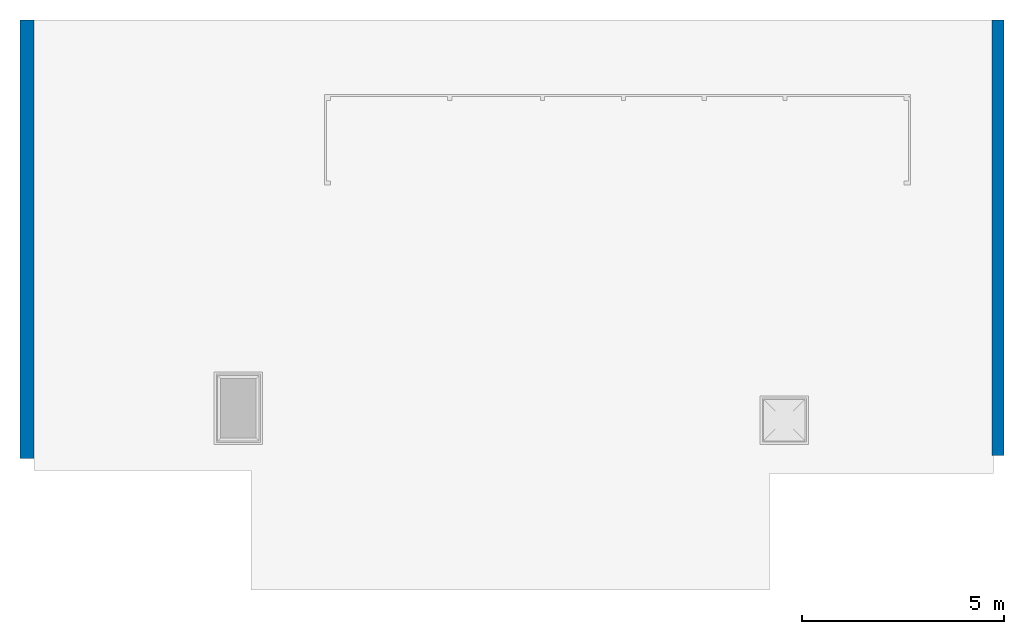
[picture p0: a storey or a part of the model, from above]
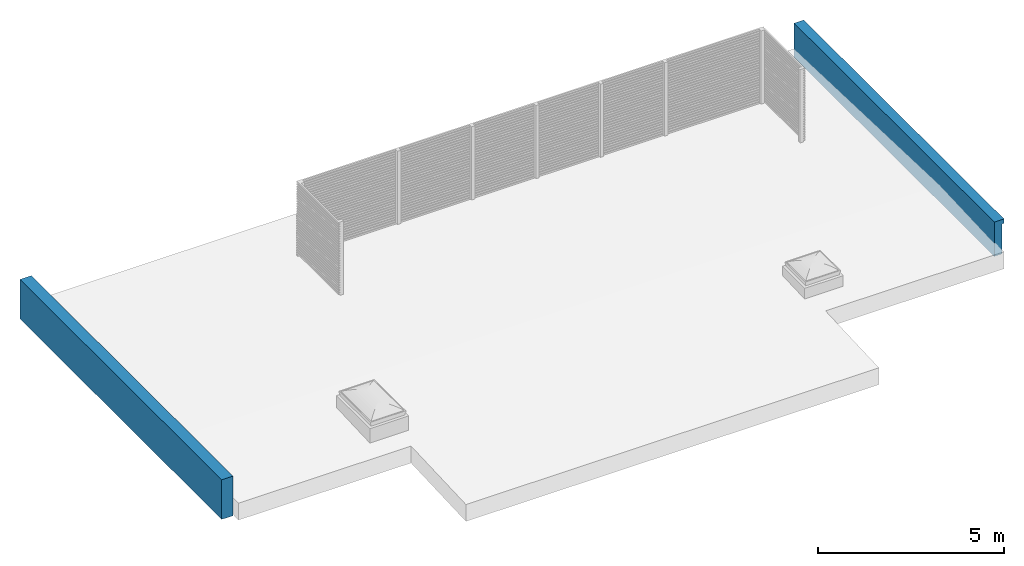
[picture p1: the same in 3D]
Properties of the parts of a building model (IFC2X3), part 1 of 7

# File
Description: ViewDefinition [CoordinationView_V2.0]
File name: 19043
Time: 2021-08-16T15:12:21
Written by: The EXPRESS Data Manager Version 5.02.0100.07 : 28 Aug 2013
Made in: 20190808_0900(x64) - Exporter 19.3.0.0 - Alternate UI 19.3.0.0
Comment: STEP Physical File produced by: The EXPRESS Data Manager Version 5.02.0100.07 : 28 Aug 2013 * Module: EDMstepFileFactory/EDMstandAlone * Creation date: Mon Aug 16 15:12:21 2021 * Host: SA-2 * Database: C:\Users\Kasutaja\AppData\Local\Temp\{7F7ABF4B-EC79-415C-8A1B-BE8ADDE48ED6}\ifc * Database version: 5507 * Database creation date: Mon Aug 16 15:08:34 2021 * Schema: IFC2X3 * Model: DataRepository.ifc * Model creation date: Mon Aug 16 15:08:34 2021 * Header model: DataRepository.ifc_HeaderModel * Header model creation date: Mon Aug 16 15:08:34 2021 * EDMuser: sdai-user * EDMgroup: sdai-group * License ID and type: 5605 : Permanent license. Expiry date: * EDMstepFileFactory options: 020000

# IfcProject, 19043
LongName: Jõe tn 8 ühiselamu rekonstrueerimine; Phase: PP

# IfcSite, Default
RefLatitude: 58, 5, 40, 850830; RefLongitude: 27, 26, 59, 528961; RefElevation: 0 mm
Pset_ProductRequirements - Category: Project Information

# IfcBuilding, SMA ARH
LongName: SMA ARH
Pset_BuildingCommon - NumberOfStoreys: 9
Pset_ProductRequirements - Category: Project Information

# IfcBuildingStorey: Level:Level head 1 (9)
In: SMA ARH
Pset_ProductRequirements - Category: Levels
Name | LongName = Pset_AirSideSystemInformation, Name = Pset_ProductRequirements, Name | Elevation (mm)
0 Kelder | 0 Kelder | -1400
1 Korrus | 1 Korrus | 0
1 Korrus A | 1 Korrus A | 1400
2 Korrus | 2 Korrus | 2800
2 Korrus A | 2 Korrus A | 4200
3 korrus | 3 korrus | 5600
3 Korrus A | 3 Korrus A | 7000
Katus | Katus | 8100
Katus A | Katus A | 9700

# IfcSpace: Dušširuum 008:1007028, 008
In: 0 Kelder
LongName: Dušširuum; InteriorOrExteriorSpace: INTERNAL
Pset_AirSideSystemInformation - Name: Dušširuum; sets with these values: 2
Pset_SpaceCommon - Reference: Dušširuum 008; FloorCovering: P3/P4; WallCovering: S3.1/S3.2; CeilingCovering: L5

# IfcSpace: Dušširuum 101E:976458, 101E
In: 1 Korrus
LongName: Dušširuum; InteriorOrExteriorSpace: INTERNAL
Pset_AirSideSystemInformation - Name: Dušširuum; sets with these values: 2
Pset_SpaceCommon - Reference: Dušširuum 101E; FloorCovering: P4; WallCovering: S4.1/S4.2; CeilingCovering: L2

# IfcSpace: Dušširuum 102D:975544, 102D
In: 1 Korrus A
LongName: Dušširuum; InteriorOrExteriorSpace: INTERNAL
Pset_AirSideSystemInformation - Name: Dušširuum; sets with these values: 2
Pset_SpaceCommon - Reference: Dušširuum 102D; FloorCovering: P3/P4; WallCovering: S3.1/S3.2; CeilingCovering: L2

# IfcSpace: Dušširuum 103C:975547, 103C
In: 1 Korrus A
LongName: Dušširuum; InteriorOrExteriorSpace: INTERNAL
Pset_AirSideSystemInformation - Name: Dušširuum; sets with these values: 2
Pset_SpaceCommon - Reference: Dušširuum 103C; FloorCovering: P3/P4; WallCovering: S3.1/S3.2; CeilingCovering: L2

# IfcSpace: Dušširuum 104D:975531, 104D
In: 1 Korrus A
LongName: Dušširuum; InteriorOrExteriorSpace: INTERNAL
Pset_AirSideSystemInformation - Name: Dušširuum; sets with these values: 2
Pset_SpaceCommon - Reference: Dušširuum 104D; FloorCovering: P3/P4; WallCovering: S3.1/S3.2; CeilingCovering: L2

# IfcSpace: Dušširuum 105C:975528, 105C
In: 1 Korrus A
LongName: Dušširuum; InteriorOrExteriorSpace: INTERNAL
Pset_AirSideSystemInformation - Name: Dušširuum; sets with these values: 2
Pset_SpaceCommon - Reference: Dušširuum 105C; FloorCovering: P3/P4; WallCovering: S3.1/S3.2; CeilingCovering: L2

# IfcSpace: Dušširuum 106D:976437, 106D
In: 1 Korrus A
LongName: Dušširuum; InteriorOrExteriorSpace: INTERNAL
Pset_AirSideSystemInformation - Name: Dušširuum; sets with these values: 2
Pset_SpaceCommon - Reference: Dušširuum 106D; FloorCovering: P3/P4; WallCovering: S3.1/S3.2; CeilingCovering: L2

# IfcSpace: Dušširuum 108G:990469, 108G
In: 1 Korrus
LongName: Dušširuum; InteriorOrExteriorSpace: INTERNAL
Pset_AirSideSystemInformation - Name: Dušširuum; sets with these values: 2
Pset_SpaceCommon - Reference: Dušširuum 108G; FloorCovering: P3; WallCovering: S3.1/S3.2; CeilingCovering: L2

# IfcSpace: Dušširuum 201F:984375, 201F
In: 2 Korrus
LongName: Dušširuum; InteriorOrExteriorSpace: INTERNAL
Pset_AirSideSystemInformation - Name: Dušširuum; sets with these values: 2
Pset_SpaceCommon - Reference: Dušširuum 201F; FloorCovering: P3; WallCovering: S3.1/S3.2; CeilingCovering: L2

# IfcSpace: Dušširuum 202D:977817, 202D
In: 2 Korrus A
LongName: Dušširuum; InteriorOrExteriorSpace: INTERNAL
Pset_AirSideSystemInformation - Name: Dušširuum; sets with these values: 2
Pset_SpaceCommon - Reference: Dušširuum 202D; FloorCovering: P3/P4; WallCovering: S3.1/S3.2; CeilingCovering: L2

# IfcSpace: Dušširuum 203C:977799, 203C
In: 2 Korrus A
LongName: Dušširuum; InteriorOrExteriorSpace: INTERNAL
Pset_AirSideSystemInformation - Name: Dušširuum; sets with these values: 2
Pset_SpaceCommon - Reference: Dušširuum 203C; FloorCovering: P3/P4; WallCovering: S3.1/S3.2; CeilingCovering: L2

# IfcSpace: Dušširuum 204D:977787, 204D
In: 2 Korrus A
LongName: Dušširuum; InteriorOrExteriorSpace: INTERNAL
Pset_AirSideSystemInformation - Name: Dušširuum; sets with these values: 2
Pset_SpaceCommon - Reference: Dušširuum 204D; FloorCovering: P3/P4; WallCovering: S3.1/S3.2; CeilingCovering: L2

# IfcSpace: Dušširuum 205C:977769, 205C
In: 2 Korrus A
LongName: Dušširuum; InteriorOrExteriorSpace: INTERNAL
Pset_AirSideSystemInformation - Name: Dušširuum; sets with these values: 2
Pset_SpaceCommon - Reference: Dušširuum 205C; FloorCovering: P3/P4; WallCovering: S3.1/S3.2; CeilingCovering: L2

# IfcSpace: Dušširuum 206D:977850, 206D
In: 2 Korrus A
LongName: Dušširuum; InteriorOrExteriorSpace: INTERNAL
Pset_AirSideSystemInformation - Name: Dušširuum; sets with these values: 2
Pset_SpaceCommon - Reference: Dušširuum 206D; FloorCovering: P3/P4; WallCovering: S3.1/S3.2; CeilingCovering: L2

# IfcSpace: Dušširuum 208E:977689, 208E
In: 2 Korrus
LongName: Dušširuum; InteriorOrExteriorSpace: INTERNAL
Pset_AirSideSystemInformation - Name: Dušširuum; sets with these values: 2
Pset_SpaceCommon - Reference: Dušširuum 208E; FloorCovering: P3/P4; WallCovering: S3.1/S3.2; CeilingCovering: L2

# IfcSpace: Dušširuum 301E:985822, 301E
In: 3 korrus
LongName: Dušširuum; InteriorOrExteriorSpace: INTERNAL
Pset_AirSideSystemInformation - Name: Dušširuum; sets with these values: 2
Pset_SpaceCommon - Reference: Dušširuum 301E; FloorCovering: P3/P4; WallCovering: S3.1/S3.2; CeilingCovering: L2

# IfcSpace: Dušširuum 302D:985771, 302D
In: 3 Korrus A
LongName: Dušširuum; InteriorOrExteriorSpace: INTERNAL
Pset_AirSideSystemInformation - Name: Dušširuum; sets with these values: 2
Pset_SpaceCommon - Reference: Dušširuum 302D; FloorCovering: P3/P4; WallCovering: S3.1/S3.2; CeilingCovering: L2

# IfcSpace: Dušširuum 303C:985774, 303C
In: 3 Korrus A
LongName: Dušširuum; InteriorOrExteriorSpace: INTERNAL
Pset_AirSideSystemInformation - Name: Dušširuum; sets with these values: 2
Pset_SpaceCommon - Reference: Dušširuum 303C; FloorCovering: P3/P4; WallCovering: S3.1/S3.2; CeilingCovering: L2

# IfcSpace: Dušširuum 304D:985753, 304D
In: 3 Korrus A
LongName: Dušširuum; InteriorOrExteriorSpace: INTERNAL
Pset_AirSideSystemInformation - Name: Dušširuum; sets with these values: 2
Pset_SpaceCommon - Reference: Dušširuum 304D; FloorCovering: P3/P4; WallCovering: S3.1/S3.2; CeilingCovering: L2

# IfcSpace: Dušširuum 305C:985750, 305C
In: 3 Korrus A
LongName: Dušširuum; InteriorOrExteriorSpace: INTERNAL
Pset_AirSideSystemInformation - Name: Dušširuum; sets with these values: 2
Pset_SpaceCommon - Reference: Dušširuum 305C; FloorCovering: P3/P4; WallCovering: S3.1/S3.2; CeilingCovering: L2

# IfcSpace: Dušširuum 306D:985798, 306D
In: 3 Korrus A
LongName: Dušširuum; InteriorOrExteriorSpace: INTERNAL
Pset_AirSideSystemInformation - Name: Dušširuum; sets with these values: 2
Pset_SpaceCommon - Reference: Dušširuum 306D; FloorCovering: P3/P4; WallCovering: S3.1/S3.2; CeilingCovering: L2

# IfcSpace: Dušširuum 308E:985433, 308E
In: 3 korrus
LongName: Dušširuum; InteriorOrExteriorSpace: INTERNAL
Pset_AirSideSystemInformation - Name: Dušširuum; sets with these values: 2
Pset_SpaceCommon - Reference: Dušširuum 308E; FloorCovering: P3/P4; WallCovering: S3.1/S3.2; CeilingCovering: L2

# IfcSpace: El. kilp 014:2405710, 014
In: 0 Kelder
LongName: El. kilp; InteriorOrExteriorSpace: INTERNAL
Pset_AirSideSystemInformation - Name: El. kilp; sets with these values: 2
Pset_SpaceCommon - Reference: El. kilp 014; FloorCovering: P2; WallCovering: S1.1; CeilingCovering: L1.1

# IfcSpace: Esik 101:976452, 101
In: 1 Korrus
LongName: Esik; InteriorOrExteriorSpace: INTERNAL
Pset_AirSideSystemInformation - Name: Esik; sets with these values: 2
Pset_SpaceCommon - Reference: Esik 101; FloorCovering: P3; WallCovering: S1.1; CeilingCovering: L1.1

# IfcSpace: Esik 102:975541, 102
In: 1 Korrus A
LongName: Esik; InteriorOrExteriorSpace: INTERNAL
Pset_AirSideSystemInformation - Name: Esik; sets with these values: 2
Pset_SpaceCommon - Reference: Esik 102; FloorCovering: P3; WallCovering: S1.1; CeilingCovering: L2

# IfcSpace: Esik 103:1088645, 103
In: 1 Korrus A
LongName: Esik; InteriorOrExteriorSpace: INTERNAL
Pset_AirSideSystemInformation - Name: Esik; sets with these values: 2
Pset_SpaceCommon - Reference: Esik 103; FloorCovering: P3; WallCovering: S1.1; CeilingCovering: L2

# IfcSpace: Esik 104:1088635, 104
In: 1 Korrus A
LongName: Esik; InteriorOrExteriorSpace: INTERNAL
Pset_AirSideSystemInformation - Name: Esik; sets with these values: 2
Pset_SpaceCommon - Reference: Esik 104; FloorCovering: P3; WallCovering: S1.1; CeilingCovering: L2

# IfcSpace: Esik 105:975525, 105
In: 1 Korrus A
LongName: Esik; InteriorOrExteriorSpace: INTERNAL
Pset_AirSideSystemInformation - Name: Esik; sets with these values: 2
Pset_SpaceCommon - Reference: Esik 105; FloorCovering: P3; WallCovering: S1.1; CeilingCovering: L2

# IfcSpace: Esik 106:976431, 106
In: 1 Korrus A
LongName: Esik; InteriorOrExteriorSpace: INTERNAL
Pset_AirSideSystemInformation - Name: Esik; sets with these values: 2
Pset_SpaceCommon - Reference: Esik 106; FloorCovering: P3; WallCovering: S1.1; CeilingCovering: L2

# IfcSpace: Esik 108:883815, 108
In: 1 Korrus
LongName: Esik; InteriorOrExteriorSpace: INTERNAL
Pset_AirSideSystemInformation - Name: Esik; sets with these values: 2
Pset_SpaceCommon - Reference: Esik 108; FloorCovering: P1; WallCovering: S1.1; CeilingCovering: L1.1

# IfcSpace: Esik 201:984372, 201
In: 2 Korrus
LongName: Esik; InteriorOrExteriorSpace: INTERNAL
Pset_AirSideSystemInformation - Name: Esik; sets with these values: 2
Pset_SpaceCommon - Reference: Esik 201; FloorCovering: P3; WallCovering: S1.1; CeilingCovering: L1.1/L3

# IfcSpace: Esik 202:977811, 202
In: 2 Korrus A
LongName: Esik; InteriorOrExteriorSpace: INTERNAL
Pset_AirSideSystemInformation - Name: Esik; sets with these values: 2
Pset_SpaceCommon - Reference: Esik 202; FloorCovering: P3; WallCovering: S1.1; CeilingCovering: L2

# IfcSpace: Esik 203:977796, 203
In: 2 Korrus A
LongName: Esik; InteriorOrExteriorSpace: INTERNAL
Pset_AirSideSystemInformation - Name: Esik; sets with these values: 2
Pset_SpaceCommon - Reference: Esik 203; FloorCovering: P3; WallCovering: S1.1; CeilingCovering: L2

# IfcSpace: Esik 204:977781, 204
In: 2 Korrus A
LongName: Esik; InteriorOrExteriorSpace: INTERNAL
Pset_AirSideSystemInformation - Name: Esik; sets with these values: 2
Pset_SpaceCommon - Reference: Esik 204; FloorCovering: P3; WallCovering: S1.1; CeilingCovering: L2

# IfcSpace: Esik 205:977766, 205
In: 2 Korrus A
LongName: Esik; InteriorOrExteriorSpace: INTERNAL
Pset_AirSideSystemInformation - Name: Esik; sets with these values: 2
Pset_SpaceCommon - Reference: Esik 205; FloorCovering: P3; WallCovering: S1.1; CeilingCovering: L2

# IfcSpace: Esik 206:977844, 206
In: 2 Korrus A
LongName: Esik; InteriorOrExteriorSpace: INTERNAL
Pset_AirSideSystemInformation - Name: Esik; sets with these values: 2
Pset_SpaceCommon - Reference: Esik 206; FloorCovering: P3/P4; WallCovering: S1.1; CeilingCovering: L2

# IfcSpace: Esik 208:977576, 208
In: 2 Korrus
LongName: Esik; InteriorOrExteriorSpace: INTERNAL
Pset_AirSideSystemInformation - Name: Esik; sets with these values: 2
Pset_SpaceCommon - Reference: Esik 208; FloorCovering: P3; WallCovering: S1.1; CeilingCovering: L1.1

# IfcSpace: Esik 301:985816, 301
In: 3 korrus
LongName: Esik; InteriorOrExteriorSpace: INTERNAL
Pset_AirSideSystemInformation - Name: Esik; sets with these values: 2
Pset_SpaceCommon - Reference: Esik 301; FloorCovering: P3; WallCovering: S1.1; CeilingCovering: L1.1

# IfcSpace: Esik 302:985768, 302
In: 3 Korrus A
LongName: Esik; InteriorOrExteriorSpace: INTERNAL
Pset_AirSideSystemInformation - Name: Esik; sets with these values: 2
Pset_SpaceCommon - Reference: Esik 302; FloorCovering: P3; WallCovering: S1.1; CeilingCovering: L2

# IfcSpace: Esik 303:1125635, 303
In: 3 Korrus A
LongName: Esik; InteriorOrExteriorSpace: INTERNAL
Pset_AirSideSystemInformation - Name: Esik; sets with these values: 2
Pset_SpaceCommon - Reference: Esik 303; FloorCovering: P3; WallCovering: S1.1; CeilingCovering: L2

# IfcSpace: Esik 304:1125644, 304
In: 3 Korrus A
LongName: Esik; InteriorOrExteriorSpace: INTERNAL
Pset_AirSideSystemInformation - Name: Esik; sets with these values: 2
Pset_SpaceCommon - Reference: Esik 304; FloorCovering: P3; WallCovering: S1.1; CeilingCovering: L2

# IfcSpace: Esik 305:985747, 305
In: 3 Korrus A
LongName: Esik; InteriorOrExteriorSpace: INTERNAL
Pset_AirSideSystemInformation - Name: Esik; sets with these values: 2
Pset_SpaceCommon - Reference: Esik 305; FloorCovering: P3; WallCovering: S1.1; CeilingCovering: L2

# IfcSpace: Esik 306:985792, 306
In: 3 Korrus A
LongName: Esik; InteriorOrExteriorSpace: INTERNAL
Pset_AirSideSystemInformation - Name: Esik; sets with these values: 2
Pset_SpaceCommon - Reference: Esik 306; FloorCovering: P3; WallCovering: S1.1; CeilingCovering: L2

# IfcSpace: Esik 308:985427, 308
In: 3 korrus
LongName: Esik; InteriorOrExteriorSpace: INTERNAL
Pset_AirSideSystemInformation - Name: Esik; sets with these values: 2
Pset_SpaceCommon - Reference: Esik 308; FloorCovering: P3; WallCovering: S1.1; CeilingCovering: L2

# IfcSpace: Hoiuruum 006:1007034, 006
In: 0 Kelder
LongName: Hoiuruum; InteriorOrExteriorSpace: INTERNAL
Pset_AirSideSystemInformation - Name: Hoiuruum; sets with these values: 2
Pset_SpaceCommon - Reference: Hoiuruum 006; FloorCovering: P6; WallCovering: S1.1; CeilingCovering: L1.1

# IfcSpace: Hoiuruum 108B:905546, 108B
In: 1 Korrus
LongName: Hoiuruum; InteriorOrExteriorSpace: INTERNAL
Pset_AirSideSystemInformation - Name: Hoiuruum; sets with these values: 2
Pset_SpaceCommon - Reference: Hoiuruum 108B; FloorCovering: P1; WallCovering: S1.1; CeilingCovering: L1.1

# IfcSpace: Hoiuruum 108C:905543, 108C
In: 1 Korrus
LongName: Hoiuruum; InteriorOrExteriorSpace: INTERNAL
Pset_AirSideSystemInformation - Name: Hoiuruum; sets with these values: 2
Pset_SpaceCommon - Reference: Hoiuruum 108C; FloorCovering: P7; WallCovering: S1.1; CeilingCovering: L1.1

# IfcSpace: Jõusaal 005:1007037, 005
In: 0 Kelder
LongName: Jõusaal; InteriorOrExteriorSpace: INTERNAL
Pset_AirSideSystemInformation - Name: Jõusaal; sets with these values: 2
Pset_SpaceCommon - Reference: Jõusaal 005; FloorCovering: P5; WallCovering: S1.2; CeilingCovering: L1.1

# IfcSpace: Koridor K001:1007049, K001
In: 0 Kelder
LongName: Koridor; InteriorOrExteriorSpace: INTERNAL
Pset_AirSideSystemInformation - Name: Koridor; sets with these values: 2
Pset_SpaceCommon - Reference: Koridor K001; FloorCovering: P1; WallCovering: S1.1; CeilingCovering: L1.1

# IfcSpace: Koridor K101:975522, K101
In: 1 Korrus A
LongName: Koridor; InteriorOrExteriorSpace: INTERNAL
Pset_AirSideSystemInformation - Name: Koridor; sets with these values: 2
Pset_SpaceCommon - Reference: Koridor K101; FloorCovering: P1; WallCovering: S1.1; CeilingCovering: L1.1

# IfcSpace: Koridor K201:977762, K201
In: 2 Korrus A
LongName: Koridor; InteriorOrExteriorSpace: INTERNAL
Pset_AirSideSystemInformation - Name: Koridor; sets with these values: 2
Pset_SpaceCommon - Reference: Koridor K201; FloorCovering: P1; WallCovering: S1.1; CeilingCovering: L1.1

# IfcSpace: Koridor K301:985743, K301
In: 3 Korrus A
LongName: Koridor; InteriorOrExteriorSpace: INTERNAL
Pset_AirSideSystemInformation - Name: Koridor; sets with these values: 2
Pset_SpaceCommon - Reference: Koridor K301; FloorCovering: P1; WallCovering: S1.1; CeilingCovering: L1.1

# IfcSpace: Koristusvahendid 108A:905549, 108A
In: 1 Korrus
LongName: Koristusvahendid; InteriorOrExteriorSpace: INTERNAL
Pset_AirSideSystemInformation - Name: Koristusvahendid; sets with these values: 2
Pset_SpaceCommon - Reference: Koristusvahendid 108A; FloorCovering: P4; WallCovering: S1.1; CeilingCovering: L1.1

# IfcSpace: Korrapidaja 109:976467, 109
In: 1 Korrus
LongName: Korrapidaja; InteriorOrExteriorSpace: INTERNAL
Pset_AirSideSystemInformation - Name: Korrapidaja; sets with these values: 2
Pset_SpaceCommon - Reference: Korrapidaja 109; FloorCovering: P7; WallCovering: S1.1; CeilingCovering: L1.1/L1.2/L3

# IfcSpace: Kuivatus ruum 002:1007046, 002
In: 0 Kelder
LongName: Kuivatus ruum; InteriorOrExteriorSpace: INTERNAL
Pset_AirSideSystemInformation - Name: Kuivatus ruum; sets with these values: 2
Pset_SpaceCommon - Reference: Kuivatus ruum 002; FloorCovering: P9; WallCovering: S2; CeilingCovering: L1.1

# IfcSpace: Kuivatus ruum 012:1007052, 012
In: 0 Kelder
LongName: Kuivatus ruum; InteriorOrExteriorSpace: INTERNAL
Pset_AirSideSystemInformation - Name: Kuivatus ruum; sets with these values: 2
Pset_SpaceCommon - Reference: Kuivatus ruum 012; FloorCovering: P9; WallCovering: S2; CeilingCovering: L1.1

# IfcSpace: Köök 107:976428, 107
In: 1 Korrus A
LongName: Köök; InteriorOrExteriorSpace: INTERNAL
Pset_AirSideSystemInformation - Name: Köök; sets with these values: 2
Pset_SpaceCommon - Reference: Köök 107; FloorCovering: P3; WallCovering: S1.1; CeilingCovering: L1.1

# IfcSpace: Köök 207:977829, 207
In: 2 Korrus A
LongName: Köök; InteriorOrExteriorSpace: INTERNAL
Pset_AirSideSystemInformation - Name: Köök; sets with these values: 2
Pset_SpaceCommon - Reference: Köök 207; FloorCovering: P3; WallCovering: S1.1; CeilingCovering: L1.1

# IfcSpace: Köök 307:985789, 307
In: 3 Korrus A
LongName: Köök; InteriorOrExteriorSpace: INTERNAL
Pset_AirSideSystemInformation - Name: Köök; sets with these values: 2
Pset_SpaceCommon - Reference: Köök 307; FloorCovering: P3; WallCovering: S1.1; CeilingCovering: L1.1

# IfcSpace: Must pesu 108D:905540, 108D
In: 1 Korrus
LongName: Must pesu; InteriorOrExteriorSpace: INTERNAL
Pset_AirSideSystemInformation - Name: Must pesu; sets with these values: 2
Pset_SpaceCommon - Reference: Must pesu 108D; FloorCovering: P1; WallCovering: S1.1; CeilingCovering: L1.1

# IfcSpace: Pesumasinad 010:1007022, 010
In: 0 Kelder
LongName: Pesumasinad; InteriorOrExteriorSpace: INTERNAL
Pset_AirSideSystemInformation - Name: Pesumasinad; sets with these values: 2
Pset_SpaceCommon - Reference: Pesumasinad 010; FloorCovering: P9; WallCovering: S2; CeilingCovering: L1.1

# IfcSpace: Puhas pesu 108E:990472, 108E
In: 1 Korrus
LongName: Puhas pesu; InteriorOrExteriorSpace: INTERNAL
Pset_AirSideSystemInformation - Name: Puhas pesu; sets with these values: 2
Pset_SpaceCommon - Reference: Puhas pesu 108E; FloorCovering: P1; WallCovering: S1.1; CeilingCovering: L1.1

# IfcSpace: Puhkeruum 110:976470, 110
In: 1 Korrus
LongName: Puhkeruum; InteriorOrExteriorSpace: INTERNAL
Pset_AirSideSystemInformation - Name: Puhkeruum; sets with these values: 2
Pset_SpaceCommon - Reference: Puhkeruum 110; FloorCovering: P7; WallCovering: S1.1; CeilingCovering: L1.1/L1.2/L3

# IfcSpace: Riietusruum 007:1007025, 007
In: 0 Kelder
LongName: Riietusruum; InteriorOrExteriorSpace: INTERNAL
Pset_AirSideSystemInformation - Name: Riietusruum; sets with these values: 2
Pset_SpaceCommon - Reference: Riietusruum 007; FloorCovering: P3; WallCovering: S1.1; CeilingCovering: L2

# IfcSpace: Saal 001:1007058, 001
In: 0 Kelder
LongName: Saal; InteriorOrExteriorSpace: INTERNAL
Pset_AirSideSystemInformation - Name: Saal; sets with these values: 2
Pset_SpaceCommon - Reference: Saal 001; FloorCovering: P7; WallCovering: S1.3; CeilingCovering: L1.1

# IfcSpace: Saun 009:1007031, 009
In: 0 Kelder
LongName: Saun; InteriorOrExteriorSpace: INTERNAL
Pset_AirSideSystemInformation - Name: Saun; sets with these values: 2
Pset_SpaceCommon - Reference: Saun 009; FloorCovering: P4; WallCovering: S5; CeilingCovering: L4

# IfcSpace: Tehniline ruum 003:1007043, 003
In: 0 Kelder
LongName: Tehniline ruum; InteriorOrExteriorSpace: INTERNAL
Pset_AirSideSystemInformation - Name: Tehniline ruum; sets with these values: 2
Pset_SpaceCommon - Reference: Tehniline ruum 003; FloorCovering: P6; WallCovering: S1.1; CeilingCovering: L1.1

# IfcSpace: Trepikoda T001:1007061, T001
In: 0 Kelder
LongName: Trepikoda; InteriorOrExteriorSpace: INTERNAL
Pset_AirSideSystemInformation - Name: Trepikoda; sets with these values: 2
Pset_SpaceCommon - Reference: Trepikoda T001; FloorCovering: P2; WallCovering: S1.1/S1.2; CeilingCovering: L1.1

# IfcSpace: Trepikoda T002:1007055, T002
In: 0 Kelder
LongName: Trepikoda; InteriorOrExteriorSpace: INTERNAL
Pset_AirSideSystemInformation - Name: Trepikoda; sets with these values: 2
Pset_SpaceCommon - Reference: Trepikoda T002; FloorCovering: P2; WallCovering: S1.1/S1.2; CeilingCovering: L1.1

# IfcSpace: Trepikoda T102:976449, T102
In: 1 Korrus
LongName: Trepikoda; InteriorOrExteriorSpace: INTERNAL
Pset_AirSideSystemInformation - Name: Trepikoda; sets with these values: 2
Pset_SpaceCommon - Reference: Trepikoda T102; FloorCovering: P2; WallCovering: S1.1/S1.2; CeilingCovering: L1.1

# IfcSpace: Trepikoda T103:975487, T103
In: 1 Korrus
LongName: Trepikoda; InteriorOrExteriorSpace: INTERNAL
Pset_AirSideSystemInformation - Name: Trepikoda; sets with these values: 2
Pset_SpaceCommon - Reference: Trepikoda T103; FloorCovering: P2; WallCovering: S1.1/S1.2; CeilingCovering: L1.1

# IfcSpace: Trepikoda T201:984233, T201
In: 2 Korrus
LongName: Trepikoda; InteriorOrExteriorSpace: INTERNAL
Pset_AirSideSystemInformation - Name: Trepikoda; sets with these values: 2
Pset_SpaceCommon - Reference: Trepikoda T201; FloorCovering: P2; WallCovering: S1.1/S1.2; CeilingCovering: L1.1

# IfcSpace: Trepikoda T202:977453, T202
In: 2 Korrus
LongName: Trepikoda; InteriorOrExteriorSpace: INTERNAL
Pset_AirSideSystemInformation - Name: Trepikoda; sets with these values: 2
Pset_SpaceCommon - Reference: Trepikoda T202; FloorCovering: P2; WallCovering: S1.1/S1.2; CeilingCovering: L1.1

# IfcSpace: Trepikoda T301:985810, T301
In: 3 korrus
LongName: Trepikoda; InteriorOrExteriorSpace: INTERNAL
Pset_AirSideSystemInformation - Name: Trepikoda; sets with these values: 2
Pset_SpaceCommon - Reference: Trepikoda T301; FloorCovering: P2; WallCovering: S1.1/S1.2; CeilingCovering: L1.1

# IfcSpace: Trepikoda T302:985419, T302
In: 3 korrus
LongName: Trepikoda; InteriorOrExteriorSpace: INTERNAL
Pset_AirSideSystemInformation - Name: Trepikoda; sets with these values: 2
Pset_SpaceCommon - Reference: Trepikoda T302; FloorCovering: P2; WallCovering: S1.1/S1.2; CeilingCovering: L1.1

# IfcSpace: Tuba 101A:976461, 101A
In: 1 Korrus
LongName: Tuba; InteriorOrExteriorSpace: INTERNAL
Pset_AirSideSystemInformation - Name: Tuba; sets with these values: 2
Pset_SpaceCommon - Reference: Tuba 101A; FloorCovering: P7; WallCovering: S1.1; CeilingCovering: L1.1/L1.2

# IfcSpace: Tuba 101B:976464, 101B
In: 1 Korrus
LongName: Tuba; InteriorOrExteriorSpace: INTERNAL
Pset_AirSideSystemInformation - Name: Tuba; sets with these values: 2
Pset_SpaceCommon - Reference: Tuba 101B; FloorCovering: P7; WallCovering: S1.1; CeilingCovering: L1.1/L1.2

# IfcSpace: Tuba 102A:975556, 102A
In: 1 Korrus A
LongName: Tuba; InteriorOrExteriorSpace: INTERNAL
Pset_AirSideSystemInformation - Name: Tuba; sets with these values: 2
Pset_SpaceCommon - Reference: Tuba 102A; FloorCovering: P7; WallCovering: S1.1/S1.4; CeilingCovering: L1.1/L1.2/L3

# IfcSpace: Tuba 102B:975559, 102B
In: 1 Korrus A
LongName: Tuba; InteriorOrExteriorSpace: INTERNAL
Pset_AirSideSystemInformation - Name: Tuba; sets with these values: 2
Pset_SpaceCommon - Reference: Tuba 102B; FloorCovering: P7; WallCovering: S1.1/S1.4; CeilingCovering: L1.1/L1.2/L3

# IfcSpace: Tuba 103A:975550, 103A
In: 1 Korrus A
LongName: Tuba; InteriorOrExteriorSpace: INTERNAL
Pset_AirSideSystemInformation - Name: Tuba; sets with these values: 2
Pset_SpaceCommon - Reference: Tuba 103A; FloorCovering: P7; WallCovering: S1.1/S1.4; CeilingCovering: L1.1/L1.2/L3

# IfcSpace: Tuba 103B:975553, 103B
In: 1 Korrus A
LongName: Tuba; InteriorOrExteriorSpace: INTERNAL
Pset_AirSideSystemInformation - Name: Tuba; sets with these values: 2
Pset_SpaceCommon - Reference: Tuba 103B; FloorCovering: P7; WallCovering: S1.1/S1.4; CeilingCovering: L1.1/L1.2/L3

# IfcSpace: Tuba 104A:961784, 104A
In: 1 Korrus A
LongName: Tuba; InteriorOrExteriorSpace: INTERNAL
Pset_AirSideSystemInformation - Name: Tuba; sets with these values: 2
Pset_SpaceCommon - Reference: Tuba 104A; FloorCovering: P7; WallCovering: S1.1/S1.4; CeilingCovering: L1.1/L1.2/L3

# IfcSpace: Tuba 104B:961787, 104B
In: 1 Korrus A
LongName: Tuba; InteriorOrExteriorSpace: INTERNAL
Pset_AirSideSystemInformation - Name: Tuba; sets with these values: 2
Pset_SpaceCommon - Reference: Tuba 104B; FloorCovering: P7; WallCovering: S1.1/S1.4; CeilingCovering: L1.1/L1.2/L3

# IfcSpace: Tuba 105A:959096, 105A
In: 1 Korrus A
LongName: Tuba; InteriorOrExteriorSpace: INTERNAL
Pset_AirSideSystemInformation - Name: Tuba; sets with these values: 2
Pset_SpaceCommon - Reference: Tuba 105A; FloorCovering: P7; WallCovering: S1.1/S1.4; CeilingCovering: L1.1/L1.2/L3

# IfcSpace: Tuba 105B:959349, 105B
In: 1 Korrus A
LongName: Tuba; InteriorOrExteriorSpace: INTERNAL
Pset_AirSideSystemInformation - Name: Tuba; sets with these values: 2
Pset_SpaceCommon - Reference: Tuba 105B; FloorCovering: P7; WallCovering: S1.1/S1.4; CeilingCovering: L1.1/L1.2/L3

# IfcSpace: Tuba 106A:976440, 106A
In: 1 Korrus A
LongName: Tuba; InteriorOrExteriorSpace: INTERNAL
Pset_AirSideSystemInformation - Name: Tuba; sets with these values: 2
Pset_SpaceCommon - Reference: Tuba 106A; FloorCovering: P7; WallCovering: S1.1/S1.4; CeilingCovering: L1.1/L1.2/L3

# IfcSpace: Tuba 106B:976443, 106B
In: 1 Korrus A
LongName: Tuba; InteriorOrExteriorSpace: INTERNAL
Pset_AirSideSystemInformation - Name: Tuba; sets with these values: 2
Pset_SpaceCommon - Reference: Tuba 106B; FloorCovering: P7; WallCovering: S1.1/S1.4; CeilingCovering: L1.1/L1.2/L3

# IfcSpace: Tuba 201A:984381, 201A
In: 2 Korrus
LongName: Tuba; InteriorOrExteriorSpace: INTERNAL
Pset_AirSideSystemInformation - Name: Tuba; sets with these values: 2
Pset_SpaceCommon - Reference: Tuba 201A; FloorCovering: P7; WallCovering: S1.1/S1.5; CeilingCovering: L1.1/L1.3/L3

# IfcSpace: Tuba 201B:984384, 201B
In: 2 Korrus
LongName: Tuba; InteriorOrExteriorSpace: INTERNAL
Pset_AirSideSystemInformation - Name: Tuba; sets with these values: 2
Pset_SpaceCommon - Reference: Tuba 201B; FloorCovering: P7; WallCovering: S1.1/S1.5; CeilingCovering: L1.1/L1.3/L3

# IfcSpace: Tuba 201C:984387, 201C
In: 2 Korrus
LongName: Tuba; InteriorOrExteriorSpace: INTERNAL
Pset_AirSideSystemInformation - Name: Tuba; sets with these values: 2
Pset_SpaceCommon - Reference: Tuba 201C; FloorCovering: P7; WallCovering: S1.1/S1.5; CeilingCovering: L1.1/L1.3/L3

# IfcSpace: Tuba 201D:984390, 201D
In: 2 Korrus
LongName: Tuba; InteriorOrExteriorSpace: INTERNAL
Pset_AirSideSystemInformation - Name: Tuba; sets with these values: 2
Pset_SpaceCommon - Reference: Tuba 201D; FloorCovering: P7; WallCovering: S1.1/S1.5; CeilingCovering: L1.1/L1.3/L3

# IfcSpace: Tuba 202A:977820, 202A
In: 2 Korrus A
LongName: Tuba; InteriorOrExteriorSpace: INTERNAL
Pset_AirSideSystemInformation - Name: Tuba; sets with these values: 2
Pset_SpaceCommon - Reference: Tuba 202A; FloorCovering: P7; WallCovering: S1.1/S1.5; CeilingCovering: L1.1/L1.3/L3

# IfcSpace: Tuba 202B:977823, 202B
In: 2 Korrus A
LongName: Tuba; InteriorOrExteriorSpace: INTERNAL
Pset_AirSideSystemInformation - Name: Tuba; sets with these values: 2
Pset_SpaceCommon - Reference: Tuba 202B; FloorCovering: P7; WallCovering: S1.1/S1.5; CeilingCovering: L1.1/L1.3/L3

# IfcSpace: Tuba 203A:977805, 203A
In: 2 Korrus A
LongName: Tuba; InteriorOrExteriorSpace: INTERNAL
Pset_AirSideSystemInformation - Name: Tuba; sets with these values: 2
Pset_SpaceCommon - Reference: Tuba 203A; FloorCovering: P7; WallCovering: S1.1/S1.5; CeilingCovering: L1.1/L1.3/L3

# IfcSpace: Tuba 203B:977808, 203B
In: 2 Korrus A
LongName: Tuba; InteriorOrExteriorSpace: INTERNAL
Pset_AirSideSystemInformation - Name: Tuba; sets with these values: 2
Pset_SpaceCommon - Reference: Tuba 203B; FloorCovering: P7; WallCovering: S1.1/S1.5; CeilingCovering: L1.1/L1.3/L3

# IfcSpace: Tuba 204A:977790, 204A
In: 2 Korrus A
LongName: Tuba; InteriorOrExteriorSpace: INTERNAL
Pset_AirSideSystemInformation - Name: Tuba; sets with these values: 2
Pset_SpaceCommon - Reference: Tuba 204A; FloorCovering: P7; WallCovering: S1.1/S1.5; CeilingCovering: L1.1/L1.3/L3

# IfcSpace: Tuba 204B:977793, 204B
In: 2 Korrus A
LongName: Tuba; InteriorOrExteriorSpace: INTERNAL
Pset_AirSideSystemInformation - Name: Tuba; sets with these values: 2
Pset_SpaceCommon - Reference: Tuba 204B; FloorCovering: P7; WallCovering: S1.1/S1.5; CeilingCovering: L1.1/L1.3/L3

# IfcSpace: Tuba 205A:977775, 205A
In: 2 Korrus A
LongName: Tuba; InteriorOrExteriorSpace: INTERNAL
Pset_AirSideSystemInformation - Name: Tuba; sets with these values: 2
Pset_SpaceCommon - Reference: Tuba 205A; FloorCovering: P7; WallCovering: S1.1/S1.4; CeilingCovering: L1.1/L1.3/L3

# IfcSpace: Tuba 205B:977778, 205B
In: 2 Korrus A
LongName: Tuba; InteriorOrExteriorSpace: INTERNAL
Pset_AirSideSystemInformation - Name: Tuba; sets with these values: 2
Pset_SpaceCommon - Reference: Tuba 205B; FloorCovering: P7; WallCovering: S1.1/S1.4; CeilingCovering: L1.1/L1.3/L3

# IfcSpace: Tuba 206A:977853, 206A
In: 2 Korrus A
LongName: Tuba; InteriorOrExteriorSpace: INTERNAL
Pset_AirSideSystemInformation - Name: Tuba; sets with these values: 2
Pset_SpaceCommon - Reference: Tuba 206A; FloorCovering: P7; WallCovering: S1.1/S1.5; CeilingCovering: L1.1/L1.3/L3

# IfcSpace: Tuba 206B:977856, 206B
In: 2 Korrus A
LongName: Tuba; InteriorOrExteriorSpace: INTERNAL
Pset_AirSideSystemInformation - Name: Tuba; sets with these values: 2
Pset_SpaceCommon - Reference: Tuba 206B; FloorCovering: P7; WallCovering: S1.1/S1.5; CeilingCovering: L1.1/L1.3/L3

# IfcSpace: Tuba 208A:977713, 208A
In: 2 Korrus
LongName: Tuba; InteriorOrExteriorSpace: INTERNAL
Pset_AirSideSystemInformation - Name: Tuba; sets with these values: 2
Pset_SpaceCommon - Reference: Tuba 208A; FloorCovering: P7; WallCovering: S1.1/S1.5; CeilingCovering: L1.1/L1.3/L3

# IfcSpace: Tuba 208B:977716, 208B
In: 2 Korrus
LongName: Tuba; InteriorOrExteriorSpace: INTERNAL
Pset_AirSideSystemInformation - Name: Tuba; sets with these values: 2
Pset_SpaceCommon - Reference: Tuba 208B; FloorCovering: P7; WallCovering: S1.1/S1.5; CeilingCovering: L1.1/L1.3/L3

# IfcSpace: Tuba 208C:977719, 208C
In: 2 Korrus
LongName: Tuba; InteriorOrExteriorSpace: INTERNAL
Pset_AirSideSystemInformation - Name: Tuba; sets with these values: 2
Pset_SpaceCommon - Reference: Tuba 208C; FloorCovering: P7; WallCovering: S1.1/S1.5; CeilingCovering: L1.1/L1.3/L3

# IfcSpace: Tuba 208D:977731, 208D
In: 2 Korrus
LongName: Tuba; InteriorOrExteriorSpace: INTERNAL
Pset_AirSideSystemInformation - Name: Tuba; sets with these values: 2
Pset_SpaceCommon - Reference: Tuba 208D; FloorCovering: P7; WallCovering: S1.1/S1.5; CeilingCovering: L1.1/L1.3/L3

# IfcSpace: Tuba 301A:985825, 301A
In: 3 korrus
LongName: Tuba; InteriorOrExteriorSpace: INTERNAL
Pset_AirSideSystemInformation - Name: Tuba; sets with these values: 2
Pset_SpaceCommon - Reference: Tuba 301A; FloorCovering: P7; WallCovering: S1.1/S1.6; CeilingCovering: L1.1/L1.4/L3

# IfcSpace: Tuba 301B:985828, 301B
In: 3 korrus
LongName: Tuba; InteriorOrExteriorSpace: INTERNAL
Pset_AirSideSystemInformation - Name: Tuba; sets with these values: 2
Pset_SpaceCommon - Reference: Tuba 301B; FloorCovering: P7; WallCovering: S1.1/S1.6; CeilingCovering: L1.1/L1.4/L3

# IfcSpace: Tuba 301C:985831, 301C
In: 3 korrus
LongName: Tuba; InteriorOrExteriorSpace: INTERNAL
Pset_AirSideSystemInformation - Name: Tuba; sets with these values: 2
Pset_SpaceCommon - Reference: Tuba 301C; FloorCovering: P7; WallCovering: S1.1/S1.6; CeilingCovering: L1.1/L1.4/L3

# IfcSpace: Tuba 301D:985834, 301D
In: 3 korrus
LongName: Tuba; InteriorOrExteriorSpace: INTERNAL
Pset_AirSideSystemInformation - Name: Tuba; sets with these values: 2
Pset_SpaceCommon - Reference: Tuba 301D; FloorCovering: P7; WallCovering: S1.1/S1.6; CeilingCovering: L1.1/L1.4/L3

# IfcSpace: Tuba 302A:985783, 302A
In: 3 Korrus A
LongName: Tuba; InteriorOrExteriorSpace: INTERNAL
Pset_AirSideSystemInformation - Name: Tuba; sets with these values: 2
Pset_SpaceCommon - Reference: Tuba 302A; FloorCovering: P7; WallCovering: S1.1/S1.6; CeilingCovering: L1.1/L1.4/L3

# IfcSpace: Tuba 302B:985786, 302B
In: 3 Korrus A
LongName: Tuba; InteriorOrExteriorSpace: INTERNAL
Pset_AirSideSystemInformation - Name: Tuba; sets with these values: 2
Pset_SpaceCommon - Reference: Tuba 302B; FloorCovering: P7; WallCovering: S1.1/S1.6; CeilingCovering: L1.1/L1.4/L3

# IfcSpace: Tuba 303A:985777, 303A
In: 3 Korrus A
LongName: Tuba; InteriorOrExteriorSpace: INTERNAL
Pset_AirSideSystemInformation - Name: Tuba; sets with these values: 2
Pset_SpaceCommon - Reference: Tuba 303A; FloorCovering: P7; WallCovering: S1.1/S1.6; CeilingCovering: L1.1/L1.4/L3

# IfcSpace: Tuba 303B:985780, 303B
In: 3 Korrus A
LongName: Tuba; InteriorOrExteriorSpace: INTERNAL
Pset_AirSideSystemInformation - Name: Tuba; sets with these values: 2
Pset_SpaceCommon - Reference: Tuba 303B; FloorCovering: P7; WallCovering: S1.1/S1.6; CeilingCovering: L1.1/L1.4/L3

# IfcSpace: Tuba 304A:985762, 304A
In: 3 Korrus A
LongName: Tuba; InteriorOrExteriorSpace: INTERNAL
Pset_AirSideSystemInformation - Name: Tuba; sets with these values: 2
Pset_SpaceCommon - Reference: Tuba 304A; FloorCovering: P7; WallCovering: S1.1/S1.6; CeilingCovering: L1.1/L1.4/L3

# IfcSpace: Tuba 304B:985765, 304B
In: 3 Korrus A
LongName: Tuba; InteriorOrExteriorSpace: INTERNAL
Pset_AirSideSystemInformation - Name: Tuba; sets with these values: 2
Pset_SpaceCommon - Reference: Tuba 304B; FloorCovering: P7; WallCovering: S1.1/S1.6; CeilingCovering: L1.1/L1.4/L3

# IfcSpace: Tuba 305A:985756, 305A
In: 3 Korrus A
LongName: Tuba; InteriorOrExteriorSpace: INTERNAL
Pset_AirSideSystemInformation - Name: Tuba; sets with these values: 2
Pset_SpaceCommon - Reference: Tuba 305A; FloorCovering: P7; WallCovering: S1.1/S1.6; CeilingCovering: L1.1/L1.4/L3

# IfcSpace: Tuba 305B:985759, 305B
In: 3 Korrus A
LongName: Tuba; InteriorOrExteriorSpace: INTERNAL
Pset_AirSideSystemInformation - Name: Tuba; sets with these values: 2
Pset_SpaceCommon - Reference: Tuba 305B; FloorCovering: P7; WallCovering: S1.1/S1.6; CeilingCovering: L1.1/L1.4/L3

# IfcSpace: Tuba 306A:985801, 306A
In: 3 Korrus A
LongName: Tuba; InteriorOrExteriorSpace: INTERNAL
Pset_AirSideSystemInformation - Name: Tuba; sets with these values: 2
Pset_SpaceCommon - Reference: Tuba 306A; FloorCovering: P7; WallCovering: S1.1/S1.6; CeilingCovering: L1.1/L1.4/L3

# IfcSpace: Tuba 306B:985804, 306B
In: 3 Korrus A
LongName: Tuba; InteriorOrExteriorSpace: INTERNAL
Pset_AirSideSystemInformation - Name: Tuba; sets with these values: 2
Pset_SpaceCommon - Reference: Tuba 306B; FloorCovering: P7; WallCovering: S1.1/S1.6; CeilingCovering: L1.1/L1.4/L3

# IfcSpace: Tuba 308A:985436, 308A
In: 3 korrus
LongName: Tuba; InteriorOrExteriorSpace: INTERNAL
Pset_AirSideSystemInformation - Name: Tuba; sets with these values: 2
Pset_SpaceCommon - Reference: Tuba 308A; FloorCovering: P7; WallCovering: S1.1/S1.6; CeilingCovering: L1.1/L1.4/L3

# IfcSpace: Tuba 308B:985439, 308B
In: 3 korrus
LongName: Tuba; InteriorOrExteriorSpace: INTERNAL
Pset_AirSideSystemInformation - Name: Tuba; sets with these values: 2
Pset_SpaceCommon - Reference: Tuba 308B; FloorCovering: P7; WallCovering: S1.1/S1.6; CeilingCovering: L1.1/L1.4/L3

# IfcSpace: Tuba 308C:985442, 308C
In: 3 korrus
LongName: Tuba; InteriorOrExteriorSpace: INTERNAL
Pset_AirSideSystemInformation - Name: Tuba; sets with these values: 2
Pset_SpaceCommon - Reference: Tuba 308C; FloorCovering: P7; WallCovering: S1.1/S1.6; CeilingCovering: L1.1/L1.4/L3

# IfcSpace: Tuba 308D:985446, 308D
In: 3 korrus
LongName: Tuba; InteriorOrExteriorSpace: INTERNAL
Pset_AirSideSystemInformation - Name: Tuba; sets with these values: 2
Pset_SpaceCommon - Reference: Tuba 308D; FloorCovering: P7; WallCovering: S1.1/S1.6; CeilingCovering: L1.1/L1.4/L3

# IfcSpace: Tuulekoda T101:983107, T101
In: 1 Korrus
LongName: Tuulekoda; InteriorOrExteriorSpace: INTERNAL
Pset_AirSideSystemInformation - Name: Tuulekoda; sets with these values: 2
Pset_SpaceCommon - Reference: Tuulekoda T101; FloorCovering: P1/P8; WallCovering: S1.1; CeilingCovering: L1.1

# IfcSpace: Tuulekoda T104:975484, T104
In: 1 Korrus
LongName: Tuulekoda; InteriorOrExteriorSpace: INTERNAL
Pset_AirSideSystemInformation - Name: Tuulekoda; sets with these values: 2
Pset_SpaceCommon - Reference: Tuulekoda T104; FloorCovering: P8; WallCovering: S1.1; CeilingCovering: L1.1

# IfcSpace: Töömehe ruum 004:1007040, 004
In: 0 Kelder
LongName: Töömehe ruum; InteriorOrExteriorSpace: INTERNAL
Pset_AirSideSystemInformation - Name: Töömehe ruum; sets with these values: 2
Pset_SpaceCommon - Reference: Töömehe ruum 004; FloorCovering: P1; WallCovering: S1.1; CeilingCovering: L1.1

# IfcSpace: Tööriiete kuivatus 011:1006994, 011
In: 0 Kelder
LongName: Tööriiete kuivatus; InteriorOrExteriorSpace: INTERNAL
Pset_AirSideSystemInformation - Name: Tööriiete kuivatus; sets with these values: 2
Pset_SpaceCommon - Reference: Tööriiete kuivatus 011; FloorCovering: P9; WallCovering: S2; CeilingCovering: L1.1

# IfcSpace: Wc 013:1309005, 013
In: 0 Kelder
LongName: Wc; InteriorOrExteriorSpace: INTERNAL
Pset_AirSideSystemInformation - Name: Wc; sets with these values: 2
Pset_SpaceCommon - Reference: Wc 013; FloorCovering: P3; WallCovering: S4.1/S4.2; CeilingCovering: L2

# IfcSpace: Wc 102C:1088651, 102C
In: 1 Korrus A
LongName: Wc; InteriorOrExteriorSpace: INTERNAL
Pset_AirSideSystemInformation - Name: Wc; sets with these values: 2
Pset_SpaceCommon - Reference: Wc 102C; FloorCovering: P3; WallCovering: S4.1/S4.2; CeilingCovering: L2

# IfcSpace: Wc 103D:1088648, 103D
In: 1 Korrus A
LongName: Wc; InteriorOrExteriorSpace: INTERNAL
Pset_AirSideSystemInformation - Name: Wc; sets with these values: 2
Pset_SpaceCommon - Reference: Wc 103D; FloorCovering: P3; WallCovering: S4.1/S4.2; CeilingCovering: L2

# IfcSpace: Wc 104C:1088638, 104C
In: 1 Korrus A
LongName: Wc; InteriorOrExteriorSpace: INTERNAL
Pset_AirSideSystemInformation - Name: Wc; sets with these values: 2
Pset_SpaceCommon - Reference: Wc 104C; FloorCovering: P3; WallCovering: S4.1/S4.2; CeilingCovering: L2

# IfcSpace: Wc 105D:1088629, 105D
In: 1 Korrus A
LongName: Wc; InteriorOrExteriorSpace: INTERNAL
Pset_AirSideSystemInformation - Name: Wc; sets with these values: 2
Pset_SpaceCommon - Reference: Wc 105D; FloorCovering: P3; WallCovering: S4.1/S4.2; CeilingCovering: L2

# IfcSpace: Wc 106C:976434, 106C
In: 1 Korrus A
LongName: Wc; InteriorOrExteriorSpace: INTERNAL
Pset_AirSideSystemInformation - Name: Wc; sets with these values: 2
Pset_SpaceCommon - Reference: Wc 106C; FloorCovering: P3; WallCovering: S4.1/S4.2; CeilingCovering: L2

# IfcSpace: Wc 108F:997693, 108F
In: 1 Korrus
LongName: Wc; InteriorOrExteriorSpace: INTERNAL
Pset_AirSideSystemInformation - Name: Wc; sets with these values: 2
Pset_SpaceCommon - Reference: Wc 108F; FloorCovering: P3/P4; WallCovering: S4.1/S4.2; CeilingCovering: L2

# IfcSpace: Wc 111:1172387, 111
In: 1 Korrus A
LongName: Wc; InteriorOrExteriorSpace: INTERNAL
Pset_AirSideSystemInformation - Name: Wc; sets with these values: 2
Pset_SpaceCommon - Reference: Wc 111; FloorCovering: P3; WallCovering: S4.1/S4.2; CeilingCovering: L2

# IfcSpace: Wc 201E:984378, 201E
In: 2 Korrus
LongName: Wc; InteriorOrExteriorSpace: INTERNAL
Pset_AirSideSystemInformation - Name: Wc; sets with these values: 2
Pset_SpaceCommon - Reference: Wc 201E; FloorCovering: P3/P4; WallCovering: S4.1/S4.2; CeilingCovering: L2

# IfcSpace: Wc 202C:977814, 202C
In: 2 Korrus A
LongName: Wc; InteriorOrExteriorSpace: INTERNAL
Pset_AirSideSystemInformation - Name: Wc; sets with these values: 2
Pset_SpaceCommon - Reference: Wc 202C; FloorCovering: P3; WallCovering: S4.1/S4.2; CeilingCovering: L2

# IfcSpace: Wc 203D:977802, 203D
In: 2 Korrus A
LongName: Wc; InteriorOrExteriorSpace: INTERNAL
Pset_AirSideSystemInformation - Name: Wc; sets with these values: 2
Pset_SpaceCommon - Reference: Wc 203D; FloorCovering: P3; WallCovering: S4.1/S4.2; CeilingCovering: L2

# IfcSpace: Wc 204C:977784, 204C
In: 2 Korrus A
LongName: Wc; InteriorOrExteriorSpace: INTERNAL
Pset_AirSideSystemInformation - Name: Wc; sets with these values: 2
Pset_SpaceCommon - Reference: Wc 204C; FloorCovering: P3; WallCovering: S4.1/S4.2; CeilingCovering: L2

# IfcSpace: Wc 205D:977772, 205D
In: 2 Korrus A
LongName: Wc; InteriorOrExteriorSpace: INTERNAL
Pset_AirSideSystemInformation - Name: Wc; sets with these values: 2
Pset_SpaceCommon - Reference: Wc 205D; FloorCovering: P3; WallCovering: S4.1/S4.2; CeilingCovering: L2

# IfcSpace: Wc 206C:977847, 206C
In: 2 Korrus A
LongName: Wc; InteriorOrExteriorSpace: INTERNAL
Pset_AirSideSystemInformation - Name: Wc; sets with these values: 2
Pset_SpaceCommon - Reference: Wc 206C; FloorCovering: P3; WallCovering: S4.1/S4.2; CeilingCovering: L2

# IfcSpace: Wc 208F:977686, 208F
In: 2 Korrus
LongName: Wc; InteriorOrExteriorSpace: INTERNAL
Pset_AirSideSystemInformation - Name: Wc; sets with these values: 2
Pset_SpaceCommon - Reference: Wc 208F; FloorCovering: P3; WallCovering: S3.1/S3.2; CeilingCovering: L2

# IfcSpace: Wc 301F:985819, 301F
In: 3 korrus
LongName: Wc; InteriorOrExteriorSpace: INTERNAL
Pset_AirSideSystemInformation - Name: Wc; sets with these values: 2
Pset_SpaceCommon - Reference: Wc 301F; FloorCovering: P3; WallCovering: S4.1/S4.2; CeilingCovering: L2

# IfcSpace: Wc 302C:1125641, 302C
In: 3 Korrus A
LongName: Wc; InteriorOrExteriorSpace: INTERNAL
Pset_AirSideSystemInformation - Name: Wc; sets with these values: 2
Pset_SpaceCommon - Reference: Wc 302C; FloorCovering: P3; WallCovering: S4.1/S4.2; CeilingCovering: L2

# IfcSpace: Wc 303D:1125638, 303D
In: 3 Korrus A
LongName: Wc; InteriorOrExteriorSpace: INTERNAL
Pset_AirSideSystemInformation - Name: Wc; sets with these values: 2
Pset_SpaceCommon - Reference: Wc 303D; FloorCovering: P3; WallCovering: S4.1/S4.2; CeilingCovering: L2

# IfcSpace: Wc 304C:1125647, 304C
In: 3 Korrus A
LongName: Wc; InteriorOrExteriorSpace: INTERNAL
Pset_AirSideSystemInformation - Name: Wc; sets with these values: 2
Pset_SpaceCommon - Reference: Wc 304C; FloorCovering: P3; WallCovering: S4.1/S4.2; CeilingCovering: L2

# IfcSpace: Wc 305D:1125650, 305D
In: 3 Korrus A
LongName: Wc; InteriorOrExteriorSpace: INTERNAL
Pset_AirSideSystemInformation - Name: Wc; sets with these values: 2
Pset_SpaceCommon - Reference: Wc 305D; FloorCovering: P3; WallCovering: S4.1/S4.2; CeilingCovering: L2

# IfcSpace: Wc 306C:985795, 306C
In: 3 Korrus A
LongName: Wc; InteriorOrExteriorSpace: INTERNAL
Pset_AirSideSystemInformation - Name: Wc; sets with these values: 2
Pset_SpaceCommon - Reference: Wc 306C; FloorCovering: P3; WallCovering: S4.1/S4.2; CeilingCovering: L2

# IfcSpace: Wc 308F:985430, 308F
In: 3 korrus
LongName: Wc; InteriorOrExteriorSpace: INTERNAL
Pset_AirSideSystemInformation - Name: Wc; sets with these values: 2
Pset_SpaceCommon - Reference: Wc 308F; FloorCovering: P3; WallCovering: S4.1/S4.2; CeilingCovering: L2

# IfcBuildingElementProxy: 2249041
In: Katus
Type - Description: eQ, s/e air
Pset_ProductRequirements - Category: Generic Models
Group: Model Group:Katus:2248594

# IfcBuildingElementProxy: 4048P Wall mounted toilet brush set polished stainless steel_ENG:Type 1 (4)
Type - Material: Inox 304 poli brillant
Type - Pset_BuildingElementProxyCommon - Reference: Type 1
Type - Pset_ManufacturerOccurrence - SerialNumber: 3456330028646
Type - Pset_ManufacturerTypeInformation - Manufacturer: DELABIE
Type - Pset_PrecastConcreteElementGeneral - SerialNumber: 3456330028646
Type - Pset_ProductRequirements - Name: Toilet brush set; Category: WC accessories
Type - Pset_QuantityTakeOff - Reference: Type 1
Pset_BuildingElementProxyCommon - sets with these values: 2
Pset_ManufacturerOccurrence - sets with these values: 2
Pset_ProductRequirements - Category: Generic Models
Name (4048P Wall mounted toilet brush set polished stainless steel_ENG:Type 1:...) | In
1431984 | 205D
1910578 | 111
1910730 | 101E
1911784 | 013

# IfcBuildingElementProxy: Fully_Parametric_Flagpole_7712:American Flag, Fully_Parametric_Flagpole_7712:American Flag:1234127
In: 0 Kelder
Type - Material: <Unnamed> (2), Steel
Type - Pset_BuildingElementProxyCommon - Reference: American Flag
Type - Pset_ProductRequirements - Category: Generic Models
Type - Pset_QuantityTakeOff - Reference: American Flag
Material: Steel
Pset_BuildingElementProxyCommon - sets with these values: 2

# IfcBuildingElementProxy: Generic Models 10:Generic Models 27, Generic Models 10:Generic Models 27:1786656
In: T201
Type - Material: __Olemasolev konstruktsioon
Type - Pset_BuildingElementProxyCommon - Reference: Generic Models 27
Type - Pset_ProductRequirements - Category: Generic Models
Type - Pset_QuantityTakeOff - Reference: Generic Models 27
Pset_BuildingElementProxyCommon - sets with these values: 2

# IfcBuildingElementProxy: Generic Models 11:Generic Models 4, Generic Models 11:Generic Models 4:1437210
In: 3 korrus
Type - Material: __Metall silt valge
Type - Pset_BuildingElementProxyCommon - Reference: Generic Models 4
Type - Pset_ProductRequirements - Category: Generic Models
Type - Pset_QuantityTakeOff - Reference: Generic Models 4
Pset_BuildingElementProxyCommon - sets with these values: 2
Pset_ProvisionForVoid - Width: 20 mm; Height: 662.5 mm; Depth: 20 mm

# IfcBuildingElementProxy: Generic Models 12:Generic Models 12, Generic Models 12:Generic Models 12:1463340
In: 308
Type - Material: __Metall silt valge
Type - Pset_BuildingElementProxyCommon - Reference: Generic Models 12
Type - Pset_ProductRequirements - Category: Generic Models
Type - Pset_QuantityTakeOff - Reference: Generic Models 12
Pset_BuildingElementProxyCommon - sets with these values: 2
Pset_ProvisionForVoid - Width: 2400 mm; Height: 17.8196 mm; Depth: 2400 mm

# IfcBuildingElementProxy: Generic Models 13:Generic Models 13, Generic Models 13:Generic Models 13:1486218
In: 207
Type - Material: __Metall silt valge
Type - Pset_BuildingElementProxyCommon - Reference: Generic Models 13
Type - Pset_ProductRequirements - Category: Generic Models
Type - Pset_QuantityTakeOff - Reference: Generic Models 13
Pset_BuildingElementProxyCommon - sets with these values: 2
Pset_ProvisionForVoid - Width: 389.406 mm; Height: 16 mm; Depth: 389.406 mm

# IfcBuildingElementProxy: Generic Models 14:Generic Models 14, Generic Models 14:Generic Models 14:1810133
In: 207
Type - Material: __Metall silt valge
Type - Pset_BuildingElementProxyCommon - Reference: Generic Models 14
Type - Pset_ProductRequirements - Category: Generic Models
Type - Pset_QuantityTakeOff - Reference: Generic Models 14
Pset_BuildingElementProxyCommon - sets with these values: 2
Pset_ProvisionForVoid - Width: 880 mm; Height: 2053.62 mm; Depth: 880 mm

# IfcBuildingElementProxy: Generic Models 15:Generic Models 14, Generic Models 15:Generic Models 14:1817653
In: 207
Type - Material: __Metall silt valge
Type - Pset_BuildingElementProxyCommon - Reference: Generic Models 14
Type - Pset_ProductRequirements - Category: Generic Models
Type - Pset_QuantityTakeOff - Reference: Generic Models 14
Pset_BuildingElementProxyCommon - sets with these values: 2
Pset_ProvisionForVoid - Width: 880 mm; Height: 2928 mm; Depth: 880 mm

# IfcBuildingElementProxy: Generic Models 16:Generic Models 8, Generic Models 16:Generic Models 8:2295190
In: T101
Type - Material: __Metall silt hall
Type - Pset_BuildingElementProxyCommon - Reference: Generic Models 8
Type - Pset_ProductRequirements - Category: Generic Models
Type - Pset_QuantityTakeOff - Reference: Generic Models 8
Material: __Metall silt hall, __Metall silt heleroheline), __Metall silt korallroosa, __Metall silt sinine
Pset_BuildingElementProxyCommon - sets with these values: 2
Pset_ProvisionForVoid - Width: 250 mm; Height: 800 mm; Depth: 250 mm

# IfcBuildingElementProxy: Generic Models 17:Generic Models 49, Generic Models 17:Generic Models 49:1524754
In: 0 Kelder
Type - Material: __Tumehall SW
Type - Pset_BuildingElementProxyCommon - Reference: Generic Models 49
Type - Pset_ProductRequirements - Category: Generic Models
Type - Pset_QuantityTakeOff - Reference: Generic Models 49
Pset_BuildingElementProxyCommon - sets with these values: 2

# IfcBuildingElementProxy: Generic Models 18:Generic Models 17, Generic Models 18:Generic Models 17:1525959
In: 1 Korrus A
Type - Material: __Metal Tumehall
Type - Pset_BuildingElementProxyCommon - Reference: Generic Models 17
Type - Pset_ProductRequirements - Category: Generic Models
Type - Pset_QuantityTakeOff - Reference: Generic Models 17
Pset_BuildingElementProxyCommon - sets with these values: 2
Pset_ProvisionForVoid - Width: 300 mm; Depth: 300 mm

# IfcBuildingElementProxy: Generic Models 19:Generic Models 17, Generic Models 19:Generic Models 17:1544020
In: 1 Korrus
Type - Material: __Metal Tumehall
Type - Pset_BuildingElementProxyCommon - Reference: Generic Models 17
Type - Pset_ProductRequirements - Category: Generic Models
Type - Pset_QuantityTakeOff - Reference: Generic Models 17
Pset_BuildingElementProxyCommon - sets with these values: 2
Pset_ProvisionForVoid - Width: 275.5 mm; Depth: 275.5 mm

# IfcBuildingElementProxy: Generic Models 1:Generic Models 49, Generic Models 1:Generic Models 49:1027794
In: 0 Kelder
Type - Material: __Tumehall SW
Type - Pset_BuildingElementProxyCommon - Reference: Generic Models 49
Type - Pset_ProductRequirements - Category: Generic Models
Type - Pset_QuantityTakeOff - Reference: Generic Models 49
Pset_BuildingElementProxyCommon - sets with these values: 2

# IfcBuildingElementProxy: Generic Models 20:Generic Models 17, Generic Models 20:Generic Models 17:1545922
In: 1 Korrus A
Type - Material: __Metal Tumehall
Type - Pset_BuildingElementProxyCommon - Reference: Generic Models 17
Type - Pset_ProductRequirements - Category: Generic Models
Type - Pset_QuantityTakeOff - Reference: Generic Models 17
Pset_BuildingElementProxyCommon - sets with these values: 2
Pset_ProvisionForVoid - Width: 313.5 mm; Depth: 313.5 mm

# IfcBuildingElementProxy: Generic Models 21:Generic Models 13, Generic Models 21:Generic Models 13:1872316
In: 307
Type - Material: __Metall silt valge
Type - Pset_BuildingElementProxyCommon - Reference: Generic Models 13
Type - Pset_ProductRequirements - Category: Generic Models
Type - Pset_QuantityTakeOff - Reference: Generic Models 13
Pset_BuildingElementProxyCommon - sets with these values: 2
Pset_ProvisionForVoid - Width: 389.406 mm; Height: 16 mm; Depth: 389.406 mm

# IfcBuildingElementProxy: Generic Models 22:Generic Models 14, Generic Models 22:Generic Models 14:1557127
In: 307
Type - Material: __Metall silt valge
Type - Pset_BuildingElementProxyCommon - Reference: Generic Models 14
Type - Pset_ProductRequirements - Category: Generic Models
Type - Pset_QuantityTakeOff - Reference: Generic Models 14
Pset_BuildingElementProxyCommon - sets with these values: 2
Pset_ProvisionForVoid - Width: 880 mm; Height: 2040 mm; Depth: 880 mm

# IfcBuildingElementProxy: Generic Models 23:Generic Models 14, Generic Models 23:Generic Models 14:1817761
In: 307
Type - Material: __Metall silt valge
Type - Pset_BuildingElementProxyCommon - Reference: Generic Models 14
Type - Pset_ProductRequirements - Category: Generic Models
Type - Pset_QuantityTakeOff - Reference: Generic Models 14
Pset_BuildingElementProxyCommon - sets with these values: 2
Pset_ProvisionForVoid - Width: 880 mm; Height: 2928 mm; Depth: 880 mm

# IfcBuildingElementProxy: Generic Models 24:Generic Models 14, Generic Models 24:Generic Models 14:1810305
In: 107
Type - Material: __Metall silt valge
Type - Pset_BuildingElementProxyCommon - Reference: Generic Models 14
Type - Pset_ProductRequirements - Category: Generic Models
Type - Pset_QuantityTakeOff - Reference: Generic Models 14
Pset_BuildingElementProxyCommon - sets with these values: 2
Pset_ProvisionForVoid - Width: 880 mm; Height: 2052.4 mm; Depth: 880 mm

# IfcBuildingElementProxy: Generic Models 25:Generic Models 4, Generic Models 25:Generic Models 4:1691928
In: 3 korrus
Type - Material: __Metall silt valge
Type - Pset_BuildingElementProxyCommon - Reference: Generic Models 4
Type - Pset_ProductRequirements - Category: Generic Models
Type - Pset_QuantityTakeOff - Reference: Generic Models 4
Pset_BuildingElementProxyCommon - sets with these values: 2
Pset_ProvisionForVoid - Width: 20 mm; Height: 450.99 mm; Depth: 20 mm

# IfcBuildingElementProxy: Generic Models 26:Generic Models 27, Generic Models 26:Generic Models 27:1751667
In: 1 Korrus A
Type - Material: __Olemasolev konstruktsioon
Type - Pset_BuildingElementProxyCommon - Reference: Generic Models 27
Type - Pset_ProductRequirements - Category: Generic Models
Type - Pset_QuantityTakeOff - Reference: Generic Models 27
Pset_BuildingElementProxyCommon - sets with these values: 2

# IfcBuildingElementProxy: Generic Models 27:Generic Models 27, Generic Models 27:Generic Models 27:1753589
In: T202
Type - Material: __Olemasolev konstruktsioon
Type - Pset_BuildingElementProxyCommon - Reference: Generic Models 27
Type - Pset_ProductRequirements - Category: Generic Models
Type - Pset_QuantityTakeOff - Reference: Generic Models 27
Pset_BuildingElementProxyCommon - sets with these values: 2

# IfcBuildingElementProxy: Generic Models 28:Generic Models 27, Generic Models 28:Generic Models 27:1786895
In: 1 Korrus A
Type - Material: __Olemasolev konstruktsioon
Type - Pset_BuildingElementProxyCommon - Reference: Generic Models 27
Type - Pset_ProductRequirements - Category: Generic Models
Type - Pset_QuantityTakeOff - Reference: Generic Models 27
Pset_BuildingElementProxyCommon - sets with these values: 2

# IfcBuildingElementProxy: Generic Models 29:Generic Models 27, Generic Models 29:Generic Models 27:1787130
In: T201
Type - Material: __Olemasolev konstruktsioon
Type - Pset_BuildingElementProxyCommon - Reference: Generic Models 27
Type - Pset_ProductRequirements - Category: Generic Models
Type - Pset_QuantityTakeOff - Reference: Generic Models 27
Pset_BuildingElementProxyCommon - sets with these values: 2

# IfcBuildingElementProxy: Generic Models 2:Generic Models 49, Generic Models 2:Generic Models 49:1027911
In: 0 Kelder
Type - Material: __Tumehall SW
Type - Pset_BuildingElementProxyCommon - Reference: Generic Models 49
Type - Pset_ProductRequirements - Category: Generic Models
Type - Pset_QuantityTakeOff - Reference: Generic Models 49
Pset_BuildingElementProxyCommon - sets with these values: 2

# IfcBuildingElementProxy: Generic Models 30:Generic Models 13, Generic Models 30:Generic Models 13:1872477
In: 107
Type - Material: __Metall silt valge
Type - Pset_BuildingElementProxyCommon - Reference: Generic Models 13
Type - Pset_ProductRequirements - Category: Generic Models
Type - Pset_QuantityTakeOff - Reference: Generic Models 13
Pset_BuildingElementProxyCommon - sets with these values: 2
Pset_ProvisionForVoid - Width: 389.406 mm; Height: 16 mm; Depth: 389.406 mm

# IfcBuildingElementProxy: Generic Models 31:Generic Models 14, Generic Models 31:Generic Models 14:1810352
In: 107
Type - Material: __Metall silt valge
Type - Pset_BuildingElementProxyCommon - Reference: Generic Models 14
Type - Pset_ProductRequirements - Category: Generic Models
Type - Pset_QuantityTakeOff - Reference: Generic Models 14
Pset_BuildingElementProxyCommon - sets with these values: 2
Pset_ProvisionForVoid - Width: 880 mm; Height: 2928 mm; Depth: 880 mm

# IfcBuildingElementProxy: Generic Models 32:Generic Models 27, Generic Models 32:Generic Models 27:1142491
In: T202
Type - Material: Concrete, Cast In Situ
Type - Pset_BuildingElementProxyCommon - Reference: Generic Models 27
Type - Pset_ProductRequirements - Category: Generic Models
Type - Pset_QuantityTakeOff - Reference: Generic Models 27
Material: Concrete, Cast In Situ, __Olemasolev konstruktsioon
Pset_BuildingElementProxyCommon - sets with these values: 2

# IfcBuildingElementProxy: Generic Models 33:Generic Models 27, Generic Models 33:Generic Models 27:1145210
In: T202
Type - Material: __Olemasolev konstruktsioon
Type - Pset_BuildingElementProxyCommon - Reference: Generic Models 27
Type - Pset_ProductRequirements - Category: Generic Models
Type - Pset_QuantityTakeOff - Reference: Generic Models 27
Pset_BuildingElementProxyCommon - sets with these values: 2

# IfcBuildingElementProxy: Generic Models 34:Generic Models 8, Generic Models 34:Generic Models 8:2296738
In: T201
Type - Material: __Metall silt hall
Type - Pset_BuildingElementProxyCommon - Reference: Generic Models 8
Type - Pset_ProductRequirements - Category: Generic Models
Type - Pset_QuantityTakeOff - Reference: Generic Models 8
Material: __Metall silt hall, __Metall silt heleroheline), __Metall silt korallroosa, __Metall silt sinine
Pset_BuildingElementProxyCommon - sets with these values: 2
Pset_ProvisionForVoid - Width: 5 mm; Depth: 5 mm

# IfcBuildingElementProxy: Generic Models 35:Generic Models 8, Generic Models 35:Generic Models 8:2304223
In: T202
Type - Material: __Metall silt hall
Type - Pset_BuildingElementProxyCommon - Reference: Generic Models 8
Type - Pset_ProductRequirements - Category: Generic Models
Type - Pset_QuantityTakeOff - Reference: Generic Models 8
Material: __Metall silt hall, __Metall silt heleroheline), __Metall silt korallroosa, __Metall silt sinine
Pset_BuildingElementProxyCommon - sets with these values: 2
Pset_ProvisionForVoid - Width: 5 mm; Depth: 5 mm

# IfcBuildingElementProxy: Generic Models 36:Generic Models 8, Generic Models 36:Generic Models 8:2314490
In: K201
Type - Material: __Metall silt heleroheline)
Type - Pset_BuildingElementProxyCommon - Reference: Generic Models 8
Type - Pset_ProductRequirements - Category: Generic Models
Type - Pset_QuantityTakeOff - Reference: Generic Models 8
Material: __Metall silt heleroheline), __Metall silt korallroosa, __Metall silt sinine
Pset_BuildingElementProxyCommon - sets with these values: 2
Pset_ProvisionForVoid - Width: 5 mm; Depth: 5 mm

# IfcBuildingElementProxy: Generic Models 37:Generic Models 2, Generic Models 37:Generic Models 2:2387745
In: 107
Type - Material: Wood Sheathing, Chipboard
Type - Pset_BuildingElementProxyCommon - Reference: Generic Models 2
Type - Pset_ProductRequirements - Category: Generic Models
Type - Pset_QuantityTakeOff - Reference: Generic Models 2
Pset_BuildingElementProxyCommon - sets with these values: 2
Pset_ProvisionForVoid - Width: 30 mm; Height: 100 mm; Depth: 30 mm

# IfcBuildingElementProxy: Generic Models 38:Generic Models 2, Generic Models 38:Generic Models 2:2387913
In: 207
Type - Material: Wood Sheathing, Chipboard
Type - Pset_BuildingElementProxyCommon - Reference: Generic Models 2
Type - Pset_ProductRequirements - Category: Generic Models
Type - Pset_QuantityTakeOff - Reference: Generic Models 2
Pset_BuildingElementProxyCommon - sets with these values: 2
Pset_ProvisionForVoid - Width: 30 mm; Height: 100 mm; Depth: 30 mm

# IfcBuildingElementProxy: Generic Models 39:Generic Models 2, Generic Models 39:Generic Models 2:2388071
In: 307
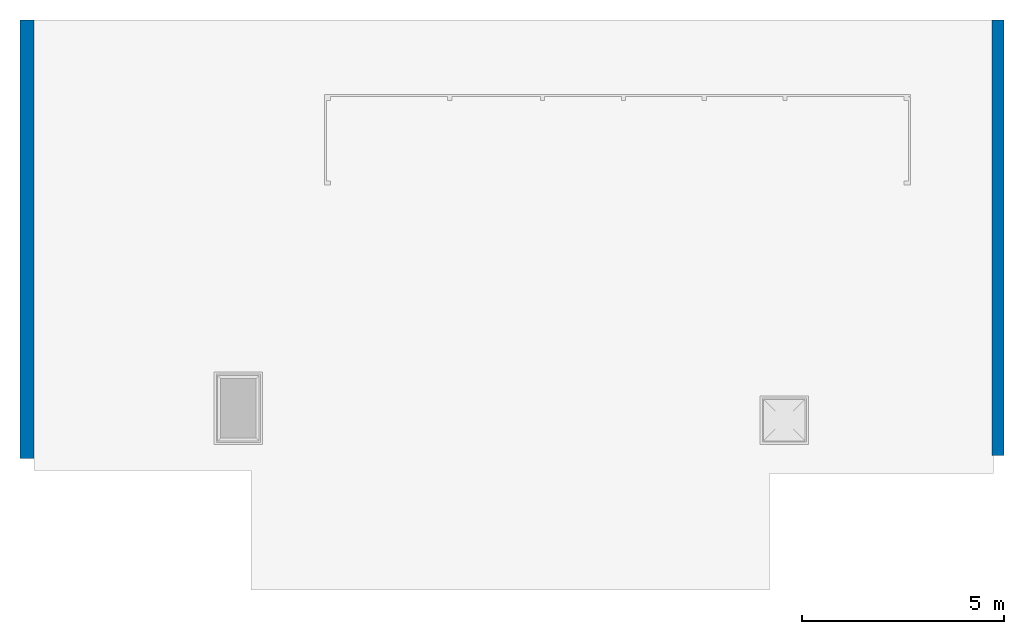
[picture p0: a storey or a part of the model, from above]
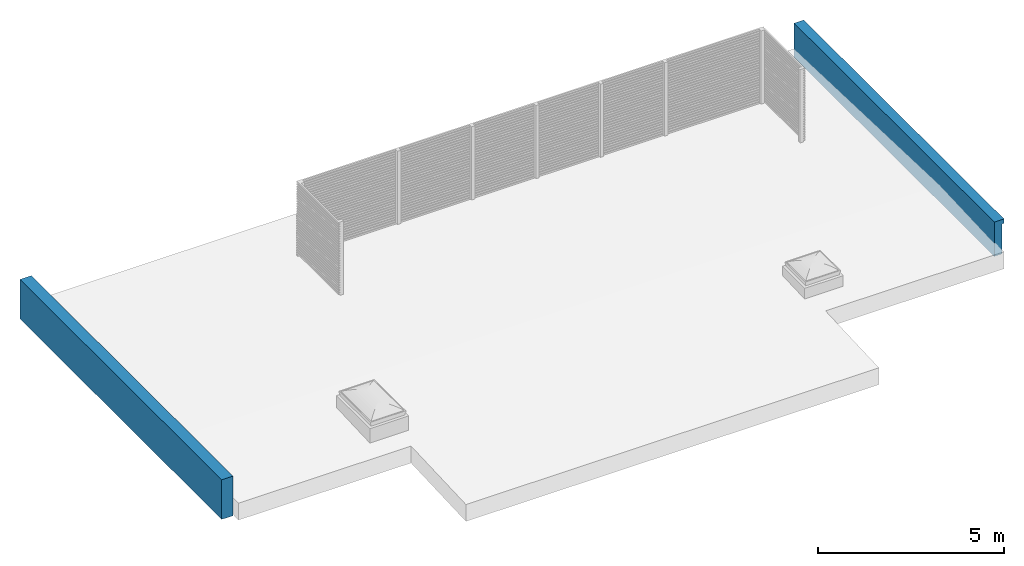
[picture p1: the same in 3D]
Properties of the parts of a building model (IFC2X3), part 2 of 7

# IfcBuildingElementProxy: Generic Models 39:Generic Models 2, Generic Models 39:Generic Models 2:2388071
Type - Material: Wood Sheathing, Chipboard
Type - Pset_BuildingElementProxyCommon - Reference: Generic Models 2
Type - Pset_ProductRequirements - Category: Generic Models
Type - Pset_QuantityTakeOff - Reference: Generic Models 2
Pset_BuildingElementProxyCommon - sets with these values: 2
Pset_ProvisionForVoid - Width: 30 mm; Height: 100 mm; Depth: 30 mm

# IfcBuildingElementProxy: Generic Models 3:Generic Models 3, Generic Models 3:Generic Models 3:1031346
In: Katus
Type - Material: EST. Katusekate. Plekk. Värvitud. RR32
Type - Pset_BuildingElementProxyCommon - Reference: Generic Models 3
Type - Pset_ProductRequirements - Category: Generic Models
Type - Pset_QuantityTakeOff - Reference: Generic Models 3
Pset_BuildingElementProxyCommon - sets with these values: 2

# IfcBuildingElementProxy: Generic Models 41:Generic Models 2, Generic Models 41:Generic Models 2:1277709
In: 109
Type - Material: Wood Sheathing, Chipboard
Type - Pset_BuildingElementProxyCommon - Reference: Generic Models 2
Type - Pset_ProductRequirements - Category: Generic Models
Type - Pset_QuantityTakeOff - Reference: Generic Models 2
Pset_BuildingElementProxyCommon - sets with these values: 2
Pset_ProvisionForVoid - Width: 30 mm; Height: 100 mm; Depth: 30 mm

# IfcBuildingElementProxy: Generic Models 4:Generic Models 4, Generic Models 4:Generic Models 4:1376197
In: 3 korrus
Type - Material: __Metall silt valge
Type - Pset_BuildingElementProxyCommon - Reference: Generic Models 4
Type - Pset_ProductRequirements - Category: Generic Models
Type - Pset_QuantityTakeOff - Reference: Generic Models 4
Pset_BuildingElementProxyCommon - sets with these values: 2
Pset_ProvisionForVoid - Width: 20 mm; Height: 662.5 mm; Depth: 20 mm

# IfcBuildingElementProxy: Generic Models 5:Generic Models 5, Generic Models 5:Generic Models 5:1038817
In: 1 Korrus
Type - Material: EST. Puit. Liimpuit
Type - Pset_BuildingElementProxyCommon - Reference: Generic Models 5
Type - Pset_ProductRequirements - Category: Generic Models
Type - Pset_QuantityTakeOff - Reference: Generic Models 5
Pset_BuildingElementProxyCommon - sets with these values: 2
Pset_ProvisionForVoid - Width: 100 mm; Depth: 100 mm

# IfcBuildingElementProxy: Generic Models 6:Generic Models 5, Generic Models 6:Generic Models 5:1039988
In: 1 Korrus
Type - Material: EST. Puit. Liimpuit
Type - Pset_BuildingElementProxyCommon - Reference: Generic Models 5
Type - Pset_ProductRequirements - Category: Generic Models
Type - Pset_QuantityTakeOff - Reference: Generic Models 5
Pset_BuildingElementProxyCommon - sets with these values: 2
Pset_ProvisionForVoid - Width: 100 mm; Depth: 100 mm

# IfcBuildingElementProxy: Generic Models 72:Generic Models 49, Generic Models 72:Generic Models 49:1664487
In: 0 Kelder
Type - Material: __Tumehall SW
Type - Pset_BuildingElementProxyCommon - Reference: Generic Models 49
Type - Pset_ProductRequirements - Category: Generic Models
Type - Pset_QuantityTakeOff - Reference: Generic Models 49
Pset_BuildingElementProxyCommon - sets with these values: 2

# IfcBuildingElementProxy: Generic Models 7:Generic Models 49, Generic Models 7:Generic Models 49:1643334
In: 0 Kelder
Type - Material: __Tumehall SW
Type - Pset_BuildingElementProxyCommon - Reference: Generic Models 49
Type - Pset_ProductRequirements - Category: Generic Models
Type - Pset_QuantityTakeOff - Reference: Generic Models 49
Pset_BuildingElementProxyCommon - sets with these values: 2

# IfcBuildingElementProxy: Generic Models 8:Generic Models 8, Generic Models 8:Generic Models 8:1304295
In: 1 Korrus A
Type - Material: __Metall silt valge
Type - Pset_BuildingElementProxyCommon - Reference: Generic Models 8
Type - Pset_ProductRequirements - Category: Generic Models
Type - Pset_QuantityTakeOff - Reference: Generic Models 8
Material: __Metall silt valge, __Metall silt sinine
Pset_BuildingElementProxyCommon - sets with these values: 2
Pset_ProvisionForVoid - Width: 180 mm; Height: 600 mm; Depth: 180 mm

# IfcBuildingElementProxy: Generic Models 9:Generic Models 27, Generic Models 9:Generic Models 27:1786599
In: T201
Type - Material: __Olemasolev konstruktsioon
Type - Pset_BuildingElementProxyCommon - Reference: Generic Models 27
Type - Pset_ProductRequirements - Category: Generic Models
Type - Pset_QuantityTakeOff - Reference: Generic Models 27
Pset_BuildingElementProxyCommon - sets with these values: 2

# IfcBuildingElementProxy: Mediclinics_Liquid soap dispenser_DJ0031x:DJ0031 (43)
Type - Classification: E Equipment & Furnishings (Uniformat); Material: AISI 304 stainless steel_Mediclinics_Satin, Steel_Mediclinics_White epoxy
Type - Pset_BuildingElementProxyCommon - Reference: DJ0031
Type - Pset_ManufacturerTypeInformation - Manufacturer: Mediclinics
Type - Pset_ProductRequirements - Category: Generic Models
Type - Pset_QuantityTakeOff - Reference: DJ0031
Type - Pset_ProvisionForVoid - Width: 109.999 mm; Height: 240 mm; Depth: 133 mm
Material: Steel_Mediclinics_White epoxy, Transparent, AISI 304 stainless steel_Mediclinics_Satin, black
Pset_BuildingElementProxyCommon - sets with these values: 2
Name (Mediclinics_Liquid soap dispenser_DJ0031x:DJ0031:...) | In
1399014 | 205D
1404758 | 205C
1909454 | 101E
1910485 | 111
2230232 | 013
2234027 | 204D
2234028 | 204C
2234034 | 203D
2234035 | 203C
2234043 | 202D
2234044 | 202C
2234052 | 302D
2234053 | 302C
2234061 | 303D
2234062 | 303C
2234070 | 304D
2234071 | 304C
2234079 | 305D
2234080 | 305C
2234088 | 105D
2234089 | 105C
2234097 | 104D
2234098 | 104C
2234106 | 103D
2234107 | 103C
2234117 | 102D
2234118 | 102C
2234857 | 108G
2234974 | 108F
2235513 | 208F
2235560 | 308F
2235612 | 201F
2235745 | 301F
2236091 | 201E
2236092 | 301E
2236100 | 208E
2236110 | 308E
2236352 | 306D
2236397 | 306C
2237005 | 206D
2237007 | 206C
2237059 | 106D
2237060 | 106C

# IfcBuildingElementProxy: Mediclinics_Steel paper towel CZ folds dispenser_DT0106x:DT0106C (36)
Type - Material: <Unnamed>, AISI 304 stainless steel_Mediclinics_Bright
Type - Pset_BuildingElementProxyCommon - Reference: DT0106C
Type - Pset_ManufacturerTypeInformation - Manufacturer: Mediclinics
Type - Pset_ProductRequirements - Category: Generic Models
Type - Pset_QuantityTakeOff - Reference: DT0106C
Type - Pset_ProvisionForVoid - Width: 275 mm; Height: 330 mm; Depth: 133 mm
Material: AISI 304 stainless steel_Mediclinics_Bright
Pset_BuildingElementProxyCommon - sets with these values: 2
Name (Mediclinics_Steel paper towel CZ folds dispenser_DT0106x:DT0106C:...) | In
1399045 | 205D
1910194 | 101E
1910356 | 111
2099231 | 204C
2099233 | 204D
2099235 | 203C
2099237 | 203D
2099239 | 202C
2099241 | 202D
2099243 | 206C
2099245 | 206D
2230235 | 013
2233977 | 105D
2233981 | 104C
2233983 | 104D
2233985 | 103C
2233987 | 103D
2233989 | 102C
2233991 | 102D
2235157 | 108F
2235336 | 108G
2235515 | 208F
2235561 | 308F
2236120 | 301F
2236223 | 201F
2236622 | 306C
2236729 | 306D
2237054 | 106C
2237056 | 106D
2379041 | 305D
2379045 | 304C
2379047 | 304D
2379049 | 303C
2379051 | 303D
2379053 | 302C
2379055 | 302D

# IfcBuildingElementProxy: Mediclinics_Steel paper towel CZ folds dispenser_DT0106x:DT0106C (7)
Type - Material: AISI 304 stainless steel_Mediclinics_Bright, <Unnamed>
Type - Pset_BuildingElementProxyCommon - Reference: DT0106C
Type - Pset_ManufacturerTypeInformation - Manufacturer: Mediclinics
Type - Pset_ProductRequirements - Category: Generic Models
Type - Pset_QuantityTakeOff - Reference: DT0106C
Type - Pset_ProvisionForVoid - Width: 275 mm; Height: 330 mm; Depth: 133 mm
Material: AISI 304 stainless steel_Mediclinics_Bright
Pset_BuildingElementProxyCommon - sets with these values: 2
Name (Mediclinics_Steel paper towel CZ folds dispenser_DT0106x:DT0106C:...) | In
1901458 | 205C
2233979 | 105C
2236101 | 208E
2236111 | 308E
2236240 | 301E
2379043 | 305C
2379115 | 201E

# IfcBuildingElementProxy: Model Text:1000mm Arial bold (3)
Type - Pset_BuildingElementProxyCommon - Reference: 1000mm Arial bold
Type - Pset_ProductRequirements - Category: Generic Models
Type - Pset_QuantityTakeOff - Reference: 1000mm Arial bold
Pset_BuildingElementProxyCommon - sets with these values: 2
Pset_ProvisionForVoid - Shape: Undefined; Width: 10 mm; Depth: 10 mm
Name (Model Text:1000mm Arial bold:...) | In
2315669 | 2 Korrus
2316586 | 3 korrus
2316606 | Katus

# IfcBuildingElementProxy: Model Text:150mm Arial (4)
Type - Pset_BuildingElementProxyCommon - Reference: 150mm Arial
Type - Pset_ProductRequirements - Category: Generic Models
Type - Pset_QuantityTakeOff - Reference: 150mm Arial
Pset_BuildingElementProxyCommon - sets with these values: 2
Pset_ProvisionForVoid - Shape: Undefined; Width: 10 mm; Depth: 10 mm
Name (Model Text:150mm Arial:...) | In
2296296 | 1 Korrus A
2296334 | 1 Korrus A
2296343 | 1 Korrus A
2296352 | 1 Korrus

# IfcBuildingElementProxy: Model Text:150mm Arial italic (6)
Type - Pset_BuildingElementProxyCommon - Reference: 150mm Arial italic
Type - Pset_ProductRequirements - Category: Generic Models
Type - Pset_QuantityTakeOff - Reference: 150mm Arial italic
Pset_BuildingElementProxyCommon - sets with these values: 2
Name (Model Text:150mm Arial italic:...) | In | Shape | Width (mm) | Depth (mm)
2298192 | 2 Korrus | Undefined | 10 | 10
2301050 | 3 korrus | Undefined | 10 | 10
2301223 | Katus | Undefined | 10 | 10
2302366 | 1 Korrus A | Undefined | 5 | 5
2302797 | 2 Korrus A |  |  | 1
2302806 | 3 Korrus A |  |  | 1

# IfcBuildingElementProxy: Model Text:200mm Arial Narrow (2)
In: 3 korrus
Type - Pset_BuildingElementProxyCommon - Reference: 200mm Arial Narrow
Type - Pset_ProductRequirements - Category: Generic Models
Type - Pset_QuantityTakeOff - Reference: 200mm Arial Narrow
Pset_BuildingElementProxyCommon - sets with these values: 2
Pset_ProvisionForVoid - Shape: Undefined; Width: 5 mm; Depth: 5 mm
Name (Model Text:200mm Arial Narrow:...)
2309942
2310032

# IfcBuildingElementProxy: Model Text:25mm Arial bold italic (13)
Type - Pset_BuildingElementProxyCommon - Reference: 25mm Arial bold italic
Type - Pset_ProductRequirements - Category: Generic Models
Type - Pset_QuantityTakeOff - Reference: 25mm Arial bold italic
Pset_BuildingElementProxyCommon - sets with these values: 2
Pset_ProvisionForVoid - Shape: Undefined; Depth: 10 mm
Name (Model Text:25mm Arial bold italic:...) | In | Width (mm) | Height (mm)
2317954 | 1 Korrus | 10 | 4.85838
2318033 | 1 Korrus | 10 | 4.85838
2318050 | 1 Korrus | 4.45351 | 4.85838
2318282 | 1 Korrus | 10 | 9.71676
2319023 | 1 Korrus A | 10
2319024 | 1 Korrus A | 10 | 9.71676
2319025 | 1 Korrus A | 10
2373669 | 1 Korrus A | 10
2373670 | 1 Korrus A | 10 | 9.71676
2373671 | 1 Korrus A | 10
2373728 | 1 Korrus A | 10
2373729 | 1 Korrus A | 10 | 9.71676
2373730 | 1 Korrus A | 10

# IfcBuildingElementProxy: Model Text:300mm Arial (3)
Type - Pset_BuildingElementProxyCommon - Reference: 300mm Arial
Type - Pset_ProductRequirements - Category: Generic Models
Type - Pset_QuantityTakeOff - Reference: 300mm Arial
Pset_BuildingElementProxyCommon - sets with these values: 2
Pset_ProvisionForVoid - Shape: Undefined; Width: 10 mm; Depth: 10 mm
Name (Model Text:300mm Arial:...) | In
2299123 | 1 Korrus A
2301051 | 2 Korrus A
2301224 | 3 Korrus A

# IfcBuildingElementProxy: Model Text:300mm Arial 2 (2)
Type - Pset_BuildingElementProxyCommon - Reference: 300mm Arial 2
Type - Pset_ProductRequirements - Category: Generic Models
Type - Pset_QuantityTakeOff - Reference: 300mm Arial 2
Pset_BuildingElementProxyCommon - sets with these values: 2
Pset_ProvisionForVoid - Shape: Undefined; Height: 58.3005 mm
Name (Model Text:300mm Arial 2:...) | In | Width (mm) = Depth (mm)
1299111 | 2 Korrus | 100
1299348 | 1 Korrus A | 50

# IfcBuildingElementProxy: Model Text:60mm Arial bold italic (4)
Type - Pset_BuildingElementProxyCommon - Reference: 60mm Arial bold italic
Type - Pset_ProductRequirements - Category: Generic Models
Type - Pset_QuantityTakeOff - Reference: 60mm Arial bold italic
Pset_BuildingElementProxyCommon - sets with these values: 2
Pset_ProvisionForVoid - Shape: Undefined; Width: 10 mm; Depth: 10 mm
Name (Model Text:60mm Arial bold italic:...) | In
2299711 | 1 Korrus
2299725 | 1 Korrus
2299735 | 1 Korrus
2300646 | 0 Kelder

# IfcBuildingElementProxy: Model Text:70 mmArial Black (6)
Type - Pset_BuildingElementProxyCommon - Reference: 70 mmArial Black
Type - Pset_ProductRequirements - Category: Generic Models
Type - Pset_QuantityTakeOff - Reference: 70 mmArial Black
Pset_BuildingElementProxyCommon - sets with these values: 2
Pset_ProvisionForVoid - Shape: Undefined
Name (Model Text:70 mmArial Black:...) | In | Width (mm) = Depth (mm)
2318969 | 1 Korrus A | 10
2319014 | 1 Korrus A | 10
2319027 | 1 Korrus A | 10
2319648 | 1 Korrus | 10
2371405 | 3 korrus | 5
2371430 | 3 korrus | 5

# IfcBuildingElementProxy: Model Text:90mm Arial, Model Text:90mm Arial:1304312
In: 1 Korrus A
Type - Pset_BuildingElementProxyCommon - Reference: 90mm Arial
Type - Pset_ProductRequirements - Category: Generic Models
Type - Pset_QuantityTakeOff - Reference: 90mm Arial
Pset_BuildingElementProxyCommon - sets with these values: 2
Pset_ProvisionForVoid - Shape: Undefined; Width: 10 mm; Depth: 10 mm

# IfcBuildingElementProxy: Model Text:90mm Franklin (2)
Type - Pset_BuildingElementProxyCommon - Reference: 90mm Franklin
Type - Pset_ProductRequirements - Category: Generic Models
Type - Pset_QuantityTakeOff - Reference: 90mm Franklin
Pset_BuildingElementProxyCommon - sets with these values: 2
Pset_ProvisionForVoid - Shape: Undefined; Width: 10 mm; Depth: 10 mm
Name (Model Text:90mm Franklin:...) | In
2298156 | 1 Korrus A
2301222 | 3 Korrus A

# IfcBuildingElementProxy: Model Text:90mmArial Black 100mm, Model Text:90mmArial Black 100mm:2301048
In: 2 Korrus A
Type - Pset_BuildingElementProxyCommon - Reference: 90mmArial Black 100mm
Type - Pset_ProductRequirements - Category: Generic Models
Type - Pset_QuantityTakeOff - Reference: 90mmArial Black 100mm
Pset_BuildingElementProxyCommon - sets with these values: 2
Pset_ProvisionForVoid - Shape: Undefined; Width: 10 mm; Depth: 10 mm

# IfcBuildingElementProxy: Reeper:Reeper, Reeper:Reeper:847138
In: 108B
Type - Pset_BuildingElementProxyCommon - Reference: Reeper
Type - Pset_ProductRequirements - Category: Generic Models
Type - Pset_QuantityTakeOff - Reference: Reeper
Pset_BuildingElementProxyCommon - sets with these values: 2
Pset_ProvisionForVoid - Width: 500 mm; Height: 500 mm; Depth: 500 mm

# IfcBuildingElementProxy: Rowing_Machine_10106:Rowing_Machine_10106, Rowing_Machine_10106:Rowing_Machine_10106:2288694
In: 005
Type - Material: Slider
Type - Pset_BuildingElementProxyCommon - Reference: Rowing_Machine_10106
Type - Pset_ProductRequirements - Category: Generic Models
Type - Pset_QuantityTakeOff - Reference: Rowing_Machine_10106
Material: Slider, Casing
Pset_BuildingElementProxyCommon - sets with these values: 2

# IfcBuildingElementProxy: Sony_TV:Sony_TV (6)
Type - Material: base
Type - Pset_BuildingElementProxyCommon - Reference: Sony_TV
Type - Pset_ProductRequirements - Category: Generic Models
Type - Pset_QuantityTakeOff - Reference: Sony_TV
Material: base, Glass, tv, sony, underlining
Pset_BuildingElementProxyCommon - sets with these values: 2
Name (Sony_TV:Sony_TV:...) | In
1129837 | 308
1133886 | 301
1165619 | 208
1165635 | 201
1247972 | 110
1265828 | 001

# IfcBuildingElementProxy: katuse varjestus2:katuse varjestus, katuse varjestus2:katuse varjestus:2278581
In: Katus A
Type - Material: EST. Fassaadikate. Laudis. Horisontaalne. Default(1)
Type - Pset_BuildingElementProxyCommon - Reference: katuse varjestus
Type - Pset_ProductRequirements - Category: Generic Models
Type - Pset_QuantityTakeOff - Reference: katuse varjestus
Pset_BuildingElementProxyCommon - sets with these values: 2
Pset_ProvisionForVoid - Width: 2406.53 mm; Height: 100 mm; Depth: 2406.53 mm

# IfcBuildingElementProxy: katuseredel1:katuseredel, katuseredel1:katuseredel:1352266
In: Katus
Type - Material: __Aken/Uks_hall(1)
Type - Pset_BuildingElementProxyCommon - Reference: katuseredel
Type - Pset_ProductRequirements - Category: Generic Models
Type - Pset_QuantityTakeOff - Reference: katuseredel
Pset_BuildingElementProxyCommon - sets with these values: 2
Pset_ProvisionForVoid - Width: 30 mm; Height: 325 mm; Depth: 30 mm

# IfcBuildingElementProxy: katuseredel3:katuseredel, katuseredel3:katuseredel:1352130
In: Katus
Type - Material: __Aken/Uks_hall(1)
Type - Pset_BuildingElementProxyCommon - Reference: katuseredel
Type - Pset_ProductRequirements - Category: Generic Models
Type - Pset_QuantityTakeOff - Reference: katuseredel
Pset_BuildingElementProxyCommon - sets with these values: 2
Pset_ProvisionForVoid - Width: 30 mm; Height: 325 mm; Depth: 30 mm

# IfcBuildingElementProxy: paneel:paneel (33)
Type - Material: Solar panel
Type - Pset_BuildingElementProxyCommon - Reference: paneel
Type - Pset_ProductRequirements - Category: Generic Models
Type - Pset_QuantityTakeOff - Reference: paneel
Pset_BuildingElementProxyCommon - sets with these values: 2
Name (paneel:paneel:...) | In
1514748 | 301C | Pset_ProvisionForVoid - Width: 1318 mm; Height: 60 mm; Depth: 1318 mm
1514749 | 301C
1514768 | 301B
1514769 | 301B
1514782 | 301B
1514783 | 301B
1514860 | 308D
1514861 | 308D
2174806 | Katus
2174807 | Katus
2174889 | 301A
2174890 | 301A
2175205 | 308D
2175206 | 308D
2175258 | 308C
2175259 | 308C
2175285 | 308B
2175286 | 308B
2175311 | 308B
2175312 | 308B
2175335 | 308A
2175336 | 308A
2243167 | Katus
2243218 | 306A
2243219 | 306A
2243220 | 307
2243243 | 306A
2243244 | 306A
2243245 | 307
2246085 | 308B
2246086 | 308A
2246122 | Katus
2246123 | Katus

# IfcBuildingElementProxy: rippkiik:rippkiik, rippkiik:rippkiik:1244530
In: 110
Type - Material: Fabric rippkiik
Type - Pset_BuildingElementProxyCommon - Reference: rippkiik
Type - Pset_ProductRequirements - Category: Generic Models
Type - Pset_QuantityTakeOff - Reference: rippkiik
Pset_BuildingElementProxyCommon - sets with these values: 2

# IfcCovering: 2249017
In: Katus
Type - PredefinedType: INSULATION
Material: Default Surface 128; Group: Model Group:Katus:2248594
Pset_ProductRequirements - Category: Generic Models

# IfcCovering: 2249019
In: Katus
Type - PredefinedType: INSULATION
Material: Default Surface 128; Group: Model Group:Katus:2248594
Pset_ProductRequirements - Category: Generic Models

# IfcCovering: 2249021
In: Katus
Type - PredefinedType: INSULATION
Material: Default Surface 128; Group: Model Group:Katus:2248594
Pset_ProductRequirements - Category: Generic Models

# IfcCovering: 2249023
In: Katus
Type - PredefinedType: INSULATION
Material: Default Surface 128; Group: Model Group:Katus:2248594
Pset_ProductRequirements - Category: Generic Models

# IfcCovering: 2249025
In: Katus
Type - PredefinedType: INSULATION
Material: Default Surface 128; Group: Model Group:Katus:2248594
Pset_ProductRequirements - Category: Generic Models

# IfcCovering: 2249027
In: Katus
Type - PredefinedType: INSULATION
Material: Default Surface 128; Group: Model Group:Katus:2248594
Pset_ProductRequirements - Category: Generic Models

# IfcCovering: 2249029
In: Katus
Type - PredefinedType: INSULATION
Material: Default Surface 128; Group: Model Group:Katus:2248594
Pset_ProductRequirements - Category: Generic Models

# IfcCovering: 2249031
In: Katus
Type - PredefinedType: INSULATION
Material: Default Surface 128; Group: Model Group:Katus:2248594
Pset_ProductRequirements - Category: Generic Models

# IfcCovering: 2249033
In: Katus
Type - PredefinedType: INSULATION
Material: Default Surface 128; Group: Model Group:Katus:2248594
Pset_ProductRequirements - Category: Generic Models

# IfcCovering: 2249035
In: Katus
Type - PredefinedType: INSULATION
Material: Default Surface 128; Group: Model Group:Katus:2248594
Pset_ProductRequirements - Category: Generic Models

# IfcCovering: 2249037
In: Katus
Type - PredefinedType: INSULATION
Material: Default Surface 128; Group: Model Group:Katus:2248594
Pset_ProductRequirements - Category: Generic Models

# IfcCovering: 2249039
In: Katus
Type - PredefinedType: INSULATION
Material: Default Surface 128; Group: Model Group:Katus:2248594
Pset_ProductRequirements - Category: Generic Models

# IfcCovering: 2249042
In: Katus
Type - PredefinedType: INSULATION
Material: Default Surface 128; Group: Model Group:Katus:2248594
Pset_ProductRequirements - Category: Generic Models

# IfcCovering: 2249044
In: Katus
Type - PredefinedType: INSULATION
Material: Default Surface 128; Group: Model Group:Katus:2248594
Pset_ProductRequirements - Category: Generic Models

# IfcCovering: 2249046
In: Katus
Type - PredefinedType: INSULATION
Material: Default Surface 128; Group: Model Group:Katus:2248594
Pset_ProductRequirements - Category: Generic Models

# IfcCovering: 2249048
In: Katus
Type - PredefinedType: INSULATION
Material: Default Surface 128; Group: Model Group:Katus:2248594
Pset_ProductRequirements - Category: Generic Models

# IfcCovering: 2249050
In: Katus
Type - PredefinedType: INSULATION
Material: Default Surface 128; Group: Model Group:Katus:2248594
Pset_ProductRequirements - Category: Generic Models

# IfcCovering: 2249052
In: Katus
Type - PredefinedType: INSULATION
Material: Default Surface 128; Group: Model Group:Katus:2248594
Pset_ProductRequirements - Category: Generic Models

# IfcCovering: 2249054
In: Katus
Type - PredefinedType: INSULATION
Material: Default Surface 128; Group: Model Group:Katus:2248594
Pset_ProductRequirements - Category: Generic Models

# IfcCovering: 2249056
In: Katus
Type - PredefinedType: INSULATION
Material: Default Surface 128; Group: Model Group:Katus:2248594
Pset_ProductRequirements - Category: Generic Models

# IfcCovering: 2249058
In: Katus
Type - PredefinedType: INSULATION
Material: Default Surface 128; Group: Model Group:Katus:2248594
Pset_ProductRequirements - Category: Generic Models

# IfcCovering: 2249060
In: Katus
Type - PredefinedType: INSULATION
Material: Default Surface 128; Group: Model Group:Katus:2248594
Pset_ProductRequirements - Category: Generic Models

# IfcCovering: 2249062
In: Katus
Type - PredefinedType: INSULATION
Material: Default Surface 128; Group: Model Group:Katus:2248594
Pset_ProductRequirements - Category: Generic Models

# IfcCovering: 2249064
In: Katus
Type - PredefinedType: INSULATION
Material: Default Surface 128; Group: Model Group:Katus:2248594
Pset_ProductRequirements - Category: Generic Models

# IfcCovering: 2249066
In: Katus
Type - PredefinedType: INSULATION
Material: Default Surface 128; Group: Model Group:Katus:2248594
Pset_ProductRequirements - Category: Generic Models

# IfcCovering: 2249068
In: Katus
Type - PredefinedType: INSULATION
Material: Default Surface 128; Group: Model Group:Katus:2248594
Pset_ProductRequirements - Category: Generic Models

# IfcCovering: 2249070
In: Katus
Type - PredefinedType: INSULATION
Material: Default Surface 128; Group: Model Group:Katus:2248594
Pset_ProductRequirements - Category: Generic Models

# IfcCovering: 2249072
In: Katus
Type - PredefinedType: INSULATION
Material: Default Surface 128; Group: Model Group:Katus:2248594
Pset_ProductRequirements - Category: Generic Models

# IfcCovering: 2249074
In: Katus
Type - PredefinedType: INSULATION
Material: Default Surface 128; Group: Model Group:Katus:2248594
Pset_ProductRequirements - Category: Generic Models

# IfcCovering: 2249076
In: Katus
Type - PredefinedType: INSULATION
Material: Default Surface 128; Group: Model Group:Katus:2248594
Pset_ProductRequirements - Category: Generic Models

# IfcCovering: 2249078
In: Katus
Type - PredefinedType: INSULATION
Material: Default Surface 128; Group: Model Group:Katus:2248594
Pset_ProductRequirements - Category: Generic Models

# IfcCovering: 2249080
In: Katus
Type - PredefinedType: INSULATION
Material: Default Surface 128; Group: Model Group:Katus:2248594
Pset_ProductRequirements - Category: Generic Models

# IfcCovering: 2249082
In: Katus
Type - PredefinedType: INSULATION
Material: Default Surface 128; Group: Model Group:Katus:2248594
Pset_ProductRequirements - Category: Generic Models

# IfcCovering: 2249085
In: Katus
Type - PredefinedType: INSULATION
Material: Default Surface 128; Group: Model Group:Katus:2248594
Pset_ProductRequirements - Category: Generic Models

# IfcCovering: 2249087
In: Katus
Type - PredefinedType: INSULATION
Material: Default Surface 128; Group: Model Group:Katus:2248594
Pset_ProductRequirements - Category: Generic Models

# IfcCovering: 2249089
In: Katus
Type - PredefinedType: INSULATION
Material: Default Surface 128; Group: Model Group:Katus:2248594
Pset_ProductRequirements - Category: Generic Models

# IfcCovering: 2249092
In: Katus
Type - PredefinedType: INSULATION
Material: Default Surface 128; Group: Model Group:Katus:2248594
Pset_ProductRequirements - Category: Generic Models

# IfcCovering: 2249094
In: Katus
Type - PredefinedType: INSULATION
Material: Default Surface 128; Group: Model Group:Katus:2248594
Pset_ProductRequirements - Category: Generic Models

# IfcCovering: 2249096
In: Katus
Type - PredefinedType: INSULATION
Material: Default Surface 128; Group: Model Group:Katus:2248594
Pset_ProductRequirements - Category: Generic Models

# IfcCovering: 2249098
In: Katus
Type - PredefinedType: INSULATION
Material: Default Surface 128; Group: Model Group:Katus:2248594
Pset_ProductRequirements - Category: Generic Models

# IfcCovering: 2249100
In: Katus
Type - PredefinedType: INSULATION
Material: Default Surface 128; Group: Model Group:Katus:2248594
Pset_ProductRequirements - Category: Generic Models

# IfcCovering: 2249102
In: Katus
Type - PredefinedType: INSULATION
Material: Default Surface 128; Group: Model Group:Katus:2248594
Pset_ProductRequirements - Category: Generic Models

# IfcCovering: 2249104
In: Katus
Type - PredefinedType: INSULATION
Material: Default Surface 128; Group: Model Group:Katus:2248594
Pset_ProductRequirements - Category: Generic Models

# IfcCovering: 2249106
In: Katus
Type - PredefinedType: INSULATION
Material: Default Surface 128; Group: Model Group:Katus:2248594
Pset_ProductRequirements - Category: Generic Models

# IfcCovering: 2249108
In: Katus
Type - PredefinedType: INSULATION
Material: Default Surface 128; Group: Model Group:Katus:2248594
Pset_ProductRequirements - Category: Generic Models

# IfcCovering: 2249110
In: Katus
Type - PredefinedType: INSULATION
Material: Default Surface 128; Group: Model Group:Katus:2248594
Pset_ProductRequirements - Category: Generic Models

# IfcCovering: 2249112
In: Katus
Type - PredefinedType: INSULATION
Material: Default Surface 128; Group: Model Group:Katus:2248594
Pset_ProductRequirements - Category: Generic Models

# IfcCovering: 2249114
In: Katus
Type - PredefinedType: INSULATION
Material: Default Surface 128; Group: Model Group:Katus:2248594
Pset_ProductRequirements - Category: Generic Models

# IfcCovering: 2249116
In: Katus
Type - PredefinedType: INSULATION
Material: Default Surface 128; Group: Model Group:Katus:2248594
Pset_ProductRequirements - Category: Generic Models

# IfcCovering: 2249118
In: Katus
Type - PredefinedType: INSULATION
Material: Default Surface 128; Group: Model Group:Katus:2248594
Pset_ProductRequirements - Category: Generic Models

# IfcCovering: 2249120
In: Katus
Type - PredefinedType: INSULATION
Material: Default Surface 128; Group: Model Group:Katus:2248594
Pset_ProductRequirements - Category: Generic Models

# IfcCovering: 2249122
In: Katus
Type - PredefinedType: INSULATION
Material: Default Surface 128; Group: Model Group:Katus:2248594
Pset_ProductRequirements - Category: Generic Models

# IfcCovering: 2249124
In: Katus
Type - PredefinedType: INSULATION
Material: Default Surface 128; Group: Model Group:Katus:2248594
Pset_ProductRequirements - Category: Generic Models

# IfcCovering: 2249126
In: Katus
Type - PredefinedType: INSULATION
Material: Default Surface 128; Group: Model Group:Katus:2248594
Pset_ProductRequirements - Category: Generic Models

# IfcCovering: 2249128
In: Katus
Type - PredefinedType: INSULATION
Material: Default Surface 128; Group: Model Group:Katus:2248594
Pset_ProductRequirements - Category: Generic Models

# IfcCovering: 2249130
In: Katus
Type - PredefinedType: INSULATION
Material: Default Surface 128; Group: Model Group:Katus:2248594
Pset_ProductRequirements - Category: Generic Models

# IfcCovering: 2249132
In: Katus
Type - PredefinedType: INSULATION
Material: Default Surface 128; Group: Model Group:Katus:2248594
Pset_ProductRequirements - Category: Generic Models

# IfcCovering: 2249134
In: Katus
Type - PredefinedType: INSULATION
Material: Default Surface 128; Group: Model Group:Katus:2248594
Pset_ProductRequirements - Category: Generic Models

# IfcCovering: 2249136
In: Katus
Type - PredefinedType: INSULATION
Material: Default Surface 128; Group: Model Group:Katus:2248594
Pset_ProductRequirements - Category: Generic Models

# IfcCovering: 2249138
In: Katus
Type - PredefinedType: INSULATION
Material: Default Surface 128; Group: Model Group:Katus:2248594
Pset_ProductRequirements - Category: Generic Models

# IfcCovering: 2249140
In: Katus
Type - PredefinedType: INSULATION
Material: Default Surface 128; Group: Model Group:Katus:2248594
Pset_ProductRequirements - Category: Generic Models

# IfcCovering: 2249142
In: Katus
Type - PredefinedType: INSULATION
Material: Default Surface 128; Group: Model Group:Katus:2248594
Pset_ProductRequirements - Category: Generic Models

# IfcCovering: 2249144
In: Katus
Type - PredefinedType: INSULATION
Material: Default Surface 128; Group: Model Group:Katus:2248594
Pset_ProductRequirements - Category: Generic Models

# IfcCovering: 2249146
In: Katus
Type - PredefinedType: INSULATION
Material: Default Surface 128; Group: Model Group:Katus:2248594
Pset_ProductRequirements - Category: Generic Models

# IfcCovering: 2249148
In: Katus
Type - PredefinedType: INSULATION
Material: Default Surface 128; Group: Model Group:Katus:2248594
Pset_ProductRequirements - Category: Generic Models

# IfcCovering: 2249150
In: Katus
Type - PredefinedType: INSULATION
Material: Default Surface 128; Group: Model Group:Katus:2248594
Pset_ProductRequirements - Category: Generic Models

# IfcCovering: 2249152
In: Katus
Type - PredefinedType: INSULATION
Material: Default Surface 128; Group: Model Group:Katus:2248594
Pset_ProductRequirements - Category: Generic Models

# IfcCovering: 2249154
In: Katus
Type - PredefinedType: INSULATION
Material: Default Surface 128; Group: Model Group:Katus:2248594
Pset_ProductRequirements - Category: Generic Models

# IfcCovering: 2249156
In: Katus
Type - PredefinedType: INSULATION
Material: Default Surface 128; Group: Model Group:Katus:2248594
Pset_ProductRequirements - Category: Generic Models

# IfcCovering: 2249158
In: Katus
Type - PredefinedType: INSULATION
Material: Default Surface 128; Group: Model Group:Katus:2248594
Pset_ProductRequirements - Category: Generic Models

# IfcCovering: 2249160
In: Katus
Type - PredefinedType: INSULATION
Material: Default Surface 128; Group: Model Group:Katus:2248594
Pset_ProductRequirements - Category: Generic Models

# IfcCovering: 2249162
In: Katus
Type - PredefinedType: INSULATION
Material: Default Surface 128; Group: Model Group:Katus:2248594
Pset_ProductRequirements - Category: Generic Models

# IfcCovering: 2249164
In: Katus
Type - PredefinedType: INSULATION
Material: Default Surface 128; Group: Model Group:Katus:2248594
Pset_ProductRequirements - Category: Generic Models

# IfcCovering: 2249166
In: Katus
Type - PredefinedType: INSULATION
Material: Default Surface 128; Group: Model Group:Katus:2248594
Pset_ProductRequirements - Category: Generic Models

# IfcCovering: 2249168
In: Katus
Type - PredefinedType: INSULATION
Material: Default Surface 128; Group: Model Group:Katus:2248594
Pset_ProductRequirements - Category: Generic Models

# IfcCovering: 2249170
In: Katus
Type - PredefinedType: INSULATION
Material: Default Surface 128; Group: Model Group:Katus:2248594
Pset_ProductRequirements - Category: Generic Models

# IfcCovering: 2249172
In: Katus
Type - PredefinedType: INSULATION
Material: Default Surface 128; Group: Model Group:Katus:2248594
Pset_ProductRequirements - Category: Generic Models

# IfcCovering: 2249174
In: Katus
Type - PredefinedType: INSULATION
Material: Default Surface 128; Group: Model Group:Katus:2248594
Pset_ProductRequirements - Category: Generic Models

# IfcCovering: 2249176
In: Katus
Type - PredefinedType: INSULATION
Material: Default Surface 128; Group: Model Group:Katus:2248594
Pset_ProductRequirements - Category: Generic Models

# IfcCovering: 2249178
In: Katus
Type - PredefinedType: INSULATION
Material: Default Surface 128; Group: Model Group:Katus:2248594
Pset_ProductRequirements - Category: Generic Models

# IfcCovering: 2249180
In: Katus
Type - PredefinedType: INSULATION
Material: Default Surface 128; Group: Model Group:Katus:2248594
Pset_ProductRequirements - Category: Generic Models

# IfcCovering: 2249182
In: Katus
Type - PredefinedType: INSULATION
Material: Default Surface 128; Group: Model Group:Katus:2248594
Pset_ProductRequirements - Category: Generic Models

# IfcCovering: 2249184
In: Katus
Type - PredefinedType: INSULATION
Material: Default Surface 128; Group: Model Group:Katus:2248594
Pset_ProductRequirements - Category: Generic Models

# IfcCovering: 2249186
In: Katus
Type - PredefinedType: INSULATION
Material: Default Surface 128; Group: Model Group:Katus:2248594
Pset_ProductRequirements - Category: Generic Models

# IfcCovering: 2249188
In: Katus
Type - PredefinedType: INSULATION
Material: Default Surface 128; Group: Model Group:Katus:2248594
Pset_ProductRequirements - Category: Generic Models

# IfcCovering: 2249190
In: Katus
Type - PredefinedType: INSULATION
Material: Default Surface 128; Group: Model Group:Katus:2248594
Pset_ProductRequirements - Category: Generic Models

# IfcCovering: 2249192
In: Katus
Type - PredefinedType: INSULATION
Material: Default Surface 128; Group: Model Group:Katus:2248594
Pset_ProductRequirements - Category: Generic Models

# IfcCovering: 2249194
In: Katus
Type - PredefinedType: INSULATION
Material: Default Surface 128; Group: Model Group:Katus:2248594
Pset_ProductRequirements - Category: Generic Models

# IfcCovering: 2249196
In: Katus
Type - PredefinedType: INSULATION
Material: Default Surface 128; Group: Model Group:Katus:2248594
Pset_ProductRequirements - Category: Generic Models

# IfcCovering: 2249198
In: Katus
Type - PredefinedType: INSULATION
Material: Default Surface 128; Group: Model Group:Katus:2248594
Pset_ProductRequirements - Category: Generic Models

# IfcCovering: 2249200
In: Katus
Type - PredefinedType: INSULATION
Material: Default Surface 128; Group: Model Group:Katus:2248594
Pset_ProductRequirements - Category: Generic Models

# IfcCovering: 2249202
In: Katus
Type - PredefinedType: INSULATION
Material: Default Surface 128; Group: Model Group:Katus:2248594
Pset_ProductRequirements - Category: Generic Models

# IfcCovering: 2249204
In: Katus
Type - PredefinedType: INSULATION
Material: Default Surface 128; Group: Model Group:Katus:2248594
Pset_ProductRequirements - Category: Generic Models

# IfcCovering: 2249206
In: Katus
Type - PredefinedType: INSULATION
Material: Default Surface 128; Group: Model Group:Katus:2248594
Pset_ProductRequirements - Category: Generic Models

# IfcCovering: 2249208
In: Katus
Type - PredefinedType: INSULATION
Material: Default Surface 128; Group: Model Group:Katus:2248594
Pset_ProductRequirements - Category: Generic Models

# IfcCovering: 2249210
In: Katus
Type - PredefinedType: INSULATION
Material: Default Surface 128; Group: Model Group:Katus:2248594
Pset_ProductRequirements - Category: Generic Models

# IfcCovering: 2249212
In: Katus
Type - PredefinedType: INSULATION
Material: Default Surface 128; Group: Model Group:Katus:2248594
Pset_ProductRequirements - Category: Generic Models

# IfcCovering: 2249214
In: Katus
Type - PredefinedType: INSULATION
Material: Default Surface 128; Group: Model Group:Katus:2248594
Pset_ProductRequirements - Category: Generic Models

# IfcCovering: 2249216
In: Katus
Type - PredefinedType: INSULATION
Material: Default Surface 128; Group: Model Group:Katus:2248594
Pset_ProductRequirements - Category: Generic Models

# IfcCovering: 2249219
In: Katus
Type - PredefinedType: INSULATION
Material: Default Surface 128; Group: Model Group:Katus:2248594
Pset_ProductRequirements - Category: Generic Models

# IfcCovering: 2249221
In: Katus
Type - PredefinedType: INSULATION
Material: Default Surface 128; Group: Model Group:Katus:2248594
Pset_ProductRequirements - Category: Generic Models

# IfcCovering: 2249223
In: Katus
Type - PredefinedType: INSULATION
Material: Default Surface 128; Group: Model Group:Katus:2248594
Pset_ProductRequirements - Category: Generic Models

# IfcCovering: 2249225
In: Katus
Type - PredefinedType: INSULATION
Material: Default Surface 128; Group: Model Group:Katus:2248594
Pset_ProductRequirements - Category: Generic Models

# IfcCovering: 2249227
In: Katus
Type - PredefinedType: INSULATION
Material: Default Surface 128; Group: Model Group:Katus:2248594
Pset_ProductRequirements - Category: Generic Models

# IfcCovering: 2249229
In: Katus
Type - PredefinedType: INSULATION
Material: Default Surface 128; Group: Model Group:Katus:2248594
Pset_ProductRequirements - Category: Generic Models

# IfcCovering: 2249231
In: Katus
Type - PredefinedType: INSULATION
Material: Default Surface 128; Group: Model Group:Katus:2248594
Pset_ProductRequirements - Category: Generic Models

# IfcCovering: 2249233
In: Katus
Type - PredefinedType: INSULATION
Material: Default Surface 128; Group: Model Group:Katus:2248594
Pset_ProductRequirements - Category: Generic Models

# IfcCovering: 2249235
In: Katus
Type - PredefinedType: INSULATION
Material: Default Surface 128; Group: Model Group:Katus:2248594
Pset_ProductRequirements - Category: Generic Models

# IfcCovering: 2249237
In: Katus
Type - PredefinedType: INSULATION
Material: Default Surface 128; Group: Model Group:Katus:2248594
Pset_ProductRequirements - Category: Generic Models

# IfcCovering: 2249239
In: Katus
Type - PredefinedType: INSULATION
Material: Default Surface 128; Group: Model Group:Katus:2248594
Pset_ProductRequirements - Category: Generic Models

# IfcCovering: 2249241
In: Katus
Type - PredefinedType: INSULATION
Material: Default Surface 128; Group: Model Group:Katus:2248594
Pset_ProductRequirements - Category: Generic Models

# IfcCovering: 2249243
In: Katus
Type - PredefinedType: INSULATION
Material: Default Surface 128; Group: Model Group:Katus:2248594
Pset_ProductRequirements - Category: Generic Models

# IfcCovering: 2249245
In: Katus
Type - PredefinedType: INSULATION
Material: Default Surface 128; Group: Model Group:Katus:2248594
Pset_ProductRequirements - Category: Generic Models

# IfcCovering: 2249247
In: Katus
Type - PredefinedType: INSULATION
Material: Default Surface 128; Group: Model Group:Katus:2248594
Pset_ProductRequirements - Category: Generic Models

# IfcCovering: 2249249
In: Katus
Type - PredefinedType: INSULATION
Material: Default Surface 128; Group: Model Group:Katus:2248594
Pset_ProductRequirements - Category: Generic Models

# IfcCovering: 2249251
In: Katus
Type - PredefinedType: INSULATION
Material: Default Surface 128; Group: Model Group:Katus:2248594
Pset_ProductRequirements - Category: Generic Models

# IfcCovering: 2249253
In: Katus
Type - PredefinedType: INSULATION
Material: Default Surface 128; Group: Model Group:Katus:2248594
Pset_ProductRequirements - Category: Generic Models

# IfcCovering: 2249255
In: Katus
Type - PredefinedType: INSULATION
Material: Default Surface 128; Group: Model Group:Katus:2248594
Pset_ProductRequirements - Category: Generic Models

# IfcCovering: 2249257
In: Katus
Type - PredefinedType: INSULATION
Material: Default Surface 128; Group: Model Group:Katus:2248594
Pset_ProductRequirements - Category: Generic Models

# IfcCovering: 2249259
In: Katus
Type - PredefinedType: INSULATION
Material: Default Surface 128; Group: Model Group:Katus:2248594
Pset_ProductRequirements - Category: Generic Models

# IfcCovering: 2249261
In: Katus
Type - PredefinedType: INSULATION
Material: Default Surface 128; Group: Model Group:Katus:2248594
Pset_ProductRequirements - Category: Generic Models

# IfcCovering: 2249263
In: Katus
Type - PredefinedType: INSULATION
Material: Default Surface 128; Group: Model Group:Katus:2248594
Pset_ProductRequirements - Category: Generic Models

# IfcCovering: 2249265
In: Katus
Type - PredefinedType: INSULATION
Material: Default Surface 128; Group: Model Group:Katus:2248594
Pset_ProductRequirements - Category: Generic Models

# IfcCovering: 2249267
In: Katus
Type - PredefinedType: INSULATION
Material: Default Surface 128; Group: Model Group:Katus:2248594
Pset_ProductRequirements - Category: Generic Models

# IfcCovering: 2249270
In: Katus
Type - PredefinedType: INSULATION
Material: Default Surface 128; Group: Model Group:Katus:2248594
Pset_ProductRequirements - Category: Generic Models

# IfcCovering: 2249272
In: Katus
Type - PredefinedType: INSULATION
Material: Default Surface 128; Group: Model Group:Katus:2248594
Pset_ProductRequirements - Category: Generic Models

# IfcCovering: 2249274
In: Katus
Type - PredefinedType: INSULATION
Material: Default Surface 128; Group: Model Group:Katus:2248594
Pset_ProductRequirements - Category: Generic Models

# IfcCovering: 2249276
In: Katus
Type - PredefinedType: INSULATION
Material: Default Surface 128; Group: Model Group:Katus:2248594
Pset_ProductRequirements - Category: Generic Models

# IfcCovering: 2249278
In: Katus
Type - PredefinedType: INSULATION
Material: Default Surface 128; Group: Model Group:Katus:2248594
Pset_ProductRequirements - Category: Generic Models

# IfcCovering: 2249280
In: Katus
Type - PredefinedType: INSULATION
Material: Default Surface 128; Group: Model Group:Katus:2248594
Pset_ProductRequirements - Category: Generic Models

# IfcCovering: 2249282
In: Katus
Type - PredefinedType: INSULATION
Material: Default Surface 128; Group: Model Group:Katus:2248594
Pset_ProductRequirements - Category: Generic Models

# IfcCovering: 2249284
In: Katus
Type - PredefinedType: INSULATION
Material: Default Surface 128; Group: Model Group:Katus:2248594
Pset_ProductRequirements - Category: Generic Models

# IfcCovering: 2249286
In: Katus
Type - PredefinedType: INSULATION
Material: Default Surface 128; Group: Model Group:Katus:2248594
Pset_ProductRequirements - Category: Generic Models

# IfcCovering: 2249288
In: Katus
Type - PredefinedType: INSULATION
Material: Default Surface 128; Group: Model Group:Katus:2248594
Pset_ProductRequirements - Category: Generic Models

# IfcCovering: 2249290
In: Katus
Type - PredefinedType: INSULATION
Material: Default Surface 128; Group: Model Group:Katus:2248594
Pset_ProductRequirements - Category: Generic Models

# IfcCovering: 2249292
In: Katus
Type - PredefinedType: INSULATION
Material: Default Surface 128; Group: Model Group:Katus:2248594
Pset_ProductRequirements - Category: Generic Models

# IfcCovering: 2249294
In: Katus
Type - PredefinedType: INSULATION
Material: Default Surface 128; Group: Model Group:Katus:2248594
Pset_ProductRequirements - Category: Generic Models

# IfcCovering: 2249298
In: Katus
Type - PredefinedType: INSULATION
Material: Default Surface 128; Group: Model Group:Katus:2248594
Pset_ProductRequirements - Category: Generic Models

# IfcCovering: 2249300
In: Katus
Type - PredefinedType: INSULATION
Material: Default Surface 128; Group: Model Group:Katus:2248594
Pset_ProductRequirements - Category: Generic Models

# IfcCovering: 2249302
In: Katus
Type - PredefinedType: INSULATION
Material: Default Surface 128; Group: Model Group:Katus:2248594
Pset_ProductRequirements - Category: Generic Models

# IfcCovering: 2249304
In: Katus
Type - PredefinedType: INSULATION
Material: Default Surface 128; Group: Model Group:Katus:2248594
Pset_ProductRequirements - Category: Generic Models

# IfcCovering: 2249307
In: Katus
Type - PredefinedType: INSULATION
Material: Default Surface 128; Group: Model Group:Katus:2248594
Pset_ProductRequirements - Category: Generic Models

# IfcCovering: 2249309
In: Katus
Type - PredefinedType: INSULATION
Material: Default Surface 128; Group: Model Group:Katus:2248594
Pset_ProductRequirements - Category: Generic Models

# IfcCovering: 2249311
In: Katus
Type - PredefinedType: INSULATION
Material: Default Surface 128; Group: Model Group:Katus:2248594
Pset_ProductRequirements - Category: Generic Models

# IfcCovering: 2249313
In: Katus
Type - PredefinedType: INSULATION
Material: Default Surface 128; Group: Model Group:Katus:2248594
Pset_ProductRequirements - Category: Generic Models

# IfcCovering: 2249315
In: Katus
Type - PredefinedType: INSULATION
Material: Default Surface 128; Group: Model Group:Katus:2248594
Pset_ProductRequirements - Category: Generic Models

# IfcCovering: 2249317
In: Katus
Type - PredefinedType: INSULATION
Material: Default Surface 128; Group: Model Group:Katus:2248594
Pset_ProductRequirements - Category: Generic Models

# IfcCovering: 2249319
In: Katus
Type - PredefinedType: INSULATION
Material: Default Surface 128; Group: Model Group:Katus:2248594
Pset_ProductRequirements - Category: Generic Models

# IfcCovering: 2249321
In: Katus
Type - PredefinedType: INSULATION
Material: Default Surface 128; Group: Model Group:Katus:2248594
Pset_ProductRequirements - Category: Generic Models

# IfcCovering: 2249323
In: Katus
Type - PredefinedType: INSULATION
Material: Default Surface 128; Group: Model Group:Katus:2248594
Pset_ProductRequirements - Category: Generic Models

# IfcCovering: 2249325
In: Katus
Type - PredefinedType: INSULATION
Material: Default Surface 128; Group: Model Group:Katus:2248594
Pset_ProductRequirements - Category: Generic Models

# IfcCovering: 2249327
In: Katus
Type - PredefinedType: INSULATION
Material: Default Surface 128; Group: Model Group:Katus:2248594
Pset_ProductRequirements - Category: Generic Models

# IfcCovering: 2249329
In: Katus
Type - PredefinedType: INSULATION
Material: Default Surface 128; Group: Model Group:Katus:2248594
Pset_ProductRequirements - Category: Generic Models

# IfcCovering: 2249331
In: Katus
Type - PredefinedType: INSULATION
Material: Default Surface 128; Group: Model Group:Katus:2248594
Pset_ProductRequirements - Category: Generic Models

# IfcCovering: 2249333
In: Katus
Type - PredefinedType: INSULATION
Material: Default Surface 128; Group: Model Group:Katus:2248594
Pset_ProductRequirements - Category: Generic Models

# IfcCovering: 2249335
In: Katus
Type - PredefinedType: INSULATION
Material: Default Surface 128; Group: Model Group:Katus:2248594
Pset_ProductRequirements - Category: Generic Models

# IfcCovering: 2249338
In: Katus
Type - PredefinedType: INSULATION
Material: Default Surface 128; Group: Model Group:Katus:2248594
Pset_ProductRequirements - Category: Generic Models

# IfcCovering: 2249340
In: Katus
Type - PredefinedType: INSULATION
Material: Default Surface 128; Group: Model Group:Katus:2248594
Pset_ProductRequirements - Category: Generic Models

# IfcCovering: 2249342
In: Katus
Type - PredefinedType: INSULATION
Material: Default Surface 128; Group: Model Group:Katus:2248594
Pset_ProductRequirements - Category: Generic Models

# IfcCovering: 2249346
In: Katus
Type - PredefinedType: INSULATION
Material: Default Surface 128; Group: Model Group:Katus:2248594
Pset_ProductRequirements - Category: Generic Models

# IfcCovering: 2249348
In: Katus
Type - PredefinedType: INSULATION
Material: Default Surface 128; Group: Model Group:Katus:2248594
Pset_ProductRequirements - Category: Generic Models

# IfcCovering: 2249350
In: Katus
Type - PredefinedType: INSULATION
Material: Default Surface 128; Group: Model Group:Katus:2248594
Pset_ProductRequirements - Category: Generic Models

# IfcCovering: 2249352
In: Katus
Type - PredefinedType: INSULATION
Material: Default Surface 128; Group: Model Group:Katus:2248594
Pset_ProductRequirements - Category: Generic Models

# IfcCovering: 2249354
In: Katus
Type - PredefinedType: INSULATION
Material: Default Surface 128; Group: Model Group:Katus:2248594
Pset_ProductRequirements - Category: Generic Models

# IfcCovering: 2249356
In: Katus
Type - PredefinedType: INSULATION
Material: Default Surface 128; Group: Model Group:Katus:2248594
Pset_ProductRequirements - Category: Generic Models

# IfcCovering: 2249358
In: Katus
Type - PredefinedType: INSULATION
Material: Default Surface 128; Group: Model Group:Katus:2248594
Pset_ProductRequirements - Category: Generic Models

# IfcCovering: 2249360
In: Katus
Type - PredefinedType: INSULATION
Material: Default Surface 128; Group: Model Group:Katus:2248594
Pset_ProductRequirements - Category: Generic Models

# IfcCovering: 2249363
In: Katus
Type - PredefinedType: INSULATION
Material: Default Surface 128; Group: Model Group:Katus:2248594
Pset_ProductRequirements - Category: Generic Models

# IfcCovering: 2249366
In: Katus
Type - PredefinedType: INSULATION
Material: Default Surface 128; Group: Model Group:Katus:2248594
Pset_ProductRequirements - Category: Generic Models

# IfcCovering: 2249368
In: Katus
Type - PredefinedType: INSULATION
Material: Default Surface 128; Group: Model Group:Katus:2248594
Pset_ProductRequirements - Category: Generic Models

# IfcCovering: 2249370
In: Katus
Type - PredefinedType: INSULATION
Material: Default Surface 128; Group: Model Group:Katus:2248594
Pset_ProductRequirements - Category: Generic Models

# IfcCovering: 2249372
In: Katus
Type - PredefinedType: INSULATION
Material: Default Surface 128; Group: Model Group:Katus:2248594
Pset_ProductRequirements - Category: Generic Models

# IfcCovering: 2249374
In: Katus
Type - PredefinedType: INSULATION
Material: Default Surface 128; Group: Model Group:Katus:2248594
Pset_ProductRequirements - Category: Generic Models

# IfcCovering: 2249376
In: Katus
Type - PredefinedType: INSULATION
Material: Default Surface 128; Group: Model Group:Katus:2248594
Pset_ProductRequirements - Category: Generic Models

# IfcCovering: 2249378
In: Katus
Type - PredefinedType: INSULATION
Material: Default Surface 128; Group: Model Group:Katus:2248594
Pset_ProductRequirements - Category: Generic Models

# IfcCovering: 2249380
In: Katus
Type - PredefinedType: INSULATION
Material: Default Surface 128; Group: Model Group:Katus:2248594
Pset_ProductRequirements - Category: Generic Models

# IfcCovering: 2249382
In: Katus
Type - PredefinedType: INSULATION
Material: Default Surface 128; Group: Model Group:Katus:2248594
Pset_ProductRequirements - Category: Generic Models

# IfcCovering: 2249385
In: Katus
Type - PredefinedType: INSULATION
Material: Default Surface 128; Group: Model Group:Katus:2248594
Pset_ProductRequirements - Category: Generic Models

# IfcCovering: 2249387
In: Katus
Type - PredefinedType: INSULATION
Material: Default Surface 128; Group: Model Group:Katus:2248594
Pset_ProductRequirements - Category: Generic Models

# IfcCovering: 2249391
In: Katus
Type - PredefinedType: INSULATION
Material: Default Surface 128; Group: Model Group:Katus:2248594
Pset_ProductRequirements - Category: Generic Models

# IfcCovering: 2249393
In: Katus
Type - PredefinedType: INSULATION
Material: Default Surface 128; Group: Model Group:Katus:2248594
Pset_ProductRequirements - Category: Generic Models

# IfcCovering: 2249397
In: Katus
Type - PredefinedType: INSULATION
Material: Default Surface 128; Group: Model Group:Katus:2248594
Pset_ProductRequirements - Category: Generic Models

# IfcCovering: 2249399
In: Katus
Type - PredefinedType: INSULATION
Material: Default Surface 128; Group: Model Group:Katus:2248594
Pset_ProductRequirements - Category: Generic Models

# IfcCovering: 2249401
In: Katus
Type - PredefinedType: INSULATION
Material: Default Surface 128; Group: Model Group:Katus:2248594
Pset_ProductRequirements - Category: Generic Models

# IfcCovering: 2249403
In: Katus
Type - PredefinedType: INSULATION
Material: Default Surface 128; Group: Model Group:Katus:2248594
Pset_ProductRequirements - Category: Generic Models

# IfcCovering: 2249405
In: Katus
Type - PredefinedType: INSULATION
Material: Default Surface 128; Group: Model Group:Katus:2248594
Pset_ProductRequirements - Category: Generic Models

# IfcCovering: 2249407
In: Katus
Type - PredefinedType: INSULATION
Material: Default Surface 128; Group: Model Group:Katus:2248594
Pset_ProductRequirements - Category: Generic Models

# IfcCovering: 2249409
In: Katus
Type - PredefinedType: INSULATION
Material: Default Surface 128; Group: Model Group:Katus:2248594
Pset_ProductRequirements - Category: Generic Models

# IfcCovering: 2249411
In: Katus
Type - PredefinedType: INSULATION
Material: Default Surface 128; Group: Model Group:Katus:2248594
Pset_ProductRequirements - Category: Generic Models

# IfcCovering: 2249413
In: Katus
Type - PredefinedType: INSULATION
Material: Default Surface 128; Group: Model Group:Katus:2248594
Pset_ProductRequirements - Category: Generic Models

# IfcCovering: 2249415
In: Katus
Type - PredefinedType: INSULATION
Material: Default Surface 128; Group: Model Group:Katus:2248594
Pset_ProductRequirements - Category: Generic Models

# IfcCovering: 2249417
In: Katus
Type - PredefinedType: INSULATION
Material: Default Surface 128; Group: Model Group:Katus:2248594
Pset_ProductRequirements - Category: Generic Models

# IfcCovering: 2249419
In: Katus
Type - PredefinedType: INSULATION
Material: Default Surface 128; Group: Model Group:Katus:2248594
Pset_ProductRequirements - Category: Generic Models

# IfcCovering: 2249421
In: Katus
Type - PredefinedType: INSULATION
Material: Default Surface 128; Group: Model Group:Katus:2248594
Pset_ProductRequirements - Category: Generic Models

# IfcCovering: 2249425
In: Katus
Type - PredefinedType: INSULATION
Material: Default Surface 128; Group: Model Group:Katus:2248594
Pset_ProductRequirements - Category: Generic Models

# IfcCovering: 2249428
In: Katus
Type - PredefinedType: INSULATION
Material: Default Surface 128; Group: Model Group:Katus:2248594
Pset_ProductRequirements - Category: Generic Models

# IfcCovering: 2249432
In: Katus
Type - PredefinedType: INSULATION
Material: Default Surface 128; Group: Model Group:Katus:2248594
Pset_ProductRequirements - Category: Generic Models

# IfcCovering: 2249434
In: Katus
Type - PredefinedType: INSULATION
Material: Default Surface 128; Group: Model Group:Katus:2248594
Pset_ProductRequirements - Category: Generic Models

# IfcCovering: 2249436
In: Katus
Type - PredefinedType: INSULATION
Material: Default Surface 128; Group: Model Group:Katus:2248594
Pset_ProductRequirements - Category: Generic Models

# IfcCovering: Compound Ceiling:600 x 600mm (59)
Type - PredefinedType: CEILING
Type - Pset_CoveringCommon - Reference: 600 x 600mm; TotalThickness: 52 mm
Type - Pset_ElementShading - Roughness: 914.4 mm
Type - Pset_ProductRequirements - Category: Ceilings
Type - Pset_QuantityTakeOff - Reference: 600 x 600mm
Material: EST. Õhkvahe. Roov. Kipsplaadi alusroov. Vertikaalne 36 mm, EST. Ripplagi. Moodullagi. 600 x 600 mm 16 mm
Pset_CoveringCommon - Finish: EST. Ripplagi. Moodullagi. 600 x 600 mm;
Name (Compound Ceiling:600 x 600mm:...) | In
1651622 | 1 Korrus A
1651632 | 1 Korrus A
1692347 | 1 Korrus A
1692355 | 1 Korrus A
1692363 | 1 Korrus A
1692371 | 1 Korrus A
1692381 | 1 Korrus A
1692389 | 1 Korrus A
1692401 | 1 Korrus A
1692412 | 1 Korrus A
1692420 | 1 Korrus A
1692428 | 1 Korrus A
1692440 | 1 Korrus A
1692448 | 1 Korrus A
1698092 | 1 Korrus
1698103 | 1 Korrus
1698111 | 1 Korrus
1698121 | 1 Korrus
1702988 | 0 Kelder
1703000 | 0 Kelder
1703938 | 2 Korrus A
1703946 | 2 Korrus A
1703954 | 2 Korrus A
1703965 | 2 Korrus A
1703977 | 2 Korrus A
1703985 | 2 Korrus A
1703995 | 2 Korrus A
1704005 | 2 Korrus A
1704013 | 2 Korrus A
1704035 | 2 Korrus A
1704043 | 2 Korrus A
1704051 | 2 Korrus A
1704059 | 2 Korrus A
1704067 | 2 Korrus A
1704079 | 3 korrus
1704088 | 3 korrus
1704096 | 2 Korrus
1709272 | 2 Korrus
1717397 | 3 korrus
1717404 | 3 Korrus A
1717411 | 3 Korrus A
1717421 | 3 Korrus A
1717438 | 3 Korrus A
1717445 | 3 Korrus A
1717452 | 3 Korrus A
1717462 | 3 Korrus A
1717469 | 3 Korrus A
1717478 | 3 Korrus A
1717487 | 3 Korrus A
1717494 | 3 Korrus A
1717504 | 3 Korrus A
1717514 | 3 Korrus A
1717521 | 3 Korrus A
1717530 | 3 korrus
1748908 | 2 Korrus
1789390 | 1 Korrus A
1823759 | 2 Korrus
1825176 | 2 Korrus A
1920765 | 3 Korrus A

# IfcCovering: Compound Ceiling:600 x 600mm Grid 2, Compound Ceiling:600 x 600mm Grid 2:1702979
In: 0 Kelder
Type - PredefinedType: CEILING
Type - Pset_CoveringCommon - Reference: 600 x 600mm Grid 2; TotalThickness: 52 mm
Type - Pset_ElementShading - Roughness: 914.4 mm
Type - Pset_ProductRequirements - Category: Ceilings
Type - Pset_QuantityTakeOff - Reference: 600 x 600mm Grid 2
Material: Default 36 mm, Ceiling Tile 600 x 600 TEINE TOON VMS 16 mm
Pset_CoveringCommon - Finish: Ceiling Tile 600 x 600 TEINE TOON VMS;

# IfcCovering: Compound Ceiling:Kips (16)
Type - PredefinedType: CEILING
Type - Pset_CoveringCommon - Reference: Kips; TotalThickness: 57 mm
Type - Pset_ElementShading - Roughness: 914.4 mm
Type - Pset_ProductRequirements - Category: Ceilings
Type - Pset_QuantityTakeOff - Reference: Kips
Material: EST. Õhkvahe. Roov. Kipsplaadi alusroov. Vertikaalne 45 mm, EST. Ehitusplaat. Kipsplaat 12 mm
Name (Compound Ceiling:Kips:...) | In
1651464 | 1 Korrus
1651474 | 1 Korrus
1694012 | 1 Korrus A
1704635 | 2 Korrus A
1707391 | 2 Korrus
1707521 | 2 Korrus
1709255 | 2 Korrus
1709263 | 2 Korrus
1709805 | 3 korrus
1709824 | 3 korrus
1713979 | 3 Korrus A
1828915 | 1 Korrus
2000567 | 3 korrus
2000601 | 2 Korrus
2000619 | 2 Korrus
2000646 | 2 Korrus

# IfcCovering: Compound Ceiling:Termotöödeldud voodrilaud, Compound Ceiling:Termotöödeldud voodrilaud:1702971
In: 0 Kelder
Type - PredefinedType: CEILING
Type - Pset_CoveringCommon - Reference: Termotöödeldud voodrilaud; TotalThickness: 52 mm
Type - Pset_ElementShading - Roughness: 914.4 mm
Type - Pset_ProductRequirements - Category: Ceilings
Type - Pset_QuantityTakeOff - Reference: Termotöödeldud voodrilaud
Material: Default 36 mm, Ceiling Tile 600 x 1200(2) 16 mm
Pset_CoveringCommon - Finish: Ceiling Tile 600 x 1200(2);

# IfcCurtainWall: Curtain Wall:Curtain Wall, Curtain Wall:Curtain Wall:1171982
In: 1 Korrus
Type - Pset_CurtainWallCommon - IsExternal: no; Reference: Curtain Wall
Type - Pset_ProductRequirements - Category: Walls
Type - Pset_QuantityTakeOff - Reference: Curtain Wall
Pset_CurtainWallCommon - IsExternal: yes

# IfcCurtainWall: Curtain Wall:Curtain Wall KLF-01.2, Curtain Wall:Curtain Wall KLF-01.2:978327
In: 1 Korrus
Type - Pset_CurtainWallCommon - IsExternal: no; Reference: Curtain Wall KLF-01.2
Type - Pset_ProductRequirements - Category: Walls
Type - Pset_QuantityTakeOff - Reference: Curtain Wall KLF-01.2
Pset_CurtainWallCommon - IsExternal: yes

# IfcCurtainWall: Curtain Wall:Curtain Wall KLF-02.1, Curtain Wall:Curtain Wall KLF-02.1:906456
In: 1 Korrus
Type - Pset_CurtainWallCommon - IsExternal: no; Reference: Curtain Wall KLF-02.1
Type - Pset_ProductRequirements - Category: Walls
Type - Pset_QuantityTakeOff - Reference: Curtain Wall KLF-02.1
Pset_CurtainWallCommon - IsExternal: yes

# IfcCurtainWall: Curtain Wall:Curtain Wall KLF-02.2, Curtain Wall:Curtain Wall KLF-02.2:906291
In: 1 Korrus
Type - Pset_CurtainWallCommon - IsExternal: no; Reference: Curtain Wall KLF-02.2
Type - Pset_ProductRequirements - Category: Walls
Type - Pset_QuantityTakeOff - Reference: Curtain Wall KLF-02.2
Pset_CurtainWallCommon - IsExternal: yes

# IfcCurtainWall: Curtain Wall:Curtain Wall KLF-03, Curtain Wall:Curtain Wall KLF-03:859011
In: 1 Korrus
Type - Pset_CurtainWallCommon - IsExternal: no; Reference: Curtain Wall KLF-03
Type - Pset_ProductRequirements - Category: Walls
Type - Pset_QuantityTakeOff - Reference: Curtain Wall KLF-03
Pset_CurtainWallCommon - IsExternal: yes

# IfcCurtainWall: Curtain Wall:Curtain Wall KLF-04, Curtain Wall:Curtain Wall KLF-04:1051206
In: 2 Korrus
Type - Pset_CurtainWallCommon - IsExternal: no; Reference: Curtain Wall KLF-04
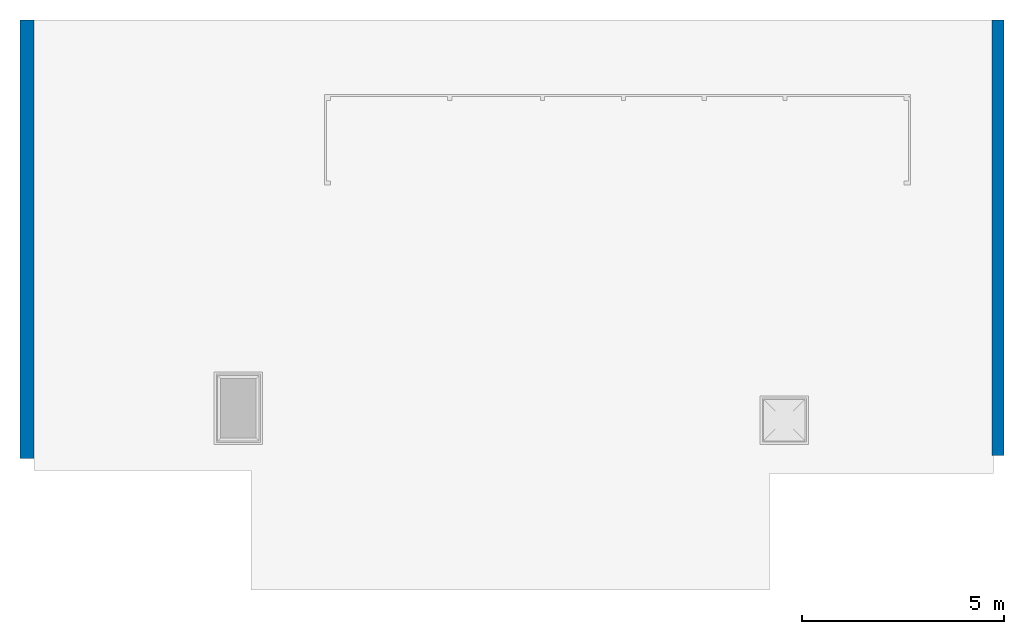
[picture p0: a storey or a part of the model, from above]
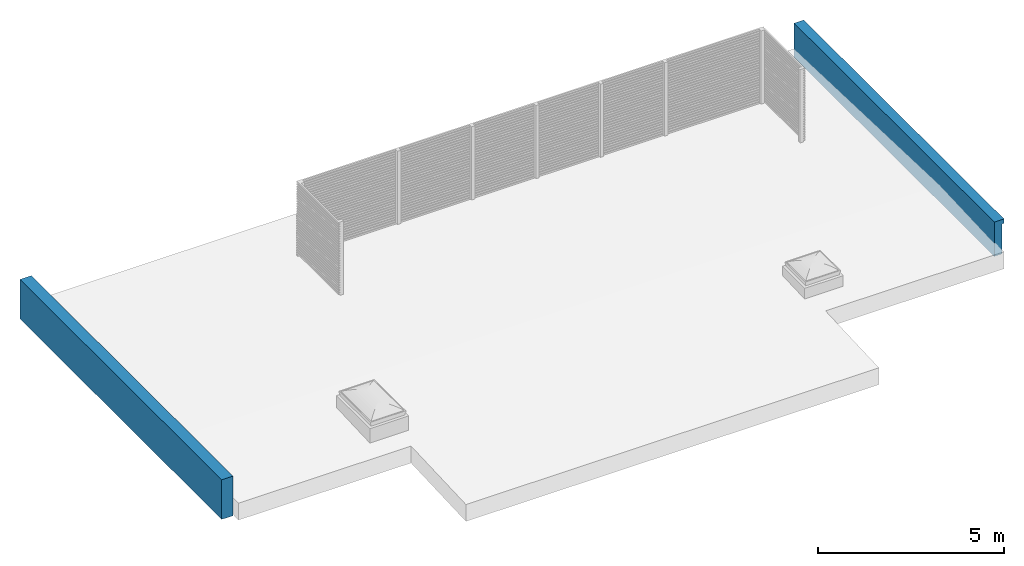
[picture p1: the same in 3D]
Properties of the parts of a building model (IFC2X3), part 3 of 7

# IfcCurtainWall: Curtain Wall:Curtain Wall KLF-04, Curtain Wall:Curtain Wall KLF-04:1051206
Type - Pset_ProductRequirements - Category: Walls
Type - Pset_QuantityTakeOff - Reference: Curtain Wall KLF-04
Pset_OpeningElementCommon - Reference: Curtain Wall KLF-04; sets with these values: 2

# IfcCurtainWall: Curtain Wall:Curtain Wall KLF-05, Curtain Wall:Curtain Wall KLF-05:1051232
In: 2 Korrus
Type - Pset_CurtainWallCommon - IsExternal: no; Reference: Curtain Wall KLF-05
Type - Pset_ProductRequirements - Category: Walls
Type - Pset_QuantityTakeOff - Reference: Curtain Wall KLF-05
Pset_OpeningElementCommon - Reference: Curtain Wall KLF-05; sets with these values: 2

# IfcCurtainWall: Curtain Wall:Curtain Wall KLF-06, Curtain Wall:Curtain Wall KLF-06:939564
In: 2 Korrus
Type - Pset_CurtainWallCommon - IsExternal: no; Reference: Curtain Wall KLF-06
Type - Pset_ProductRequirements - Category: Walls
Type - Pset_QuantityTakeOff - Reference: Curtain Wall KLF-06
Pset_OpeningElementCommon - Reference: Curtain Wall KLF-06; sets with these values: 2

# IfcCurtainWall: Curtain Wall:Curtain Wall KLF-07, Curtain Wall:Curtain Wall KLF-07:858533
In: 1 Korrus
Type - Pset_CurtainWallCommon - IsExternal: no; Reference: Curtain Wall KLF-07
Type - Pset_ProductRequirements - Category: Walls
Type - Pset_QuantityTakeOff - Reference: Curtain Wall KLF-07
Pset_OpeningElementCommon - Reference: Curtain Wall KLF-07; sets with these values: 2

# IfcCurtainWall: Curtain Wall:Curtain Wall KLF-08, Curtain Wall:Curtain Wall KLF-08:859162
In: 2 Korrus
Type - Pset_CurtainWallCommon - IsExternal: no; Reference: Curtain Wall KLF-08
Type - Pset_ProductRequirements - Category: Walls
Type - Pset_QuantityTakeOff - Reference: Curtain Wall KLF-08
Pset_OpeningElementCommon - Reference: Curtain Wall KLF-08; sets with these values: 2

# IfcCurtainWall: Curtain Wall:Curtain Wall KLF-09, Curtain Wall:Curtain Wall KLF-09:1049648
In: 2 Korrus
Type - Pset_CurtainWallCommon - IsExternal: no; Reference: Curtain Wall KLF-09
Type - Pset_ProductRequirements - Category: Walls
Type - Pset_QuantityTakeOff - Reference: Curtain Wall KLF-09
Pset_OpeningElementCommon - Reference: Curtain Wall KLF-09; sets with these values: 2

# IfcCurtainWall: Curtain Wall:Curtain Wall KLF-10, Curtain Wall:Curtain Wall KLF-10:859215
In: 2 Korrus
Type - Pset_CurtainWallCommon - IsExternal: no; Reference: Curtain Wall KLF-10
Type - Pset_ProductRequirements - Category: Walls
Type - Pset_QuantityTakeOff - Reference: Curtain Wall KLF-10
Pset_OpeningElementCommon - Reference: Curtain Wall KLF-10; sets with these values: 2

# IfcCurtainWall: Curtain Wall:Curtain Wall KLF-11, Curtain Wall:Curtain Wall KLF-11:859017
In: 1 Korrus
Type - Pset_CurtainWallCommon - IsExternal: no; Reference: Curtain Wall KLF-11
Type - Pset_ProductRequirements - Category: Walls
Type - Pset_QuantityTakeOff - Reference: Curtain Wall KLF-11
Pset_CurtainWallCommon - IsExternal: yes

# IfcCurtainWall: Curtain Wall:Curtain Wall SKF-02, Curtain Wall:Curtain Wall SKF-02:858924
In: 1 Korrus
Type - Pset_CurtainWallCommon - IsExternal: no; Reference: Curtain Wall SKF-02
Type - Pset_ProductRequirements - Category: Walls
Type - Pset_QuantityTakeOff - Reference: Curtain Wall SKF-02
Pset_OpeningElementCommon - Reference: Curtain Wall SKF-02; sets with these values: 2

# IfcCurtainWall: Curtain Wall:Curtain Wall SKF-03, Curtain Wall:Curtain Wall SKF-03:1234896
In: 1 Korrus
Type - Pset_CurtainWallCommon - IsExternal: no; Reference: Curtain Wall SKF-03
Type - Pset_ProductRequirements - Category: Walls
Type - Pset_QuantityTakeOff - Reference: Curtain Wall SKF-03
Pset_CurtainWallCommon - IsExternal: yes

# IfcCurtainWall: Curtain Wall:Curtain Wall SKF-04, Curtain Wall:Curtain Wall SKF-04:1177057
In: 1 Korrus
Type - Pset_CurtainWallCommon - IsExternal: no; Reference: Curtain Wall SKF-04
Type - Pset_ProductRequirements - Category: Walls
Type - Pset_QuantityTakeOff - Reference: Curtain Wall SKF-04
Pset_CurtainWallCommon - IsExternal: yes

# IfcDistributionPort (95)
Description: Flow
Name | FlowDirection
Port_927013 | SOURCE
2 x Port_927014 | SOURCE
Port_927148 | SOURCE
2 x Port_927149 | SOURCE
2 x Port_928283 | SOURCE
Port_928299 | SOURCE
2 x Port_928300 | SOURCE
Port_928327 | SOURCE
2 x Port_960013 | SOURCE
Port_961657 | SOURCE
2 x Port_964291 | SOURCE
Port_964298 | SOURCE
2 x Port_984763 | SOURCE
Port_984780 | SOURCE
2 x Port_984802 | SOURCE
Port_984809 | SOURCE
2 x Port_990765 | SOURCE
2 x Port_1003803 | SOURCE
2 x Port_1003821 | SOURCE
2 x Port_1008217 | SOURCE
Port_1087488 | SOURCE
Port_1088243 | SOURCE
2 x Port_1088941 | SOURCE
2 x Port_1088985 | SOURCE
Port_1089195 | SOURCE
Port_1096543 | SOURCE
2 x Port_1096544 | SOURCE
Port_1096547 | SOURCE
2 x Port_1096548 | SOURCE
Port_1097291 | SOURCE
2 x Port_1133726 | SOURCE
2 x Port_1149609 | SOURCE
2 x Port_1152890 | SOURCE
Port_1163451 | SOURCE
2 x Port_1165601 | SOURCE
2 x Port_1165627 | SOURCE
Port_1185656 | SOURCE
Port_1186849 | SOURCE
Port_1189481 | SOURCE
Port_1189507 | SOURCE
Port_1190811 | SOURCE
Port_1214545 | SOURCE
Port_1216161 | SINK
Port_1308801 | SOURCE
Port_1452865 | SOURCE
Port_1464224 | SOURCE
Port_1655380 | SOURCE
Port_1655395 | SOURCE
2 x Port_1689746 | SOURCE
2 x Port_1689975 | SOURCE
2 x Port_1690031 | SOURCE
Port_1732858 | SOURCE
Port_1733218 | SOURCE
Port_1742474 | SOURCE
Port_1742484 | SOURCE
Port_1742540 | SOURCE
Port_1742541 | SOURCE
Port_1742542 | SOURCE
Port_1742591 | SOURCE
Port_1742592 | SOURCE
Port_1742593 | SOURCE
Port_1742594 | SOURCE
Port_1742595 | SOURCE
Port_1742596 | SOURCE
Port_1772812 | SOURCE
Port_1782382 | SOURCE
Port_1805655 | SOURCE
2 x Port_2392830 | SOURCE
2 x Port_2393006 | SOURCE

# IfcDoor: Liugsein 2700-h:SU-L-03_Liugsein 5700x2700-h klassides, Liugsein 2700-h:SU-L-03_Liugsein 5700x2700-h klassides:1255928
In: 0 Kelder
Type - ParameterTakesPrecedence: no; Sizeable: no; Material: <Unnamed> (3), Default White Panel
Type - Pset_DoorCommon - IsExternal: no; Reference: SU-L-03_Liugsein 5700x2700-h klassides
Type - Pset_ProductRequirements - Category: Doors
Type - Pset_QuantityTakeOff - Reference: SU-L-03_Liugsein 5700x2700-h klassides
OverallHeight: 2000 mm; OverallWidth: 3300 mm; Material: Default White Panel, Aluminum, Default White Frame

# IfcDoor: SMA_D01, 1-poolne:SU-AL-01 - 800x2100, SMA_D01, 1-poolne:SU-AL-01 - 800x2100:1003749
In: 0 Kelder
Type - ParameterTakesPrecedence: no; Sizeable: no; Material: Glass, <Unnamed> (3), __Metall silt hall (2), EST. Klaas. 3x. Default
Type - Pset_ConcreteElementGeneral - FireRating: -
Type - Pset_DoorCommon - IsExternal: no; Reference: SU-AL-01 - 800x2100; FireRating: -; AcousticRating: -
Type - Pset_ProductRequirements - Category: Doors
Type - Pset_QuantityTakeOff - Reference: SU-AL-01 - 800x2100
OverallHeight: 2100 mm; OverallWidth: 800 mm; Material: __Metall silt hall, Glass

# IfcDoor: SMA_D01, 1-poolne:SU-KL-01 - 700x2100, SMA_D01, 1-poolne:SU-KL-01 - 700x2100:1003642
In: 0 Kelder
Type - ParameterTakesPrecedence: no; Sizeable: no; Material: EST. Metall. Alumiinium. Värvitud. RAL7023 (Concrete grey) (2), <Unnamed> (2), __Metall silt hall, EST. Klaas. 3x. Default, EST. Klaas. 1x. Default(1)
Type - Pset_ConcreteElementGeneral - FireRating: -
Type - Pset_DoorCommon - IsExternal: no; Reference: SU-KL-01 - 700x2100; FireRating: -; AcousticRating: -
Type - Pset_ProductRequirements - Category: Doors
Type - Pset_QuantityTakeOff - Reference: SU-KL-01 - 700x2100
OverallHeight: 2100 mm; OverallWidth: 700 mm; Material: EST. Metall. Alumiinium. Värvitud. RAL7023 (Concrete grey), __Metall silt hall

# IfcDoor: SMA_D01, 1-poolne:SU-M-02 - 1000x2100, SMA_D01, 1-poolne:SU-M-02 - 1000x2100:1001055
In: 0 Kelder
Type - ParameterTakesPrecedence: no; Sizeable: no; Material: <Unnamed> (3), __Metall silt hall (3), EST. Klaas. 3x. Default
Type - Pset_ConcreteElementGeneral - FireRating: -
Type - Pset_DoorCommon - IsExternal: no; Reference: SU-M-02 - 1000x2100; FireRating: -; AcousticRating: -
Type - Pset_ProductRequirements - Category: Doors
Type - Pset_QuantityTakeOff - Reference: SU-M-02 - 1000x2100
OverallHeight: 2100 mm; OverallWidth: 1000 mm; Material: __Metall silt hall

# IfcDoor: SMA_D01, 1-poolne:SU-M-02 - 1000x2100 (2)
In: 0 Kelder
Type - ParameterTakesPrecedence: no; Sizeable: no; Material: __Metall silt hall (3), <Unnamed> (3), EST. Klaas. 3x. Default
Type - Pset_ConcreteElementGeneral - FireRating: -
Type - Pset_DoorCommon - IsExternal: no; Reference: SU-M-02 - 1000x2100; FireRating: -; AcousticRating: -
Type - Pset_ProductRequirements - Category: Doors
Type - Pset_QuantityTakeOff - Reference: SU-M-02 - 1000x2100
OverallHeight: 2100 mm; OverallWidth: 1000 mm; Material: __Metall silt hall
Name (SMA_D01, 1-poolne:SU-M-02 - 1000x2100:...)
1001475
1004780

# IfcDoor: SMA_D01, 1-poolne:SU-M-03- 900x2100, SMA_D01, 1-poolne:SU-M-03- 900x2100:1001097
In: 0 Kelder
Type - ParameterTakesPrecedence: no; Sizeable: no; Material: EST. Klaas. 3x. Default, __Metall silt hall (3), <Unnamed> (3)
Type - Pset_ConcreteElementGeneral - FireRating: -
Type - Pset_DoorCommon - IsExternal: no; Reference: SU-M-03- 900x2100; FireRating: -; AcousticRating: -
Type - Pset_ProductRequirements - Category: Doors
Type - Pset_QuantityTakeOff - Reference: SU-M-03- 900x2100
OverallHeight: 2100 mm; OverallWidth: 900 mm; Material: __Metall silt hall
Pset_OpeningElementCommon - Reference: SU-M-03- 900x2100; sets with these values: 2

# IfcDoor: SMA_D01, 1-poolne:SU-M-03- 900x2100, SMA_D01, 1-poolne:SU-M-03- 900x2100:1001388
In: 0 Kelder
Type - ParameterTakesPrecedence: no; Sizeable: no; Material: __Metall silt hall (3), <Unnamed> (3), EST. Klaas. 3x. Default
Type - Pset_ConcreteElementGeneral - FireRating: -
Type - Pset_DoorCommon - IsExternal: no; Reference: SU-M-03- 900x2100; FireRating: -; AcousticRating: -
Type - Pset_ProductRequirements - Category: Doors
Type - Pset_QuantityTakeOff - Reference: SU-M-03- 900x2100
OverallHeight: 2100 mm; OverallWidth: 900 mm; Material: __Metall silt hall

# IfcDoor: SMA_D01, 1-poolne:SU-P-01 - 1200x2100 EI, SMA_D01, 1-poolne:SU-P-01 - 1200x2100 EI:1147972
In: 0 Kelder
Type - ParameterTakesPrecedence: no; Sizeable: no; Material: <Unnamed> (3), EST. Klaas. 3x. Default, __Metall silt hall (2), EST. Metall. Alumiinium. Anodeeritud. Naturaalne
Type - Pset_ConcreteElementGeneral - FireRating: EI-30
Type - Pset_DoorCommon - IsExternal: no; Reference: SU-P-01 - 1200x2100 EI; FireRating: EI-30; AcousticRating: 35dB
Type - Pset_ProductRequirements - Category: Doors
Type - Pset_QuantityTakeOff - Reference: SU-P-01 - 1200x2100 EI
OverallHeight: 2100 mm; OverallWidth: 1200 mm; Material: EST. Metall. Alumiinium. Anodeeritud. Naturaalne, __Metall silt hall
Pset_OpeningElementCommon - Reference: SU-P-01 - 1200x2100 EI; sets with these values: 2

# IfcDoor: SMA_D01, 1-poolne:SU-P-01 - 1200x2100 EI, SMA_D01, 1-poolne:SU-P-01 - 1200x2100 EI:999350
In: 0 Kelder
Type - ParameterTakesPrecedence: no; Sizeable: no; Material: __Metall silt hall (2), <Unnamed> (3), EST. Klaas. 3x. Default, EST. Metall. Alumiinium. Anodeeritud. Naturaalne
Type - Pset_ConcreteElementGeneral - FireRating: EI-30
Type - Pset_DoorCommon - IsExternal: no; Reference: SU-P-01 - 1200x2100 EI; FireRating: EI-30; AcousticRating: 35dB
Type - Pset_ProductRequirements - Category: Doors
Type - Pset_QuantityTakeOff - Reference: SU-P-01 - 1200x2100 EI
OverallHeight: 2100 mm; OverallWidth: 1200 mm; Material: EST. Metall. Alumiinium. Anodeeritud. Naturaalne, __Metall silt hall

# IfcDoor: SMA_D01, 1-poolne:SU-P-01 - 1200x2100 EI 1korrus, SMA_D01, 1-poolne:SU-P-01 - 1200x2100 EI 1korrus:847671
In: 1 Korrus A
Type - OperationType: SINGLE_SWING_LEFT; ParameterTakesPrecedence: no; Sizeable: no; Material: <Unnamed> (3), EST. Klaas. 3x. Default, __Metall silt heleroheline) (2), EST. Metall. Alumiinium. Anodeeritud. Naturaalne
Type - SMA_D01, 1-poolne:SU-P-01 - 1200x2100 EI 1korrus:847671 - PanelOperation: SWINGING
Type - Pset_ConcreteElementGeneral - FireRating: EI-30
Type - Pset_DoorCommon - IsExternal: no; Reference: SU-P-01 - 1200x2100 EI 1korrus; FireRating: EI-30; AcousticRating: 35dB
Type - Pset_ProductRequirements - Category: Doors
Type - Pset_QuantityTakeOff - Reference: SU-P-01 - 1200x2100 EI 1korrus
OverallHeight: 2100 mm; OverallWidth: 1200 mm; Material: EST. Metall. Alumiinium. Anodeeritud. Naturaalne, __Metall silt heleroheline)
Pset_OpeningElementCommon - Reference: SU-P-01 - 1200x2100 EI 1korrus; sets with these values: 2

# IfcDoor: SMA_D01, 1-poolne:SU-P-01 - 1200x2100 EI 1korrus, SMA_D01, 1-poolne:SU-P-01 - 1200x2100 EI 1korrus:847702
In: 1 Korrus A
Type - OperationType: SINGLE_SWING_RIGHT; ParameterTakesPrecedence: no; Sizeable: no; Material: <Unnamed> (3), __Metall silt heleroheline) (2), EST. Klaas. 3x. Default, EST. Metall. Alumiinium. Anodeeritud. Naturaalne
Type - SMA_D01, 1-poolne:SU-P-01 - 1200x2100 EI 1korrus:847702 - PanelOperation: SWINGING
Type - Pset_ConcreteElementGeneral - FireRating: EI-30
Type - Pset_DoorCommon - IsExternal: no; Reference: SU-P-01 - 1200x2100 EI 1korrus; FireRating: EI-30; AcousticRating: 35dB
Type - Pset_ProductRequirements - Category: Doors
Type - Pset_QuantityTakeOff - Reference: SU-P-01 - 1200x2100 EI 1korrus
OverallHeight: 2100 mm; OverallWidth: 1200 mm; Material: EST. Metall. Alumiinium. Anodeeritud. Naturaalne, __Metall silt heleroheline)
Pset_OpeningElementCommon - Reference: SU-P-01 - 1200x2100 EI 1korrus; sets with these values: 2

# IfcDoor: SMA_D01, 1-poolne:SU-P-01 - 1200x2100 EI 2 korrus, SMA_D01, 1-poolne:SU-P-01 - 1200x2100 EI 2 korrus:847743
In: 2 Korrus A
Type - ParameterTakesPrecedence: no; Sizeable: no; Material: <Unnamed> (3), __Metall silt korallroosa (2), EST. Metall. Alumiinium. Anodeeritud. Naturaalne, EST. Klaas. 3x. Default
Type - Pset_ConcreteElementGeneral - FireRating: EI-30
Type - Pset_DoorCommon - IsExternal: no; Reference: SU-P-01 - 1200x2100 EI 2 korrus; FireRating: EI-30; AcousticRating: 35dB
Type - Pset_ProductRequirements - Category: Doors
Type - Pset_QuantityTakeOff - Reference: SU-P-01 - 1200x2100 EI 2 korrus
OverallHeight: 2100 mm; OverallWidth: 1200 mm; Material: EST. Metall. Alumiinium. Anodeeritud. Naturaalne, __Metall silt korallroosa

# IfcDoor: SMA_D01, 1-poolne:SU-P-01 - 1200x2100 EI 2 korrus, SMA_D01, 1-poolne:SU-P-01 - 1200x2100 EI 2 korrus:847740
In: 2 Korrus A
Type - ParameterTakesPrecedence: no; Sizeable: no; Material: EST. Klaas. 3x. Default, <Unnamed> (3), __Metall silt korallroosa (2), EST. Metall. Alumiinium. Anodeeritud. Naturaalne
Type - Pset_ConcreteElementGeneral - FireRating: EI-30
Type - Pset_DoorCommon - IsExternal: no; Reference: SU-P-01 - 1200x2100 EI 2 korrus; FireRating: EI-30; AcousticRating: 35dB
Type - Pset_ProductRequirements - Category: Doors
Type - Pset_QuantityTakeOff - Reference: SU-P-01 - 1200x2100 EI 2 korrus
OverallHeight: 2100 mm; OverallWidth: 1200 mm; Material: EST. Metall. Alumiinium. Anodeeritud. Naturaalne, __Metall silt korallroosa
Pset_OpeningElementCommon - Reference: SU-P-01 - 1200x2100 EI 2 korrus; sets with these values: 2

# IfcDoor: SMA_D01, 1-poolne:SU-P-01 - 1200x2100 EI 3 korrus, SMA_D01, 1-poolne:SU-P-01 - 1200x2100 EI 3 korrus:847810
In: 3 Korrus A
Type - ParameterTakesPrecedence: no; Sizeable: no; Material: <Unnamed> (3), EST. Klaas. 3x. Default, __Metall silt sinine (2), EST. Metall. Alumiinium. Anodeeritud. Naturaalne
Type - Pset_ConcreteElementGeneral - FireRating: EI-30
Type - Pset_DoorCommon - IsExternal: no; Reference: SU-P-01 - 1200x2100 EI 3 korrus; FireRating: EI-30; AcousticRating: 35dB
Type - Pset_ProductRequirements - Category: Doors
Type - Pset_QuantityTakeOff - Reference: SU-P-01 - 1200x2100 EI 3 korrus
OverallHeight: 2100 mm; OverallWidth: 1200 mm; Material: EST. Metall. Alumiinium. Anodeeritud. Naturaalne, __Metall silt sinine

# IfcDoor: SMA_D01, 1-poolne:SU-P-01 - 1200x2100 EI 3 korrus, SMA_D01, 1-poolne:SU-P-01 - 1200x2100 EI 3 korrus:847800
In: 3 Korrus A
Type - ParameterTakesPrecedence: no; Sizeable: no; Material: __Metall silt sinine (2), EST. Metall. Alumiinium. Anodeeritud. Naturaalne, <Unnamed> (3), EST. Klaas. 3x. Default
Type - Pset_ConcreteElementGeneral - FireRating: EI-30
Type - Pset_DoorCommon - IsExternal: no; Reference: SU-P-01 - 1200x2100 EI 3 korrus; FireRating: EI-30; AcousticRating: 35dB
Type - Pset_ProductRequirements - Category: Doors
Type - Pset_QuantityTakeOff - Reference: SU-P-01 - 1200x2100 EI 3 korrus
OverallHeight: 2100 mm; OverallWidth: 1200 mm; Material: EST. Metall. Alumiinium. Anodeeritud. Naturaalne, __Metall silt sinine

# IfcDoor: SMA_D01, 1-poolne:SU-P-03 - 1200x2100, SMA_D01, 1-poolne:SU-P-03 - 1200x2100:1000728
In: 0 Kelder
Type - ParameterTakesPrecedence: no; Sizeable: no; Material: <Unnamed> (3), __Metall silt korallroosa (3), EST. Klaas. 3x. Default
Type - Pset_ConcreteElementGeneral - FireRating: -
Type - Pset_DoorCommon - IsExternal: no; Reference: SU-P-03 - 1200x2100; FireRating: -; AcousticRating: 35dB
Type - Pset_ProductRequirements - Category: Doors
Type - Pset_QuantityTakeOff - Reference: SU-P-03 - 1200x2100
OverallHeight: 2100 mm; OverallWidth: 1200 mm; Material: __Metall silt korallroosa

# IfcDoor: SMA_D01, 1-poolne:SU-P-04 - 750x2100 (18)
Type - OperationType: SINGLE_SWING_LEFT; ParameterTakesPrecedence: no; Sizeable: no; Material: EST. Klaas. 3x. Default, __Metall silt hall (3), <Unnamed> (3)
Type - SMA_D01, 1-poolne:SU-P-04 - 750x2100:895776 - PanelOperation: SWINGING
Type - Pset_ConcreteElementGeneral - FireRating: -
Type - Pset_DoorCommon - IsExternal: no; Reference: SU-P-04 - 750x2100; FireRating: -; AcousticRating: -
Type - Pset_ProductRequirements - Category: Doors
Type - Pset_QuantityTakeOff - Reference: SU-P-04 - 750x2100
OverallHeight: 2100 mm; OverallWidth: 750 mm; Material: __Metall silt hall
Name (SMA_D01, 1-poolne:SU-P-04 - 750x2100:...) | In
895776 | 1 Korrus A
912007 | 2 Korrus A
912014 | 2 Korrus A
919247 | 2 Korrus A
928278 | 2 Korrus A
928481 | 2 Korrus A
960009 | 1 Korrus A | Pset_OpeningElementCommon - Reference: SU-P-04 - 750x2100; sets with these values: 2
984731 | 3 Korrus A | Pset_OpeningElementCommon - Reference: SU-P-04 - 750x2100; sets with these values: 2
984761 | 3 Korrus A | Pset_OpeningElementCommon - Reference: SU-P-04 - 750x2100; sets with these values: 2
984798 | 3 Korrus A
1081745 | 1 Korrus A
1081749 | 1 Korrus A | Pset_OpeningElementCommon - Reference: SU-P-04 - 750x2100; sets with these values: 2
1081761 | 1 Korrus A
1093848 | 3 Korrus A | Pset_OpeningElementCommon - Reference: SU-P-04 - 750x2100; sets with these values: 2
1093861 | 3 Korrus A | Pset_OpeningElementCommon - Reference: SU-P-04 - 750x2100; sets with these values: 2
1165600 | 2 Korrus | Pset_OpeningElementCommon - Reference: SU-P-04 - 750x2100; sets with these values: 2
1165624 | 2 Korrus | Pset_OpeningElementCommon - Reference: SU-P-04 - 750x2100; sets with these values: 2
1898575 | 1 Korrus | Pset_OpeningElementCommon - Reference: SU-P-04 - 750x2100; sets with these values: 2

# IfcDoor: SMA_D01, 1-poolne:SU-P-04 - 750x2100 (21)
Type - OperationType: SINGLE_SWING_RIGHT; ParameterTakesPrecedence: no; Sizeable: no; Material: __Metall silt hall (3), EST. Klaas. 3x. Default, <Unnamed> (3)
Type - SMA_D01, 1-poolne:SU-P-04 - 750x2100:895705 - PanelOperation: SWINGING
Type - Pset_ConcreteElementGeneral - FireRating: -
Type - Pset_DoorCommon - IsExternal: no; Reference: SU-P-04 - 750x2100; FireRating: -; AcousticRating: -
Type - Pset_ProductRequirements - Category: Doors
Type - Pset_QuantityTakeOff - Reference: SU-P-04 - 750x2100
OverallHeight: 2100 mm; OverallWidth: 750 mm; Material: __Metall silt hall
Name (SMA_D01, 1-poolne:SU-P-04 - 750x2100:...) | In | Reference | sets with these values
895705 | 1 Korrus A
912008 | 2 Korrus A | SU-P-04 - 750x2100 | 2
912013 | 2 Korrus A
912018 | 2 Korrus A
919288 | 2 Korrus A | SU-P-04 - 750x2100 | 2
960004 | 1 Korrus A
981304 | 3 korrus
984729 | 3 Korrus A | SU-P-04 - 750x2100 | 2
984759 | 3 Korrus A | SU-P-04 - 750x2100 | 2
984800 | 3 Korrus A | SU-P-04 - 750x2100 | 2
1081744 | 1 Korrus A | SU-P-04 - 750x2100 | 2
1081750 | 1 Korrus A | SU-P-04 - 750x2100 | 2
1081760 | 1 Korrus A | SU-P-04 - 750x2100 | 2
1093849 | 3 Korrus A | SU-P-04 - 750x2100 | 2
1093860 | 3 Korrus A | SU-P-04 - 750x2100 | 2
1099340 | 3 korrus | SU-P-04 - 750x2100 | 2
1149606 | 1 Korrus | SU-P-04 - 750x2100 | 2
1149612 | 1 Korrus | SU-P-04 - 750x2100 | 2
1165593 | 2 Korrus | SU-P-04 - 750x2100 | 2
1165611 | 2 Korrus
1209232 | 2 Korrus A | SU-P-04 - 750x2100 | 2

# IfcDoor: SMA_D01, 1-poolne:SU-P-04 - 750x2100 (2)
In: 3 korrus
Type - ParameterTakesPrecedence: no; Sizeable: no; Material: __Metall silt hall (3), <Unnamed> (3), EST. Klaas. 3x. Default
Type - Pset_ConcreteElementGeneral - FireRating: -
Type - Pset_DoorCommon - IsExternal: no; Reference: SU-P-04 - 750x2100; FireRating: -; AcousticRating: -
Type - Pset_ProductRequirements - Category: Doors
Type - Pset_QuantityTakeOff - Reference: SU-P-04 - 750x2100
OverallHeight: 2100 mm; OverallWidth: 750 mm; Material: __Metall silt hall
Pset_OpeningElementCommon - Reference: SU-P-04 - 750x2100; sets with these values: 2
Name (SMA_D01, 1-poolne:SU-P-04 - 750x2100:...)
985246
1133644

# IfcDoor: SMA_D01, 1-poolne:SU-P-04 - 750x2100, SMA_D01, 1-poolne:SU-P-04 - 750x2100:1308913
In: 0 Kelder
Type - ParameterTakesPrecedence: no; Sizeable: no; Material: __Metall silt hall (3), EST. Klaas. 3x. Default, <Unnamed> (3)
Type - Pset_ConcreteElementGeneral - FireRating: -
Type - Pset_DoorCommon - IsExternal: no; Reference: SU-P-04 - 750x2100; FireRating: -; AcousticRating: -
Type - Pset_ProductRequirements - Category: Doors
Type - Pset_QuantityTakeOff - Reference: SU-P-04 - 750x2100
OverallHeight: 2100 mm; OverallWidth: 750 mm; Material: __Metall silt hall

# IfcDoor: SMA_D01, 1-poolne:SU-P-05- 900x2100, SMA_D01, 1-poolne:SU-P-05- 900x2100:1007118
In: 0 Kelder
Type - ParameterTakesPrecedence: no; Sizeable: no; Material: EST. Klaas. 3x. Default, <Unnamed> (3), __Metall silt hall (3)
Type - Pset_ConcreteElementGeneral - FireRating: -
Type - Pset_DoorCommon - IsExternal: no; Reference: SU-P-05- 900x2100; FireRating: -; AcousticRating: -
Type - Pset_ProductRequirements - Category: Doors
Type - Pset_QuantityTakeOff - Reference: SU-P-05- 900x2100
OverallHeight: 2100 mm; OverallWidth: 900 mm; Material: __Metall silt hall

# IfcDoor: SMA_D01, 1-poolne:SU-P-05- 900x2100 (5)
In: 1 Korrus
Type - ParameterTakesPrecedence: no; Sizeable: no; Material: __Metall silt hall (3), <Unnamed> (3), EST. Klaas. 3x. Default
Type - Pset_ConcreteElementGeneral - FireRating: -
Type - Pset_DoorCommon - IsExternal: no; Reference: SU-P-05- 900x2100; FireRating: -; AcousticRating: -
Type - Pset_ProductRequirements - Category: Doors
Type - Pset_QuantityTakeOff - Reference: SU-P-05- 900x2100
OverallHeight: 2100 mm; OverallWidth: 900 mm; Material: __Metall silt hall
Name (SMA_D01, 1-poolne:SU-P-05- 900x2100:...)
866225
866294
866961
867016
996302

# IfcDoor: SMA_D01, 1-poolne:SU-P-06 - 900x2100 EI-30 (2)
Type - ParameterTakesPrecedence: no; Sizeable: no; Material: <Unnamed> (3), __Metall silt korallroosa (3), EST. Klaas. 3x. Default
Type - Pset_ConcreteElementGeneral - FireRating: EI-30
Type - Pset_DoorCommon - IsExternal: no; Reference: SU-P-06 - 900x2100 EI-30; FireRating: EI-30; AcousticRating: 35dB
Type - Pset_ProductRequirements - Category: Doors
Type - Pset_QuantityTakeOff - Reference: SU-P-06 - 900x2100 EI-30
OverallHeight: 2100 mm; OverallWidth: 900 mm; Material: __Metall silt korallroosa
Name (SMA_D01, 1-poolne:SU-P-06 - 900x2100 EI-30:...) | In
1199508 | 0 Kelder
1213530 | 1 Korrus | Pset_OpeningElementCommon - Reference: SU-P-06 - 900x2100 EI-30; sets with these values: 2

# IfcDoor: SMA_D01, 1-poolne:SU-P-06 - 900x2100 EI-30, SMA_D01, 1-poolne:SU-P-06 - 900x2100 EI-30:1177053
In: 1 Korrus
Type - ParameterTakesPrecedence: no; Sizeable: no; Material: __Metall silt korallroosa (3), <Unnamed> (3), EST. Klaas. 3x. Default
Type - Pset_ConcreteElementGeneral - FireRating: EI-30
Type - Pset_DoorCommon - IsExternal: no; Reference: SU-P-06 - 900x2100 EI-30; FireRating: EI-30; AcousticRating: 35dB
Type - Pset_ProductRequirements - Category: Doors
Type - Pset_QuantityTakeOff - Reference: SU-P-06 - 900x2100 EI-30
OverallHeight: 2100 mm; OverallWidth: 900 mm; Material: __Metall silt korallroosa

# IfcDoor: SMA_D01, 1-poolne:SU-P-07 - 1000x2100 1 korrus (2)
In: 1 Korrus A
Type - OperationType: SINGLE_SWING_LEFT; ParameterTakesPrecedence: no; Sizeable: no; Material: <Unnamed> (3), __Metall silt heleroheline) (2), EST. Metall. Alumiinium. Anodeeritud. Naturaalne, EST. Klaas. 3x. Default
Type - SMA_D01, 1-poolne:SU-P-07 - 1000x2100 1 korrus:896119 - PanelOperation: SWINGING
Type - Pset_ConcreteElementGeneral - FireRating: EI-15
Type - Pset_DoorCommon - IsExternal: no; Reference: SU-P-07 - 1000x2100 1 korrus; FireRating: EI-15; AcousticRating: 35dB
Type - Pset_ProductRequirements - Category: Doors
Type - Pset_QuantityTakeOff - Reference: SU-P-07 - 1000x2100 1 korrus
OverallHeight: 2100 mm; OverallWidth: 1000 mm; Material: EST. Metall. Alumiinium. Anodeeritud. Naturaalne, __Metall silt heleroheline)
Name (SMA_D01, 1-poolne:SU-P-07 - 1000x2100 1 korrus:...)
896119
1018835

# IfcDoor: SMA_D01, 1-poolne:SU-P-07 - 1000x2100 1 korrus (3)
In: 1 Korrus A
Type - OperationType: SINGLE_SWING_RIGHT; ParameterTakesPrecedence: no; Sizeable: no; Material: __Metall silt heleroheline) (2), EST. Klaas. 3x. Default, <Unnamed> (3), EST. Metall. Alumiinium. Anodeeritud. Naturaalne
Type - SMA_D01, 1-poolne:SU-P-07 - 1000x2100 1 korrus:895916 - PanelOperation: SWINGING
Type - Pset_ConcreteElementGeneral - FireRating: EI-15
Type - Pset_DoorCommon - IsExternal: no; Reference: SU-P-07 - 1000x2100 1 korrus; FireRating: EI-15; AcousticRating: 35dB
Type - Pset_ProductRequirements - Category: Doors
Type - Pset_QuantityTakeOff - Reference: SU-P-07 - 1000x2100 1 korrus
OverallHeight: 2100 mm; OverallWidth: 1000 mm; Material: EST. Metall. Alumiinium. Anodeeritud. Naturaalne, __Metall silt heleroheline)
Name (SMA_D01, 1-poolne:SU-P-07 - 1000x2100 1 korrus:...)
895916
896288
1082451

# IfcDoor: SMA_D01, 1-poolne:SU-P-07 - 1000x2100 2korrus (2)
In: 2 Korrus A
Type - ParameterTakesPrecedence: no; Sizeable: no; Material: <Unnamed> (3), __Metall silt korallroosa (2), EST. Klaas. 3x. Default, EST. Metall. Alumiinium. Anodeeritud. Naturaalne
Type - Pset_ConcreteElementGeneral - FireRating: EI-15
Type - Pset_DoorCommon - IsExternal: no; Reference: SU-P-07 - 1000x2100 2korrus; FireRating: EI-15; AcousticRating: 35dB
Type - Pset_ProductRequirements - Category: Doors
Type - Pset_QuantityTakeOff - Reference: SU-P-07 - 1000x2100 2korrus
OverallHeight: 2100 mm; OverallWidth: 1000 mm; Material: EST. Metall. Alumiinium. Anodeeritud. Naturaalne, __Metall silt korallroosa
Name (SMA_D01, 1-poolne:SU-P-07 - 1000x2100 2korrus:...)
912023
985903

# IfcDoor: SMA_D01, 1-poolne:SU-P-07 - 1000x2100 2korrus (3)
In: 2 Korrus A
Type - ParameterTakesPrecedence: no; Sizeable: no; Material: <Unnamed> (3), __Metall silt korallroosa (2), EST. Metall. Alumiinium. Anodeeritud. Naturaalne, EST. Klaas. 3x. Default
Type - Pset_ConcreteElementGeneral - FireRating: EI-15
Type - Pset_DoorCommon - IsExternal: no; Reference: SU-P-07 - 1000x2100 2korrus; FireRating: EI-15; AcousticRating: 35dB
Type - Pset_ProductRequirements - Category: Doors
Type - Pset_QuantityTakeOff - Reference: SU-P-07 - 1000x2100 2korrus
OverallHeight: 2100 mm; OverallWidth: 1000 mm; Material: EST. Metall. Alumiinium. Anodeeritud. Naturaalne, __Metall silt korallroosa
Name (SMA_D01, 1-poolne:SU-P-07 - 1000x2100 2korrus:...)
912022
912024
926904

# IfcDoor: SMA_D01, 1-poolne:SU-P-07 - 1000x2100 3korrus (2)
In: 3 Korrus A
Type - ParameterTakesPrecedence: no; Sizeable: no; Material: <Unnamed> (3), __Metall silt sinine (2), EST. Metall. Alumiinium. Anodeeritud. Naturaalne, EST. Klaas. 3x. Default
Type - Pset_ConcreteElementGeneral - FireRating: EI-15
Type - Pset_DoorCommon - IsExternal: no; Reference: SU-P-07 - 1000x2100 3korrus; FireRating: EI-15; AcousticRating: 35dB
Type - Pset_ProductRequirements - Category: Doors
Type - Pset_QuantityTakeOff - Reference: SU-P-07 - 1000x2100 3korrus
OverallHeight: 2100 mm; OverallWidth: 1000 mm; Material: EST. Metall. Alumiinium. Anodeeritud. Naturaalne, __Metall silt sinine
Name (SMA_D01, 1-poolne:SU-P-07 - 1000x2100 3korrus:...)
984734
1064311

# IfcDoor: SMA_D01, 1-poolne:SU-P-07 - 1000x2100 3korrus (3)
In: 3 Korrus A
Type - ParameterTakesPrecedence: no; Sizeable: no; Material: __Metall silt sinine (2), <Unnamed> (3), EST. Metall. Alumiinium. Anodeeritud. Naturaalne, EST. Klaas. 3x. Default
Type - Pset_ConcreteElementGeneral - FireRating: EI-15
Type - Pset_DoorCommon - IsExternal: no; Reference: SU-P-07 - 1000x2100 3korrus; FireRating: EI-15; AcousticRating: 35dB
Type - Pset_ProductRequirements - Category: Doors
Type - Pset_QuantityTakeOff - Reference: SU-P-07 - 1000x2100 3korrus
OverallHeight: 2100 mm; OverallWidth: 1000 mm; Material: EST. Metall. Alumiinium. Anodeeritud. Naturaalne, __Metall silt sinine
Name (SMA_D01, 1-poolne:SU-P-07 - 1000x2100 3korrus:...)
984733
984735
1064425

# IfcDoor: SMA_D01, 1-poolne:SU-P-08 - 1200x2100 EI, SMA_D01, 1-poolne:SU-P-08 - 1200x2100 EI:1557387
In: 2 Korrus A
Type - ParameterTakesPrecedence: no; Sizeable: no; Material: <Unnamed> (3), EST. Klaas. 3x. Default, __Metall silt korallroosa (2), EST. Metall. Alumiinium. Anodeeritud. Naturaalne
Type - Pset_ConcreteElementGeneral - FireRating: EI-30
Type - Pset_DoorCommon - IsExternal: no; Reference: SU-P-08 - 1200x2100 EI; FireRating: EI-30; AcousticRating: 35dB
Type - Pset_ProductRequirements - Category: Doors
Type - Pset_QuantityTakeOff - Reference: SU-P-08 - 1200x2100 EI
OverallHeight: 2100 mm; OverallWidth: 1200 mm; Material: EST. Metall. Alumiinium. Anodeeritud. Naturaalne, __Metall silt korallroosa
Pset_OpeningElementCommon - Reference: SU-P-08 - 1200x2100 EI; sets with these values: 2

# IfcDoor: SMA_D01, 1-poolne:SU-P-08 - 1200x2100 EI, SMA_D01, 1-poolne:SU-P-08 - 1200x2100 EI:847742
In: 2 Korrus
Type - ParameterTakesPrecedence: no; Sizeable: no; Material: <Unnamed> (3), __Metall silt korallroosa (2), EST. Metall. Alumiinium. Anodeeritud. Naturaalne, EST. Klaas. 3x. Default
Type - Pset_ConcreteElementGeneral - FireRating: EI-30
Type - Pset_DoorCommon - IsExternal: no; Reference: SU-P-08 - 1200x2100 EI; FireRating: EI-30; AcousticRating: 35dB
Type - Pset_ProductRequirements - Category: Doors
Type - Pset_QuantityTakeOff - Reference: SU-P-08 - 1200x2100 EI
OverallHeight: 2100 mm; OverallWidth: 1200 mm; Material: EST. Metall. Alumiinium. Anodeeritud. Naturaalne, __Metall silt korallroosa
Pset_OpeningElementCommon - Reference: SU-P-08 - 1200x2100 EI; sets with these values: 2

# IfcDoor: SMA_D01, 1-poolne:SU-P-08 - 1200x2100 EI, SMA_D01, 1-poolne:SU-P-08 - 1200x2100 EI:847741
In: 2 Korrus A
Type - ParameterTakesPrecedence: no; Sizeable: no; Material: __Metall silt korallroosa (2), EST. Metall. Alumiinium. Anodeeritud. Naturaalne, EST. Klaas. 3x. Default, <Unnamed> (3)
Type - Pset_ConcreteElementGeneral - FireRating: EI-30
Type - Pset_DoorCommon - IsExternal: no; Reference: SU-P-08 - 1200x2100 EI; FireRating: EI-30; AcousticRating: 35dB
Type - Pset_ProductRequirements - Category: Doors
Type - Pset_QuantityTakeOff - Reference: SU-P-08 - 1200x2100 EI
OverallHeight: 2100 mm; OverallWidth: 1200 mm; Material: EST. Metall. Alumiinium. Anodeeritud. Naturaalne, __Metall silt korallroosa
Pset_OpeningElementCommon - Reference: SU-P-08 - 1200x2100 EI; sets with these values: 2

# IfcDoor: SMA_D01, 1-poolne:SU-P-08 - 1200x2100 EI 1 korrus, SMA_D01, 1-poolne:SU-P-08 - 1200x2100 EI 1 korrus:895798
In: 1 Korrus A
Type - OperationType: SINGLE_SWING_LEFT; ParameterTakesPrecedence: no; Sizeable: no; Material: <Unnamed> (3), __Metall silt heleroheline) (2), EST. Metall. Alumiinium. Anodeeritud. Naturaalne, EST. Klaas. 3x. Default
Type - SMA_D01, 1-poolne:SU-P-08 - 1200x2100 EI 1 korrus:895798 - PanelOperation: SWINGING
Type - Pset_ConcreteElementGeneral - FireRating: EI-30
Type - Pset_DoorCommon - IsExternal: no; Reference: SU-P-08 - 1200x2100 EI 1 korrus; FireRating: EI-30; AcousticRating: 35dB
Type - Pset_ProductRequirements - Category: Doors
Type - Pset_QuantityTakeOff - Reference: SU-P-08 - 1200x2100 EI 1 korrus
OverallHeight: 2100 mm; OverallWidth: 1200 mm; Material: EST. Metall. Alumiinium. Anodeeritud. Naturaalne, __Metall silt heleroheline)

# IfcDoor: SMA_D01, 1-poolne:SU-P-08 - 1200x2100 EI 1 korrus (2)
In: 1 Korrus
Type - ParameterTakesPrecedence: no; Sizeable: no; Material: __Metall silt heleroheline) (2), <Unnamed> (3), EST. Klaas. 3x. Default, EST. Metall. Alumiinium. Anodeeritud. Naturaalne
Type - Pset_ConcreteElementGeneral - FireRating: EI-30
Type - Pset_DoorCommon - IsExternal: no; Reference: SU-P-08 - 1200x2100 EI 1 korrus; FireRating: EI-30; AcousticRating: 35dB
Type - Pset_ProductRequirements - Category: Doors
Type - Pset_QuantityTakeOff - Reference: SU-P-08 - 1200x2100 EI 1 korrus
OverallHeight: 2100 mm; OverallWidth: 1200 mm; Material: EST. Metall. Alumiinium. Anodeeritud. Naturaalne, __Metall silt heleroheline)
Name (SMA_D01, 1-poolne:SU-P-08 - 1200x2100 EI 1 korrus:...)
847672
1178971 | Pset_OpeningElementCommon - Reference: SU-P-08 - 1200x2100 EI 1 korrus; sets with these values: 2

# IfcDoor: SMA_D01, 1-poolne:SU-P-08 - 1200x2100 EI 3 korrus, SMA_D01, 1-poolne:SU-P-08 - 1200x2100 EI 3 korrus:847811
In: 3 korrus
Type - ParameterTakesPrecedence: no; Sizeable: no; Material: <Unnamed> (3), EST. Metall. Alumiinium. Anodeeritud. Naturaalne, __Metall silt sinine (2), EST. Klaas. 3x. Default
Type - Pset_ConcreteElementGeneral - FireRating: EI-30
Type - Pset_DoorCommon - IsExternal: no; Reference: SU-P-08 - 1200x2100 EI 3 korrus; FireRating: EI-30; AcousticRating: 35dB
Type - Pset_ProductRequirements - Category: Doors
Type - Pset_QuantityTakeOff - Reference: SU-P-08 - 1200x2100 EI 3 korrus
OverallHeight: 2100 mm; OverallWidth: 1200 mm; Material: EST. Metall. Alumiinium. Anodeeritud. Naturaalne, __Metall silt sinine

# IfcDoor: SMA_D01, 1-poolne:SU-P-08 - 1200x2100 EI 3 korrus, SMA_D01, 1-poolne:SU-P-08 - 1200x2100 EI 3 korrus:1755816
In: 3 Korrus A
Type - ParameterTakesPrecedence: no; Sizeable: no; Material: <Unnamed> (3), __Metall silt sinine (2), EST. Klaas. 3x. Default, EST. Metall. Alumiinium. Anodeeritud. Naturaalne
Type - Pset_ConcreteElementGeneral - FireRating: EI-30
Type - Pset_DoorCommon - IsExternal: no; Reference: SU-P-08 - 1200x2100 EI 3 korrus; FireRating: EI-30; AcousticRating: 35dB
Type - Pset_ProductRequirements - Category: Doors
Type - Pset_QuantityTakeOff - Reference: SU-P-08 - 1200x2100 EI 3 korrus
OverallHeight: 2100 mm; OverallWidth: 1200 mm; Material: EST. Metall. Alumiinium. Anodeeritud. Naturaalne, __Metall silt sinine

# IfcDoor: SMA_D01, 1-poolne:SU-P-08 - 1200x2100 EI 3 korrus, SMA_D01, 1-poolne:SU-P-08 - 1200x2100 EI 3 korrus:1098961
In: 3 Korrus A
Type - ParameterTakesPrecedence: no; Sizeable: no; Material: __Metall silt sinine (2), EST. Klaas. 3x. Default, <Unnamed> (3), EST. Metall. Alumiinium. Anodeeritud. Naturaalne
Type - Pset_ConcreteElementGeneral - FireRating: EI-30
Type - Pset_DoorCommon - IsExternal: no; Reference: SU-P-08 - 1200x2100 EI 3 korrus; FireRating: EI-30; AcousticRating: 35dB
Type - Pset_ProductRequirements - Category: Doors
Type - Pset_QuantityTakeOff - Reference: SU-P-08 - 1200x2100 EI 3 korrus
OverallHeight: 2100 mm; OverallWidth: 1200 mm; Material: EST. Metall. Alumiinium. Anodeeritud. Naturaalne, __Metall silt sinine

# IfcDoor: SMA_D01, 1-poolne:SU-P-09 - 1000x2100 (2)
In: 1 Korrus
Type - ParameterTakesPrecedence: no; Sizeable: no; Material: EST. Metall. Alumiinium. Värvitud. RAL7023 (Concrete grey), <Unnamed> (3), EST. Klaas. 3x. Default, __Metall silt heleroheline) (2)
Type - Pset_ConcreteElementGeneral - FireRating: -
Type - Pset_DoorCommon - IsExternal: no; Reference: SU-P-09 - 1000x2100; FireRating: -; AcousticRating: 35dB
Type - Pset_ProductRequirements - Category: Doors
Type - Pset_QuantityTakeOff - Reference: SU-P-09 - 1000x2100
OverallHeight: 2100 mm; OverallWidth: 1000 mm; Material: EST. Metall. Alumiinium. Värvitud. RAL7023 (Concrete grey), __Metall silt heleroheline)
Name (SMA_D01, 1-poolne:SU-P-09 - 1000x2100:...)
886870 | Pset_OpeningElementCommon - Reference: SU-P-09 - 1000x2100; sets with these values: 2
886871

# IfcDoor: SMA_D01, 1-poolne:SU-P-10- 900x2100 1 korrus (5)
In: 1 Korrus A
Type - OperationType: SINGLE_SWING_LEFT; ParameterTakesPrecedence: no; Sizeable: no; Material: __Metall silt heleroheline) (2), <Unnamed> (3), EST. Metall. Alumiinium. Anodeeritud. Naturaalne, EST. Klaas. 3x. Default
Type - SMA_D01, 1-poolne:SU-P-10- 900x2100 1 korrus:887994 - PanelOperation: SWINGING
Type - Pset_ConcreteElementGeneral - FireRating: -
Type - Pset_DoorCommon - IsExternal: no; Reference: SU-P-10- 900x2100 1 korrus; FireRating: -; AcousticRating: 35dB
Type - Pset_ProductRequirements - Category: Doors
Type - Pset_QuantityTakeOff - Reference: SU-P-10- 900x2100 1 korrus
OverallHeight: 2100 mm; OverallWidth: 900 mm; Material: EST. Metall. Alumiinium. Anodeeritud. Naturaalne, __Metall silt heleroheline)
Name (SMA_D01, 1-poolne:SU-P-10- 900x2100 1 korrus:...)
887994 | Pset_OpeningElementCommon - Reference: SU-P-10- 900x2100 1 korrus; sets with these values: 2
888112
889334
889365
897309

# IfcDoor: SMA_D01, 1-poolne:SU-P-10- 900x2100 1 korrus (5)
In: 1 Korrus A
Type - OperationType: SINGLE_SWING_RIGHT; ParameterTakesPrecedence: no; Sizeable: no; Material: __Metall silt heleroheline) (2), <Unnamed> (3), EST. Klaas. 3x. Default, EST. Metall. Alumiinium. Anodeeritud. Naturaalne
Type - SMA_D01, 1-poolne:SU-P-10- 900x2100 1 korrus:887995 - PanelOperation: SWINGING
Type - Pset_ConcreteElementGeneral - FireRating: -
Type - Pset_DoorCommon - IsExternal: no; Reference: SU-P-10- 900x2100 1 korrus; FireRating: -; AcousticRating: 35dB
Type - Pset_ProductRequirements - Category: Doors
Type - Pset_QuantityTakeOff - Reference: SU-P-10- 900x2100 1 korrus
OverallHeight: 2100 mm; OverallWidth: 900 mm; Material: EST. Metall. Alumiinium. Anodeeritud. Naturaalne, __Metall silt heleroheline)
Name (SMA_D01, 1-poolne:SU-P-10- 900x2100 1 korrus:...)
887995
888111
889265
889426 | Pset_OpeningElementCommon - Reference: SU-P-10- 900x2100 1 korrus; sets with these values: 2
897379

# IfcDoor: SMA_D01, 1-poolne:SU-P-10- 900x2100 2 korrus (2)
In: 2 Korrus
Type - ParameterTakesPrecedence: no; Sizeable: no; Material: <Unnamed> (3), EST. Klaas. 3x. Default, __Metall silt korallroosa (2), EST. Metall. Alumiinium. Anodeeritud. Naturaalne
Type - Pset_ConcreteElementGeneral - FireRating: -
Type - Pset_DoorCommon - IsExternal: no; Reference: SU-P-10- 900x2100 2 korrus; FireRating: -; AcousticRating: 35dB
Type - Pset_ProductRequirements - Category: Doors
Type - Pset_QuantityTakeOff - Reference: SU-P-10- 900x2100 2 korrus
OverallHeight: 2100 mm; OverallWidth: 900 mm; Material: EST. Metall. Alumiinium. Anodeeritud. Naturaalne, __Metall silt korallroosa
Name (SMA_D01, 1-poolne:SU-P-10- 900x2100 2 korrus:...)
912489
918217

# IfcDoor: SMA_D01, 1-poolne:SU-P-10- 900x2100 2 korrus (2)
In: 2 Korrus
Type - ParameterTakesPrecedence: no; Sizeable: no; Material: <Unnamed> (3), EST. Metall. Alumiinium. Anodeeritud. Naturaalne, EST. Klaas. 3x. Default, __Metall silt korallroosa (2)
Type - Pset_ConcreteElementGeneral - FireRating: -
Type - Pset_DoorCommon - IsExternal: no; Reference: SU-P-10- 900x2100 2 korrus; FireRating: -; AcousticRating: 35dB
Type - Pset_ProductRequirements - Category: Doors
Type - Pset_QuantityTakeOff - Reference: SU-P-10- 900x2100 2 korrus
OverallHeight: 2100 mm; OverallWidth: 900 mm; Material: EST. Metall. Alumiinium. Anodeeritud. Naturaalne, __Metall silt korallroosa
Name (SMA_D01, 1-poolne:SU-P-10- 900x2100 2 korrus:...)
912488
912490

# IfcDoor: SMA_D01, 1-poolne:SU-P-10- 900x2100 2 korrus (14)
Type - ParameterTakesPrecedence: no; Sizeable: no; Material: __Metall silt korallroosa (2), <Unnamed> (3), EST. Metall. Alumiinium. Anodeeritud. Naturaalne, EST. Klaas. 3x. Default
Type - Pset_ConcreteElementGeneral - FireRating: -
Type - Pset_DoorCommon - IsExternal: no; Reference: SU-P-10- 900x2100 2 korrus; FireRating: -; AcousticRating: 35dB
Type - Pset_ProductRequirements - Category: Doors
Type - Pset_QuantityTakeOff - Reference: SU-P-10- 900x2100 2 korrus
OverallHeight: 2100 mm; OverallWidth: 900 mm; Material: EST. Metall. Alumiinium. Anodeeritud. Naturaalne, __Metall silt korallroosa
Name (SMA_D01, 1-poolne:SU-P-10- 900x2100 2 korrus:...) | In
911990 | 2 Korrus A
911991 | 2 Korrus A
911993 | 2 Korrus A
911994 | 2 Korrus A
912001 | 2 Korrus A
912002 | 2 Korrus A
912003 | 2 Korrus A
912004 | 2 Korrus A | Pset_OpeningElementCommon - Reference: SU-P-10- 900x2100 2 korrus; sets with these values: 2
912025 | 2 Korrus A
912026 | 2 Korrus A | Pset_OpeningElementCommon - Reference: SU-P-10- 900x2100 2 korrus; sets with these values: 2
912476 | 2 Korrus
912477 | 2 Korrus
912478 | 2 Korrus
912479 | 2 Korrus

# IfcDoor: SMA_D01, 1-poolne:SU-P-10- 900x2100 3 korrus (5)
In: 3 Korrus A
Type - ParameterTakesPrecedence: no; Sizeable: no; Material: <Unnamed> (3), EST. Klaas. 3x. Default, EST. Metall. Alumiinium. Anodeeritud. Naturaalne, __Metall silt sinine (2)
Type - Pset_ConcreteElementGeneral - FireRating: -
Type - Pset_DoorCommon - IsExternal: no; Reference: SU-P-10- 900x2100 3 korrus; FireRating: -; AcousticRating: 35dB
Type - Pset_ProductRequirements - Category: Doors
Type - Pset_QuantityTakeOff - Reference: SU-P-10- 900x2100 3 korrus
OverallHeight: 2100 mm; OverallWidth: 900 mm; Material: EST. Metall. Alumiinium. Anodeeritud. Naturaalne, __Metall silt sinine
Name (SMA_D01, 1-poolne:SU-P-10- 900x2100 3 korrus:...)
984686
984688
984696
984699
984740

# IfcDoor: SMA_D01, 1-poolne:SU-P-10- 900x2100 3 korrus (2)
In: 3 korrus
Type - ParameterTakesPrecedence: no; Sizeable: no; Material: <Unnamed> (3), EST. Metall. Alumiinium. Anodeeritud. Naturaalne, __Metall silt sinine (2), EST. Klaas. 3x. Default
Type - Pset_ConcreteElementGeneral - FireRating: -
Type - Pset_DoorCommon - IsExternal: no; Reference: SU-P-10- 900x2100 3 korrus; FireRating: -; AcousticRating: 35dB
Type - Pset_ProductRequirements - Category: Doors
Type - Pset_QuantityTakeOff - Reference: SU-P-10- 900x2100 3 korrus
OverallHeight: 2100 mm; OverallWidth: 900 mm; Material: EST. Metall. Alumiinium. Anodeeritud. Naturaalne, __Metall silt sinine
Name (SMA_D01, 1-poolne:SU-P-10- 900x2100 3 korrus:...)
981298
981300

# IfcDoor: SMA_D01, 1-poolne:SU-P-10- 900x2100 3 korrus (2)
In: 3 korrus
Type - ParameterTakesPrecedence: no; Sizeable: no; Material: EST. Klaas. 3x. Default, <Unnamed> (3), __Metall silt sinine (2), EST. Metall. Alumiinium. Anodeeritud. Naturaalne
Type - Pset_ConcreteElementGeneral - FireRating: -
Type - Pset_DoorCommon - IsExternal: no; Reference: SU-P-10- 900x2100 3 korrus; FireRating: -; AcousticRating: 35dB
Type - Pset_ProductRequirements - Category: Doors
Type - Pset_QuantityTakeOff - Reference: SU-P-10- 900x2100 3 korrus
OverallHeight: 2100 mm; OverallWidth: 900 mm; Material: EST. Metall. Alumiinium. Anodeeritud. Naturaalne, __Metall silt sinine
Name (SMA_D01, 1-poolne:SU-P-10- 900x2100 3 korrus:...)
985191
1718227

# IfcDoor: SMA_D01, 1-poolne:SU-P-10- 900x2100 3 korrus (4)
In: 3 Korrus A
Type - ParameterTakesPrecedence: no; Sizeable: no; Material: EST. Metall. Alumiinium. Anodeeritud. Naturaalne, <Unnamed> (3), __Metall silt sinine (2), EST. Klaas. 3x. Default
Type - Pset_ConcreteElementGeneral - FireRating: -
Type - Pset_DoorCommon - IsExternal: no; Reference: SU-P-10- 900x2100 3 korrus; FireRating: -; AcousticRating: 35dB
Type - Pset_ProductRequirements - Category: Doors
Type - Pset_QuantityTakeOff - Reference: SU-P-10- 900x2100 3 korrus
OverallHeight: 2100 mm; OverallWidth: 900 mm; Material: EST. Metall. Alumiinium. Anodeeritud. Naturaalne, __Metall silt sinine
Name (SMA_D01, 1-poolne:SU-P-10- 900x2100 3 korrus:...)
984689
984697
984698
984739

# IfcDoor: SMA_D01, 1-poolne:SU-P-10- 900x2100 3 korrus (2)
In: 3 korrus
Type - ParameterTakesPrecedence: no; Sizeable: no; Material: EST. Metall. Alumiinium. Anodeeritud. Naturaalne, __Metall silt sinine (2), <Unnamed> (3), EST. Klaas. 3x. Default
Type - Pset_ConcreteElementGeneral - FireRating: -
Type - Pset_DoorCommon - IsExternal: no; Reference: SU-P-10- 900x2100 3 korrus; FireRating: -; AcousticRating: 35dB
Type - Pset_ProductRequirements - Category: Doors
Type - Pset_QuantityTakeOff - Reference: SU-P-10- 900x2100 3 korrus
OverallHeight: 2100 mm; OverallWidth: 900 mm; Material: EST. Metall. Alumiinium. Anodeeritud. Naturaalne, __Metall silt sinine
Name (SMA_D01, 1-poolne:SU-P-10- 900x2100 3 korrus:...)
981297
981299

# IfcDoor: SMA_D01, 1-poolne:SU-P-10- 900x2100 3 korrus, SMA_D01, 1-poolne:SU-P-10- 900x2100 3 korrus:984685
In: 3 Korrus A
Type - ParameterTakesPrecedence: no; Sizeable: no; Material: __Metall silt sinine (2), <Unnamed> (3), EST. Metall. Alumiinium. Anodeeritud. Naturaalne, EST. Klaas. 3x. Default
Type - Pset_ConcreteElementGeneral - FireRating: -
Type - Pset_DoorCommon - IsExternal: no; Reference: SU-P-10- 900x2100 3 korrus; FireRating: -; AcousticRating: 35dB
Type - Pset_ProductRequirements - Category: Doors
Type - Pset_QuantityTakeOff - Reference: SU-P-10- 900x2100 3 korrus
OverallHeight: 2100 mm; OverallWidth: 900 mm; Material: EST. Metall. Alumiinium. Anodeeritud. Naturaalne, __Metall silt sinine

# IfcDoor: SMA_D01, 1-poolne:SU-P-10- 900x2100 3 korrus (2)
In: 3 korrus
Type - ParameterTakesPrecedence: no; Sizeable: no; Material: __Metall silt sinine (2), EST. Metall. Alumiinium. Anodeeritud. Naturaalne, <Unnamed> (3), EST. Klaas. 3x. Default
Type - Pset_ConcreteElementGeneral - FireRating: -
Type - Pset_DoorCommon - IsExternal: no; Reference: SU-P-10- 900x2100 3 korrus; FireRating: -; AcousticRating: 35dB
Type - Pset_ProductRequirements - Category: Doors
Type - Pset_QuantityTakeOff - Reference: SU-P-10- 900x2100 3 korrus
OverallHeight: 2100 mm; OverallWidth: 900 mm; Material: EST. Metall. Alumiinium. Anodeeritud. Naturaalne, __Metall silt sinine
Name (SMA_D01, 1-poolne:SU-P-10- 900x2100 3 korrus:...)
985190
1718228

# IfcDoor: SMA_D01, 1-poolne:SU-P-11 - 1000x2100, SMA_D01, 1-poolne:SU-P-11 - 1000x2100:1215646
In: 1 Korrus
Type - ParameterTakesPrecedence: no; Sizeable: no; Material: <Unnamed> (3), EST. Metall. Alumiinium. Värvitud. RAL7023 (Concrete grey), EST. Klaas. 3x. Default, __Metall silt heleroheline) (2)
Type - Pset_ConcreteElementGeneral - FireRating: -
Type - Pset_DoorCommon - IsExternal: no; Reference: SU-P-11 - 1000x2100; FireRating: -; AcousticRating: 35dB
Type - Pset_ProductRequirements - Category: Doors
Type - Pset_QuantityTakeOff - Reference: SU-P-11 - 1000x2100
OverallHeight: 2100 mm; OverallWidth: 1000 mm; Material: EST. Metall. Alumiinium. Värvitud. RAL7023 (Concrete grey), __Metall silt heleroheline)
Pset_OpeningElementCommon - Reference: SU-P-11 - 1000x2100; sets with these values: 2

# IfcDoor: SMA_D02, 2-poolne:SU-M-01 - 1200x2100, SMA_D02, 2-poolne:SU-M-01 - 1200x2100:1000967
In: 0 Kelder
Type - ParameterTakesPrecedence: no; Sizeable: no; Material: <Unnamed> (3), __Metall silt hall (3), EST. Klaas. 3x. Default
Type - Pset_ConcreteElementGeneral - FireRating: EI-30
Type - Pset_DoorCommon - IsExternal: no; Reference: SU-M-01 - 1200x2100; FireRating: EI-30; AcousticRating: -
Type - Pset_ProductRequirements - Category: Doors
Type - Pset_QuantityTakeOff - Reference: SU-M-01 - 1200x2100
OverallHeight: 2100 mm; OverallWidth: 1200 mm; Material: __Metall silt hall
Pset_OpeningElementCommon - Reference: SU-M-01 - 1200x2100; sets with these values: 2

# IfcDoor: SMA_D02, 2-poolne:SU-M-04 - 1000x1800, SMA_D02, 2-poolne:SU-M-04 - 1000x1800:2404765
In: 0 Kelder
Type - ParameterTakesPrecedence: no; Sizeable: no; Material: EST. Klaas. 3x. Default, __Metall silt hall (3), <Unnamed> (3)
Type - Pset_ConcreteElementGeneral - FireRating: EI-30
Type - Pset_DoorCommon - IsExternal: no; Reference: SU-M-04 - 1000x1800; FireRating: EI-30; AcousticRating: -
Type - Pset_ProductRequirements - Category: Doors
Type - Pset_QuantityTakeOff - Reference: SU-M-04 - 1000x1800
OverallHeight: 1800 mm; OverallWidth: 1000 mm; Material: __Metall silt hall
Pset_OpeningElementCommon - Reference: SU-M-04 - 1000x1800; sets with these values: 2

# IfcDoor: SMA_D02, 2-poolne:SU-P-02 - 1500x2100, SMA_D02, 2-poolne:SU-P-02 - 1500x2100:999328
In: 0 Kelder
Type - ParameterTakesPrecedence: no; Sizeable: no; Material: <Unnamed> (3), EST. Metall. Alumiinium. Anodeeritud. Naturaalne, EST. Klaas. 3x. Default, __Metall silt korallroosa (2)
Type - Pset_ConcreteElementGeneral - FireRating: EI-30
Type - Pset_DoorCommon - IsExternal: no; Reference: SU-P-02 - 1500x2100; FireRating: EI-30; AcousticRating: 35dB
Type - Pset_ProductRequirements - Category: Doors
Type - Pset_QuantityTakeOff - Reference: SU-P-02 - 1500x2100
OverallHeight: 2100 mm; OverallWidth: 1500 mm; Material: EST. Metall. Alumiinium. Anodeeritud. Naturaalne, __Metall silt korallroosa, EST. Klaas. 3x. Default

# IfcDoor: SMA_D02, 2-poolne:SU-P-02 - 1500x2100, SMA_D02, 2-poolne:SU-P-02 - 1500x2100:999266
In: 0 Kelder
Type - ParameterTakesPrecedence: no; Sizeable: no; Material: __Metall silt korallroosa (2), EST. Metall. Alumiinium. Anodeeritud. Naturaalne, <Unnamed> (3), EST. Klaas. 3x. Default
Type - Pset_ConcreteElementGeneral - FireRating: EI-30
Type - Pset_DoorCommon - IsExternal: no; Reference: SU-P-02 - 1500x2100; FireRating: EI-30; AcousticRating: 35dB
Type - Pset_ProductRequirements - Category: Doors
Type - Pset_QuantityTakeOff - Reference: SU-P-02 - 1500x2100
OverallHeight: 2100 mm; OverallWidth: 1500 mm; Material: EST. Metall. Alumiinium. Anodeeritud. Naturaalne, __Metall silt korallroosa, EST. Klaas. 3x. Default
Pset_OpeningElementCommon - Reference: SU-P-02 - 1500x2100; sets with these values: 2

# IfcDoor: Schueco_FWS_ADS-70-HD_out_Family-02:FWS SI insert unit 4, Schueco_FWS_ADS-70-HD_out_Family-02:FWS SI insert unit 4:1574108
In: 1 Korrus
Type - ConstructionType: USERDEFINED; ParameterTakesPrecedence: no; Sizeable: no; Material: __Metal Tumehall, <Unnamed> (4), Glass
Type - Pset_ConcreteElementGeneral - FireRating: -; ConstructionType: Door, double-leaf, outward-opening
Type - Pset_DoorCommon - IsExternal: no; Reference: FWS SI insert unit 4; FireRating: -; AcousticRating: -
Type - Pset_ManufacturerTypeInformation - Manufacturer: Schueco International KG
Type - Pset_ProductRequirements - Category: Doors
Type - Pset_QuantityTakeOff - Reference: FWS SI insert unit 4
OverallHeight: 2154 mm; OverallWidth: 1814 mm; Material: __Metal Tumehall, Glass
Pset_DoorCommon - IsExternal: yes

# IfcDoor: Schueco_FWS_ADS-70-HD_out_Family-02:SU-AL-02 FWS SI insert unit 3, Schueco_FWS_ADS-70-HD_out_Family-02:SU-AL-02 FWS SI insert unit 3:1177687
In: 1 Korrus
Type - ConstructionType: USERDEFINED; ParameterTakesPrecedence: no; Sizeable: no; Material: <Unnamed> (4), EST. Metall. Alumiinium. Värvitud. RAL7023 (Concrete grey), Glass
Type - Pset_ConcreteElementGeneral - FireRating: -; ConstructionType: Door, double-leaf, outward-opening
Type - Pset_DoorCommon - IsExternal: no; Reference: SU-AL-02 FWS SI insert unit 3; FireRating: -; AcousticRating: -
Type - Pset_ManufacturerTypeInformation - Manufacturer: Schueco International KG
Type - Pset_ProductRequirements - Category: Doors
Type - Pset_QuantityTakeOff - Reference: SU-AL-02 FWS SI insert unit 3
OverallHeight: 2154 mm; OverallWidth: 1768 mm; Material: EST. Metall. Alumiinium. Värvitud. RAL7023 (Concrete grey), Glass
Pset_DoorCommon - IsExternal: yes

# IfcDoor: Schueco_FWS_ADS-70-HD_out_Family-02:VU-01 FWS SI insert unit, Schueco_FWS_ADS-70-HD_out_Family-02:VU-01 FWS SI insert unit:1171881
In: 1 Korrus
Type - ConstructionType: USERDEFINED; ParameterTakesPrecedence: no; Sizeable: no; Material: __Metal Tumehall, <Unnamed> (4), Glass
Type - Pset_ConcreteElementGeneral - FireRating: EI-30; ConstructionType: Door, double-leaf, outward-opening
Type - Pset_DoorCommon - IsExternal: no; Reference: VU-01 FWS SI insert unit; FireRating: EI-30; AcousticRating: 35dB
Type - Pset_ManufacturerTypeInformation - Manufacturer: Schueco International KG
Type - Pset_ProductRequirements - Category: Doors
Type - Pset_QuantityTakeOff - Reference: VU-01 FWS SI insert unit
OverallHeight: 2154 mm; OverallWidth: 1768 mm; Material: __Metal Tumehall, Glass
Pset_DoorCommon - IsExternal: yes

# IfcDoor: Schueco_FWS_ADS-70-HD_out_Family-02:VU-02 FWS SI insert unit 2, Schueco_FWS_ADS-70-HD_out_Family-02:VU-02 FWS SI insert unit 2:1177792
In: 1 Korrus
Type - ConstructionType: USERDEFINED; ParameterTakesPrecedence: no; Sizeable: no; Material: <Unnamed> (4), EST. Metall. Alumiinium. Värvitud. RAL7023 (Concrete grey), Glass
Type - Pset_ConcreteElementGeneral - FireRating: -; ConstructionType: Door, double-leaf, outward-opening
Type - Pset_DoorCommon - IsExternal: no; Reference: VU-02 FWS SI insert unit 2; FireRating: -; AcousticRating: 35dB
Type - Pset_ManufacturerTypeInformation - Manufacturer: Schueco International KG
Type - Pset_ProductRequirements - Category: Doors
Type - Pset_QuantityTakeOff - Reference: VU-02 FWS SI insert unit 2
OverallHeight: 2108 mm; OverallWidth: 1768 mm; Material: EST. Metall. Alumiinium. Värvitud. RAL7023 (Concrete grey), Glass
Pset_DoorCommon - IsExternal: yes

# IfcFlowFitting: BAKB-1-080-080-0, BAKB-1-0801:BAKB-1-0801:2249394
In: Katus
Type - Description: Kant; PredefinedType: BEND; Material: Default Surface 128
Type - Pset_DistributionFlowElementCommon - Reference: BAKB-1-0801
Type - Pset_ProductRequirements - Category: Duct Fittings
Type - Pset_QuantityTakeOff - Reference: BAKB-1-0801
Description: Bend; Group: Model Group:Katus:2248594
Pset_DistributionFlowElementCommon - sets with these values: 2

# IfcFlowFitting: BAKB-1-080-080-0, BAKB-11:BAKB-11:2249418
In: Katus
Type - Description: Kant; PredefinedType: BEND; Material: Default Surface 128
Type - Pset_DistributionFlowElementCommon - Reference: BAKB-11
Type - Pset_ProductRequirements - Category: Duct Fittings
Type - Pset_QuantityTakeOff - Reference: BAKB-11
Description: Bend; Group: Model Group:Katus:2248594
Pset_DistributionFlowElementCommon - sets with these values: 2

# IfcFlowFitting: BDEB-30-063, BDEB-301:BDEB-301:2249287
In: Katus
Type - Description: Ümar; PredefinedType: BEND; Material: Default Surface 128
Type - Pset_DistributionFlowElementCommon - Reference: BDEB-301
Type - Pset_ProductRequirements - Category: Duct Fittings
Type - Pset_QuantityTakeOff - Reference: BDEB-301
Description: Bend; Group: Model Group:Katus:2248594
Pset_DistributionFlowElementCommon - sets with these values: 2

# IfcFlowFitting: BDEB-90-020, BDEB1:BDEB1:2249266
In: Katus
Type - Description: Ümar; PredefinedType: BEND; Material: Default Surface 128
Type - Pset_DistributionFlowElementCommon - Reference: BDEB1
Type - Pset_ProductRequirements - Category: Duct Fittings
Type - Pset_QuantityTakeOff - Reference: BDEB1
Description: Bend; Group: Model Group:Katus:2248594
Pset_DistributionFlowElementCommon - sets with these values: 2

# IfcFlowFitting: BDEB-90-020, BDEB2:BDEB2:2249141
In: Katus
Type - Description: Ümar; PredefinedType: BEND; Material: Default Surface 128
Type - Pset_DistributionFlowElementCommon - Reference: BDEB2
Type - Pset_ProductRequirements - Category: Duct Fittings
Type - Pset_QuantityTakeOff - Reference: BDEB2
Description: Bend; Group: Model Group:Katus:2248594
Pset_DistributionFlowElementCommon - sets with these values: 2

# IfcFlowFitting: BDEB-90-025 (49)
In: Katus
Type - Description: Ümar; PredefinedType: BEND; Material: Default Surface 128
Type - Pset_DistributionFlowElementCommon - Reference: BDEB2
Type - Pset_ProductRequirements - Category: Duct Fittings
Type - Pset_QuantityTakeOff - Reference: BDEB2
Description: Bend; Group: Model Group:Katus:2248594
Pset_DistributionFlowElementCommon - sets with these values: 2
Name (BDEB2:BDEB2:...)
2249018
2249020
2249022
2249024
2249028
2249032
2249036
2249040
2249043
2249045
2249047
2249049
2249053
2249057
2249061
2249065
2249069
2249073
2249077
2249081
2249086
2249113
2249127
2249137
2249157
2249161
2249165
2249169
2249171
2249181
2249195
2249199
2249203
2249207
2249211
2249215
2249222
2249230
2249248
2249252
2249256
2249260
2249262
2249277
2249314
2249375
2249398
2249406
2249437

# IfcFlowFitting: BDEM-1-050, BDEM1:BDEM1:2249310
In: Katus
Type - Description: Ümar; PredefinedType: JUNCTION; Material: Default Surface 128
Type - Pset_DistributionFlowElementCommon - Reference: BDEM1
Type - Pset_ProductRequirements - Category: Duct Fittings
Type - Pset_QuantityTakeOff - Reference: BDEM1
Description: Joint part; Group: Model Group:Katus:2248594
Pset_DistributionFlowElementCommon - sets with these values: 2

# IfcFlowFitting: BDEM-1-050, BDEM2:BDEM2:2249324
In: Katus
Type - Description: Ümar; PredefinedType: JUNCTION; Material: Default Surface 128
Type - Pset_DistributionFlowElementCommon - Reference: BDEM2
Type - Pset_ProductRequirements - Category: Duct Fittings
Type - Pset_QuantityTakeOff - Reference: BDEM2
Description: Joint part; Group: Model Group:Katus:2248594
Pset_DistributionFlowElementCommon - sets with these values: 2

# IfcFlowFitting: BDET-1-031-025 (4)
In: Katus
Type - Description: Ümar; PredefinedType: JUNCTION; Material: Default Surface 128
Type - Pset_DistributionFlowElementCommon - Reference: BDET1
Type - Pset_ProductRequirements - Category: Duct Fittings
Type - Pset_QuantityTakeOff - Reference: BDET1
Description: T-branch; Group: Model Group:Katus:2248594
Pset_DistributionFlowElementCommon - sets with these values: 2
Name (BDET1:BDET1:...)
2249133
2249191
2249240
2249244

# IfcFlowFitting: BDET-1-040-025, BDET1:BDET1:2249149
In: Katus
Type - Description: Ümar; PredefinedType: JUNCTION; Material: Default Surface 128
Type - Pset_DistributionFlowElementCommon - Reference: BDET1
Type - Pset_ProductRequirements - Category: Duct Fittings
Type - Pset_QuantityTakeOff - Reference: BDET1
Description: T-branch; Group: Model Group:Katus:2248594
Pset_DistributionFlowElementCommon - sets with these values: 2

# IfcFlowFitting: BDET-1-040-025, BDET2:BDET2:2249351
In: Katus
Type - Description: Ümar; PredefinedType: JUNCTION; Material: Default Surface 128
Type - Pset_DistributionFlowElementCommon - Reference: BDET2
Type - Pset_ProductRequirements - Category: Duct Fittings
Type - Pset_QuantityTakeOff - Reference: BDET2
Description: T-branch; Group: Model Group:Katus:2248594
Pset_DistributionFlowElementCommon - sets with these values: 2

# IfcFlowFitting: BDET-1-040-031 (3)
In: Katus
Type - Description: Ümar; PredefinedType: JUNCTION; Material: Default Surface 128
Type - Pset_DistributionFlowElementCommon - Reference: BDET1
Type - Pset_ProductRequirements - Category: Duct Fittings
Type - Pset_QuantityTakeOff - Reference: BDET1
Description: T-branch; Group: Model Group:Katus:2248594
Pset_DistributionFlowElementCommon - sets with these values: 2
Name (BDET1:BDET1:...)
2249187
2249271
2249295

# IfcFlowFitting: BDET-1-050-031, BDET1:BDET1:2249291
In: Katus
Type - Description: Ümar; PredefinedType: JUNCTION; Material: Default Surface 128
Type - Pset_DistributionFlowElementCommon - Reference: BDET1
Type - Pset_ProductRequirements - Category: Duct Fittings
Type - Pset_QuantityTakeOff - Reference: BDET1
Description: T-branch; Group: Model Group:Katus:2248594
Pset_DistributionFlowElementCommon - sets with these values: 2

# IfcFlowFitting: BDET-1-050-040, BDET-1-0501:BDET-1-0501:2249177
In: Katus
Type - Description: Ümar; PredefinedType: JUNCTION; Material: Default Surface 128
Type - Pset_DistributionFlowElementCommon - Reference: BDET-1-0501
Type - Pset_ProductRequirements - Category: Duct Fittings
Type - Pset_QuantityTakeOff - Reference: BDET-1-0501
Description: T-branch; Group: Model Group:Katus:2248594
Pset_DistributionFlowElementCommon - sets with these values: 2

# IfcFlowFitting: BDET-1-050-050, BDET1:BDET1:2249328
In: Katus
Type - Description: Ümar; PredefinedType: JUNCTION; Material: Default Surface 128
Type - Pset_DistributionFlowElementCommon - Reference: BDET1
Type - Pset_ProductRequirements - Category: Duct Fittings
Type - Pset_QuantityTakeOff - Reference: BDET1
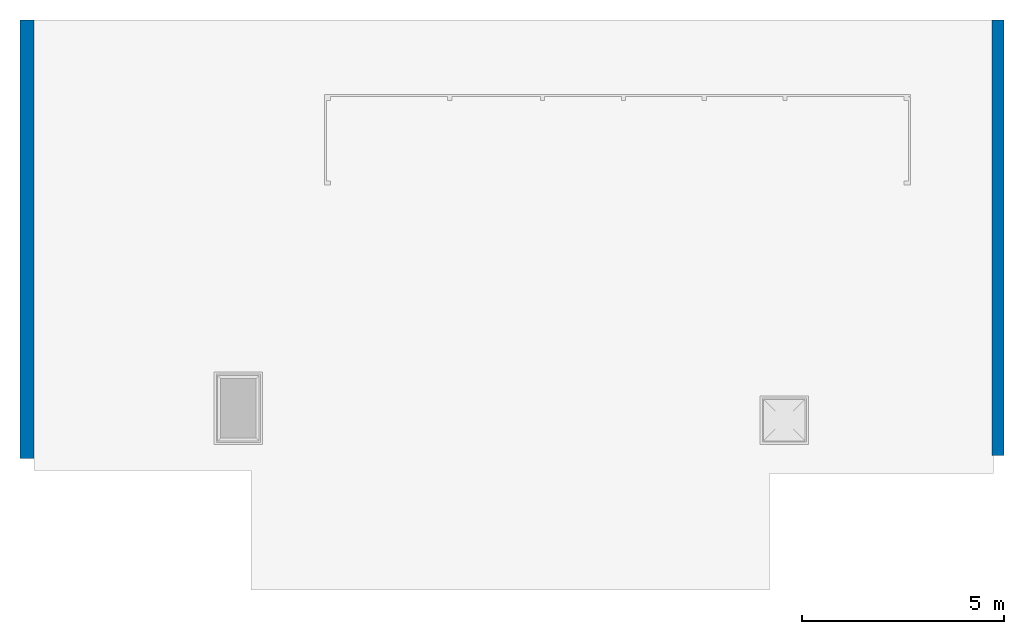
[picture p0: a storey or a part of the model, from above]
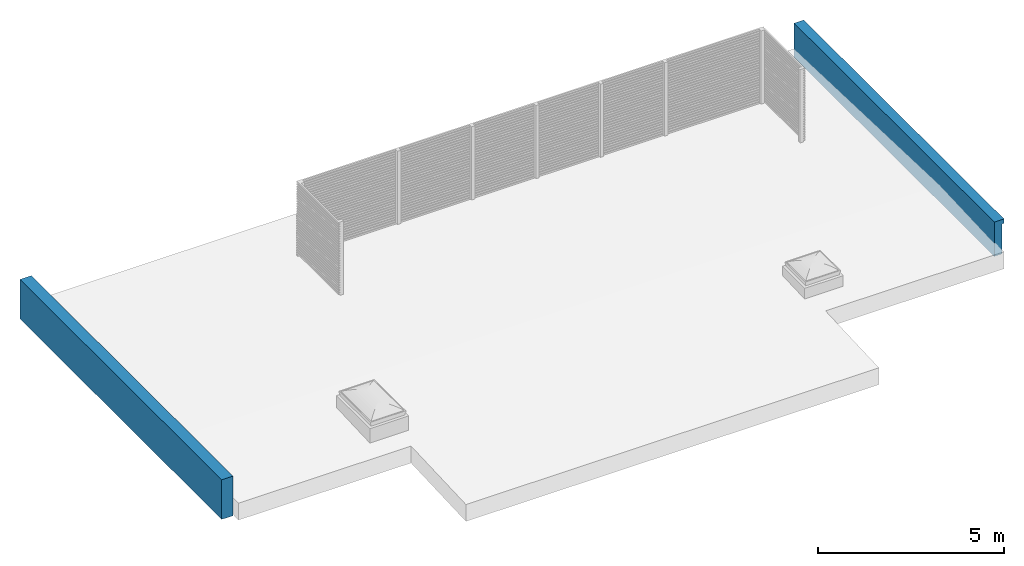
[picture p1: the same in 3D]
Properties of the parts of a building model (IFC2X3), part 4 of 7

# IfcFlowFitting: BDET-1-050-050, BDET1:BDET1:2249328
Description: T-branch; Group: Model Group:Katus:2248594
Pset_DistributionFlowElementCommon - sets with these values: 2

# IfcFlowFitting: BDET-1-063-040 (2)
In: Katus
Type - Description: Ümar; PredefinedType: JUNCTION; Material: Default Surface 128
Type - Pset_DistributionFlowElementCommon - Reference: BDET-1-0631
Type - Pset_ProductRequirements - Category: Duct Fittings
Type - Pset_QuantityTakeOff - Reference: BDET-1-0631
Description: T-branch; Group: Model Group:Katus:2248594
Pset_DistributionFlowElementCommon - sets with these values: 2
Name (BDET-1-0631:BDET-1-0631:...)
2249334
2249371

# IfcFlowFitting: DirectShapeType 11477:DirectShapeType 11477, DirectShapeType 11477:DirectShapeType 11477:2249218
In: Katus
Type - PredefinedType: TRANSITION; Material: Default Surface 128
Type - Pset_DistributionFlowElementCommon - Reference: DirectShapeType 11477
Type - Pset_ProductRequirements - Category: Duct Fittings
Type - Pset_QuantityTakeOff - Reference: DirectShapeType 11477
Description: Reduction; Group: Model Group:Katus:2248594
Pset_DistributionFlowElementCommon - sets with these values: 2

# IfcFlowFitting: DirectShapeType 11686:DirectShapeType 11686, DirectShapeType 11686:DirectShapeType 11686:2249234
In: Katus
Type - Description: Ümar; PredefinedType: JUNCTION; Material: Default Surface 128
Type - Pset_DistributionFlowElementCommon - Reference: DirectShapeType 11686
Type - Pset_ProductRequirements - Category: Duct Fittings
Type - Pset_QuantityTakeOff - Reference: DirectShapeType 11686
Description: S-part; Group: Model Group:Katus:2248594
Pset_DistributionFlowElementCommon - sets with these values: 2

# IfcFlowFitting: DirectShapeType 14370:DirectShapeType 14370, DirectShapeType 14370:DirectShapeType 14370:2249269
In: Katus
Type - PredefinedType: TRANSITION; Material: Default Surface 128
Type - Pset_DistributionFlowElementCommon - Reference: DirectShapeType 14370
Type - Pset_ProductRequirements - Category: Duct Fittings
Type - Pset_QuantityTakeOff - Reference: DirectShapeType 14370
Description: Reduction; Group: Model Group:Katus:2248594
Pset_DistributionFlowElementCommon - sets with these values: 2

# IfcFlowFitting: DirectShapeType 14875:DirectShapeType 14875, DirectShapeType 14875:DirectShapeType 14875:2249283
In: Katus
Type - Description: Ümar; PredefinedType: JUNCTION; Material: Default Surface 128
Type - Pset_DistributionFlowElementCommon - Reference: DirectShapeType 14875
Type - Pset_ProductRequirements - Category: Duct Fittings
Type - Pset_QuantityTakeOff - Reference: DirectShapeType 14875
Description: X-branch; Group: Model Group:Katus:2248594
Pset_DistributionFlowElementCommon - sets with these values: 2

# IfcFlowFitting: DirectShapeType 16358:DirectShapeType 16358, DirectShapeType 16358:DirectShapeType 16358:2249296
In: Katus
Type - PredefinedType: TRANSITION; Material: Default Surface 128
Type - Pset_DistributionFlowElementCommon - Reference: DirectShapeType 16358
Type - Pset_ProductRequirements - Category: Duct Fittings
Type - Pset_QuantityTakeOff - Reference: DirectShapeType 16358
Description: Reduction; Group: Model Group:Katus:2248594
Pset_DistributionFlowElementCommon - sets with these values: 2

# IfcFlowFitting: DirectShapeType 16451:DirectShapeType 16451, DirectShapeType 16451:DirectShapeType 16451:2249297
In: Katus
Type - PredefinedType: TRANSITION; Material: Default Surface 128
Type - Pset_DistributionFlowElementCommon - Reference: DirectShapeType 16451
Type - Pset_ProductRequirements - Category: Duct Fittings
Type - Pset_QuantityTakeOff - Reference: DirectShapeType 16451
Description: Reduction; Group: Model Group:Katus:2248594
Pset_DistributionFlowElementCommon - sets with these values: 2

# IfcFlowFitting: DirectShapeType 16561:DirectShapeType 16561, DirectShapeType 16561:DirectShapeType 16561:2249301
In: Katus
Type - Description: Ümar; PredefinedType: BEND; Material: Default Surface 128
Type - Pset_DistributionFlowElementCommon - Reference: DirectShapeType 16561
Type - Pset_ProductRequirements - Category: Duct Fittings
Type - Pset_QuantityTakeOff - Reference: DirectShapeType 16561
Description: Bend; Group: Model Group:Katus:2248594
Pset_DistributionFlowElementCommon - sets with these values: 2

# IfcFlowFitting: DirectShapeType 17129:DirectShapeType 17129, DirectShapeType 17129:DirectShapeType 17129:2249303
In: Katus
Type - Description: Ümar; PredefinedType: JUNCTION; Material: Default Surface 128
Type - Pset_DistributionFlowElementCommon - Reference: DirectShapeType 17129
Type - Pset_ProductRequirements - Category: Duct Fittings
Type - Pset_QuantityTakeOff - Reference: DirectShapeType 17129
Description: S-part; Group: Model Group:Katus:2248594
Pset_DistributionFlowElementCommon - sets with these values: 2

# IfcFlowFitting: DirectShapeType 18414:DirectShapeType 18414, DirectShapeType 18414:DirectShapeType 18414:2249306
In: Katus
Type - PredefinedType: TRANSITION; Material: Default Surface 128
Type - Pset_DistributionFlowElementCommon - Reference: DirectShapeType 18414
Type - Pset_ProductRequirements - Category: Duct Fittings
Type - Pset_QuantityTakeOff - Reference: DirectShapeType 18414
Description: Reduction; Group: Model Group:Katus:2248594
Pset_DistributionFlowElementCommon - sets with these values: 2

# IfcFlowFitting: DirectShapeType 19034:DirectShapeType 19034, DirectShapeType 19034:DirectShapeType 19034:2249318
In: Katus
Type - Description: Kant; PredefinedType: TRANSITION; Material: Default Surface 128
Type - Pset_DistributionFlowElementCommon - Reference: DirectShapeType 19034
Type - Pset_ProductRequirements - Category: Duct Fittings
Type - Pset_QuantityTakeOff - Reference: DirectShapeType 19034
Description: Reduction; Group: Model Group:Katus:2248594
Pset_DistributionFlowElementCommon - sets with these values: 2

# IfcFlowFitting: DirectShapeType 20034:DirectShapeType 20034, DirectShapeType 20034:DirectShapeType 20034:2249337
In: Katus
Type - PredefinedType: TRANSITION; Material: Default Surface 128
Type - Pset_DistributionFlowElementCommon - Reference: DirectShapeType 20034
Type - Pset_ProductRequirements - Category: Duct Fittings
Type - Pset_QuantityTakeOff - Reference: DirectShapeType 20034
Description: Reduction; Group: Model Group:Katus:2248594
Pset_DistributionFlowElementCommon - sets with these values: 2

# IfcFlowFitting: DirectShapeType 20144:DirectShapeType 20144, DirectShapeType 20144:DirectShapeType 20144:2249341
In: Katus
Type - Description: Ümar; PredefinedType: BEND; Material: Default Surface 128
Type - Pset_DistributionFlowElementCommon - Reference: DirectShapeType 20144
Type - Pset_ProductRequirements - Category: Duct Fittings
Type - Pset_QuantityTakeOff - Reference: DirectShapeType 20144
Description: Bend; Group: Model Group:Katus:2248594
Pset_DistributionFlowElementCommon - sets with these values: 2

# IfcFlowFitting: DirectShapeType 20731:DirectShapeType 20731, DirectShapeType 20731:DirectShapeType 20731:2249344
In: Katus
Type - PredefinedType: TRANSITION; Material: Default Surface 128
Type - Pset_DistributionFlowElementCommon - Reference: DirectShapeType 20731
Type - Pset_ProductRequirements - Category: Duct Fittings
Type - Pset_QuantityTakeOff - Reference: DirectShapeType 20731
Description: Reduction; Group: Model Group:Katus:2248594
Pset_DistributionFlowElementCommon - sets with these values: 2

# IfcFlowFitting: DirectShapeType 20825:DirectShapeType 20825, DirectShapeType 20825:DirectShapeType 20825:2249345
In: Katus
Type - PredefinedType: TRANSITION; Material: Default Surface 128
Type - Pset_DistributionFlowElementCommon - Reference: DirectShapeType 20825
Type - Pset_ProductRequirements - Category: Duct Fittings
Type - Pset_QuantityTakeOff - Reference: DirectShapeType 20825
Description: Reduction; Group: Model Group:Katus:2248594
Pset_DistributionFlowElementCommon - sets with these values: 2

# IfcFlowFitting: DirectShapeType 21299:DirectShapeType 21299, DirectShapeType 21299:DirectShapeType 21299:2249353
In: Katus
Type - Description: Ümar; PredefinedType: JUNCTION; Material: Default Surface 128
Type - Pset_DistributionFlowElementCommon - Reference: DirectShapeType 21299
Type - Pset_ProductRequirements - Category: Duct Fittings
Type - Pset_QuantityTakeOff - Reference: DirectShapeType 21299
Description: S-part; Group: Model Group:Katus:2248594
Pset_DistributionFlowElementCommon - sets with these values: 2

# IfcFlowFitting: DirectShapeType 22571:DirectShapeType 22571, DirectShapeType 22571:DirectShapeType 22571:2249355
In: Katus
Type - Description: Ümar; PredefinedType: JUNCTION; Material: Default Surface 128
Type - Pset_DistributionFlowElementCommon - Reference: DirectShapeType 22571
Type - Pset_ProductRequirements - Category: Duct Fittings
Type - Pset_QuantityTakeOff - Reference: DirectShapeType 22571
Description: S-part; Group: Model Group:Katus:2248594
Pset_DistributionFlowElementCommon - sets with these values: 2

# IfcFlowFitting: DirectShapeType 23843:DirectShapeType 23843, DirectShapeType 23843:DirectShapeType 23843:2249357
In: Katus
Type - Description: Ümar; PredefinedType: BEND; Material: Default Surface 128
Type - Pset_DistributionFlowElementCommon - Reference: DirectShapeType 23843
Type - Pset_ProductRequirements - Category: Duct Fittings
Type - Pset_QuantityTakeOff - Reference: DirectShapeType 23843
Description: Bend; Group: Model Group:Katus:2248594
Pset_DistributionFlowElementCommon - sets with these values: 2

# IfcFlowFitting: DirectShapeType 24448:DirectShapeType 24448, DirectShapeType 24448:DirectShapeType 24448:2249362
In: Katus
Type - PredefinedType: TRANSITION; Material: Default Surface 128
Type - Pset_DistributionFlowElementCommon - Reference: DirectShapeType 24448
Type - Pset_ProductRequirements - Category: Duct Fittings
Type - Pset_QuantityTakeOff - Reference: DirectShapeType 24448
Description: Reduction; Group: Model Group:Katus:2248594
Pset_DistributionFlowElementCommon - sets with these values: 2

# IfcFlowFitting: DirectShapeType 24561:DirectShapeType 24561, DirectShapeType 24561:DirectShapeType 24561:2249365
In: Katus
Type - PredefinedType: TRANSITION; Material: Default Surface 128
Type - Pset_DistributionFlowElementCommon - Reference: DirectShapeType 24561
Type - Pset_ProductRequirements - Category: Duct Fittings
Type - Pset_QuantityTakeOff - Reference: DirectShapeType 24561
Description: Reduction; Group: Model Group:Katus:2248594
Pset_DistributionFlowElementCommon - sets with these values: 2

# IfcFlowFitting: DirectShapeType 24808:DirectShapeType 24808, DirectShapeType 24808:DirectShapeType 24808:2249384
In: Katus
Type - Description: Ümar; Material: Default Surface 128
Type - Pset_DistributionFlowElementCommon - Reference: DirectShapeType 24808
Type - Pset_ProductRequirements - Category: Duct Fittings
Type - Pset_QuantityTakeOff - Reference: DirectShapeType 24808
Description: N-branch; Group: Model Group:Katus:2248594
Pset_DistributionFlowElementCommon - sets with these values: 2

# IfcFlowFitting: DirectShapeType 25100:DirectShapeType 25100, DirectShapeType 25100:DirectShapeType 25100:2249389
In: Katus
Type - PredefinedType: TRANSITION; Material: Default Surface 128
Type - Pset_DistributionFlowElementCommon - Reference: DirectShapeType 25100
Type - Pset_ProductRequirements - Category: Duct Fittings
Type - Pset_QuantityTakeOff - Reference: DirectShapeType 25100
Description: Reduction; Group: Model Group:Katus:2248594
Pset_DistributionFlowElementCommon - sets with these values: 2

# IfcFlowFitting: DirectShapeType 25194:DirectShapeType 25194, DirectShapeType 25194:DirectShapeType 25194:2249390
In: Katus
Type - PredefinedType: TRANSITION; Material: Default Surface 128
Type - Pset_DistributionFlowElementCommon - Reference: DirectShapeType 25194
Type - Pset_ProductRequirements - Category: Duct Fittings
Type - Pset_QuantityTakeOff - Reference: DirectShapeType 25194
Description: Reduction; Group: Model Group:Katus:2248594
Pset_DistributionFlowElementCommon - sets with these values: 2

# IfcFlowFitting: DirectShapeType 25875:DirectShapeType 25875, DirectShapeType 25875:DirectShapeType 25875:2249395
In: Katus
Type - PredefinedType: TRANSITION; Material: Default Surface 128
Type - Pset_DistributionFlowElementCommon - Reference: DirectShapeType 25875
Type - Pset_ProductRequirements - Category: Duct Fittings
Type - Pset_QuantityTakeOff - Reference: DirectShapeType 25875
Description: Reduction; Group: Model Group:Katus:2248594
Pset_DistributionFlowElementCommon - sets with these values: 2

# IfcFlowFitting: DirectShapeType 25969:DirectShapeType 25969, DirectShapeType 25969:DirectShapeType 25969:2249396
In: Katus
Type - PredefinedType: TRANSITION; Material: Default Surface 128
Type - Pset_DistributionFlowElementCommon - Reference: DirectShapeType 25969
Type - Pset_ProductRequirements - Category: Duct Fittings
Type - Pset_QuantityTakeOff - Reference: DirectShapeType 25969
Description: Reduction; Group: Model Group:Katus:2248594
Pset_DistributionFlowElementCommon - sets with these values: 2

# IfcFlowFitting: DirectShapeType 26459:DirectShapeType 26459 (2)
In: Katus
Type - Description: Ümar; PredefinedType: BEND; Material: Default Surface 128
Type - Pset_DistributionFlowElementCommon - Reference: DirectShapeType 26459
Type - Pset_ProductRequirements - Category: Duct Fittings
Type - Pset_QuantityTakeOff - Reference: DirectShapeType 26459
Description: Bend; Group: Model Group:Katus:2248594
Pset_DistributionFlowElementCommon - sets with these values: 2
Name (DirectShapeType 26459:DirectShapeType 26459:...)
2249402
2249408

# IfcFlowFitting: DirectShapeType 27108:DirectShapeType 27108, DirectShapeType 27108:DirectShapeType 27108:2249414
In: Katus
Type - Description: Kant; PredefinedType: TRANSITION; Material: Default Surface 128
Type - Pset_DistributionFlowElementCommon - Reference: DirectShapeType 27108
Type - Pset_ProductRequirements - Category: Duct Fittings
Type - Pset_QuantityTakeOff - Reference: DirectShapeType 27108
Description: Reduction; Group: Model Group:Katus:2248594
Pset_DistributionFlowElementCommon - sets with these values: 2

# IfcFlowFitting: DirectShapeType 28045:DirectShapeType 28045, DirectShapeType 28045:DirectShapeType 28045:2249424
In: Katus
Type - PredefinedType: TRANSITION; Material: Default Surface 128
Type - Pset_DistributionFlowElementCommon - Reference: DirectShapeType 28045
Type - Pset_ProductRequirements - Category: Duct Fittings
Type - Pset_QuantityTakeOff - Reference: DirectShapeType 28045
Description: Reduction; Group: Model Group:Katus:2248594
Pset_DistributionFlowElementCommon - sets with these values: 2

# IfcFlowFitting: DirectShapeType 28092:DirectShapeType 28092, DirectShapeType 28092:DirectShapeType 28092:2249427
In: Katus
Type - PredefinedType: TRANSITION; Material: Default Surface 128
Type - Pset_DistributionFlowElementCommon - Reference: DirectShapeType 28092
Type - Pset_ProductRequirements - Category: Duct Fittings
Type - Pset_QuantityTakeOff - Reference: DirectShapeType 28092
Description: Reduction; Group: Model Group:Katus:2248594
Pset_DistributionFlowElementCommon - sets with these values: 2

# IfcFlowFitting: DirectShapeType 28203:DirectShapeType 28203, DirectShapeType 28203:DirectShapeType 28203:2249430
In: Katus
Type - PredefinedType: TRANSITION; Material: Default Surface 128
Type - Pset_DistributionFlowElementCommon - Reference: DirectShapeType 28203
Type - Pset_ProductRequirements - Category: Duct Fittings
Type - Pset_QuantityTakeOff - Reference: DirectShapeType 28203
Description: Reduction; Group: Model Group:Katus:2248594
Pset_DistributionFlowElementCommon - sets with these values: 2

# IfcFlowFitting: DirectShapeType 28398:DirectShapeType 28398, DirectShapeType 28398:DirectShapeType 28398:2249438
In: Katus
Type - PredefinedType: TRANSITION; Material: Default Surface 128
Type - Pset_DistributionFlowElementCommon - Reference: DirectShapeType 28398
Type - Pset_ProductRequirements - Category: Duct Fittings
Type - Pset_QuantityTakeOff - Reference: DirectShapeType 28398
Description: Reduction; Group: Model Group:Katus:2248594
Pset_DistributionFlowElementCommon - sets with these values: 2

# IfcFlowFitting: DirectShapeType 3998:DirectShapeType 3998, DirectShapeType 3998:DirectShapeType 3998:2249084
In: Katus
Type - PredefinedType: TRANSITION; Material: Default Surface 128
Type - Pset_DistributionFlowElementCommon - Reference: DirectShapeType 3998
Type - Pset_ProductRequirements - Category: Duct Fittings
Type - Pset_QuantityTakeOff - Reference: DirectShapeType 3998
Description: Reduction; Group: Model Group:Katus:2248594
Pset_DistributionFlowElementCommon - sets with these values: 2

# IfcFlowFitting: DirectShapeType 4064:DirectShapeType 4064, DirectShapeType 4064:DirectShapeType 4064:2249090
In: Katus
Type - Description: Kant; PredefinedType: BEND; Material: Default Surface 128
Type - Pset_DistributionFlowElementCommon - Reference: DirectShapeType 4064
Type - Pset_ProductRequirements - Category: Duct Fittings
Type - Pset_QuantityTakeOff - Reference: DirectShapeType 4064
Description: Bend; Group: Model Group:Katus:2248594
Pset_DistributionFlowElementCommon - sets with these values: 2

# IfcFlowFitting: DirectShapeType 4232:DirectShapeType 4232, DirectShapeType 4232:DirectShapeType 4232:2249091
In: Katus
Type - PredefinedType: TRANSITION; Material: Default Surface 128
Type - Pset_DistributionFlowElementCommon - Reference: DirectShapeType 4232
Type - Pset_ProductRequirements - Category: Duct Fittings
Type - Pset_QuantityTakeOff - Reference: DirectShapeType 4232
Description: Reduction; Group: Model Group:Katus:2248594
Pset_DistributionFlowElementCommon - sets with these values: 2

# IfcFlowFitting: DirectShapeType 4446:DirectShapeType 4446, DirectShapeType 4446:DirectShapeType 4446:2249117
In: Katus
Type - Description: Ümar; PredefinedType: BEND; Material: Default Surface 128
Type - Pset_DistributionFlowElementCommon - Reference: DirectShapeType 4446
Type - Pset_ProductRequirements - Category: Duct Fittings
Type - Pset_QuantityTakeOff - Reference: DirectShapeType 4446
Description: Bend; Group: Model Group:Katus:2248594
Pset_DistributionFlowElementCommon - sets with these values: 2

# IfcFlowFitting: DirectShapeType 5031:DirectShapeType 5031, DirectShapeType 5031:DirectShapeType 5031:2249121
In: Katus
Type - Description: Ümar; PredefinedType: JUNCTION; Material: Default Surface 128
Type - Pset_DistributionFlowElementCommon - Reference: DirectShapeType 5031
Type - Pset_ProductRequirements - Category: Duct Fittings
Type - Pset_QuantityTakeOff - Reference: DirectShapeType 5031
Description: S-part; Group: Model Group:Katus:2248594
Pset_DistributionFlowElementCommon - sets with these values: 2

# IfcFlowFitting: DirectShapeType 7364:DirectShapeType 7364, DirectShapeType 7364:DirectShapeType 7364:2249145
In: Katus
Type - Description: Ümar; PredefinedType: BEND; Material: Default Surface 128
Type - Pset_DistributionFlowElementCommon - Reference: DirectShapeType 7364
Type - Pset_ProductRequirements - Category: Duct Fittings
Type - Pset_QuantityTakeOff - Reference: DirectShapeType 7364
Description: Bend; Group: Model Group:Katus:2248594
Pset_DistributionFlowElementCommon - sets with these values: 2

# IfcFlowFitting: DirectShapeType 8311:DirectShapeType 8311 (2)
In: Katus
Type - Description: Ümar; PredefinedType: BEND; Material: Default Surface 128
Type - Pset_DistributionFlowElementCommon - Reference: DirectShapeType 8311
Type - Pset_ProductRequirements - Category: Duct Fittings
Type - Pset_QuantityTakeOff - Reference: DirectShapeType 8311
Description: Bend; Group: Model Group:Katus:2248594
Pset_DistributionFlowElementCommon - sets with these values: 2
Name (DirectShapeType 8311:DirectShapeType 8311:...)
2249153
2249379

# IfcFlowSegment: BAKK-1-080-080-0 (6)
In: Katus
Type - PredefinedType: RIGIDSEGMENT; Material: Default Surface 128
Type - Pset_DistributionFlowElementCommon - Reference: BAKK-1-080-0801
Type - Pset_ProductRequirements - Category: Ducts
Type - Pset_QuantityTakeOff - Reference: BAKK-1-080-0801
Description: Duct; Group: Model Group:Katus:2248594
Pset_DistributionFlowElementCommon - sets with these values: 2
Name (BAKK-1-080-0801:BAKK-1-080-0801:...)
2249083
2249088
2249109
2249392
2249416
2249420

# IfcFlowSegment: BDEK-6-031 (105)
In: Katus
Type - PredefinedType: RIGIDSEGMENT; Material: Default Surface 128
Type - Pset_DistributionFlowElementCommon - Reference: BDEK-61
Type - Pset_ProductRequirements - Category: Ducts
Type - Pset_QuantityTakeOff - Reference: BDEK-61
Description: Duct; Group: Model Group:Katus:2248594
Pset_DistributionFlowElementCommon - sets with these values: 2
Name (BDEK-61:BDEK-61:...)
2249026
2249030
2249034
2249038
2249051
2249055
2249059
2249063
2249067
2249071
2249075
2249079
2249093
2249095
2249097
2249099
2249101
2249103
2249105
2249107
2249111
2249115
2249119
2249123
2249125
2249129
2249131
2249135
2249139
2249143
2249147
2249151
2249155
2249159
2249163
2249167
2249173
2249175
2249179
2249183
2249185
2249189
2249193
2249197
2249201
2249205
2249209
2249213
2249217
2249220
2249224
2249226
2249228
2249232
2249236
2249238
2249242
2249246
2249250
2249254
2249258
2249264
2249268
2249273
2249275
2249279
2249281
2249285
2249289
2249293
2249299
2249305
2249308
2249312
2249316
2249320
2249322
2249326
2249330
2249332
2249336
2249339
2249343
2249347
2249349
2249359
2249361
2249364
2249367
2249369
2249373
2249377
2249381
2249383
2249386
2249388
2249400
2249404
2249410
2249412
2249422
2249426
2249429
2249433
2249435

# IfcFlowTerminal: Bath&ShowerMixer-(Built-in)-Vitra-OriginSeries-A42619:Bath&ShowerMixer-Vitra-OriginSeries(Chrome)-A42619 (2)
Type - Material: Vitra-Chrome
Type - Pset_ElementShading - Color: Chrome
Type - Pset_ManufacturerTypeInformation - Manufacturer: Hansgrohe
Type - Pset_ProductRequirements - Category: Plumbing Fixtures
Type - Pset_QuantityTakeOff - Reference: Bath&ShowerMixer-Vitra-OriginSeries(Chrome)-A42619
Pset_DistributionFlowElementCommon - Reference: Bath&ShowerMixer-Vitra-OriginSeries(Chrome)-A42619; sets with these values: 3
Pset_ElementShading - sets with these values: 2
Pset_ManufacturerTypeInformation - sets with these values: 2
Pset_ProductRequirements - sets with these values: 2
Name (Bath&ShowerMixer-(Built-in)-Vitra-OriginSeries-A42619:Bath&ShowerMixer-Vitra-OriginSeries(Chrome)-A42619:...) | In
2392830 | T101
2393006 | 101E

# IfcFlowTerminal: Dušši segisti:SA-00 - Dušš Oras Nova + Apollo 530 ECO (24)
Type - Classification: D2010 Plumbing Fixtures (Uniformat); Material: Gustavsberg Chrome - Polished
Type - Pset_ManufacturerTypeInformation - Manufacturer: Oras
Type - Pset_ProductRequirements - Category: Plumbing Fixtures
Type - Pset_QuantityTakeOff - Reference: SA-00 - Dušš Oras Nova + Apollo 530 ECO
Pset_DistributionFlowElementCommon - Reference: SA-00 - Dušš Oras Nova + Apollo 530 ECO; sets with these values: 3
Pset_ManufacturerTypeInformation - sets with these values: 2
Pset_ProductRequirements - sets with these values: 2
Name (Dušši segisti:SA-00 - Dušš Oras Nova + Apollo 530 ECO:...) | In
927014 | 204D
927149 | 205C
928283 | 202D
928300 | 203C
960013 | 105C
964291 | 102D
984763 | 305C
984802 | 302D
990765 | 308E
1003803 | 008
1003821 | 008
1008217 | 008
1088941 | 103C
1088985 | 104D
1096544 | 304D
1096548 | 303C
1133726 | 301E
1149609 | 108F
1152890 | 101E
1165601 | 208E
1165627 | 201E
1689746 | 306D
1689975 | 206D
1690031 | 106D

# IfcFlowTerminal: EYMA-2-080, EYMA-21:EYMA-21:2249423
In: Katus
Type - Description: EYAMA-2; Material: Default Surface 128
Type - Pset_DistributionFlowElementCommon - Reference: EYMA-21
Type - Pset_ProductRequirements - Category: Air Terminals
Type - Pset_QuantityTakeOff - Reference: EYMA-21
Description: Exhaust air device; Group: Model Group:Katus:2248594
Pset_DistributionFlowElementCommon - sets with these values: 2

# IfcFlowTerminal: Flush_System-Push_Plates_Mechanical&Pneumatic-Valsir-TropeaS_WinnerS_CubikS-P1-00:P1_Polished_Chrome, Flush_System-Push_Plates_Mechanical&Pneumatic-Valsir-TropeaS_WinnerS_CubikS-P1-00:P1_Polished_Chrome:1432566
In: 205D
Type - Material: POLISHED CHROME - ABS - Valsir® PLATES (3)
Type - Pset_ManufacturerTypeInformation - Manufacturer: Valsir S.p.A.
Type - Pset_ProductRequirements - Category: Plumbing Fixtures
Type - Pset_QuantityTakeOff - Reference: P1_Polished_Chrome
Material: POLISHED CHROME - ABS - Valsir® PLATES
Pset_DistributionFlowElementCommon - Reference: P1_Polished_Chrome; sets with these values: 3
Pset_ManufacturerTypeInformation - sets with these values: 2
Pset_ProductRequirements - sets with these values: 2

# IfcFlowTerminal: M_Sink Vanity-Square:500 x 440mm (2)
In: 207
Type - Material: Porcelain - Linen, Metal - Steel, Polished
Type - Pset_ProductRequirements - Category: Plumbing Fixtures
Type - Pset_QuantityTakeOff - Reference: 500 x 440mm
Pset_DistributionFlowElementCommon - Reference: 500 x 440mm; sets with these values: 3
Pset_ProductRequirements - sets with these values: 2
Name (M_Sink Vanity-Square:500 x 440mm:...)
1480243
1480654

# IfcFlowTerminal: SMA_Inva valamu:Standard, SMA_Inva valamu:Standard:1216161
In: 101E
Type - Classification: D2010400 Sinks (Uniformat); Material: Gustavsberg Porcelain - White
Type - Pset_ManufacturerTypeInformation - ArticleNumber: GB1074010101; Manufacturer: Gustavsberg
Type - Pset_ProductRequirements - Category: Plumbing Fixtures
Type - Pset_QuantityTakeOff - Reference: Standard
Pset_DistributionFlowElementCommon - Reference: Standard; sets with these values: 3
Pset_ManufacturerTypeInformation - sets with these values: 2
Pset_ProductRequirements - sets with these values: 2

# IfcFlowTerminal: SMA_Pro A allas 28x48cm:SA-00 - Laufen Pro 480 + Oras Saga PAREMPOOLNE (8)
Type - Material: Chrome, Duravit Keramik
Type - Pset_ManufacturerTypeInformation - ArticleNumber: PL8159550001041F; Manufacturer: Laufen + Hansgrohe
Type - Pset_ProductRequirements - Category: Plumbing Fixtures
Type - Pset_QuantityTakeOff - Reference: SA-00 - Laufen Pro 480 + Oras Saga PAREMPOOLNE
Pset_DistributionFlowElementCommon - Reference: SA-00 - Laufen Pro 480 + Oras Saga PAREMPOOLNE
Name (SMA_Pro A allas 28x48cm:SA-00 - Laufen Pro 480 + Oras Saga PAREMPOOLNE:...) | In | Pset_DistributionFlowElementCommon, sets with these values | Pset_ManufacturerTypeInformation, sets with these values = Pset_ProductRequirements, sets with these values
927013 | 204D | 2
928327 | 202D | 3 | 2
964298 | 102D | 3 | 2
984809 | 302D | 3 | 2
1089195 | 104D | 3 | 2
1096543 | 304D | 3 | 2
1185656 | 201E | 3 | 2
1189507 | 301E | 3 | 2

# IfcFlowTerminal: SMA_Pro A allas 28x48cm:SA-00 - Laufen Pro 480 + Oras Saga PAREMPOOLNE KÄSIDUŠŠIGA (11)
Type - Material: Chrome, Duravit Keramik
Type - Pset_ManufacturerTypeInformation - ArticleNumber: PL8159550001041F; Manufacturer: Laufen + Hansgrohe
Type - Pset_ProductRequirements - Category: Plumbing Fixtures
Type - Pset_QuantityTakeOff - Reference: SA-00 - Laufen Pro 480 + Oras Saga PAREMPOOLNE KÄSIDUŠŠIGA
Pset_DistributionFlowElementCommon - Reference: SA-00 - Laufen Pro 480 + Oras Saga PAREMPOOLNE KÄSIDUŠŠIGA; sets with these values: 3
Pset_ManufacturerTypeInformation - sets with these values: 2
Pset_ProductRequirements - sets with these values: 2
Name (SMA_Pro A allas 28x48cm:SA-00 - Laufen Pro 480 + Oras Saga PAREMPOOLNE KÄSIDUŠŠIGA:...) | In
1452865 | 308F
1464224 | 205D
1655380 | 208F
1655395 | 108G
1742474 | 305D
1742484 | 105D
1742594 | 203D
1742595 | 303D
1772812 | 306C
1782382 | 206C
1805655 | 106C

# IfcFlowTerminal: SMA_Pro A allas 28x48cm:SA-00 - Laufen Pro 480 + Oras Saga PAREMPOOLNE KÄSIDUŠŠIGA (3)
Type - Material: Duravit Keramik, Chrome
Type - Pset_ManufacturerTypeInformation - ArticleNumber: PL8159550001041F; Manufacturer: Laufen + Hansgrohe
Type - Pset_ProductRequirements - Category: Plumbing Fixtures
Type - Pset_QuantityTakeOff - Reference: SA-00 - Laufen Pro 480 + Oras Saga PAREMPOOLNE KÄSIDUŠŠIGA
Material: Chrome, Duravit Keramik
Pset_DistributionFlowElementCommon - Reference: SA-00 - Laufen Pro 480 + Oras Saga PAREMPOOLNE KÄSIDUŠŠIGA; sets with these values: 3
Pset_ManufacturerTypeInformation - sets with these values: 2
Pset_ProductRequirements - sets with these values: 2
Name (SMA_Pro A allas 28x48cm:SA-00 - Laufen Pro 480 + Oras Saga PAREMPOOLNE KÄSIDUŠŠIGA:...) | In
1214545 | 111
1308801 | 013
1742596 | 103D

# IfcFlowTerminal: SMA_Pro A allas 28x48cm:SA-00 - Laufen Pro 480 + Oras Saga VASAK POOLNE DUŠŠIGA (8)
Type - Material: Chrome, Duravit Keramik
Type - Pset_ManufacturerTypeInformation - ArticleNumber: PL8159550001041F; Manufacturer: Laufen + Hansgrohe
Type - Pset_ProductRequirements - Category: Plumbing Fixtures
Type - Pset_QuantityTakeOff - Reference: SA-00 - Laufen Pro 480 + Oras Saga VASAK POOLNE DUŠŠIGA
Pset_DistributionFlowElementCommon - Reference: SA-00 - Laufen Pro 480 + Oras Saga VASAK POOLNE DUŠŠIGA; sets with these values: 3
Pset_ManufacturerTypeInformation - sets with these values: 2
Pset_ProductRequirements - sets with these values: 2
Name (SMA_Pro A allas 28x48cm:SA-00 - Laufen Pro 480 + Oras Saga VASAK POOLNE DUŠŠIGA:...) | In
1732858 | 301F
1733218 | 201F
1742540 | 204C
1742541 | 304C
1742542 | 104C
1742591 | 202C
1742592 | 302C
1742593 | 102C

# IfcFlowTerminal: SMA_Pro A allas 28x48cm:SA-00 - Laufen Pro 480 + Oras Saga VASAKPOOLNE2 (12)
Type - Material: Chrome, Duravit Keramik
Type - Pset_ManufacturerTypeInformation - ArticleNumber: PL8159550001041F; Manufacturer: Laufen + Hansgrohe
Type - Pset_ProductRequirements - Category: Plumbing Fixtures
Type - Pset_QuantityTakeOff - Reference: SA-00 - Laufen Pro 480 + Oras Saga VASAKPOOLNE2
Pset_DistributionFlowElementCommon - Reference: SA-00 - Laufen Pro 480 + Oras Saga VASAKPOOLNE2; sets with these values: 3
Pset_ManufacturerTypeInformation - sets with these values: 2
Pset_ProductRequirements - sets with these values: 2
Name (SMA_Pro A allas 28x48cm:SA-00 - Laufen Pro 480 + Oras Saga VASAKPOOLNE2:...) | In
927148 | 205C
928299 | 203C
961657 | 105C
984780 | 305C
1087488 | 103C
1088243 | 106D
1096547 | 303C
1097291 | 306D
1163451 | 206D
1186849 | 108F
1189481 | 308E
1190811 | 208E

# IfcFlowTerminal: SMA_valamu 2:Rozměr 500x419x170 (2)
Type - Pset_ManufacturerTypeInformation - Manufacturer: IFÖ + Oras
Type - Pset_ProductRequirements - Category: Plumbing Fixtures
Type - Pset_QuantityTakeOff - Reference: Rozměr 500x419x170
Pset_DistributionFlowElementCommon - Reference: Rozměr 500x419x170; sets with these values: 3
Pset_ManufacturerTypeInformation - sets with these values: 2
Pset_ProductRequirements - sets with these values: 2
Name (SMA_valamu 2:Rozměr 500x419x170:...) | In
1004728 | 010
1018529 | 108A

# IfcFlowTerminal: Sanitary_Other_Metlex_Carina_GrabRail:300mm Chrome SS Grab Bar, Sanitary_Other_Metlex_Carina_GrabRail:300mm Chrome SS Grab Bar:2233844
In: 101E
Type - Material: Metlex_Stainless Steel, Chrome
Type - Pset_ManufacturerOccurrence - BarCode: 5012044104311
Type - Pset_ManufacturerTypeInformation - Manufacturer: Mediclinics
Type - Pset_ProductRequirements - Name: Stainless Steel Grab Bar; Category: Plumbing Fixtures
Type - Pset_QuantityTakeOff - Reference: 300mm Chrome SS Grab Bar
Pset_DistributionFlowElementCommon - Reference: 300mm Chrome SS Grab Bar; sets with these values: 3
Pset_ManufacturerOccurrence - sets with these values: 2
Pset_ManufacturerTypeInformation - sets with these values: 2
Pset_ProductRequirements - sets with these values: 2

# IfcFlowTerminal: Sanitary_Other_Metlex_Carina_GrabRail:450mm Chrome SS Grab Bar, Sanitary_Other_Metlex_Carina_GrabRail:450mm Chrome SS Grab Bar:2233842
In: 101E
Type - Material: Metlex_Stainless Steel, Chrome
Type - Pset_ManufacturerOccurrence - BarCode: 5012044104328
Type - Pset_ManufacturerTypeInformation - Manufacturer: Mediclinics
Type - Pset_ProductRequirements - Name: Stainless Steel Grab Bar; Category: Plumbing Fixtures
Type - Pset_QuantityTakeOff - Reference: 450mm Chrome SS Grab Bar
Pset_DistributionFlowElementCommon - Reference: 450mm Chrome SS Grab Bar; sets with these values: 3
Pset_ManufacturerOccurrence - sets with these values: 2
Pset_ManufacturerTypeInformation - sets with these values: 2
Pset_ProductRequirements - sets with these values: 2

# IfcFlowTerminal: USS/I-1400-800, USS/I-14001:USS/I-14001:2249431
In: Katus
Type - Description: USS; Material: Default Surface 128
Type - Pset_DistributionFlowElementCommon - Reference: USS/I-14001
Type - Pset_ProductRequirements - Category: Air Terminals
Type - Pset_QuantityTakeOff - Reference: USS/I-14001
Description: Outdoor air device; Group: Model Group:Katus:2248594
Pset_DistributionFlowElementCommon - sets with these values: 2

# IfcFlowTerminal: WC seinal:Tüüp 1 (22)
Type - Classification: D2010110 Water Closets - Single (Uniformat); Material: WC
Type - Pset_ManufacturerTypeInformation - Manufacturer: Gustavsberg
Type - Pset_ProductRequirements - Category: Plumbing Fixtures
Type - Pset_QuantityTakeOff - Reference: Tüüp 1
Pset_DistributionFlowElementCommon - Reference: Tüüp 1; sets with these values: 3
Pset_ManufacturerTypeInformation - sets with these values: 2
Pset_ProductRequirements - sets with these values: 2
Name (WC seinal:Tüüp 1:...) | In
1081766 | 104C
1081769 | 105D
1081772 | 103D
1081773 | 102C
1183277 | 106C
1184982 | 201F
1184983 | 204C
1184986 | 205D
1184987 | 203D
1184988 | 202C
1185005 | 206C
1185835 | 208F
1186749 | 108G
1189086 | 301F
1189087 | 304C
1189090 | 305D
1189091 | 303D
1189092 | 302C
1189109 | 206C
1189114 | 208F
1214197 | 1 Korrus
1308765 | 013

# IfcFlowTerminal: WC tavaline:SA-00 - Gustavsberg ARTic 4300, WC tavaline:SA-00 - Gustavsberg ARTic 4300:1315365
In: 101E
Type - Pset_ManufacturerTypeInformation - Manufacturer: Gustavsberg
Type - Pset_ProductRequirements - Category: Plumbing Fixtures
Type - Pset_QuantityTakeOff - Reference: SA-00 - Gustavsberg ARTic 4300
Pset_DistributionFlowElementCommon - Reference: SA-00 - Gustavsberg ARTic 4300; sets with these values: 3
Pset_ManufacturerTypeInformation - sets with these values: 2
Pset_ProductRequirements - sets with these values: 2

# IfcFurnishingElement: 3 patja:Divano_Diagonal (2)
In: 110
Type - Pset_ProductRequirements - Category: Casework
Type - Pset_QuantityTakeOff - Reference: Divano_Diagonal
Name (3 patja:Divano_Diagonal:...)
1244578
1244579

# IfcFurnishingElement: Base (1):600mm (2)
In: 308
Type - Material: Cabinets - Handles, Cabinets (2)
Type - Pset_ProductRequirements - Category: Casework
Type - Pset_QuantityTakeOff - Reference: 600mm
Material: Cabinets, Cabinets - Handles
Name (Base (1):600mm:...)
1443536
1443558

# IfcFurnishingElement: Base (3):0300mm, Base (3):0300mm:1444437
In: 308
Type - Material: Cabinets (2), Cabinets - Handles
Type - Pset_ProductRequirements - Category: Casework
Type - Pset_QuantityTakeOff - Reference: 0300mm
Material: Cabinets, Cabinets - Handles

# IfcFurnishingElement: Counter Top w Sink:600mm Depth, Counter Top w Sink:600mm Depth:1441808
In: 308
Type - Material: Laminate - Marble
Type - Pset_ProductRequirements - Category: Casework
Type - Pset_QuantityTakeOff - Reference: 600mm Depth

# IfcFurnishingElement: Exercise_Bike_4766:Exercise_Bike_4766, Exercise_Bike_4766:Exercise_Bike_4766:1008321
In: 005
Type - Material: plastic 2
Type - Pset_ProductRequirements - Category: Furniture
Type - Pset_QuantityTakeOff - Reference: Exercise_Bike_4766
Material: plastic 2, Plastic, Plastic - Black, Metal - Chrome, plastic 3

# IfcFurnishingElement: Furniture_Chairs_Great-Openings_Sparkeology-SLY_Chair:Standard (26)
Type - Material: Wood - Birch_tume, Plastic - Great Openings_Sparkeology - Black, __Metall 1
Type - Pset_FurnitureTypeCommon - Description: Juno tool, art 3600 või sellega samaväärne toode. Nelja jalaga polüpropüleenist avatud seljaavaga toon tumehall PT00005, Pilt on illustratiivse tähendusega ja toodud näidisena; NominalHeight: 831.85 mm
Type - Pset_ManufacturerTypeInformation - Manufacturer: Elke
Type - Pset_ProductRequirements - Category: Furniture
Type - Pset_QuantityTakeOff - Reference: Standard
Material: Plastic - Great Openings_Sparkeology - Black, __Metall 1, Wood - Birch_tume
Name (Furniture_Chairs_Great-Openings_Sparkeology-SLY_Chair:Standard:...) | In
1266443 | 107
1266444 | 107
1266448 | 107
1266451 | 107
1266452 | 107
1266453 | 107
1476966 | 307
1476985 | 307
1477068 | 307
1477069 | 307
1791983 | 3 Korrus A
1791984 | 3 Korrus A
1791987 | 3 Korrus A
1791988 | 3 Korrus A
1792052 | 207
1792053 | 207
1792056 | 207
1792057 | 207
2030205 | 3 korrus
2030206 | 3 korrus
2030207 | 3 korrus
2030208 | 3 korrus
2036968 | 301
2036969 | 301
2036970 | 301
2036971 | 301

# IfcFurnishingElement: Furniture_Chairs_Great-Openings_Sparkeology-SLY_Chair:Standard (26)
Type - Material: Wood - Birch_tume, __Metall 1, Plastic - Great Openings_Sparkeology - Black
Type - Pset_FurnitureTypeCommon - Description: Juno tool, art 3600 või sellega samaväärne toode. Nelja jalaga polüpropüleenist avatud seljaavaga toon tumehall PT00005, Pilt on illustratiivse tähendusega ja toodud näidisena; NominalHeight: 831.85 mm
Type - Pset_ManufacturerTypeInformation - Manufacturer: Elke
Type - Pset_ProductRequirements - Category: Furniture
Type - Pset_QuantityTakeOff - Reference: Standard
Material: Plastic - Great Openings_Sparkeology - Black, __Metall 1, Wood - Birch_tume
Name (Furniture_Chairs_Great-Openings_Sparkeology-SLY_Chair:Standard:...) | In
1266445 | 107
1266446 | 107
1266447 | 107
1266449 | 107
1266450 | 107
1266454 | 107
1477036 | 307
1477037 | 307
1477071 | 307
1477072 | 307
1791985 | 3 Korrus A
1791986 | 3 Korrus A
1791989 | 3 Korrus A
1791990 | 3 Korrus A
1792054 | 207
1792055 | 207
1792058 | 207
1792059 | 207
2036829 | 3 korrus
2036830 | 3 korrus
2036831 | 3 korrus
2036832 | 3 korrus
2036973 | 308
2036974 | 308
2036975 | 308
2036976 | 308

# IfcFurnishingElement: Furniture_Tables_Alias-Design_044-Kobi-Pad:Alias Kobi Pad 44, Furniture_Tables_Alias-Design_044-Kobi-Pad:Alias Kobi Pad 44:2076807
In: T101
Type - Material: <Unnamed> (2)
Type - Pset_FurnitureTypeCommon - Description: PET vildist pressitud iste. Valmistatud taaskasutatud plastikpudelitest. Vildi toon helehall, Metalljalad – pulbervärvitud mustaks
Type - Pset_ManufacturerTypeInformation - Manufacturer: Standard
Type - Pset_ProductRequirements - Category: Furniture
Type - Pset_QuantityTakeOff - Reference: Alias Kobi Pad 44

# IfcFurnishingElement: Green_Pedestals_250x800x620:Green_Pedestals_250x800x620 (3)
In: 001
Type - Material: Steel-Offecct-Pedestals-White-Lacquer
Type - Pset_FurnitureTypeCommon - Description: Lille pedestaals 600 x 250, H- 650 mm, lillepoti kõrgus 150 mm, pulbervärvitud metall - toon tumeroheline.; NominalHeight: 188976 mm
Type - Pset_ManufacturerTypeInformation - ArticleNumber: 625001-10; Manufacturer: Living -Elke
Type - Pset_ProductRequirements - Category: Furniture
Type - Pset_QuantityTakeOff - Reference: Green_Pedestals_250x800x620
Name (Green_Pedestals_250x800x620:Green_Pedestals_250x800x620:...)
1269812
1271921
1271964

# IfcFurnishingElement: Gym_weight_bench_set_14865:Gym_weight_bench_set_14865, Gym_weight_bench_set_14865:Gym_weight_bench_set_14865:1008320
In: 005
Type - Material: silver
Type - Pset_FurnitureTypeCommon - Description: Multifunktsionaalne treeningpink raam valmistatud terasest. Kasutaja maksimaalne kaal 150 kg. Tõstekang ning raskused ei kuulu komplekti. Maksimaalne kangi raskus 125 kg. jalalihaste treeningu maks raskus 45 kg rinnalihaste treeningu maks raskus 35 kg
Type - Pset_ManufacturerTypeInformation - Manufacturer: Sportfever
Type - Pset_ProductRequirements - Category: Furniture
Type - Pset_QuantityTakeOff - Reference: Gym_weight_bench_set_14865
Material: silver, black, white

# IfcFurnishingElement: Lockers x 2:Lockers x 2 (4)
Type - Material: Paint - Grey (2), Paint - White
Type - Pset_FurnitureTypeCommon - Description: Kapi korpus on kokku keevitatud ja pulbervärvitud. Ventilatsiooniavad paiknevad kapi põhjas ja laes. Korpus, uksed ja riiulid on helehalli värvi RAL 7035. Vasakul pool kolm riiulit, teisel pool kõgem ruum koristusvahenditele. Ukse küljes kolm konksu ja käterätikutoru. Kapil on reguleeritavad jalad, jalgade kõrgus on 150 mm
Type - Pset_ManufacturerTypeInformation - Manufacturer: Laoekspert OÜ
Type - Pset_ProductRequirements - Category: Furniture
Type - Pset_QuantityTakeOff - Reference: Lockers x 2
Material: Paint - Grey, Paint - White
Name (Lockers x 2:Lockers x 2:...) | In
2350456 | 201
2351314 | 208
2351741 | 301
2352101 | 308

# IfcFurnishingElement: M_Chair-Executive:M_Chair-Executive (48)
Type - Material: Plastic - Black (2), Textile - Slate Blue
Type - Pset_FurnitureTypeCommon - Description: Töötool IDEA või sellega samaväärne toode, Kattematerjal - Iste ja seljatugi polsterdatud kangaga Politex (50 000 Martindale), - Sünkroonmehhanism- Kiike jäikuse reguleerimine, vastavalt istuja kaalule. Istme kõrguse reguleerimine gaasamordiga. Kõrguses ja laiuses reguleeritavad käetoed.Jalarist must plastik, Pehmed rattad kõvadele põrandatele - ISO 9001, ISO 14001. Kõrgus 1180-1300 mm, Istme kõrgus 420-540 mm, Istme sügavus 460-590 mm, Istme laius 440 mm, Jalarist Ø 700 mm
Type - Pset_ManufacturerTypeInformation - Manufacturer: Standard
Type - Pset_ProductRequirements - Category: Furniture
Type - Pset_QuantityTakeOff - Reference: M_Chair-Executive
Material: Plastic - Black, Textile - Slate Blue
Name (M_Chair-Executive:M_Chair-Executive:...) | In
912981 | 208C
912983 | 201A
912987 | 205B
912988 | 205B
912989 | 206A
912990 | 206A
912992 | 208D
912993 | 208A
912996 | 208B
912999 | 204B
913000 | 204B
913005 | 203B
913006 | 203B
913007 | 202B
913008 | 202B
913012 | 201B
913013 | 201C
913102 | 201D
1085708 | 101A
1085712 | 105B
1085713 | 105B
1085714 | 106A
1085715 | 106A
1085718 | 104B
1085719 | 104B
1085724 | 103B
1085725 | 103B
1085726 | 102B
1085727 | 102B
1092640 | 308C
1092642 | 301A
1092646 | 305B
1092647 | 305B
1092648 | 306A
1092649 | 306A
1092651 | 308D
1092652 | 308A
1092655 | 308B
1092658 | 304B
1092659 | 304B
1092664 | 303B
1092665 | 303B
1092666 | 302B
1092667 | 302B
1092671 | 301B
1092672 | 301C
1092675 | 301D
1177056 | 109

# IfcFurnishingElement: M_Chair-Executive:M_Chair-Executive (49)
Type - Material: Textile - Slate Blue, Plastic - Black (2)
Type - Pset_FurnitureTypeCommon - Description: Töötool IDEA või sellega samaväärne toode, Kattematerjal - Iste ja seljatugi polsterdatud kangaga Politex (50 000 Martindale), - Sünkroonmehhanism- Kiike jäikuse reguleerimine, vastavalt istuja kaalule. Istme kõrguse reguleerimine gaasamordiga. Kõrguses ja laiuses reguleeritavad käetoed.Jalarist must plastik, Pehmed rattad kõvadele põrandatele - ISO 9001, ISO 14001. Kõrgus 1180-1300 mm, Istme kõrgus 420-540 mm, Istme sügavus 460-590 mm, Istme laius 440 mm, Jalarist Ø 700 mm
Type - Pset_ManufacturerTypeInformation - Manufacturer: Standard
Type - Pset_ProductRequirements - Category: Furniture
Type - Pset_QuantityTakeOff - Reference: M_Chair-Executive
Material: Plastic - Black, Textile - Slate Blue
Name (M_Chair-Executive:M_Chair-Executive:...) | In
912982 | 208C
912984 | 201A
912985 | 205A
912986 | 205A
912991 | 208D
912994 | 208A
912995 | 208B
912997 | 206B
912998 | 206B
913001 | 204A
913002 | 204A
913003 | 203A
913004 | 203A
913009 | 202A
913010 | 202A
913011 | 201B
913014 | 201C
913101 | 201D
1085710 | 105A
1085711 | 105A
1085716 | 106B
1085717 | 106B
1085720 | 104A
1085721 | 104A
1085722 | 103A
1085723 | 103A
1085728 | 102A
1085729 | 102A
1085730 | 101B
1092641 | 308C
1092643 | 301A
1092644 | 305A
1092645 | 305A
1092650 | 308D
1092653 | 308A
1092654 | 308B
1092656 | 306B
1092657 | 306B
1092660 | 304A
1092661 | 304A
1092662 | 303A
1092663 | 303A
1092668 | 302A
1092669 | 302A
1092670 | 301B
1092673 | 301C
1092674 | 301D
1150318 | 108C
1173037 | 109

# IfcFurnishingElement: M_Desk:1830 x 915mm, M_Desk:1830 x 915mm:2031186
In: 004
Type - Material: Laminate, Ivory, Matte, Steel, Chrome Plated, Cherry
Type - Pset_FurnitureTypeCommon - Description: Metallist töölaud+ sahtli, perfoseina, lambi, plastkarpide ja tsingitud jalgadega, laud 1500x800, töölaud paksusega 44mm on kaetud 2mm paksuse tsingitud terasplekiga, kandevõime kuni 500kg, laua jalgade kõrgus reguleeritav, jalad tugevast tsingitud terasprofiilist, sahtel mõõtudega 145x465x505mm, perfosein 2000x600mm, perfopostid, karbiliist, kaks plastkarpi mõõtudega 250x146x128mm ja valgusti, valgusti kinnitatakse kinituskonsoolidega perfopostide külge, valgusti 2x58W luminofoortoru; nt Laoekspert OÜ töölaud kood : 05-2080ZK või samaväärne
Type - Pset_ManufacturerTypeInformation - Manufacturer: Laoekspert OÜ
Type - Pset_ProductRequirements - Category: Furniture
Type - Pset_QuantityTakeOff - Reference: 1830 x 915mm

# IfcFurnishingElement: Piano:1370 x 600 x 1170mm, Piano:1370 x 600 x 1170mm:1267512
In: 001
Type - Material: Wood - Mahogany
Type - Pset_ProductRequirements - Category: Furniture
Type - Pset_QuantityTakeOff - Reference: 1370 x 600 x 1170mm

# IfcFurnishingElement: Riiul R-01:Riiul R-01 (92)
Type - Material: <Unnamed> (2)
Type - Pset_FurnitureTypeCommon - Description: Eritellimusmööbel vt.joonis SA-7-11
Type - Pset_ManufacturerTypeInformation - Manufacturer: Standard
Type - Pset_ProductRequirements - Category: Furniture
Type - Pset_QuantityTakeOff - Reference: Riiul R-01
Name (Riiul R-01:Riiul R-01:...) | In
2036810 | 105A
2036811 | 308A
2036813 | 308A
2036814 | 308B
2036816 | 308B
2036817 | 308C
2036818 | 308C
2036819 | 308D
2036820 | 308D
2036838 | 102B
2036839 | 301D
2036840 | 301D
2036841 | 301C
2036842 | 301C
2036843 | 301B
2036844 | 301B
2036845 | 301A
2036846 | 301A
2036855 | 102A
2036856 | 102A
2036857 | 103B
2036858 | 103A
2036859 | 104B
2036860 | 104A
2036861 | 105B
2036862 | 105A
2036873 | 102B
2036874 | 103B
2036875 | 103A
2036876 | 104B
2036877 | 104A
2036878 | 105B
2036885 | 205A
2036886 | 202B
2036887 | 202A
2036888 | 202A
2036889 | 203B
2036890 | 203A
2036891 | 204B
2036892 | 204A
2036893 | 205B
2036894 | 205A
2036895 | 202B
2036896 | 203B
2036897 | 203A
2036898 | 204B
2036899 | 204A
2036900 | 205B
2036918 | 208A
2036919 | 208A
2036920 | 208B
2036921 | 208B
2036922 | 208C
2036923 | 208C
2036924 | 208D
2036925 | 208D
2036926 | 201D
2036927 | 201D
2036928 | 201C
2036929 | 201C
2036930 | 201B
2036931 | 201B
2036932 | 201A
2036933 | 201A
2036935 | 305A
2036936 | 302B
2036937 | 302A
2036938 | 302A
2036939 | 303B
2036940 | 303A
2036941 | 304B
2036942 | 304A
2036943 | 305B
2036944 | 305A
2036945 | 302B
2036946 | 303B
2036947 | 303A
2036948 | 304B
2036949 | 304A
2036950 | 305B
2036977 | 206B
2036978 | 206B
2036981 | 206A
2036982 | 206A
2076791 | 306B
2076792 | 306B
2076793 | 306A
2076794 | 306A
2076795 | 106B
2076796 | 106B
2076797 | 106A
2076798 | 106A

# IfcFurnishingElement: SMA_Garderoob_Sliding_Komandor_Standard:Chipboard, SMA_Garderoob_Sliding_Komandor_Standard:Chipboard:1462681
In: 308
Type - Material: Chipboard-Walnut, Steel-White, Kauczuk, czarny
Type - Pset_ProductRequirements - Category: Furniture Systems
Type - Pset_QuantityTakeOff - Reference: Chipboard
Material: Kauczuk, czarny, Steel-White, Chipboard-Walnut

# IfcFurnishingElement: SMA_töölaud:SMA_töölaud, SMA_töölaud:SMA_töölaud:1177055
In: 109
Type - Material: Oak, White, + Melamiin hall
Type - Pset_FurnitureTypeCommon - Description: töölaud PIANO U esikilbiga, abikapiga ja laekakapiga või sellega samaväärne toode. - lauaplaat PALPK1608 1600x800x22mm, melamiinplaat 22mm/ABS kant 2mm - toon valgendatud saar; - U-jalaraam, metallist nelikanttoru 40x40, toruseina paksus 2mm, raamjalg pulbervärvitud must RAL9005 H:740mm, jalgade otstes reguleerimiseks plastkork, lauaplaadi all kaks metallsarja, metallraam ühendatud poltühendusega, metallraami ja lauaplaadi vahel 10mm distants; - laekakapp PALK5 424x740(H)x600mm pliiatsilaekaga PALSPLK (korpus melamiin valge 18mm, ABS kant valge 2mm, fassaad ja pealisplaat valgentatud saar 16mm, ABS kant 2mm) kesklukuga; - abikapp 1600x666(H)x446mm PAAK3A/PAAK3B korpus valge melamiin 18mm, valge ABS kant 2mm, fassaad ja pealisplaat valgendatud saar 16mm, ABS kant 2mm); - töölaua esikilp melamiin 1600x16x475(H)mm PAEK1605G, ava töölauas rosett LSR2. Lauaplaadi ala- ja ülaserv pehmendatud (R3mm), välisnurkadele anda ümardus. Kõik keevised lihvitud, servad ja nurgad pehmendatud. Pilt on illustratiivse tähendusega ja toodud näidisena. Tooted peavad olema testitud ja vastama Euroopa normidele NE 527-1:2000, NE 521-2:2003, EN521-3:2003 Pilt on illustratiivse tähendusega ja toodud näidisena.
Type - Pset_ManufacturerTypeInformation - Manufacturer: Standard
Type - Pset_ProductRequirements - Category: Furniture
Type - Pset_QuantityTakeOff - Reference: SMA_töölaud

# IfcFurnishingElement: Sanitary_Accessories_ODF-Paris_Tabouret-de-douche-escamotable_8330-00:Tabouret de douche escamotable 8330-00, Sanitary_Accessories_ODF-Paris_Tabouret-de-douche-escamotable_8330-00:Tabouret de douche escamotable 8330-00:2232992
In: 101E
Type - Material: 8330 00 Plastique Gris
Type - Pset_FurnitureTypeCommon - Description: Seinale kinnitatav, värv: hõbe, roostevaba teras AISI 304, maksimaalne kandevõime 120 kG, mõõt: 400x450 mm, Toru diameeter 32 mm, Toru tihedus 1.5 mm; NominalHeight: 140 mm
Type - Pset_ProductRequirements - Category: Furniture
Type - Pset_QuantityTakeOff - Reference: Tabouret de douche escamotable 8330-00
Material: 8330 00 Plastique Gris, 8330 00 Aluminium Blanc

# IfcFurnishingElement: Sanitary_Compound-Units_LAUFEN_BASE-Vanity-unit-470-mm_:Default (10)
Type - Material: 260 White Matt E957895F
Type - Pset_ProductRequirements - Category: Casework
Type - Pset_QuantityTakeOff - Reference: Default
Material: 260 White Matt E957895F, 100 Matt white FE380DD3, Aluminium 2BD395F3, Glass B52FA8FE
Name (Sanitary_Compound-Units_LAUFEN_BASE-Vanity-unit-470-mm_:Default:...) | In
1452713 | 308F
1452866 | 308E
1463790 | K201
1464046 | K201
1655381 | 208E
1655396 | 108F
2099255 | 208F
2147788 | K301
2147807 | K101
2234448 | 108G

# IfcFurnishingElement: Santo:Santo (12)
In: 1 Korrus
Type - Material: __Metall 1, __Aknaraam, + Melamiin hall, Default
Type - Pset_FurnitureTypeCommon - Description: Diivan ZEETAvõi sellega samaväärne toode. Diivan ZED3AB, metalljalad RAL9005, must. Polstri porolooni tulekindlus SK1, mahukaal 35kg/m3, kõvadus 150N±15%. Kanga kulumiskindlus vähemalt 100000 Martindale, tulekindlus vähemalt EN1021-1/2. Kangas - küljed ja põhi Gabriel Step 62057 (kollane), istumine Gabriel Step Melange 60011(hall). Pilt on illustratiivse tähendusega ja toodud näidisena.
Type - Pset_ManufacturerTypeInformation - Manufacturer: Standard
Type - Pset_ProductRequirements - Category: Furniture
Type - Pset_QuantityTakeOff - Reference: Santo
Material: Default
Name (Santo:Santo:...)
1325113
1325115
1325119
1325123
1325127
1325131
1325135
1332527
1332537
1332547
1332559
1332569

# IfcFurnishingElement: Standard 1200_SERIE SE411S:Standard 1200_SERIE SE411S (3)
Type - Pset_FurnitureTypeCommon - Description: Kapp SERIE SE510M 1200x2039(H)x420mm või sellega samaväärne toode. Korpus valge melamiin 18mm, valge ABS kant 2mm, fassaad valgendatud saa 16mm, ABS kant valgendatud saar 2mm) kesklukuga; - metalljalg H:100mm, RAL9006, jalgade otstes reguleerimiseks plastkork. Pilt on illustratiivse tähendusega ja toodud näidisena.
Type - Pset_ManufacturerTypeInformation - Manufacturer: Standard
Type - Pset_ProductRequirements - Category: Furniture
Type - Pset_QuantityTakeOff - Reference: Standard 1200_SERIE SE411S
Name (Standard 1200_SERIE SE411S:Standard 1200_SERIE SE411S:...) | In
996461 | 108C
997444 | 108C
998035 | 109

# IfcFurnishingElement: Standard 550x800 riietekapp:Standard 550x800 riietekapp (97)
Type - Pset_FurnitureTypeCommon - Description: Eritellimusmööbel vt.joonis SA-7-10
Type - Pset_ProductRequirements - Category: Furniture
Type - Pset_QuantityTakeOff - Reference: Standard 550x800 riietekapp
Name (Standard 550x800 riietekapp:Standard 550x800 riietekapp:...) | In
1683785 | 201C
1683973 | 201D
1685334 | 201B
1722931 | 206A
1722961 | 206A
1723707 | 205A
1723874 | 205B
1723966 | 205B
1725915 | 205A
1726171 | 204A
1726172 | 204A
1726195 | 204B
1726258 | 204B
1726291 | 203A
1726292 | 203A
1726313 | 203B
1726314 | 203B
1726327 | 202A
1726328 | 202A
1726773 | 202B
1726774 | 202B
1728061 | 201D
1732457 | 201B
1739492 | 201A
1739567 | 201A
1739621 | 208B
1739622 | 208A
1739623 | 208C
1739624 | 208A
1739625 | 208C
1739626 | 208D
1739627 | 208D
1739638 | 201C
1739680 | 208B
1739734 | 206B
1739754 | 206B
1741077 | 301C
1741078 | 301D
1741079 | 301B
1741080 | 306A
1741081 | 306A
1741082 | 305A
1741083 | 305B
1741084 | 305B
1741085 | 305A
1741086 | 304A
1741087 | 304A
1741088 | 304B
1741089 | 304B
1741090 | 303A
1741091 | 303A
1741092 | 303B
1741093 | 303B
1741094 | 302A
1741095 | 302A
1741096 | 302B
1741097 | 302B
1741098 | 301D
1741099 | 301B
1741100 | 301A
1741101 | 301A
1741102 | 308B
1741103 | 308A
1741104 | 308C
1741105 | 308A
1741106 | 308C
1741107 | 308D
1741108 | 308D
1741109 | 301C
1741110 | 308B
1741111 | 306B
1741112 | 306B
1743859 | 106A
1743860 | 106A
1743861 | 105A
1743862 | 105B
1743863 | 105B
1743864 | 105A
1743865 | 104A
1743866 | 104A
1743867 | 104B
1743868 | 104B
1743869 | 103A
1743870 | 103A
1743871 | 103B
1743872 | 103B
1743873 | 102A
1743874 | 102A
1743875 | 102B
1743876 | 102B
1743878 | 101B
1743879 | 101A
1743881 | 108C
1743890 | 106B
1743891 | 106B
1765374 | 101
1834202 | 108C

# IfcFurnishingElement: Stool (3):Aluminium Stool, Stool (3):Aluminium Stool:1274103
In: 004
Type - Material: Metal - Aluminium Satin (2)
Type - Pset_FurnitureTypeCommon - Description: Lakitud vineerist istmega taburet - pika kasutuseaga, vastupidav, elegantne ning kergelt puhastatav. Istmeosa mõõdud: Ø 350 mm. Jala läbimõõt 500 mm, valmistatud poleeritud alumiiniumist. Rattad: Ø 50 mm. Kõrguse reguleerimine vahemikus 460 - 650 mm, koormusega pidurdavate ratastega, kõrguse reguleerimise pedaaliga.
Type - Pset_ManufacturerTypeInformation - Manufacturer: Elbest OÜ
Type - Pset_ProductRequirements - Category: Furniture
Type - Pset_QuantityTakeOff - Reference: Aluminium Stool
Material: Metal - Aluminium Satin

# IfcFurnishingElement: Treadmill_8126:Treadmill_8126, Treadmill_8126:Treadmill_8126:1013578
In: 005
Type - Material: <Unnamed> (2)
Type - Pset_FurnitureTypeCommon - Description: Jooksulint Gilavar, maksimaalne kiirus kuni 22 km/h jooksulindi mootori võimsus: 3,5 HP võimalus muuta kallakut kuni 22% maksimaalne kasutaja kaal 150 kg trenažööri kaal 97 kg kompuuter näitab distantsi, aega, kiirust, pulssi, põletatud kaloreid
Type - Pset_ManufacturerTypeInformation - Manufacturer: inSPORTline
Type - Pset_ProductRequirements - Category: Furniture
Type - Pset_QuantityTakeOff - Reference: Treadmill_8126

# IfcFurnishingElement: ZED2.dwg:ZED2.dwg (6)
Type - Material: __Metal Tumehall, Laminate, Ivory, Matte
Type - Pset_FurnitureTypeCommon - Description: Diivan ZEETA või sellega samaväärne toode. Diivan ZED3, metalljalad RAL9005, must. Polstri porolooni tulekindlus SK1, mahukaal 35kg/m3, kõvadus 150N±15%. Kanga kulumiskindlus vähemalt 100000 Martindale, tulekindlus vähemalt EN1021-1/2. Kangas - küljed ja põhi Gabriel Step Melange 64178, istumine Gabriel Step Melange 66019 (tumehall). Pilt on illustratiivse tähendusega ja toodud näidisena.
Type - Pset_ManufacturerTypeInformation - Manufacturer: Standard
Type - Pset_ProductRequirements - Category: Furniture
Type - Pset_QuantityTakeOff - Reference: ZED2.dwg
Name (ZED2.dwg:ZED2.dwg:...) | In
1246559 | 110
1247899 | 110
1264714 | 001
1264815 | 001
1268659 | 001
1271962 | 001

# IfcFurnishingElement: ZESP2 ZEETA SIRGE DIIVAN.0001:B korpuse kapp, ZESP2 ZEETA SIRGE DIIVAN.0001:B korpuse kapp:1248090
In: 110
Type - Material: Laminate, Ivory, Matte (2)
Type - Pset_FurnitureTypeCommon - Description: Diivanilaud Zeeta või sellega samaväärne toode. - lauaplaat 1300x700x22mm, melamiinplaat valgendatud saar; - U-jalaraam, metallist nelikanttoru 40x40, toruseina paksus 2mm, raamjalg pulbervärvitud must RAL9005, jalgade otstes reguleerimiseks plastkork, lauaplaadi all kaks metallsarja, metallraam ühendatud poltühendusega, metallraami ja lauaplaadi vahel 10mm distants; Pilt on illustratiivse tähendusega ja toodud näidisena
Type - Pset_ManufacturerTypeInformation - Manufacturer: Standard
Type - Pset_ProductRequirements - Category: Furniture
Type - Pset_QuantityTakeOff - Reference: B korpuse kapp

# IfcFurnishingElement: kirjutuslaud 1400:kirjutuslaud 1400 (95)
Type - Material: <Unnamed> (2)
Type - Pset_FurnitureTypeCommon - Description: töölaud PIANO U, laekakapiga või sellega samaväärne toode. - lauaplaat PALPK1206 1200x600x22mm, melamiinplaat 22mm/ABS kant 2mm - toon valgendatud saar; - U-jalaraam, metallist nelikanttoru 40x40, toruseina paksus 2mm, raamjalg pulbervärvitud must RAL9005 H:740mm, jalgade otstes reguleerimiseks plastkork, lauaplaadi all kaks metallsarja, metallraam ühendatud poltühendusega, metallraami ja lauaplaadi vahel 10mm distants; - laekakapp PALK5 424x740(H)x600mm pliiatsilaekaga PALSPLK (korpus melamiin valge 18mm, ABS kant valge 2mm, fassaad ja pealisplaat valgentatud saar 16mm, ABS kant 2mm) kesklukuga; ava töölauas rosett LSR2. Lauaplaadi ala- ja ülaserv pehmendatud (R3mm), välisnurkadele anda ümardus. Kõik keevised lihvitud, servad ja nurgad pehmendatud. Pilt on illustratiivse tähendusega ja toodud näidisena. Tooted peavad olema testitud ja vastama Euroopa normidele NE 527-1:2000, NE 521-2:2003, EN521-3:2003 Pilt on illustratiivse tähendusega ja toodud näidisena.
Type - Pset_ManufacturerTypeInformation - Manufacturer: Standard
Type - Pset_ProductRequirements - Category: Furniture
Type - Pset_QuantityTakeOff - Reference: kirjutuslaud 1400
Name (kirjutuslaud 1400:kirjutuslaud 1400:...) | In
912914 | 208C
912915 | 208C
912916 | 201A
912917 | 201A
912919 | 205A
912920 | 205B
912921 | 205B
912922 | 206A
912923 | 206A
912924 | 208D
912925 | 208D
912926 | 208A
912927 | 208A
912928 | 208B
912929 | 208B
912930 | 206B
912931 | 206B
912932 | 204B
912933 | 204B
912934 | 204A
912935 | 204A
912936 | 203A
912937 | 203A
912938 | 203B
912939 | 203B
912940 | 202B
912941 | 202B
912942 | 202A
912943 | 202A
912944 | 201B
912945 | 201B
912946 | 201C
912947 | 201C
913099 | 201D
913100 | 201D
1085270 | 101A
1085271 | 105A
1085272 | 105A
1085273 | 105B
1085274 | 105B
1085275 | 106A
1085276 | 106A
1085277 | 106B
1085278 | 106B
1085279 | 104B
1085280 | 104B
1085281 | 104A
1085282 | 104A
1085283 | 103A
1085284 | 103A
1085285 | 103B
1085286 | 103B
1085287 | 102B
1085288 | 102B
1085289 | 102A
1085290 | 102A
1085292 | 101B
1092737 | 308C
1092738 | 308C
1092739 | 301A
1092740 | 301A
1092741 | 305A
1092742 | 305A
1092743 | 305B
1092744 | 305B
1092745 | 306A
1092746 | 306A
1092747 | 308D
1092748 | 308D
1092749 | 308A
1092750 | 308A
1092751 | 308B
1092752 | 308B
1092753 | 306B
1092754 | 306B
1092755 | 304B
1092756 | 304B
1092757 | 304A
1092758 | 304A
1092759 | 303A
1092760 | 303A
1092761 | 303B
1092762 | 303B
1092763 | 302B
1092764 | 302B
1092765 | 302A
1092766 | 302A
1092767 | 301B
1092768 | 301B
1092769 | 301C
1092770 | 301C
1092771 | 301D
1092772 | 301D
1173036 | 109
1355048 | 205A

# IfcFurnishingElement: kirjutuslaud 1600:kirjutuslaud 1600, kirjutuslaud 1600:kirjutuslaud 1600:1150317
In: 108C
Type - Material: <Unnamed> (2)
Type - Pset_FurnitureTypeCommon - Description: töölaud PIANO U, laekakapiga või sellega samaväärne toode. - lauaplaat PALPK1808 1800x800x22mm, melamiinplaat 22mm/ABS kant 2mm - toon valgendatud saar; - U-jalaraam, metallist nelikanttoru 40x40, toruseina paksus 2mm, raamjalg pulbervärvitud must RAL9005 H:740mm, jalgade otstes reguleerimiseks plastkork, lauaplaadi all kaks metallsarja, metallraam ühendatud poltühendusega, metallraami ja lauaplaadi vahel 10mm distants; - laekakapp PALK5 424x740(H)x600mm pliiatsilaekaga PALSPLK (korpus melamiin valge 18mm, ABS kant valge 2mm, fassaad ja pealisplaat valgentatud saar 16mm, ABS kant 2mm) kesklukuga; ava töölauas rosett LSR2. Lauaplaadi ala- ja ülaserv pehmendatud (R3mm), välisnurkadele anda ümardus. Kõik keevised lihvitud, servad ja nurgad pehmendatud. Pilt on illustratiivse tähendusega ja toodud näidisena. Tooted peavad olema testitud ja vastama Euroopa normidele NE 527-1:2000, NE 521-2:2003, EN521-3:2003 Pilt on illustratiivse tähendusega ja toodud näidisena.
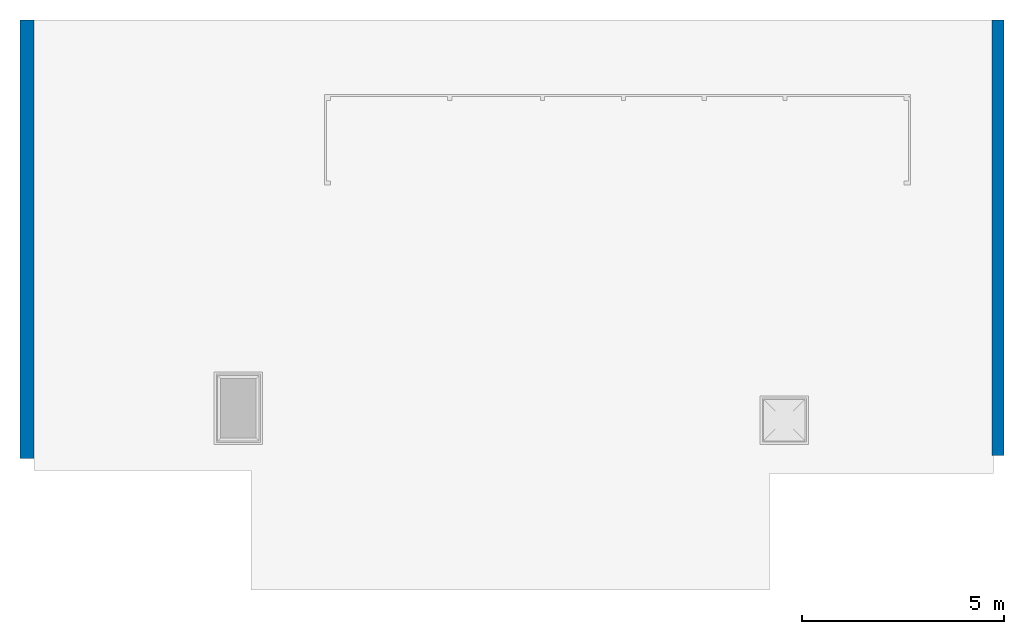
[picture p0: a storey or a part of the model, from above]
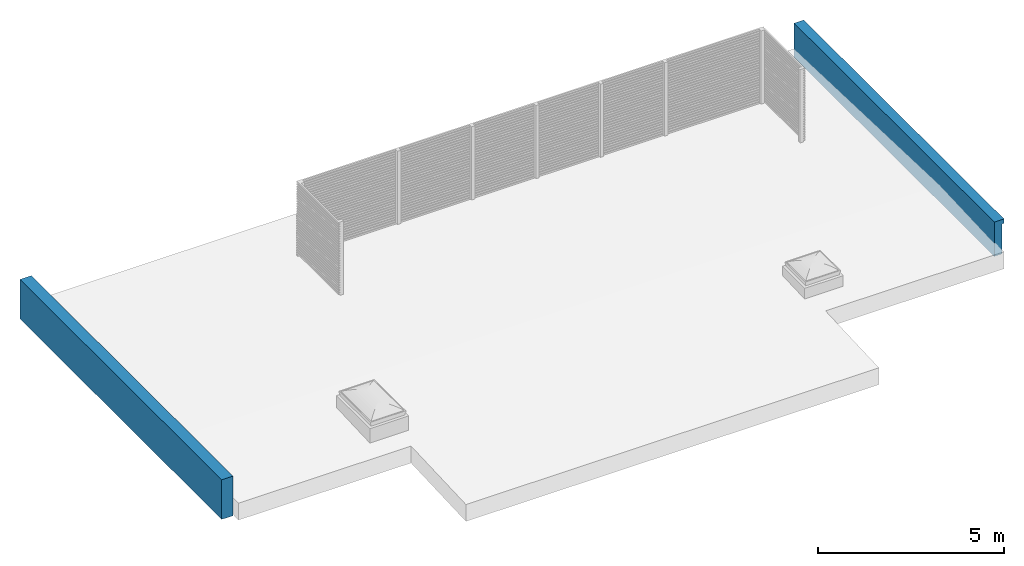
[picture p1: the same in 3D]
Properties of the parts of a building model (IFC2X3), part 5 of 7

# IfcFurnishingElement: kirjutuslaud 1600:kirjutuslaud 1600, kirjutuslaud 1600:kirjutuslaud 1600:1150317
Type - Pset_ManufacturerTypeInformation - Manufacturer: Standard
Type - Pset_ProductRequirements - Category: Furniture
Type - Pset_QuantityTakeOff - Reference: kirjutuslaud 1600

# IfcFurnishingElement: laud_1200x800:laud_1200x800 (2)
Type - Material: <Unnamed>, Metal - Stud Layer
Type - Pset_FurnitureTypeCommon - Description: laud 1200x740(H)x800 või sellega samaväärne toode. Lauaplaat 1200mm, paksus 22mm, puitlaastplaat kaetud mööbli Linoleumiga (Forbo furniture linoleum desktop - 2mm, toon 4184 olive, kuumtöötlusega valatud 4mm polüuretaankant hall 95, metallist jalg 40x40, toruseina paksus 2mm, raamjalg pulbervärvitud must RAL9005 H:740mm, jalgade otstes reguleerimiseks plastkork, lauaplaadi all kaks metallsarja, metallraam ühendatud poltühendusega, metallraami ja lauaplaadi vahel 10mm distants, Lauaplaadi ala- ja ülaserv pehmendatud (R3mm), välisnurkadele anda ümardus. Kõik keevised lihvitud, servad ja nurgad pehmendatud. Pilt on illustratiivse tähendusega ja toodud näidisena.
Type - Pset_ManufacturerTypeInformation - Manufacturer: Standard
Type - Pset_ProductRequirements - Category: Furniture
Type - Pset_QuantityTakeOff - Reference: laud_1200x800
Material: Metal - Stud Layer
Name (laud_1200x800:laud_1200x800:...) | In
2036828 | 308
2036972 | 208

# IfcFurnishingElement: laud_1200x800:laud_1200x800 (2)
Type - Material: Metal - Stud Layer, <Unnamed>
Type - Pset_FurnitureTypeCommon - Description: laud 1200x740(H)x800 või sellega samaväärne toode. Lauaplaat 1200mm, paksus 22mm, puitlaastplaat kaetud mööbli Linoleumiga (Forbo furniture linoleum desktop - 2mm, toon 4184 olive, kuumtöötlusega valatud 4mm polüuretaankant hall 95, metallist jalg 40x40, toruseina paksus 2mm, raamjalg pulbervärvitud must RAL9005 H:740mm, jalgade otstes reguleerimiseks plastkork, lauaplaadi all kaks metallsarja, metallraam ühendatud poltühendusega, metallraami ja lauaplaadi vahel 10mm distants, Lauaplaadi ala- ja ülaserv pehmendatud (R3mm), välisnurkadele anda ümardus. Kõik keevised lihvitud, servad ja nurgad pehmendatud. Pilt on illustratiivse tähendusega ja toodud näidisena.
Type - Pset_ManufacturerTypeInformation - Manufacturer: Standard
Type - Pset_ProductRequirements - Category: Furniture
Type - Pset_QuantityTakeOff - Reference: laud_1200x800
Material: Metal - Stud Layer
Name (laud_1200x800:laud_1200x800:...) | In
1731230 | 301
2036967 | 201

# IfcFurnishingElement: laud_1600x800:laud_1600x800 (6)
Type - Material: Metal - Stud Layer, <Unnamed>
Type - Pset_FurnitureTypeCommon - Description: laud 1600x740(H)x800 või sellega samaväärne toode. Lauaplaat 1600mm, paksus 22mm, puitlaastplaat kaetud mööbli Linoleumiga (Forbo furniture linoleum desktop - 2mm, toon 4184 olive, kuumtöötlusega valatud 4mm polüuretaankant hall 95, metallist jalg 40x40, toruseina paksus 2mm, raamjalg pulbervärvitud must RAL9005 H:740mm, jalgade otstes reguleerimiseks plastkork, lauaplaadi all kaks metallsarja, metallraam ühendatud poltühendusega, metallraami ja lauaplaadi vahel 10mm distants, Lauaplaadi ala- ja ülaserv pehmendatud (R3mm), välisnurkadele anda ümardus. Kõik keevised lihvitud, servad ja nurgad pehmendatud. Pilt on illustratiivse tähendusega ja toodud näidisena.
Type - Pset_ManufacturerTypeInformation - Manufacturer: Standard
Type - Pset_ProductRequirements - Category: Furniture
Type - Pset_QuantityTakeOff - Reference: laud_1600x800
Material: Metal - Stud Layer
Name (laud_1600x800:laud_1600x800:...) | In
1472576 | 207
1472692 | 207
1791981 | 307
1791982 | 307
1792050 | 107
1792051 | 107

# IfcFurnishingElement: laud_1800x900:laud_1800x900 (2)
In: 001
Type - Material: Metal - Stud Layer, <Unnamed>
Type - Pset_FurnitureTypeCommon - Description: laud 1800x740(H)x800 või sellega samaväärne toode. Lauaplaat 1600mm, paksus 22mm, puitlaastplaat kaetud mööbli Linoleumiga (Forbo furniture linoleum desktop - 2mm, toon 4184 olive, kuumtöötlusega valatud 4mm polüuretaankant hall 95, metallist jalg 40x40, toruseina paksus 2mm, raamjalg pulbervärvitud must RAL9005 H:740mm, jalgade otstes reguleerimiseks plastkork, lauaplaadi all kaks metallsarja, metallraam ühendatud poltühendusega, metallraami ja lauaplaadi vahel 10mm distants, Lauaplaadi ala- ja ülaserv pehmendatud (R3mm), välisnurkadele anda ümardus. Kõik keevised lihvitud, servad ja nurgad pehmendatud. Pilt on illustratiivse tähendusega ja toodud näidisena.
Type - Pset_ManufacturerTypeInformation - Manufacturer: Standard
Type - Pset_ProductRequirements - Category: Furniture
Type - Pset_QuantityTakeOff - Reference: laud_1800x900
Material: Metal - Stud Layer
Name (laud_1800x900:laud_1800x900:...)
1266441
1266442

# IfcFurnishingElement: varbsein 1,00x2.30:varbsein 1,00x2.30 (3)
In: 005
Type - Pset_FurnitureTypeCommon - Description: Puidust varbsein ovaalsete pulkadega. Peab vastama EN913 standardile.
Type - Pset_ManufacturerTypeInformation - Manufacturer: Tommi Play
Type - Pset_ProductRequirements - Category: Furniture
Type - Pset_QuantityTakeOff - Reference: varbsein 1,00x2.30
Name (varbsein 1,00x2.30:varbsein 1,00x2.30:...)
2029195
2030065
2030066

# IfcFurnishingElement: voodi.rfa sahtlitega 900x2000mm:voodi.rfa sahtlitega 900x2000mm (46)
Type - Material: Cloth, white (2)
Type - Pset_FurnitureTypeCommon - Description: Voodi kahe sahtliga. Melamiinplaat 22mm / abs kant 2mm - toon valge, sahtlid suurte plastik ratastega, nurgad pehmendatud. Tooted peavad olema testitud ja vastama Euroopa normidele NE 527-1:2000, NE 521-2003, EN521-3:2003. Pilt on illustratiivse tähendusega ja toodud näidisena.
Type - Pset_ProductRequirements - Category: Furniture
Type - Pset_QuantityTakeOff - Reference: voodi.rfa sahtlitega 900x2000mm
Material: white, Textile - White
Name (voodi.rfa sahtlitega 900x2000mm:voodi.rfa sahtlitega 900x2000mm:...) | In
913029 | 208B
913041 | 208B
913044 | 208D
913045 | 208D
913050 | 201B
913051 | 201B
913056 | 205B
913060 | 204B
913061 | 204B
913064 | 203B
913065 | 203B
913068 | 202B
913069 | 202B
913070 | 206A
913071 | 206A
913103 | 201D
913104 | 201D
1084828 | 101B
1084833 | 105B
1084834 | 105B
1084837 | 104B
1084838 | 104B
1084841 | 103B
1084842 | 103B
1084845 | 102B
1084846 | 102B
1084847 | 106A
1084848 | 106A
1092542 | 308B
1092543 | 308B
1092546 | 308D
1092547 | 308D
1092552 | 301B
1092553 | 301B
1092558 | 305B
1092559 | 305B
1092562 | 304B
1092563 | 304B
1092566 | 303B
1092567 | 303B
1092570 | 302B
1092571 | 302B
1092572 | 306A
1092573 | 306A
1092576 | 301D
1092577 | 301D

# IfcFurnishingElement: voodi.rfa sahtlitega 900x2000mm:voodi.rfa sahtlitega 900x2000mm (49)
Type - Material: white (2), Cloth
Type - Pset_FurnitureTypeCommon - Description: Voodi kahe sahtliga. Melamiinplaat 22mm / abs kant 2mm - toon valge, sahtlid suurte plastik ratastega, nurgad pehmendatud. Tooted peavad olema testitud ja vastama Euroopa normidele NE 527-1:2000, NE 521-2003, EN521-3:2003. Pilt on illustratiivse tähendusega ja toodud näidisena.
Type - Pset_ProductRequirements - Category: Furniture
Type - Pset_QuantityTakeOff - Reference: voodi.rfa sahtlitega 900x2000mm
Material: white, Textile - White
Name (voodi.rfa sahtlitega 900x2000mm:voodi.rfa sahtlitega 900x2000mm:...) | In
913042 | 208C
913043 | 208C
913046 | 208A
913047 | 208A
913048 | 201C
913049 | 201C
913052 | 201A
913053 | 201A
913055 | 205A
913058 | 204A
913059 | 204A
913062 | 203A
913063 | 203A
913066 | 202A
913067 | 202A
913072 | 206B
913073 | 206B
1084826 | 109
1084830 | 101A
1084831 | 105A
1084832 | 105A
1084835 | 104A
1084836 | 104A
1084839 | 103A
1084840 | 103A
1084843 | 102A
1084844 | 102A
1084849 | 106B
1084850 | 106B
1092544 | 308C
1092545 | 308C
1092548 | 308A
1092549 | 308A
1092550 | 301C
1092551 | 301C
1092554 | 301A
1092555 | 301A
1092556 | 305A
1092557 | 305A
1092560 | 304A
1092561 | 304A
1092564 | 303A
1092565 | 303A
1092568 | 302A
1092569 | 302A
1092574 | 306B
1092575 | 306B
1354933 | 205B
1354989 | 205A

# IfcFurnishingElement: zeeta.2A:zeeta.2A (5)
Type - Material: __Aknaraam, + Melamiin hall, __Metall 1
Type - Pset_FurnitureTypeCommon - Description: Diivan ZEETA või sellega samaväärne toode. Diivan ZED2A, metalljalad RAL9005, must. Polstri porolooni tulekindlus SK1, mahukaal 35kg/m3, kõvadus 150N±15%. Kanga kulumiskindlus vähemalt 100000 Martindale, tulekindlus vähemalt EN1021-1/2. Kangas - küljed ja põhi Gabriel Step 64178, istumine Gabriel Step Melange 66019 (tume hall). Pilt on illustratiivse tähendusega ja toodud näidisena.
Type - Pset_ManufacturerTypeInformation - Manufacturer: Standard
Type - Pset_ProductRequirements - Category: Furniture
Type - Pset_QuantityTakeOff - Reference: zeeta.2A
Name (zeeta.2A:zeeta.2A:...) | In
1133889 | 301
1264767 | 001
1264814 | 001
1268658 | 001
1662178 | 201

# IfcFurnishingElement: zeeta.2A:zeeta.2A (6)
Type - Material: __Metall 1, + Melamiin hall, __Aknaraam
Type - Pset_FurnitureTypeCommon - Description: Diivan ZEETA või sellega samaväärne toode. Diivan ZED2A, metalljalad RAL9005, must. Polstri porolooni tulekindlus SK1, mahukaal 35kg/m3, kõvadus 150N±15%. Kanga kulumiskindlus vähemalt 100000 Martindale, tulekindlus vähemalt EN1021-1/2. Kangas - küljed ja põhi Gabriel Step 64178, istumine Gabriel Step Melange 66019 (tume hall). Pilt on illustratiivse tähendusega ja toodud näidisena.
Type - Pset_ManufacturerTypeInformation - Manufacturer: Standard
Type - Pset_ProductRequirements - Category: Furniture
Type - Pset_QuantityTakeOff - Reference: zeeta.2A
Name (zeeta.2A:zeeta.2A:...) | In
1131733 | 308
1165623 | 208
1234638 | T101
1264713 | 001
1264816 | 001
1271961 | 001

# IfcFurnishingElement: zeeta.dwg.0002:zeeta.dwg.0002, zeeta.dwg.0002:zeeta.dwg.0002:1169405
In: T101
Type - Material: + Melamiin hall, __Aknaraam, __Metall 1, Fabric ääred
Type - Pset_FurnitureTypeCommon - Description: Diivan ZEETA või sellega samaväärne toode. Diivan ZED3AB, metalljalad RAL9005, must. Polstri porolooni tulekindlus SK1, mahukaal 35kg/m3, kõvadus 150N±15%. Kanga kulumiskindlus vähemalt 100000 Martindale, tulekindlus vähemalt EN1021-1/2. Kangas - küljed ja põhi Gabriel Step 64178, istumine Gabriel Step Melange 66019(tumehall). Pilt on illustratiivse tähendusega ja toodud näidisena.
Type - Pset_ManufacturerTypeInformation - Manufacturer: Standard
Type - Pset_ProductRequirements - Category: Furniture
Type - Pset_QuantityTakeOff - Reference: zeeta.dwg.0002
Material: __Metall 1, Fabric ääred, Fabric istumine

# IfcFurnishingElement: zeeta.dwg.0002:zeeta.dwg.0002, zeeta.dwg.0002:zeeta.dwg.0002:1170779
In: 110
Type - Material: + Melamiin hall, __Metall 1, __Aknaraam, Fabric ääred
Type - Pset_FurnitureTypeCommon - Description: Diivan ZEETA või sellega samaväärne toode. Diivan ZED3AB, metalljalad RAL9005, must. Polstri porolooni tulekindlus SK1, mahukaal 35kg/m3, kõvadus 150N±15%. Kanga kulumiskindlus vähemalt 100000 Martindale, tulekindlus vähemalt EN1021-1/2. Kangas - küljed ja põhi Gabriel Step 64178, istumine Gabriel Step Melange 66019(tumehall). Pilt on illustratiivse tähendusega ja toodud näidisena.
Type - Pset_ManufacturerTypeInformation - Manufacturer: Standard
Type - Pset_ProductRequirements - Category: Furniture
Type - Pset_QuantityTakeOff - Reference: zeeta.dwg.0002
Material: __Metall 1, Fabric ääred, Fabric istumine

# IfcMember: Rectangular Mullion:50 x 100mm (8)
In: 1 Korrus
Type - PredefinedType: MULLION; Material: __Aknaraam
Type - Pset_MemberCommon - IsExternal: no; Reference: 50 x 100mm
Type - Pset_ProductRequirements - Category: Curtain Wall Mullions
Type - Pset_QuantityTakeOff - Reference: 50 x 100mm
Pset_MemberCommon - IsExternal: yes
Name (Rectangular Mullion:50 x 100mm:...) | Span (mm)
1177060 | 2100
1776478 | 1658.27
1776479 | 1658.27
1776480 | 2100
1234898 | 2100
1234932 | 623.621
1234933 | 623.621
1234934 | 2100

# IfcMember: Rectangular Mullion:Schüco hor. tran, cover cap 45mm, profiil 130mm (71)
Type - PredefinedType: MULLION; Material: EST. Metall. Alumiinium. Värvitud. RAL7023 (Concrete grey)
Type - Pset_MemberCommon - IsExternal: no; Reference: Schüco hor. tran, cover cap 45mm, profiil 130mm
Type - Pset_ProductRequirements - Category: Curtain Wall Mullions
Type - Pset_QuantityTakeOff - Reference: Schüco hor. tran, cover cap 45mm, profiil 130mm
Pset_MemberCommon - IsExternal: yes
Name (Rectangular Mullion:Schüco hor. tran, cover cap 45mm, profiil 130mm:...) | In | Span (mm)
858536 | 1 Korrus | 1080
858537 | 1 Korrus | 1080
1577360 | 1 Korrus | 1080
1591498 | 1 Korrus | 1080
858926 | 1 Korrus | 1740
1177586 | 1 Korrus | 777.154
1177694 | 1 Korrus | 777.154
859013 | 1 Korrus | 1081
859014 | 1 Korrus | 1081
1230834 | 1 Korrus | 1081
1588702 | 1 Korrus | 1081
1025872 | 1 Korrus | 769.728
1080577 | 1 Korrus | 1800
1574139 | 1 Korrus | 769.728
859164 | 2 Korrus | 880
859165 | 2 Korrus | 880
1040106 | 2 Korrus | 880
1040155 | 2 Korrus | 880
1040429 | 2 Korrus | 880
1040582 | 2 Korrus | 880
859217 | 2 Korrus | 1080
859218 | 2 Korrus | 1080
1040225 | 2 Korrus | 1080
1040276 | 2 Korrus | 1080
1040334 | 2 Korrus | 1080
1040382 | 2 Korrus | 1080
1587977 | 2 Korrus | 1080
1588037 | 2 Korrus | 1080
906296 | 1 Korrus | 2275
906297 | 1 Korrus | 2275
906460 | 1 Korrus | 440
1177765 | 1 Korrus | 344.815
1177799 | 1 Korrus | 344.815
1177800 | 1 Korrus | 1740
1177912 | 1 Korrus | 1740
1177913 | 1 Korrus | 440
939566 | 2 Korrus | 1125
939567 | 2 Korrus | 1125
1038841 | 2 Korrus | 1125
1038888 | 2 Korrus | 1125
1038968 | 2 Korrus | 1125
1039004 | 2 Korrus | 1125
1587327 | 2 Korrus | 1125
1587385 | 2 Korrus | 1125
978329 | 1 Korrus | 1845.2
978330 | 1 Korrus | 1314.57
1171890 | 1 Korrus | 1314.57
1171893 | 1 Korrus | 1845.2
1602187 | 1 Korrus | 1740
1049650 | 2 Korrus | 1080
1049651 | 2 Korrus | 1080
1049658 | 2 Korrus | 1080
1049663 | 2 Korrus | 1080
1049668 | 2 Korrus | 1080
1049673 | 2 Korrus | 1080
1051208 | 2 Korrus | 810
1051209 | 2 Korrus | 810
1051216 | 2 Korrus | 810
1051221 | 2 Korrus | 810
1051226 | 2 Korrus | 810
1051231 | 2 Korrus | 810
1051234 | 2 Korrus | 1130
1051235 | 2 Korrus | 1130
1051242 | 2 Korrus | 1130
1051247 | 2 Korrus | 1130
1051252 | 2 Korrus | 1130
1051257 | 2 Korrus | 1130
1171984 | 1 Korrus | 1310.11
1171987 | 1 Korrus | 1275.23
1520739 | 1 Korrus | 1275.23
1520740 | 1 Korrus | 1310.11

# IfcMember: Rectangular Mullion:Schüco vert. mullion, cover cap 45mm, profiil 150mm (99)
Type - PredefinedType: MULLION; Material: EST. Metall. Alumiinium. Värvitud. RAL7023 (Concrete grey)
Type - Pset_MemberCommon - IsExternal: no; Reference: Schüco vert. mullion, cover cap 45mm, profiil 150mm
Type - Pset_ProductRequirements - Category: Curtain Wall Mullions
Type - Pset_QuantityTakeOff - Reference: Schüco vert. mullion, cover cap 45mm, profiil 150mm
Pset_MemberCommon - IsExternal: yes
Name (Rectangular Mullion:Schüco vert. mullion, cover cap 45mm, profiil 150mm:...) | In | Span (mm)
858538 | 1 Korrus | 1125
858539 | 1 Korrus | 830
1577358 | 1 Korrus | 245
1577359 | 1 Korrus | 1125
1591496 | 1 Korrus | 830
1591497 | 1 Korrus | 245
858928 | 1 Korrus | 2200
858929 | 1 Korrus | 2200
1177696 | 1 Korrus | 2200
859015 | 1 Korrus | 1120
859016 | 1 Korrus | 830
1230832 | 1 Korrus | 830
1230833 | 1 Korrus | 250
1588700 | 1 Korrus | 250
1588701 | 1 Korrus | 1120
859022 | 1 Korrus | 2200
1025873 | 1 Korrus | 2200
1574141 | 1 Korrus | 2200
859166 | 2 Korrus | 960
859167 | 2 Korrus | 1550
1040104 | 2 Korrus | 880
1040105 | 2 Korrus | 1920
1040153 | 2 Korrus | 1920
1040154 | 2 Korrus | 880
1040427 | 2 Korrus | 1550
1040428 | 2 Korrus | 880
1040580 | 2 Korrus | 880
1040581 | 2 Korrus | 960
859219 | 2 Korrus | 733.286
859220 | 2 Korrus | 1550
1040223 | 2 Korrus | 1673.29
1040224 | 2 Korrus | 880
1040274 | 2 Korrus | 226.714
1040275 | 2 Korrus | 733.286
1040332 | 2 Korrus | 246.714
1040333 | 2 Korrus | 1673.29
1040380 | 2 Korrus | 1550
1040381 | 2 Korrus | 880
1587975 | 2 Korrus | 880
1587976 | 2 Korrus | 246.714
1588035 | 2 Korrus | 880
1588036 | 2 Korrus | 226.714
906298 | 1 Korrus | 2200
906299 | 1 Korrus | 2200
906462 | 1 Korrus | 2200
906463 | 1 Korrus | 2200
1177801 | 1 Korrus | 2200
1177914 | 1 Korrus | 2200
939568 | 2 Korrus | 733.286
939569 | 2 Korrus | 1550
1038839 | 2 Korrus | 1550
1038840 | 2 Korrus | 880
1038886 | 2 Korrus | 246.714
1038887 | 2 Korrus | 1673.29
1038966 | 2 Korrus | 1673.29
1038967 | 2 Korrus | 880
1039002 | 2 Korrus | 226.714
1039003 | 2 Korrus | 733.286
1587325 | 2 Korrus | 880
1587326 | 2 Korrus | 226.714
1587383 | 2 Korrus | 880
1587384 | 2 Korrus | 246.714
978331 | 1 Korrus | 2200
978332 | 1 Korrus | 2200
1171894 | 1 Korrus | 2200
1171895 | 1 Korrus | 2200
1049652 | 2 Korrus | 960
1049653 | 2 Korrus | 1550
1049656 | 2 Korrus | 880
1049657 | 2 Korrus | 1920
1049661 | 2 Korrus | 1920
1049662 | 2 Korrus | 880
1049666 | 2 Korrus | 1550
1049667 | 2 Korrus | 880
1049671 | 2 Korrus | 880
1049672 | 2 Korrus | 960
1051210 | 2 Korrus | 960
1051211 | 2 Korrus | 1550
1051214 | 2 Korrus | 880
1051215 | 2 Korrus | 1920
1051219 | 2 Korrus | 1920
1051220 | 2 Korrus | 880
1051224 | 2 Korrus | 1550
1051225 | 2 Korrus | 880
1051229 | 2 Korrus | 880
1051230 | 2 Korrus | 960
1051236 | 2 Korrus | 960
1051237 | 2 Korrus | 1550
1051240 | 2 Korrus | 880
1051241 | 2 Korrus | 1920
1051245 | 2 Korrus | 1920
1051246 | 2 Korrus | 880
1051250 | 2 Korrus | 1550
1051251 | 2 Korrus | 880
1051255 | 2 Korrus | 880
1051256 | 2 Korrus | 960
1171985 | 1 Korrus | 2200
1171986 | 1 Korrus | 2200
1520741 | 1 Korrus | 2200

# IfcOpeningElement: Opening (512)
Name | In | Category
Basic Wall:Generic - 300mm:847139:1 | 1 Korrus | Walls | Pset_ElementShading - Roughness: 914.4 mm; Pset_OpeningElementCommon - Reference: Generic - 300mm; sets with these values: 2
Basic Wall:Generic - 300mm:847139:2 | 1 Korrus | Walls | Pset_ElementShading - Roughness: 914.4 mm; Pset_OpeningElementCommon - Reference: Generic - 300mm; sets with these values: 2
2 x Basic Wall:Generic - 300mm:847140 | 1 Korrus A | Windows | Pset_OpeningElementCommon - Reference: -A-01 2700x1500mm; sets with these values: 2
Basic Wall:Generic - 300mm:847146 | 1 Korrus | Doors | Pset_OpeningElementCommon - Reference: SU-P-01 - 1200x2100 EI 2 korrus; sets with these values: 2
Basic Wall:Generic - 300mm:847146 | 1 Korrus | Doors | Pset_OpeningElementCommon - Reference: SU-P-01 - 1200x2100 EI 1korrus; sets with these values: 2
Basic Wall:Generic - 300mm:847147 | 1 Korrus | Doors | Pset_OpeningElementCommon - Reference: SU-P-04 - 750x2100; sets with these values: 2
Basic Wall:Generic - 350mm:847150 | 1 Korrus | Doors | Pset_OpeningElementCommon - Reference: SU-M-03- 900x2100; sets with these values: 2
Basic Wall:Generic - 350mm:847150 | 1 Korrus | Doors | Pset_OpeningElementCommon - Reference: SU-P-01 - 1200x2100 EI 1korrus; sets with these values: 2
Basic Wall:Generic - 445mm:847223:1 | 0 Kelder | Walls | Pset_ElementShading - Roughness: 914.4 mm; Pset_OpeningElementCommon - Reference: Generic - 445mm; sets with these values: 2
Basic Wall:Generic - 445mm:847223:2 | 0 Kelder | Walls | Pset_ElementShading - Roughness: 914.4 mm; Pset_OpeningElementCommon - Reference: Generic - 445mm; sets with these values: 2
Basic Wall:Generic - 350mm:847225 | 0 Kelder | Windows | Pset_OpeningElementCommon - Reference: -A-02 2000x1200mm; sets with these values: 2
Basic Wall:Generic - 410mm:847229 | 0 Kelder | Doors | Pset_OpeningElementCommon - Reference: SU-M-01 - 1200x2100; sets with these values: 2
Basic Wall:Generic - 410mm:847229 | 0 Kelder | Doors | Pset_OpeningElementCommon - Reference: SU-M-03- 900x2100; sets with these values: 2
Basic Wall:Generic - 410mm:847232 | 0 Kelder | Windows | Pset_OpeningElementCommon - Reference: -A-02 2000x1200mm; sets with these values: 2
Basic Wall:Generic - 410mm:847232 | 0 Kelder | Windows | Pset_OpeningElementCommon - Reference: -A-07 2000x1200mm 2; sets with these values: 2
2 x Basic Wall:Generic - 350mm:847234 | 0 Kelder | Windows | Pset_OpeningElementCommon - Reference: -A-04 2500x1200mm; sets with these values: 2
Basic Wall:Generic - 350mm:847235:1 | 0 Kelder | Walls | Pset_ElementShading - Roughness: 914.4 mm; Pset_OpeningElementCommon - Reference: Generic - 350mm; sets with these values: 2
Basic Wall:Generic - 350mm:847236:1 | 0 Kelder | Walls | Pset_ElementShading - Roughness: 914.4 mm; Pset_OpeningElementCommon - Reference: Generic - 350mm; sets with these values: 2
Basic Wall:Generic - 350mm:847241 | 0 Kelder | Windows | Pset_OpeningElementCommon - Reference: -A-02 2000x1200mm; sets with these values: 2
Basic Wall:Generic - 350mm:847242 | 0 Kelder | Doors | Pset_OpeningElementCommon - Reference: SU-P-02 - 1500x2100; sets with these values: 2
Basic Wall:Generic - 410mm:847243 | 0 Kelder | Doors | Pset_OpeningElementCommon - Reference: SU-P-02 - 1500x2100; sets with these values: 2
Basic Wall:Generic - 300mm:847292 | 1 Korrus A | Windows | Pset_OpeningElementCommon - Reference: -A-01 2700x1500mm; sets with these values: 2
Basic Wall:Generic - 300mm:847292 | 1 Korrus A | Windows | Pset_OpeningElementCommon - Reference: -A-03; sets with these values: 2
Basic Wall:Generic - 350mm:847326 | 1 Korrus A | Walls | Pset_OpeningElementCommon - Reference: Curtain Wall KLF-10; sets with these values: 2
Basic Wall:Generic - 350mm:847326 | 1 Korrus A | Walls | Pset_OpeningElementCommon - Reference: Curtain Wall KLF-07; sets with these values: 2
Basic Wall:Generic - 350mm:847326 | 1 Korrus A | Walls | Pset_OpeningElementCommon - Reference: Curtain Wall KLF-08; sets with these values: 2
Basic Wall:Generic - 350mm:847326 | 1 Korrus A | Walls | Pset_OpeningElementCommon - Reference: Curtain Wall KLF-09; sets with these values: 2
Basic Wall:Generic - 350mm:847326 | 1 Korrus A | Walls | Pset_OpeningElementCommon - Reference: Curtain Wall SKF-02; sets with these values: 2
2 x Basic Wall:Generic - 300mm:847329 | 1 Korrus A | Windows | Pset_OpeningElementCommon - Reference: -A-01 2700x1500mm; sets with these values: 2
Basic Wall:Generic - 300mm:847329 | 1 Korrus A | Windows | Pset_OpeningElementCommon - Reference: -A-03; sets with these values: 2
2 x Basic Wall:Generic - 300mm:847384 | 2 Korrus A | Windows | Pset_OpeningElementCommon - Reference: -A-01 2700x1500mm; sets with these values: 2
Basic Wall:Generic - 300mm:847387:1 | 2 Korrus A | Walls | Pset_ElementShading - Roughness: 914.4 mm; Pset_OpeningElementCommon - Reference: Generic - 300mm; sets with these values: 2
Basic Wall:Generic - 300mm:847387:2 | 2 Korrus A | Walls | Pset_ElementShading - Roughness: 914.4 mm; Pset_OpeningElementCommon - Reference: Generic - 300mm; sets with these values: 2
2 x Basic Wall:Generic - 300mm:847400 | 3 Korrus A | Windows | Pset_OpeningElementCommon - Reference: -A-01 2700x1500mm; sets with these values: 2
2 x Basic Wall:Generic - 300mm:847437 | 3 Korrus A | Windows | Pset_OpeningElementCommon - Reference: -A-01 2700x1500mm; sets with these values: 2
Basic Wall:Generic - 350mm:847438 | 3 Korrus A | Walls | Pset_OpeningElementCommon - Reference: Curtain Wall KLF-08; sets with these values: 2
Basic Wall:Generic - 350mm:847438 | 3 Korrus A | Walls | Pset_OpeningElementCommon - Reference: Curtain Wall KLF-09; sets with these values: 2
Basic Wall:Generic - 300mm:847440 | 3 Korrus A | Windows | Pset_OpeningElementCommon - Reference: -A-03; sets with these values: 2
2 x Basic Wall:Generic - 300mm:847440 | 3 Korrus A | Windows | Pset_OpeningElementCommon - Reference: -A-01 2700x1500mm; sets with these values: 2
Basic Wall:Generic - 300mm:847453:1 | 2 Korrus | Walls | Pset_ElementShading - Roughness: 914.4 mm; Pset_OpeningElementCommon - Reference: Generic - 300mm; sets with these values: 2
Basic Wall:Generic - 300mm:847453:2 | 2 Korrus | Walls | Pset_ElementShading - Roughness: 914.4 mm; Pset_OpeningElementCommon - Reference: Generic - 300mm; sets with these values: 2
Basic Wall:Generic - 350mm:847456 | 2 Korrus | Windows | Pset_OpeningElementCommon - Reference: -A-05_1200x1500mm; sets with these values: 2
Basic Wall:Generic - 320mm:847457 | 2 Korrus | Doors | Pset_OpeningElementCommon - Reference: SU-P-01 - 1200x2100 EI 1korrus; sets with these values: 2
Basic Wall:Generic - 410mm:847459 | 2 Korrus | Doors | Pset_OpeningElementCommon - Reference: SU-P-08 - 1200x2100 EI; sets with these values: 2
Basic Wall:Generic - 320mm:847462 | 2 Korrus | Doors | Pset_OpeningElementCommon - Reference: SU-P-04 - 750x2100; sets with these values: 2
2 x Basic Wall:Generic - 300mm:847483 | 2 Korrus | Windows | Pset_OpeningElementCommon - Reference: -A-01 2700x1500mm; sets with these values: 2
2 x Basic Wall:Generic - 300mm:847483 | 2 Korrus | Windows | Pset_OpeningElementCommon - Reference: -A-03; sets with these values: 2
Basic Wall:Generic - 320mm:847492 | 2 Korrus | Windows | Pset_OpeningElementCommon - Reference: -A-03; sets with these values: 2
2 x Basic Wall:Generic - 300mm:847493 | 3 korrus | Windows | Pset_OpeningElementCommon - Reference: -A-05_1200x1500mm; sets with these values: 2
2 x Basic Wall:Generic - 350mm:847496 | 3 korrus | Windows | Pset_OpeningElementCommon - Reference: -A-05_1200x1500mm; sets with these values: 2
Basic Wall:Generic - 320mm:847497 | 3 korrus | Doors | Pset_OpeningElementCommon - Reference: SU-P-01 - 1200x2100 EI 2 korrus; sets with these values: 2
Basic Wall:Generic - 300mm:847498 | 2 Korrus A | Doors | Pset_OpeningElementCommon - Reference: SU-P-01 - 1200x2100 EI 2 korrus; sets with these values: 2
Basic Wall:Generic - 350mm:847499:1 | 3 korrus | Walls | Pset_ElementShading - Roughness: 914.4 mm; Pset_OpeningElementCommon - Reference: Generic - 350mm; sets with these values: 2
Basic Wall:Generic - 350mm:847499 | 3 korrus | Doors | Pset_OpeningElementCommon - Reference: SU-P-04 - 750x2100; sets with these values: 2
Basic Wall:Generic - 320mm:847502 | 3 korrus | Doors | Pset_OpeningElementCommon - Reference: SU-P-04 - 750x2100; sets with these values: 2
2 x Basic Wall:Generic - 300mm:847523 | 3 korrus | Windows | Pset_OpeningElementCommon - Reference: -A-01 2700x1500mm; sets with these values: 2
Basic Wall:Generic - 300mm:847524 | 3 korrus | Walls | Pset_OpeningElementCommon - Reference: Curtain Wall KLF-09; sets with these values: 2
Basic Wall:Generic - 300mm:847524 | 3 korrus | Walls | Pset_OpeningElementCommon - Reference: Curtain Wall KLF-08; sets with these values: 2
Basic Wall:Generic - 300mm:847530 | 3 Korrus A | Walls | Pset_OpeningElementCommon - Reference: Curtain Wall KLF-06; sets with these values: 2
Basic Wall:Generic - 300mm:847530 | 3 Korrus A | Walls | Pset_OpeningElementCommon - Reference: Curtain Wall KLF-04; sets with these values: 2
Basic Wall:Generic - 300mm:847530 | 3 Korrus A | Walls | Pset_OpeningElementCommon - Reference: Curtain Wall KLF-05; sets with these values: 2
Basic Wall:Generic - 410mm:847542 | 2 Korrus A | Doors | Pset_OpeningElementCommon - Reference: SU-P-08 - 1200x2100 EI; sets with these values: 2
Basic Wall:VS-01_Puitkonstruktsioon 368mm:847633 | 1 Korrus A | Windows | Pset_OpeningElementCommon - Reference: -A-03; sets with these values: 2
3 x Basic Wall:VS-01_Puitkonstruktsioon 368mm:847646 | 2 Korrus A | Windows | Pset_OpeningElementCommon - Reference: -A-03; sets with these values: 2
Basic Wall:VS-01_Puitkonstruktsioon 368mm:847647 | 2 Korrus A | Windows | Pset_OpeningElementCommon - Reference: -A-03; sets with these values: 2
Basic Wall:VS-01_Puitkonstruktsioon 368mm:847728 | 3 Korrus A | Windows | Pset_OpeningElementCommon - Reference: -A-03; sets with these values: 2
Basic Wall:VS-01_Puitkonstruktsioon 368mm:847777 | 3 Korrus A | Windows | Pset_OpeningElementCommon - Reference: -A-03; sets with these values: 2
Basic Wall:VS-01_Puitkonstruktsioon 368mm:847820 | 3 Korrus A | Windows | Pset_OpeningElementCommon - Reference: -A-03; sets with these values: 2
2 x Basic Wall:Generic - 300mm:847856 | Katus | Windows | Pset_OpeningElementCommon - Reference: -A-05_1200x1500mm; sets with these values: 2
2 x Basic Wall:Generic - 350mm:848135 | Katus | Windows | Pset_OpeningElementCommon - Reference: -A-05_1200x1500mm; sets with these values: 2
Basic Wall:Generic - 350mm:854158 | 1 Korrus | Rectangular Straight Wall Opening | Pset_ElementShading - Roughness: 914.4 mm; Pset_OpeningElementCommon - Reference: Generic - 350mm; sets with these values: 2
SMA_D02, 2-poolne:SU-M-04 - 1000x1800:2404765:1 | 0 Kelder
SMA_W1, 1-jaotus:-A-05_1200x1500mm:2293718:1 | 2 Korrus
sma_W3:-A-07 2000x1200mm 2:1776279:1 | 0 Kelder
SMA_D01, 1-poolne:SU-P-08 - 1200x2100 EI 3 korrus:1755816:1 | 3 Korrus A
SMA_D01, 1-poolne:SU-P-10- 900x2100 3 korrus:1718228:1 | 3 korrus
SMA_D01, 1-poolne:SU-P-10- 900x2100 3 korrus:1718227:1 | 3 korrus
1.0 W - 2x2:-A-03:1664419:1 | 1 Korrus
1.0 W - 2x2:-A-03:1663614:1 | 3 Korrus A
1.0 W - 2x2:-A-03:1664915:1 | 2 Korrus
Basic Wall:SS-01_Kips, 95mm metallkarkass:886867 | 1 Korrus | Doors | Pset_OpeningElementCommon - Reference: SU-P-09 - 1000x2100; sets with these values: 2
Basic Wall:SS-01_Kips, 95mm metallkarkass:886867 | 1 Korrus | Doors | Pset_OpeningElementCommon - Reference: SU-P-11 - 1000x2100; sets with these values: 2
Basic Wall:SS-02_Kips, 95mm metallkarkass 2:887992 | 1 Korrus A | Doors | Pset_OpeningElementCommon - Reference: SU-P-10- 900x2100 1 korrus; sets with these values: 2
Basic Wall:SS-02_Kips, 95mm metallkarkass 2:888110 | 1 Korrus A | Doors | Pset_OpeningElementCommon - Reference: SU-P-10- 900x2100 1 korrus; sets with these values: 2
3 x Basic Wall:SS-03_Kips, 66mm metallkarkass:888264 | 1 Korrus A | Doors | Pset_OpeningElementCommon - Reference: SU-P-04 - 750x2100; sets with these values: 2
Basic Wall:SS-02_Kips, 95mm metallkarkass 2:894259 | 1 Korrus A | Doors | Pset_OpeningElementCommon - Reference: SU-P-04 - 750x2100; sets with these values: 2
1.0 W - 2x2:-A-03:1664914:1 | 2 Korrus
Basic Wall:SS-02_Kips, 95mm metallkarkass 2:894259 | 1 Korrus A | Doors | Pset_ConcreteElementGeneral - FireRating: -; Pset_DoorCommon - IsExternal: no; Reference: SU-P-10- 900x2100 1 korrus; FireRating: -; AcousticRating: 35dB; Pset_QuantityTakeOff - Reference: SU-P-10- 900x2100 1 korrus
SMA_W1, 1-jaotus:-A-05_1200x1500mm:1659807:1 | 1 Korrus
sma_W3:-A-01 2700x1500mm:1658671:1 | 3 korrus
Basic Wall:SS-02_Kips, 95mm metallkarkass 2:911992 | 2 Korrus A | Doors | Pset_OpeningElementCommon - Reference: SU-P-04 - 750x2100; sets with these values: 2
Basic Wall:SS-02_Kips, 95mm metallkarkass 2:911992 | 2 Korrus A | Doors | Pset_OpeningElementCommon - Reference: SU-P-10- 900x2100 2 korrus; sets with these values: 2
Basic Wall:SS-02_Kips, 95mm metallkarkass 2:912009 | 2 Korrus A | Doors | Pset_OpeningElementCommon - Reference: SU-P-04 - 750x2100; sets with these values: 2
Basic Wall:SS-02_Kips, 95mm metallkarkass 2:912009 | 2 Korrus A | Doors | Pset_ConcreteElementGeneral - FireRating: -; Pset_DoorCommon - IsExternal: no; Reference: SU-P-10- 900x2100 2 korrus; FireRating: -; AcousticRating: 35dB; Pset_QuantityTakeOff - Reference: SU-P-10- 900x2100 2 korrus
Basic Wall:SS-02_Kips, 95mm metallkarkass 2:912010 | 2 Korrus A | Doors | Pset_OpeningElementCommon - Reference: SU-P-04 - 750x2100; sets with these values: 2
Basic Wall:SS-02_Kips, 95mm metallkarkass 2:912010 | 2 Korrus A | Doors | Pset_OpeningElementCommon - Reference: SU-P-10- 900x2100 2 korrus; sets with these values: 2
sma_W3:-A-01 2700x1500mm:1658670:1 | 3 korrus
sma_W3:-A-01 2700x1500mm:1658668:1 | 2 Korrus
sma_W3:-A-01 2700x1500mm:1658667:1 | 2 Korrus
sma_W3:-A-01 2700x1500mm:1658665:1 | 1 Korrus
sma_W3:-A-01 2700x1500mm:1658664:1 | 1 Korrus
SMA_D01, 1-poolne:SU-P-08 - 1200x2100 EI:1557387:1 | 2 Korrus A
Liugsein 2700-h:SU-L-03_Liugsein 5700x2700-h klassides:1255928:1 | 0 Kelder
SMA_D01, 1-poolne:SU-P-06 - 900x2100 EI-30:1213530:1 | 1 Korrus
Basic Wall:SS-01_Kips, 95mm metallkarkass:914870 | 2 Korrus | Doors | Pset_OpeningElementCommon - Reference: SU-P-04 - 750x2100; sets with these values: 2
Basic Wall:SS-01_Kips, 95mm metallkarkass:917539 | 2 Korrus | Doors | Pset_OpeningElementCommon - Reference: SU-P-04 - 750x2100; sets with these values: 2
SMA_D01, 1-poolne:SU-P-06 - 900x2100 EI-30:1177053:1 | 1 Korrus
Basic Wall:SS-02_Kips, 95mm metallkarkass 2:930583 | 2 Korrus A | Doors | Pset_ConcreteElementGeneral - FireRating: -; Pset_DoorCommon - IsExternal: no; Reference: SU-P-04 - 750x2100; FireRating: -; AcousticRating: -; Pset_QuantityTakeOff - Reference: SU-P-04 - 750x2100
Basic Wall:SS-02_Kips, 95mm metallkarkass 2:930583 | 2 Korrus A | Doors | Pset_ConcreteElementGeneral - FireRating: -; Pset_DoorCommon - IsExternal: no; Reference: SU-P-10- 900x2100 2 korrus; FireRating: -; AcousticRating: 35dB; Pset_QuantityTakeOff - Reference: SU-P-10- 900x2100 2 korrus
Basic Wall:SS-03_Kips, 66mm metallkarkass:932071 | 1 Korrus | Doors | Pset_OpeningElementCommon - Reference: SU-P-04 - 750x2100; sets with these values: 2
Basic Wall:Generic - 410mm:935418 | 1 Korrus | Doors | Pset_OpeningElementCommon - Reference: SU-P-08 - 1200x2100 EI 1 korrus; sets with these values: 2
Basic Wall:Generic - 300mm:936701 | 1 Korrus A | Windows | Pset_QuantityTakeOff - Reference: -A-01 2700x1500mm; Pset_WindowCommon - Reference: -A-01 2700x1500mm; IsExternal: yes; FireRating: -; AcousticRating: 35 dB
Basic Wall:Generic - 300mm:936701 | 1 Korrus A | Windows | Pset_OpeningElementCommon - Reference: -A-03; sets with these values: 2
2 x Basic Wall:VS-04_200mm EPS+ krohv:1291842 | 1 Korrus | <Sketch> | Pset_ElementShading - Roughness: 914.4 mm; Pset_OpeningElementCommon - Reference: VS-04_200mm EPS+ krohv; sets with these values: 2
SMA_D01, 1-poolne:SU-P-04 - 750x2100:1898575:1 | 1 Korrus
Basic Wall:VS-04_200mm EPS+ krohv:937461 | 1 Korrus | Windows | Pset_OpeningElementCommon - Reference: -A-06 2000x1500mm; sets with these values: 2
2 x Basic Wall:VS-04_200mm EPS+ krohv:937461 | 1 Korrus | Windows | Pset_OpeningElementCommon - Reference: -A-03; sets with these values: 2
Basic Wall:VS-04_200mm EPS+ krohv:937714 | 1 Korrus A | Windows | Pset_OpeningElementCommon - Reference: -A-03; sets with these values: 2
SMA_D01, 1-poolne:SU-P-04 - 750x2100:1165624:1 | 2 Korrus
SMA_D01, 1-poolne:SU-P-04 - 750x2100:1165600:1 | 2 Korrus
SMA_D01, 1-poolne:SU-P-04 - 750x2100:1165611:1 | 2 Korrus
Basic Wall:VS-04_200mm EPS+ krohv:939728 | 1 Korrus A | Windows | Pset_OpeningElementCommon - Reference: -A-03; sets with these values: 2
Basic Wall:VS-04_200mm EPS+ krohv:939773 | 1 Korrus A | Walls | Pset_OpeningElementCommon - Reference: Curtain Wall KLF-10; sets with these values: 2
Basic Wall:VS-04_200mm EPS+ krohv:939773 | 1 Korrus A | Walls | Pset_OpeningElementCommon - Reference: Curtain Wall KLF-07; sets with these values: 2
Basic Wall:VS-04_200mm EPS+ krohv:939773 | 1 Korrus A | Walls | Pset_OpeningElementCommon - Reference: Curtain Wall KLF-09; sets with these values: 2
Basic Wall:VS-04_200mm EPS+ krohv:939773 | 1 Korrus A | Walls | Pset_OpeningElementCommon - Reference: Curtain Wall KLF-08; sets with these values: 2
SMA_D01, 1-poolne:SU-P-04 - 750x2100:1165593:1 | 2 Korrus
Basic Wall:VS-04_200mm EPS+ krohv:939773 | 1 Korrus A | Walls | Pset_OpeningElementCommon - Reference: Curtain Wall SKF-02; sets with these values: 2
Basic Wall:VS-04_200mm EPS+ krohv:940184 | 1 Korrus A | Windows | Pset_OpeningElementCommon - Reference: -A-03; sets with these values: 2
2 x Basic Wall:VS-01_Puitkonstruktsioon 2:943836 | 1 Korrus | Windows | Pset_OpeningElementCommon - Reference: -A-03; sets with these values: 2
Basic Wall:VS-01_Puitkonstruktsioon 2:943836 | 1 Korrus | Windows | Pset_OpeningElementCommon - Reference: -A-06 2000x1500mm; sets with these values: 2
Basic Wall:VS-01_Puitkonstruktsioon 2:944282 | 1 Korrus | Windows | Pset_OpeningElementCommon - Reference: -A-03; sets with these values: 2
2 x Basic Wall:VS-00_200mm EPS+ krohv:945230 | 2 Korrus | Windows | Pset_OpeningElementCommon - Reference: -A-03; sets with these values: 2
2 x Basic Wall:VS-01_Puitkonstruktsioon 368mm:952563 | 2 Korrus | Windows | Pset_OpeningElementCommon - Reference: -A-03; sets with these values: 2
Basic Wall:VS-00_200mm EPS+ krohv:952564 | 2 Korrus | Windows | Pset_OpeningElementCommon - Reference: -A-03; sets with these values: 2
3 x Basic Wall:VS-01_Puitkonstruktsioon 368mm:952565 | 2 Korrus | Windows | Pset_OpeningElementCommon - Reference: -A-03; sets with these values: 2
SMA_D01, 1-poolne:SU-P-04 - 750x2100:1149612:1 | 1 Korrus
Basic Wall:VS-00_200mm EPS+ krohv:952575 | 3 korrus | Windows | Pset_OpeningElementCommon - Reference: -A-03; sets with these values: 2
Basic Wall:VS-04_200mm EPS+ krohv:954590 | 2 Korrus A | Walls | Pset_OpeningElementCommon - Reference: Curtain Wall KLF-06; sets with these values: 2
Basic Wall:VS-00_200mm EPS+ krohv:954591 | 2 Korrus A | Windows | Pset_OpeningElementCommon - Reference: -A-03; sets with these values: 2
Basic Wall:VS-04_200mm EPS+ krohv:954593 | 2 Korrus A | Windows | Pset_OpeningElementCommon - Reference: -A-03; sets with these values: 2
Basic Wall:VS-00_200mm EPS+ krohv:954594 | 2 Korrus A | Windows | Pset_OpeningElementCommon - Reference: -A-03; sets with these values: 2
Basic Wall:VS-00_200mm EPS+ krohv:954596 | 2 Korrus | Doors | Pset_OpeningElementCommon - Reference: SU-P-08 - 1200x2100 EI; sets with these values: 2
Basic Wall:VS-04_200mm EPS+ krohv:954809 | 3 korrus | Windows | Pset_OpeningElementCommon - Reference: -A-03; sets with these values: 2
Basic Wall:VS-04_200mm EPS+ krohv:954812 | 3 Korrus A | Walls | Pset_OpeningElementCommon - Reference: Curtain Wall KLF-06; sets with these values: 2
Basic Wall:VS-04_200mm EPS+ krohv:954812 | 3 Korrus A | Walls | Pset_OpeningElementCommon - Reference: Curtain Wall KLF-04; sets with these values: 2
Basic Wall:VS-04_200mm EPS+ krohv:954812 | 3 Korrus A | Walls | Pset_OpeningElementCommon - Reference: Curtain Wall KLF-05; sets with these values: 2
2 x Basic Wall:VS-04_200mm EPS+ krohv:1291842 | 3 Korrus A | <Sketch> | Pset_ElementShading - Roughness: 914.4 mm; Pset_OpeningElementCommon - Reference: VS-04_200mm EPS+ krohv; sets with these values: 2
Basic Wall:VS-04_200mm EPS+ krohv:954813 | 3 Korrus A | Windows | Pset_OpeningElementCommon - Reference: -A-03; sets with these values: 2
Basic Wall:VS-04_200mm EPS+ krohv:954814 | 3 Korrus A | Walls | Pset_OpeningElementCommon - Reference: Curtain Wall KLF-08; sets with these values: 2
Basic Wall:VS-04_200mm EPS+ krohv:954814 | 3 Korrus A | Walls | Pset_OpeningElementCommon - Reference: Curtain Wall KLF-10; sets with these values: 2
Basic Wall:VS-04_200mm EPS+ krohv:954814 | 3 Korrus A | Walls | Pset_OpeningElementCommon - Reference: Curtain Wall KLF-09; sets with these values: 2
SMA_D01, 1-poolne:SU-P-04 - 750x2100:1149606:1 | 1 Korrus
Basic Wall:SS-02_Kips, 95mm metallkarkass 2:959702 | 1 Korrus A | Doors | Pset_OpeningElementCommon - Reference: SU-P-04 - 750x2100; sets with these values: 2
Basic Wall:SS-02_Kips, 95mm metallkarkass 2:959702 | 1 Korrus A | Doors | Pset_ConcreteElementGeneral - FireRating: -; Pset_DoorCommon - IsExternal: no; Reference: SU-P-10- 900x2100 1 korrus; FireRating: -; AcousticRating: 35dB; Pset_QuantityTakeOff - Reference: SU-P-10- 900x2100 1 korrus
Basic Wall:SS-03_Kips, 66mm metallkarkass:960007 | 1 Korrus A | Doors | Pset_ConcreteElementGeneral - FireRating: -; Pset_DoorCommon - IsExternal: no; Reference: SU-P-10- 900x2100 1 korrus; FireRating: -; AcousticRating: 35dB; Pset_QuantityTakeOff - Reference: SU-P-10- 900x2100 1 korrus
Basic Wall:SS-02_Kips, 95mm metallkarkass 2:964410 | 1 Korrus A | Doors | Pset_OpeningElementCommon - Reference: SU-P-04 - 750x2100; sets with these values: 2
Basic Wall:SS-02_Kips, 95mm metallkarkass 2:964410 | 1 Korrus A | Doors | Pset_ConcreteElementGeneral - FireRating: -; Pset_DoorCommon - IsExternal: no; Reference: SU-P-10- 900x2100 1 korrus; FireRating: -; AcousticRating: 35dB; Pset_QuantityTakeOff - Reference: SU-P-10- 900x2100 1 korrus
Basic Wall:SS-02_Kips, 95mm metallkarkass 2:969154 | 2 Korrus A | Doors | Pset_ConcreteElementGeneral - FireRating: -; Pset_DoorCommon - IsExternal: no; Reference: SU-P-10- 900x2100 2 korrus; FireRating: -; AcousticRating: 35dB; Pset_QuantityTakeOff - Reference: SU-P-10- 900x2100 2 korrus
Basic Wall:SS-02_Kips, 95mm metallkarkass 2:969154 | 2 Korrus A | Doors | Pset_ConcreteElementGeneral - FireRating: -; Pset_DoorCommon - IsExternal: no; Reference: SU-P-04 - 750x2100; FireRating: -; AcousticRating: -; Pset_QuantityTakeOff - Reference: SU-P-04 - 750x2100
SMA_D01, 1-poolne:SU-P-01 - 1200x2100 EI:1147972:1 | 0 Kelder
SMA_D01, 1-poolne:SU-P-04 - 750x2100:1093861:1 | 3 Korrus A
Basic Wall:SS-06_ 150mm:980389 | 1 Korrus A | Doors | Pset_ConcreteElementGeneral - FireRating: EI-30; Pset_DoorCommon - IsExternal: no; Reference: SU-P-08 - 1200x2100 EI 1 korrus; FireRating: EI-30; AcousticRating: 35dB; Pset_QuantityTakeOff - Reference: SU-P-08 - 1200x2100 EI 1 korrus
2 x Basic Wall:SS-03_Kips, 66mm metallkarkass:980770 | 1 Korrus A | Doors | Pset_ConcreteElementGeneral - FireRating: -; Pset_DoorCommon - IsExternal: no; Reference: SU-P-04 - 750x2100; FireRating: -; AcousticRating: -; Pset_QuantityTakeOff - Reference: SU-P-04 - 750x2100
Basic Wall:SS-01_Kips, 95mm metallkarkass:981389 | 3 korrus | Doors | Pset_ConcreteElementGeneral - FireRating: -; Pset_DoorCommon - IsExternal: no; Reference: SU-P-04 - 750x2100; FireRating: -; AcousticRating: -; Pset_QuantityTakeOff - Reference: SU-P-04 - 750x2100
Basic Wall:SS-06_ 150mm:983449 | 2 Korrus A | Doors | Pset_OpeningElementCommon - Reference: SU-P-08 - 1200x2100 EI; sets with these values: 2
Basic Wall:Generic - 410mm:984298 | 2 Korrus | Doors | Pset_OpeningElementCommon - Reference: SU-P-08 - 1200x2100 EI; sets with these values: 2
2 x Basic Wall:SS-02_Kips, 95mm metallkarkass 2:984684 | 3 Korrus A | Doors | Pset_OpeningElementCommon - Reference: SU-P-04 - 750x2100; sets with these values: 2
2 x Basic Wall:SS-02_Kips, 95mm metallkarkass 2:984687 | 3 Korrus A | Doors | Pset_OpeningElementCommon - Reference: SU-P-04 - 750x2100; sets with these values: 2
2 x Basic Wall:SS-02_Kips, 95mm metallkarkass 2:984720 | 3 Korrus A | Doors | Pset_OpeningElementCommon - Reference: SU-P-04 - 750x2100; sets with these values: 2
SMA_D01, 1-poolne:SU-P-04 - 750x2100:1093860:1 | 3 Korrus A
2 x Basic Wall:SS-02_Kips, 95mm metallkarkass 2:984756 | 3 Korrus A | Doors | Pset_OpeningElementCommon - Reference: SU-P-04 - 750x2100; sets with these values: 2
Basic Wall:SS-02_Kips, 95mm metallkarkass 2:984815 | 3 Korrus A | Doors | Pset_OpeningElementCommon - Reference: SU-P-04 - 750x2100; sets with these values: 2
Basic Wall:SS-02_Kips, 95mm metallkarkass 2:984815 | 3 Korrus A | Doors | Pset_ConcreteElementGeneral - FireRating: -; Pset_DoorCommon - IsExternal: no; Reference: SU-P-04 - 750x2100; FireRating: -; AcousticRating: -; Pset_QuantityTakeOff - Reference: SU-P-04 - 750x2100
2 x Basic Wall:SS-03_Kips, 66mm metallkarkass:984834 | 3 Korrus A | Doors | Pset_OpeningElementCommon - Reference: SU-P-04 - 750x2100; sets with these values: 2
Basic Wall:SS-01_Kips, 95mm metallkarkass:985239 | 3 korrus | Doors | Pset_OpeningElementCommon - Reference: SU-P-04 - 750x2100; sets with these values: 2
SMA_D01, 1-poolne:SU-P-04 - 750x2100:1093849:1 | 3 Korrus A
SMA_D01, 1-poolne:SU-P-04 - 750x2100:1093848:1 | 3 Korrus A
SMA_D01, 1-poolne:SU-P-04 - 750x2100:1081761:1 | 1 Korrus A
Basic Wall:SS-06_ 150mm:1000858 | 0 Kelder | Doors | Pset_OpeningElementCommon - Reference: SU-M-01 - 1200x2100; sets with these values: 2
Basic Wall:SS-05_Sauna sein:1004283 | 0 Kelder | Windows | Pset_OpeningElementCommon - Reference: -A-07 2000x1200mm 2; sets with these values: 2
Basic Wall:SS-05_Sauna sein:1004335 | 0 Kelder | Doors | Pset_ConcreteElementGeneral - FireRating: -; Pset_DoorCommon - IsExternal: no; Reference: SU-KL-01 - 700x2100; FireRating: -; AcousticRating: -; Pset_QuantityTakeOff - Reference: SU-KL-01 - 700x2100
SMA_D01, 1-poolne:SU-P-04 - 750x2100:1081760:1 | 1 Korrus A
Basic Wall:VS-04_200mm EPS+ krohv:1014013 | 0 Kelder | Windows | Pset_OpeningElementCommon - Reference: -A-02 2000x1200mm; sets with these values: 2
Basic Wall:VS-00_200mm EPS+ krohv:1014380 | 0 Kelder | Windows | Pset_OpeningElementCommon - Reference: -A-02 2000x1200mm; sets with these values: 2
Basic Wall:VS-00_200mm EPS+ krohv:1014674:1 | 0 Kelder | Walls | Pset_ElementShading - Roughness: 914.4 mm; Pset_OpeningElementCommon - Reference: VS-00_200mm EPS+ krohv; sets with these values: 2
2 x Basic Wall:VS-00_200mm EPS+ krohv:937078 | 0 Kelder | <Sketch> | Pset_ElementShading - Roughness: 914.4 mm; Pset_OpeningElementCommon - Reference: VS-00_200mm EPS+ krohv; sets with these values: 2
Basic Wall:VS-00_200mm EPS+ krohv:1014964 | 0 Kelder | Windows | Pset_QuantityTakeOff - Reference: -A-04 2500x1200mm; Pset_WindowCommon - Reference: -A-04 2500x1200mm; IsExternal: yes; FireRating: -; AcousticRating: 35 dB
SMA_D01, 1-poolne:SU-P-04 - 750x2100:1081750:1 | 1 Korrus A
SMA_D01, 1-poolne:SU-P-04 - 750x2100:1081749:1 | 1 Korrus A
Basic Wall:VS-04_200mm EPS+ krohv:1050455 | 2 Korrus A | Walls | Pset_OpeningElementCommon - Reference: Curtain Wall KLF-10; sets with these values: 2
SMA_D01, 1-poolne:SU-P-04 - 750x2100:1081744:1 | 1 Korrus A
SMA_D01, 1-poolne:SU-P-04 - 750x2100:1081745:1 | 1 Korrus A
sma_W3:-A-02 2000x1200mm:1018344:1 | 0 Kelder
SMA_D01, 1-poolne:SU-AL-01 - 800x2100:1003749:1 | 0 Kelder
SMA_D01, 1-poolne:SU-M-03- 900x2100:1001097:1 | 0 Kelder
SMA_D02, 2-poolne:SU-M-01 - 1200x2100:1000967:1 | 0 Kelder
SMA_D01, 1-poolne:SU-M-02 - 1000x2100:1001055:1 | 0 Kelder
SMA_D01, 1-poolne:SU-KL-01 - 700x2100:1003642:1 | 0 Kelder
SMA_D01, 1-poolne:SU-M-02 - 1000x2100:1004780:1 | 0 Kelder
SMA_D01, 1-poolne:SU-M-02 - 1000x2100:1001475:1 | 0 Kelder
SMA_D01, 1-poolne:SU-M-03- 900x2100:1001388:1 | 0 Kelder
SMA_D01, 1-poolne:SU-P-04 - 750x2100:1308913:1 | 0 Kelder
SMA_D01, 1-poolne:SU-P-06 - 900x2100 EI-30:1199508:1 | 0 Kelder
SMA_D01, 1-poolne:SU-P-05- 900x2100:1007118:1 | 0 Kelder
SMA_D01, 1-poolne:SU-P-03 - 1200x2100:1000728:1 | 0 Kelder
SMA_D02, 2-poolne:SU-P-02 - 1500x2100:999266:1 | 0 Kelder
1.0 W - 2x2:-A-03:989668:1 | 2 Korrus A
1.0 W - 2x2:-A-03:989630:1 | 2 Korrus A
Basic Wall:VS-07_Puitkonstruktsioon:1122215 | 2 Korrus A | Walls | Pset_OpeningElementCommon - Reference: Curtain Wall KLF-06; sets with these values: 2
Basic Wall:VS-07_Puitkonstruktsioon:1122215 | 2 Korrus A | Walls | Pset_OpeningElementCommon - Reference: Curtain Wall KLF-05; sets with these values: 2
Basic Wall:VS-07_Puitkonstruktsioon:1122215 | 2 Korrus A | Walls | Pset_OpeningElementCommon - Reference: Curtain Wall KLF-04; sets with these values: 2
1.0 W - 2x2:-A-03:989613:1 | 1 Korrus A
Basic Wall:Generic - 380mm:1136810 | 1 Korrus | Doors | Pset_OpeningElementCommon - Reference: SU-P-01 - 1200x2100 EI; sets with these values: 2
Basic Wall:Generic - 380mm:1136810 | 1 Korrus | Doors | Pset_ConcreteElementGeneral - FireRating: -; Pset_DoorCommon - IsExternal: no; Reference: SU-M-03- 900x2100; FireRating: -; AcousticRating: -; Pset_QuantityTakeOff - Reference: SU-M-03- 900x2100
Basic Wall:Generic - 380mm:1136810 | 1 Korrus | Doors | Pset_OpeningElementCommon - Reference: SU-P-01 - 1200x2100 EI 1korrus; sets with these values: 2
1.0 W - 2x2:-A-03:989612:1 | 1 Korrus A
Basic Wall:Generic - 410mm:1147973 | 0 Kelder | Doors | Pset_ConcreteElementGeneral - FireRating: -; Pset_DoorCommon - IsExternal: no; Reference: SU-M-03- 900x2100; FireRating: -; AcousticRating: -; Pset_QuantityTakeOff - Reference: SU-M-03- 900x2100
1.0 W - 2x2:-A-03:989475:1 | 2 Korrus A
SMA_D01, 1-poolne:SU-P-04 - 750x2100:1133644:1 | 3 korrus
Basic Wall:SS-02_Kips, 95mm metallkarkass 2:1177052 | 1 Korrus | Doors | Pset_OpeningElementCommon - Reference: SU-P-06 - 900x2100 EI-30; sets with these values: 2
Basic Wall:SS-02_Kips, 95mm metallkarkass 2:1177052 | 1 Korrus | Doors | Pset_OpeningElementCommon - Reference: SU-P-04 - 750x2100; sets with these values: 2
SMA_D01, 1-poolne:SU-P-04 - 750x2100:985246:1 | 3 korrus
SMA_D01, 1-poolne:SU-P-10- 900x2100 3 korrus:985191:1 | 3 korrus
SMA_D01, 1-poolne:SU-P-10- 900x2100 3 korrus:985190:1 | 3 korrus
Basic Wall:SS-01_Kips, 95mm metallkarkass:1215416 | 1 Korrus | Doors | Pset_OpeningElementCommon - Reference: SU-P-11 - 1000x2100; sets with these values: 2
SMA_D01, 1-poolne:SU-P-04 - 750x2100:984800:1 | 3 Korrus A
SMA_D01, 1-poolne:SU-P-04 - 750x2100:984798:1 | 3 Korrus A
SMA_D01, 1-poolne:SU-P-04 - 750x2100:984761:1 | 3 Korrus A
SMA_D01, 1-poolne:SU-P-04 - 750x2100:984759:1 | 3 Korrus A
SMA_D01, 1-poolne:SU-P-10- 900x2100 3 korrus:984740:1 | 3 Korrus A
SMA_D01, 1-poolne:SU-P-10- 900x2100 3 korrus:984739:1 | 3 Korrus A
Basic Wall:SS-01_Kips, 95mm metallkarkass:1376688 | 2 Korrus A | Doors | Pset_OpeningElementCommon - Reference: SU-P-04 - 750x2100; sets with these values: 2
Basic Wall:SS-01_Kips, 95mm metallkarkass:1376688 | 2 Korrus A | Doors | Pset_ConcreteElementGeneral - FireRating: -; Pset_DoorCommon - IsExternal: no; Reference: SU-P-04 - 750x2100; FireRating: -; AcousticRating: -; Pset_QuantityTakeOff - Reference: SU-P-04 - 750x2100
Basic Wall:SS-02_Kips, 95mm metallkarkass 2:1376755 | 2 Korrus A | Doors | Pset_ConcreteElementGeneral - FireRating: -; Pset_DoorCommon - IsExternal: no; Reference: SU-P-04 - 750x2100; FireRating: -; AcousticRating: -; Pset_QuantityTakeOff - Reference: SU-P-04 - 750x2100
Basic Wall:SS-02_Kips, 95mm metallkarkass 2:1376755 | 2 Korrus A | Doors | Pset_ConcreteElementGeneral - FireRating: -; Pset_DoorCommon - IsExternal: no; Reference: SU-P-10- 900x2100 2 korrus; FireRating: -; AcousticRating: 35dB; Pset_QuantityTakeOff - Reference: SU-P-10- 900x2100 2 korrus
SMA_D01, 1-poolne:SU-P-07 - 1000x2100 3korrus:984735:1 | 3 Korrus A
Counter Top w Sink:600mm Depth:1441808:1 | 308 | Casework | Pset_OpeningElementCommon - Reference: 600mm Depth; sets with these values: 2
SMA_D01, 1-poolne:SU-P-04 - 750x2100:984731:1 | 3 Korrus A
SMA_D01, 1-poolne:SU-P-04 - 750x2100:984729:1 | 3 Korrus A
SMA_D01, 1-poolne:SU-P-10- 900x2100 3 korrus:984697:1 | 3 Korrus A
SMA_D01, 1-poolne:SU-P-10- 900x2100 3 korrus:984696:1 | 3 Korrus A
Basic Wall:Generic - 300mm:1585110 | 2 Korrus | Walls | Pset_OpeningElementCommon - Reference: Curtain Wall KLF-10; sets with these values: 2
Basic Wall:Generic - 300mm:1585110 | 2 Korrus | Walls | Pset_OpeningElementCommon - Reference: Curtain Wall KLF-09; sets with these values: 2
Basic Wall:Generic - 300mm:1585110 | 2 Korrus | Walls | Pset_OpeningElementCommon - Reference: Curtain Wall KLF-08; sets with these values: 2
2 x Basic Wall:Generic - 350mm:1658661 | 1 Korrus | Windows | Pset_OpeningElementCommon - Reference: -A-01 2700x1500mm; sets with these values: 2
Basic Wall:Generic - 350mm:1658661 | 1 Korrus | Windows | Pset_OpeningElementCommon - Reference: -A-03; sets with these values: 2
SMA_D01, 1-poolne:SU-P-07 - 1000x2100 3korrus:1064311:1 | 3 Korrus A
Basic Wall:Generic - 350mm:1658661 | 1 Korrus | Windows | Pset_QuantityTakeOff - Reference: -A-03; Pset_WindowCommon - Reference: -A-03; IsExternal: yes; FireRating: -; AcousticRating: 35 dB
2 x Basic Wall:Generic - 300mm:1658662 | 2 Korrus | Windows | Pset_OpeningElementCommon - Reference: -A-01 2700x1500mm; sets with these values: 2
2 x Basic Wall:Generic - 350mm:1658663 | 3 korrus | Windows | Pset_OpeningElementCommon - Reference: -A-01 2700x1500mm; sets with these values: 2
Basic Wall:VS-04_200mm EPS+ krohv:1659808 | 1 Korrus | Doors | Pset_ConcreteElementGeneral - FireRating: EI-30; Pset_DoorCommon - IsExternal: no; Reference: SU-P-08 - 1200x2100 EI 1 korrus; FireRating: EI-30; AcousticRating: 35dB; Pset_QuantityTakeOff - Reference: SU-P-08 - 1200x2100 EI 1 korrus
2 x Basic Wall:VS-01_Puitkonstruktsioon 368mm:441435 | 3 Korrus A | <Sketch> | Pset_ElementShading - Roughness: 914.4 mm; Pset_OpeningElementCommon - Reference: VS-01_Puitkonstruktsioon 368mm; sets with these values: 2
Basic Wall:VS-01_Puitkonstruktsioon 368mm:1664330 | 3 korrus | Windows | Pset_OpeningElementCommon - Reference: -A-03; sets with these values: 2
Basic Wall:VS-01_Puitkonstruktsioon 368mm:1664658 | 3 korrus | Windows | Pset_OpeningElementCommon - Reference: -A-03; sets with these values: 2
SMA_D01, 1-poolne:SU-P-07 - 1000x2100 3korrus:984734:1 | 3 Korrus A
Basic Wall:Generic - 400mm:1689257 | 0 Kelder | Doors | Pset_DoorCommon - IsExternal: no; Reference: SU-L-03_Liugsein 5700x2700-h klassides; Pset_QuantityTakeOff - Reference: SU-L-03_Liugsein 5700x2700-h klassides
Basic Wall:Generic - 400mm:1689612 | 0 Kelder | Doors | Pset_DoorCommon - IsExternal: no; Reference: SU-L-03_Liugsein 5700x2700-h klassides; Pset_QuantityTakeOff - Reference: SU-L-03_Liugsein 5700x2700-h klassides
Basic Wall:Generic - 410mm:1690238:1 | 1 Korrus A | Walls | Pset_ElementShading - Roughness: 914.4 mm; Pset_OpeningElementCommon - Reference: Generic - 410mm; sets with these values: 2
Basic Wall:Generic - 410mm:1690238:2 | 1 Korrus A | Walls | Pset_ElementShading - Roughness: 914.4 mm; Pset_OpeningElementCommon - Reference: Generic - 410mm; sets with these values: 2
Basic Wall:Generic - 400mm:1690493:1 | 1 Korrus A | Walls | Pset_ElementShading - Roughness: 914.4 mm; Pset_OpeningElementCommon - Reference: Generic - 400mm; sets with these values: 2
Basic Wall:Generic - 400mm:1691272:1 | 2 Korrus A | Walls | Pset_ElementShading - Roughness: 914.4 mm; Pset_OpeningElementCommon - Reference: Generic - 400mm; sets with these values: 2
Basic Wall:Generic - 380mm:1691347:1 | 2 Korrus A | Walls | Pset_ElementShading - Roughness: 914.4 mm; Pset_OpeningElementCommon - Reference: Generic - 380mm; sets with these values: 2
Basic Wall:SS-02_Kips, 95mm metallkarkass 2:1714501 | 2 Korrus | Doors | Pset_OpeningElementCommon - Reference: SU-P-04 - 750x2100; sets with these values: 2
Basic Wall:SS-02_Kips, 95mm metallkarkass 2:1714501 | 2 Korrus | Doors | Pset_ConcreteElementGeneral - FireRating: -; Pset_DoorCommon - IsExternal: no; Reference: SU-P-10- 900x2100 2 korrus; FireRating: -; AcousticRating: 35dB; Pset_QuantityTakeOff - Reference: SU-P-10- 900x2100 2 korrus
Basic Wall:SS-01_Kips, 95mm metallkarkass:1715444 | 1 Korrus | Walls | Pset_OpeningElementCommon - Reference: Curtain Wall SKF-04; sets with these values: 2
Basic Wall:SS-01_Kips, 95mm metallkarkass:1715444 | 1 Korrus | Walls | Pset_OpeningElementCommon - Reference: Curtain Wall SKF-03; sets with these values: 2
Basic Wall:SS-01_Kips, 95mm metallkarkass:1715444 | 1 Korrus | Doors | Pset_OpeningElementCommon - Reference: SU-P-04 - 750x2100; sets with these values: 2
SMA_D01, 1-poolne:SU-P-07 - 1000x2100 3korrus:1064425:1 | 3 Korrus A
Basic Wall:SS-02_Kips, 95mm metallkarkass 2:1715751 | 1 Korrus A | Doors | Pset_ConcreteElementGeneral - FireRating: -; Pset_DoorCommon - IsExternal: no; Reference: SU-P-10- 900x2100 1 korrus; FireRating: -; AcousticRating: 35dB; Pset_QuantityTakeOff - Reference: SU-P-10- 900x2100 1 korrus
Basic Wall:SS-02_Kips, 95mm metallkarkass 2:1715751 | 1 Korrus A | Doors | Pset_ConcreteElementGeneral - FireRating: -; Pset_DoorCommon - IsExternal: no; Reference: SU-P-04 - 750x2100; FireRating: -; AcousticRating: -; Pset_QuantityTakeOff - Reference: SU-P-04 - 750x2100
Basic Wall:SS-02_Kips, 95mm metallkarkass 2:1716082 | 1 Korrus A | Doors | Pset_ConcreteElementGeneral - FireRating: -; Pset_DoorCommon - IsExternal: no; Reference: SU-P-04 - 750x2100; FireRating: -; AcousticRating: -; Pset_QuantityTakeOff - Reference: SU-P-04 - 750x2100
Basic Wall:SS-02_Kips, 95mm metallkarkass 2:1716082 | 1 Korrus A | Doors | Pset_ConcreteElementGeneral - FireRating: -; Pset_DoorCommon - IsExternal: no; Reference: SU-P-10- 900x2100 1 korrus; FireRating: -; AcousticRating: 35dB; Pset_QuantityTakeOff - Reference: SU-P-10- 900x2100 1 korrus
Basic Wall:SS-01_Kips, 95mm metallkarkass:1716120 | 1 Korrus A | Doors | Pset_ConcreteElementGeneral - FireRating: -; Pset_DoorCommon - IsExternal: no; Reference: SU-P-04 - 750x2100; FireRating: -; AcousticRating: -; Pset_QuantityTakeOff - Reference: SU-P-04 - 750x2100
Basic Wall:SS-01_Kips, 95mm metallkarkass:1716120 | 1 Korrus A | Doors | Pset_OpeningElementCommon - Reference: SU-P-04 - 750x2100; sets with these values: 2
SMA_D01, 1-poolne:SU-P-07 - 1000x2100 3korrus:984733:1 | 3 Korrus A
SMA_D01, 1-poolne:SU-P-10- 900x2100 3 korrus:984689:1 | 3 Korrus A
SMA_D01, 1-poolne:SU-P-10- 900x2100 3 korrus:984688:1 | 3 Korrus A
SMA_D01, 1-poolne:SU-P-10- 900x2100 3 korrus:984699:1 | 3 Korrus A
SMA_D01, 1-poolne:SU-P-10- 900x2100 3 korrus:984698:1 | 3 Korrus A
SMA_D01, 1-poolne:SU-P-10- 900x2100 3 korrus:984686:1 | 3 Korrus A
SMA_D01, 1-poolne:SU-P-10- 900x2100 3 korrus:984685:1 | 3 Korrus A
SMA_D01, 1-poolne:SU-P-04 - 750x2100:1099340:1 | 3 korrus
Basic Wall:SS-08_Kips, 66mm metallkarkass 3:1758409 | 2 Korrus A | Doors | Pset_OpeningElementCommon - Reference: SU-P-08 - 1200x2100 EI; sets with these values: 2
Basic Wall:SS-02_Kips, 95mm metallkarkass 2:1759803 | 3 korrus | Doors | Pset_ConcreteElementGeneral - FireRating: -; Pset_DoorCommon - IsExternal: no; Reference: SU-P-04 - 750x2100; FireRating: -; AcousticRating: -; Pset_QuantityTakeOff - Reference: SU-P-04 - 750x2100
SMA_D01, 1-poolne:SU-P-04 - 750x2100:981304:1 | 3 korrus
Basic Wall:SS-02_Kips, 95mm metallkarkass 2:1759803 | 3 korrus | Doors | Pset_ConcreteElementGeneral - FireRating: -; Pset_DoorCommon - IsExternal: no; Reference: SU-P-10- 900x2100 3 korrus; FireRating: -; AcousticRating: 35dB; Pset_QuantityTakeOff - Reference: SU-P-10- 900x2100 3 korrus
Basic Wall:SS-02_Kips, 95mm metallkarkass 2:1760818 | 3 korrus | Doors | Pset_OpeningElementCommon - Reference: SU-P-04 - 750x2100; sets with these values: 2
Basic Wall:SS-02_Kips, 95mm metallkarkass 2:1760818 | 3 korrus | Doors | Pset_ConcreteElementGeneral - FireRating: -; Pset_DoorCommon - IsExternal: no; Reference: SU-P-10- 900x2100 3 korrus; FireRating: -; AcousticRating: 35dB; Pset_QuantityTakeOff - Reference: SU-P-10- 900x2100 3 korrus
Basic Wall:SS-01_Kips, 95mm metallkarkass:1761207 | 2 Korrus A | Doors | Pset_ConcreteElementGeneral - FireRating: -; Pset_DoorCommon - IsExternal: no; Reference: SU-P-04 - 750x2100; FireRating: -; AcousticRating: -; Pset_QuantityTakeOff - Reference: SU-P-04 - 750x2100
Basic Wall:SS-01_Kips, 95mm metallkarkass:1761207 | 2 Korrus A | Doors | Pset_OpeningElementCommon - Reference: SU-P-04 - 750x2100; sets with these values: 2
Basic Wall:SS-02_Kips, 95mm metallkarkass 2:1761217 | 2 Korrus A | Doors | Pset_ConcreteElementGeneral - FireRating: -; Pset_DoorCommon - IsExternal: no; Reference: SU-P-04 - 750x2100; FireRating: -; AcousticRating: -; Pset_QuantityTakeOff - Reference: SU-P-04 - 750x2100
Basic Wall:SS-02_Kips, 95mm metallkarkass 2:1761217 | 2 Korrus A | Doors | Pset_ConcreteElementGeneral - FireRating: -; Pset_DoorCommon - IsExternal: no; Reference: SU-P-10- 900x2100 2 korrus; FireRating: -; AcousticRating: 35dB; Pset_QuantityTakeOff - Reference: SU-P-10- 900x2100 2 korrus
2 x Basic Wall:SS-01_Kips, 95mm metallkarkass:1761249 | 2 Korrus A | Doors | Pset_ConcreteElementGeneral - FireRating: -; Pset_DoorCommon - IsExternal: no; Reference: SU-P-04 - 750x2100; FireRating: -; AcousticRating: -; Pset_QuantityTakeOff - Reference: SU-P-04 - 750x2100
Basic Wall:SS-02_Kips, 95mm metallkarkass 2:1761289 | 2 Korrus A | Doors | Pset_ConcreteElementGeneral - FireRating: -; Pset_DoorCommon - IsExternal: no; Reference: SU-P-04 - 750x2100; FireRating: -; AcousticRating: -; Pset_QuantityTakeOff - Reference: SU-P-04 - 750x2100
Basic Wall:SS-02_Kips, 95mm metallkarkass 2:1761289 | 2 Korrus A | Doors | Pset_ConcreteElementGeneral - FireRating: -; Pset_DoorCommon - IsExternal: no; Reference: SU-P-10- 900x2100 2 korrus; FireRating: -; AcousticRating: 35dB; Pset_QuantityTakeOff - Reference: SU-P-10- 900x2100 2 korrus
Basic Wall:SS-01_Kips, 95mm metallkarkass:1761336 | 2 Korrus A | Doors | Pset_OpeningElementCommon - Reference: SU-P-04 - 750x2100; sets with these values: 2
Basic Wall:SS-01_Kips, 95mm metallkarkass:1761336 | 2 Korrus A | Doors | Pset_ConcreteElementGeneral - FireRating: -; Pset_DoorCommon - IsExternal: no; Reference: SU-P-04 - 750x2100; FireRating: -; AcousticRating: -; Pset_QuantityTakeOff - Reference: SU-P-04 - 750x2100
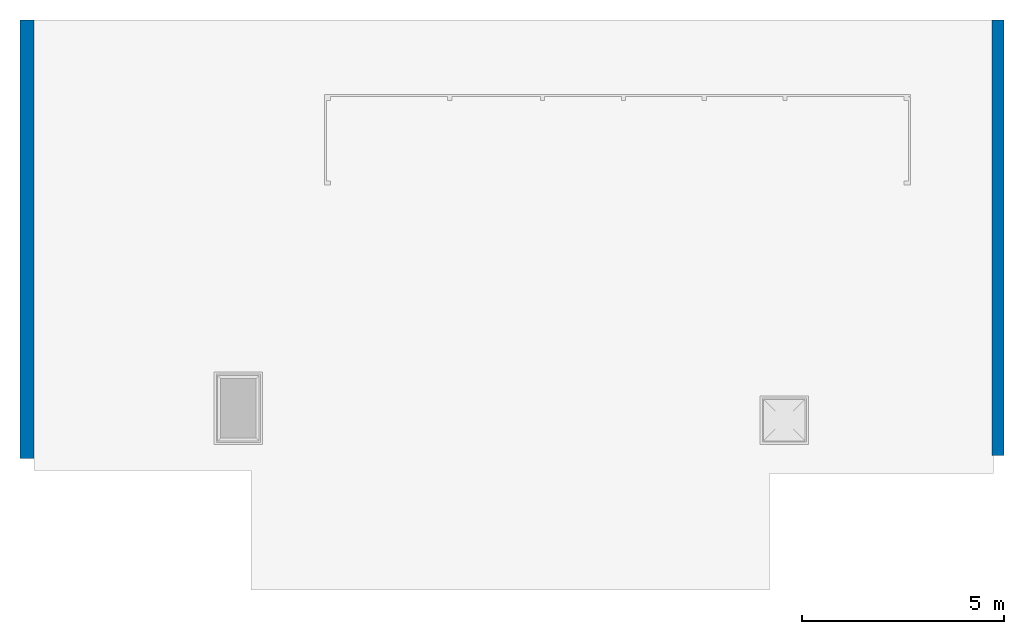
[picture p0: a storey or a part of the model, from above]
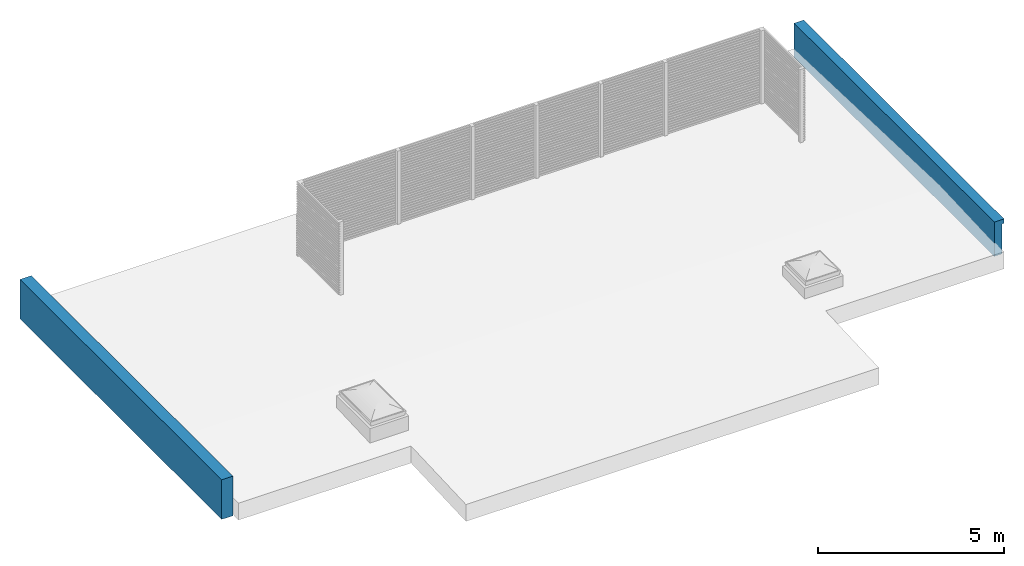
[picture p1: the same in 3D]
Properties of the parts of a building model (IFC2X3), part 6 of 7

# IfcOpeningElement: Opening (512)
Name | In | Category
Basic Wall:SS-02_Kips, 95mm metallkarkass 2:1761370 | 2 Korrus A | Doors | Pset_ConcreteElementGeneral - FireRating: -; Pset_DoorCommon - IsExternal: no; Reference: SU-P-04 - 750x2100; FireRating: -; AcousticRating: -; Pset_QuantityTakeOff - Reference: SU-P-04 - 750x2100
SMA_D01, 1-poolne:SU-P-10- 900x2100 3 korrus:981299:1 | 3 korrus
Basic Wall:SS-02_Kips, 95mm metallkarkass 2:1761370 | 2 Korrus A | Doors | Pset_ConcreteElementGeneral - FireRating: -; Pset_DoorCommon - IsExternal: no; Reference: SU-P-10- 900x2100 2 korrus; FireRating: -; AcousticRating: 35dB; Pset_QuantityTakeOff - Reference: SU-P-10- 900x2100 2 korrus
Basic Wall:SS-01_Kips, 95mm metallkarkass:1762245 | 1 Korrus A | Doors | Pset_OpeningElementCommon - Reference: SU-P-04 - 750x2100; sets with these values: 2
Basic Wall:SS-01_Kips, 95mm metallkarkass:1762245 | 1 Korrus A | Doors | Pset_ConcreteElementGeneral - FireRating: -; Pset_DoorCommon - IsExternal: no; Reference: SU-P-04 - 750x2100; FireRating: -; AcousticRating: -; Pset_QuantityTakeOff - Reference: SU-P-04 - 750x2100
Basic Wall:SS-02_Kips, 95mm metallkarkass 2:1762254 | 1 Korrus A | Doors | Pset_OpeningElementCommon - Reference: SU-P-04 - 750x2100; sets with these values: 2
Basic Wall:SS-02_Kips, 95mm metallkarkass 2:1762254 | 1 Korrus A | Doors | Pset_ConcreteElementGeneral - FireRating: -; Pset_DoorCommon - IsExternal: no; Reference: SU-P-10- 900x2100 1 korrus; FireRating: -; AcousticRating: 35dB; Pset_QuantityTakeOff - Reference: SU-P-10- 900x2100 1 korrus
2 x Basic Wall:SS-01_Kips, 95mm metallkarkass:1762274 | 1 Korrus A | Doors | Pset_OpeningElementCommon - Reference: SU-P-04 - 750x2100; sets with these values: 2
Basic Wall:SS-02_Kips, 95mm metallkarkass 2:1762341 | 1 Korrus A | Doors | Pset_ConcreteElementGeneral - FireRating: -; Pset_DoorCommon - IsExternal: no; Reference: SU-P-10- 900x2100 1 korrus; FireRating: -; AcousticRating: 35dB; Pset_QuantityTakeOff - Reference: SU-P-10- 900x2100 1 korrus
Basic Wall:SS-02_Kips, 95mm metallkarkass 2:1762341 | 1 Korrus A | Doors | Pset_OpeningElementCommon - Reference: SU-P-04 - 750x2100; sets with these values: 2
Basic Wall:SS-01_Kips, 95mm metallkarkass:1762376 | 1 Korrus A | Doors | Pset_ConcreteElementGeneral - FireRating: -; Pset_DoorCommon - IsExternal: no; Reference: SU-P-04 - 750x2100; FireRating: -; AcousticRating: -; Pset_QuantityTakeOff - Reference: SU-P-04 - 750x2100
Basic Wall:SS-01_Kips, 95mm metallkarkass:1762376 | 1 Korrus A | Doors | Pset_OpeningElementCommon - Reference: SU-P-04 - 750x2100; sets with these values: 2
Basic Wall:SS-02_Kips, 95mm metallkarkass 2:1762428 | 1 Korrus A | Doors | Pset_ConcreteElementGeneral - FireRating: -; Pset_DoorCommon - IsExternal: no; Reference: SU-P-04 - 750x2100; FireRating: -; AcousticRating: -; Pset_QuantityTakeOff - Reference: SU-P-04 - 750x2100
Basic Wall:SS-02_Kips, 95mm metallkarkass 2:1762428 | 1 Korrus A | Doors | Pset_ConcreteElementGeneral - FireRating: -; Pset_DoorCommon - IsExternal: no; Reference: SU-P-10- 900x2100 1 korrus; FireRating: -; AcousticRating: 35dB; Pset_QuantityTakeOff - Reference: SU-P-10- 900x2100 1 korrus
Basic Wall:SS-01_Kips, 95mm metallkarkass:1763047 | 1 Korrus A | Doors | Pset_ConcreteElementGeneral - FireRating: -; Pset_DoorCommon - IsExternal: no; Reference: SU-P-04 - 750x2100; FireRating: -; AcousticRating: -; Pset_QuantityTakeOff - Reference: SU-P-04 - 750x2100
SMA_D01, 1-poolne:SU-P-10- 900x2100 3 korrus:981298:1 | 3 korrus
Basic Wall:SS-02_Kips, 95mm metallkarkass 2:1766373 | 2 Korrus A | Doors | Pset_ConcreteElementGeneral - FireRating: -; Pset_DoorCommon - IsExternal: no; Reference: SU-P-10- 900x2100 2 korrus; FireRating: -; AcousticRating: 35dB; Pset_QuantityTakeOff - Reference: SU-P-10- 900x2100 2 korrus
2 x Basic Wall:SS-01_Kips, 95mm metallkarkass:1766432 | 2 Korrus A | Doors | Pset_ConcreteElementGeneral - FireRating: -; Pset_DoorCommon - IsExternal: no; Reference: SU-P-04 - 750x2100; FireRating: -; AcousticRating: -; Pset_QuantityTakeOff - Reference: SU-P-04 - 750x2100
Basic Wall:SS-02_Kips, 95mm metallkarkass 2:1766930 | 2 Korrus | Doors | Pset_OpeningElementCommon - Reference: SU-P-04 - 750x2100; sets with these values: 2
Basic Wall:SS-02_Kips, 95mm metallkarkass 2:1766930 | 2 Korrus | Doors | Pset_ConcreteElementGeneral - FireRating: -; Pset_DoorCommon - IsExternal: no; Reference: SU-P-10- 900x2100 2 korrus; FireRating: -; AcousticRating: 35dB; Pset_QuantityTakeOff - Reference: SU-P-10- 900x2100 2 korrus
Basic Wall:SS-06_ 150mm:1771519 | 2 Korrus A | Doors | Pset_ConcreteElementGeneral - FireRating: -; Pset_DoorCommon - IsExternal: no; Reference: SU-P-10- 900x2100 2 korrus; FireRating: -; AcousticRating: 35dB; Pset_QuantityTakeOff - Reference: SU-P-10- 900x2100 2 korrus
Basic Wall:SS-06_ 150mm:1771605 | 3 Korrus A | Doors | Pset_ConcreteElementGeneral - FireRating: -; Pset_DoorCommon - IsExternal: no; Reference: SU-P-10- 900x2100 3 korrus; FireRating: -; AcousticRating: 35dB; Pset_QuantityTakeOff - Reference: SU-P-10- 900x2100 3 korrus
SMA_D01, 1-poolne:SU-P-10- 900x2100 3 korrus:981300:1 | 3 korrus
SMA_D01, 1-poolne:SU-P-10- 900x2100 3 korrus:981297:1 | 3 korrus
1.0 W - 2x2:-A-03:975912:1 | 1 Korrus A
1.0 W - 2x2:-A-03:975865:1 | 1 Korrus A
Basic Wall:Generic - 300mm:1950151 | 3 korrus | Walls | Pset_OpeningElementCommon - Reference: Curtain Wall KLF-05; sets with these values: 2
Basic Wall:Generic - 300mm:1950151 | 3 korrus | Walls | Pset_OpeningElementCommon - Reference: Curtain Wall KLF-04; sets with these values: 2
Basic Wall:Generic - 300mm:1950151 | 3 korrus | Walls | Pset_OpeningElementCommon - Reference: Curtain Wall KLF-06; sets with these values: 2
Basic Wall:Generic - 300mm:1950524 | 2 Korrus | Walls | Pset_OpeningElementCommon - Reference: Curtain Wall KLF-09; sets with these values: 2
1.0 W - 2x2:-A-03:975582:1 | 1 Korrus A
Basic Wall:Generic - 300mm:1950524 | 2 Korrus | Walls | Pset_OpeningElementCommon - Reference: Curtain Wall KLF-08; sets with these values: 2
Basic Wall:Generic - 300mm:1950524 | 2 Korrus | Walls | Pset_OpeningElementCommon - Reference: Curtain Wall KLF-10; sets with these values: 2
Basic Wall:Generic - 300mm:1950525 | 2 Korrus | Walls | Pset_OpeningElementCommon - Reference: Curtain Wall KLF-06; sets with these values: 2
1.0 W - 2x2:-A-03:973951:1 | 2 Korrus
1.0 W - 2x2:-A-03:973950:1 | 2 Korrus
1.0 W - 2x2:-A-03:972694:1 | 1 Korrus A
1.0 W - 2x2:-A-03:972651:1 | 3 Korrus A
SMA_D01, 1-poolne:SU-P-11 - 1000x2100:1215646:1 | 1 Korrus
SMA_D01, 1-poolne:SU-P-04 - 750x2100:960009:1 | 1 Korrus A
SMA_D01, 1-poolne:SU-P-04 - 750x2100:960004:1 | 1 Korrus A
SMA_W1, 1-jaotus:-A-05_1200x1500mm:989701:1 | 3 korrus
SMA_W1, 1-jaotus:-A-05_1200x1500mm:956955:1 | 3 korrus
sma_W3:-A-01 2700x1500mm:989663:1 | 3 Korrus A
sma_W3:-A-01 2700x1500mm:989662:1 | 3 Korrus A
sma_W3:-A-01 2700x1500mm:989665:1 | 3 Korrus A
sma_W3:-A-01 2700x1500mm:989664:1 | 3 Korrus A
SMA_W1, 1-jaotus:-A-05_1200x1500mm:989881:1 | 3 korrus
SMA_W1, 1-jaotus:-A-05_1200x1500mm:989775:1 | 3 korrus
sma_W3:-A-01 2700x1500mm:954806:1 | 3 Korrus A
sma_W3:-A-01 2700x1500mm:954805:1 | 3 Korrus A
sma_W3:-A-01 2700x1500mm:954584:1 | 2 Korrus A
sma_W3:-A-01 2700x1500mm:954583:1 | 2 Korrus A
SMA_W1, 1-jaotus:-A-05_1200x1500mm:954582:1 | 2 Korrus
sma_W3:-A-01 2700x1500mm:954581:1 | 2 Korrus A
2 x Basic Wall:SS-00_Fibo 300mm:2293321 | 2 Korrus | Windows | Pset_OpeningElementCommon - Reference: -A-05_1200x1500mm; sets with these values: 2
2 x Basic Wall:Generic - 350mm:2293399 | 2 Korrus | Windows | Pset_OpeningElementCommon - Reference: -A-05_1200x1500mm; sets with these values: 2
sma_W3:-A-01 2700x1500mm:954580:1 | 2 Korrus A
sma_W3:-A-01 2700x1500mm:954579:1 | 2 Korrus A
sma_W3:-A-01 2700x1500mm:954578:1 | 2 Korrus A
1.0 W - 2x2:-A-03:955711:1 | 3 korrus
Basic Wall:SS-03_Kips, 66mm metallkarkass:2401643 | 0 Kelder | Doors | Pset_OpeningElementCommon - Reference: SU-M-04 - 1000x1800; sets with these values: 2
Basic Wall:SS-03_Kips, 66mm metallkarkass:2404598 | 0 Kelder | Doors | Pset_OpeningElementCommon - Reference: SU-M-04 - 1000x1800; sets with these values: 2
1.0 W - 2x2:-A-03:952578:1 | 3 korrus
SMA_D01, 1-poolne:SU-P-01 - 1200x2100 EI 1korrus:847671:1 | 1 Korrus A
SMA_D01, 1-poolne:SU-P-08 - 1200x2100 EI 1 korrus:847672:1 | 1 Korrus
SMA_D01, 1-poolne:SU-P-01 - 1200x2100 EI:999350:1 | 1 Korrus
SMA_D01, 1-poolne:SU-P-08 - 1200x2100 EI 1 korrus:1178971:1 | 0 Kelder
SMA_D01, 1-poolne:SU-P-01 - 1200x2100 EI 2 korrus:847740:1 | 2 Korrus
SMA_D01, 1-poolne:SU-P-01 - 1200x2100 EI 1korrus:847702:1 | 2 Korrus
SMA_D01, 1-poolne:SU-P-08 - 1200x2100 EI:847742:1 | 2 Korrus
SMA_D01, 1-poolne:SU-P-01 - 1200x2100 EI 3 korrus:847800:1 | 3 korrus
SMA_D01, 1-poolne:SU-P-08 - 1200x2100 EI 3 korrus:1098961:1 | 3 korrus
SMA_D01, 1-poolne:SU-P-01 - 1200x2100 EI 2 korrus:847743:1 | 3 korrus
SMA_D01, 1-poolne:SU-P-01 - 1200x2100 EI 3 korrus:847810:1 | 3 korrus
SMA_D01, 1-poolne:SU-P-08 - 1200x2100 EI 3 korrus:847811:1 | 3 korrus
sma_W3:-A-01 2700x1500mm:847629:1 | 1 Korrus A
1.0 W - 2x2:-A-03:972695:1 | 1 Korrus A
1.0 W - 2x2:-A-03:968525:1 | 2 Korrus A
1.0 W - 2x2:-A-03:968599:1 | 2 Korrus A
1.0 W - 2x2:-A-03:976033:1 | 1 Korrus A
1.0 W - 2x2:-A-03:989614:1 | 1 Korrus A
1.0 W - 2x2:-A-03:989631:1 | 2 Korrus A
1.0 W - 2x2:-A-03:989632:1 | 2 Korrus A
sma_W3:-A-01 2700x1500mm:847648:1 | 1 Korrus A
sma_W3:-A-01 2700x1500mm:847653:1 | 1 Korrus A
sma_W3:-A-01 2700x1500mm:847654:1 | 1 Korrus A
sma_W3:-A-01 2700x1500mm:847677:1 | 1 Korrus
SMA_W1, 1-jaotus:SA-05_1200x1500mm EI-30:847695:1 | 1 Korrus
sma_W3:-A-01 2700x1500mm:847707:1 | 1 Korrus A
SMA_D01, 1-poolne:SU-P-08 - 1200x2100 EI:847741:1 | 2 Korrus
sma_W3:-A-04 2500x1200mm:850305:1 | 0 Kelder
sma_W3:-A-04 2500x1200mm:850306:1 | 0 Kelder
sma_W3:-A-02 2000x1200mm:850463:1 | 0 Kelder
sma_W3:-A-04 2500x1200mm:850520:1 | 0 Kelder
sma_W3:-A-04 2500x1200mm:850612:1 | 0 Kelder
sma_W3:-A-02 2000x1200mm:850649:1 | 0 Kelder
sma_W3:-A-04 2500x1200mm:850698:1 | 0 Kelder
sma_W3:-A-04 2500x1200mm:850759:1 | 0 Kelder
sma_W3:-A-02 2000x1200mm:850808:1 | 0 Kelder
sma_W3:-A-02 2000x1200mm:850958:1 | 0 Kelder
SMA_W1, 1-jaotus:-A-05_1200x1500mm:852345:1 | 2 Korrus
SMA_W1, 1-jaotus:-A-05_1200x1500mm:852346:1 | 2 Korrus
SMA_D01, 1-poolne:SU-P-05- 900x2100:867016:1 | 1 Korrus
SMA_D01, 1-poolne:SU-P-05- 900x2100:996302:1 | 1 Korrus
SMA_D01, 1-poolne:SU-P-05- 900x2100:866225:1 | 1 Korrus
SMA_D01, 1-poolne:SU-P-05- 900x2100:866294:1 | 1 Korrus
SMA_D01, 1-poolne:SU-P-05- 900x2100:866961:1 | 1 Korrus
SMA_D01, 1-poolne:SU-P-09 - 1000x2100:886871:1 | 1 Korrus
SMA_D01, 1-poolne:SU-P-09 - 1000x2100:886870:1 | 1 Korrus
SMA_D01, 1-poolne:SU-P-10- 900x2100 1 korrus:887994:1 | 1 Korrus A
SMA_D01, 1-poolne:SU-P-10- 900x2100 1 korrus:887995:1 | 1 Korrus A
SMA_D01, 1-poolne:SU-P-10- 900x2100 1 korrus:888111:1 | 1 Korrus A
SMA_D01, 1-poolne:SU-P-10- 900x2100 1 korrus:888112:1 | 1 Korrus A
SMA_D01, 1-poolne:SU-P-07 - 1000x2100 1 korrus:895916:1 | 1 Korrus A
SMA_D01, 1-poolne:SU-P-07 - 1000x2100 1 korrus:1082451:1 | 1 Korrus A
SMA_D01, 1-poolne:SU-P-07 - 1000x2100 1 korrus:896119:1 | 1 Korrus A
SMA_D01, 1-poolne:SU-P-07 - 1000x2100 1 korrus:1018835:1 | 1 Korrus A
SMA_D01, 1-poolne:SU-P-10- 900x2100 1 korrus:889265:1 | 1 Korrus A
SMA_D01, 1-poolne:SU-P-10- 900x2100 1 korrus:889334:1 | 1 Korrus A
SMA_D01, 1-poolne:SU-P-10- 900x2100 1 korrus:889365:1 | 1 Korrus A
SMA_D01, 1-poolne:SU-P-10- 900x2100 1 korrus:889426:1 | 1 Korrus A
SMA_D01, 1-poolne:SU-P-04 - 750x2100:895705:1 | 1 Korrus A
SMA_D01, 1-poolne:SU-P-04 - 750x2100:895776:1 | 1 Korrus A
SMA_D01, 1-poolne:SU-P-08 - 1200x2100 EI 1 korrus:895798:1 | 1 Korrus A
SMA_D01, 1-poolne:SU-P-07 - 1000x2100 1 korrus:896288:1 | 1 Korrus A
SMA_D01, 1-poolne:SU-P-10- 900x2100 1 korrus:897309:1 | 1 Korrus A
SMA_D01, 1-poolne:SU-P-10- 900x2100 1 korrus:897379:1 | 1 Korrus A
SMA_D01, 1-poolne:SU-P-10- 900x2100 2 korrus:911990:1 | 2 Korrus A
SMA_D01, 1-poolne:SU-P-10- 900x2100 2 korrus:911991:1 | 2 Korrus A
SMA_D01, 1-poolne:SU-P-10- 900x2100 2 korrus:911993:1 | 2 Korrus A
SMA_D01, 1-poolne:SU-P-10- 900x2100 2 korrus:911994:1 | 2 Korrus A
SMA_D01, 1-poolne:SU-P-07 - 1000x2100 2korrus:912023:1 | 2 Korrus A
SMA_D01, 1-poolne:SU-P-07 - 1000x2100 2korrus:985903:1 | 2 Korrus A
SMA_D01, 1-poolne:SU-P-10- 900x2100 2 korrus:912001:1 | 2 Korrus A
SMA_D01, 1-poolne:SU-P-10- 900x2100 2 korrus:912002:1 | 2 Korrus A
SMA_D01, 1-poolne:SU-P-10- 900x2100 2 korrus:912003:1 | 2 Korrus A
SMA_D01, 1-poolne:SU-P-10- 900x2100 2 korrus:912004:1 | 2 Korrus A
SMA_D01, 1-poolne:SU-P-04 - 750x2100:912008:1 | 2 Korrus A
SMA_D01, 1-poolne:SU-P-04 - 750x2100:912007:1 | 2 Korrus A
SMA_D01, 1-poolne:SU-P-04 - 750x2100:912014:1 | 2 Korrus A
SMA_D01, 1-poolne:SU-P-04 - 750x2100:912013:1 | 2 Korrus A
SMA_D01, 1-poolne:SU-P-04 - 750x2100:912018:1 | 2 Korrus A
SMA_D01, 1-poolne:SU-P-07 - 1000x2100 2korrus:912022:1 | 2 Korrus A
SMA_D01, 1-poolne:SU-P-07 - 1000x2100 2korrus:912024:1 | 2 Korrus A
SMA_D01, 1-poolne:SU-P-10- 900x2100 2 korrus:912025:1 | 2 Korrus A
SMA_D01, 1-poolne:SU-P-10- 900x2100 2 korrus:912026:1 | 2 Korrus A
SMA_D01, 1-poolne:SU-P-10- 900x2100 2 korrus:912476:1 | 2 Korrus
SMA_D01, 1-poolne:SU-P-10- 900x2100 2 korrus:912479:1 | 2 Korrus
SMA_D01, 1-poolne:SU-P-10- 900x2100 2 korrus:912477:1 | 2 Korrus
SMA_D01, 1-poolne:SU-P-10- 900x2100 2 korrus:912478:1 | 2 Korrus
SMA_D01, 1-poolne:SU-P-10- 900x2100 2 korrus:912488:1 | 2 Korrus
SMA_D01, 1-poolne:SU-P-10- 900x2100 2 korrus:918217:1 | 2 Korrus
SMA_D01, 1-poolne:SU-P-10- 900x2100 2 korrus:912489:1 | 2 Korrus
SMA_D01, 1-poolne:SU-P-10- 900x2100 2 korrus:912490:1 | 2 Korrus
SMA_D01, 1-poolne:SU-P-04 - 750x2100:919247:1 | 2 Korrus A
SMA_D01, 1-poolne:SU-P-04 - 750x2100:919288:1 | 2 Korrus A
SMA_D01, 1-poolne:SU-P-07 - 1000x2100 2korrus:926904:1 | 2 Korrus A
SMA_D01, 1-poolne:SU-P-04 - 750x2100:1209232:1 | 2 Korrus A
SMA_D01, 1-poolne:SU-P-04 - 750x2100:928278:1 | 2 Korrus A
SMA_D01, 1-poolne:SU-P-04 - 750x2100:928481:1 | 2 Korrus A
sma_W3:-A-01 2700x1500mm:936873:1 | 1 Korrus A
sma_W3:-A-01 2700x1500mm:952186:1 | 1 Korrus
sma_W3:-A-06 2000x1500mm:949195:1 | 1 Korrus
sma_W3:-A-06 2000x1500mm:955677:1 | 1 Korrus
1.0 W - 2x2:-A-03:955709:1 | 1 Korrus
1.0 W - 2x2:-A-03:973901:1 | 1 Korrus
sma_W3:-A-01 2700x1500mm:945228:1 | 2 Korrus
sma_W3:-A-01 2700x1500mm:945229:1 | 2 Korrus
sma_W3:-A-01 2700x1500mm:945273:1 | 3 korrus
sma_W3:-A-01 2700x1500mm:945274:1 | 3 korrus
1.0 W - 2x2:-A-03:952567:1 | 2 Korrus

# IfcPlate: System Panel:Glazed (39)
Type - PredefinedType: CURTAIN_PANEL; Material: Glass
Type - Pset_PlateCommon - IsExternal: no; Reference: Glazed; ThermalTransmittance: 6.7069 kg/K/s3
Type - Pset_ProductRequirements - Category: Curtain Panels
Type - Pset_QuantityTakeOff - Reference: Glazed
Pset_PlateCommon - IsExternal: yes
Name (System Panel:Glazed:...) | In
858534 | 1 Korrus
1591489 | 1 Korrus
858925 | 1 Korrus
859012 | 1 Korrus
1230825 | 1 Korrus
859018 | 1 Korrus
859163 | 2 Korrus
1040568 | 2 Korrus
1040141 | 2 Korrus
1040092 | 2 Korrus
1040415 | 2 Korrus
1588028 | 2 Korrus
1587968 | 2 Korrus
906292 | 1 Korrus
906457 | 1 Korrus
1177906 | 1 Korrus
1587318 | 2 Korrus
1587376 | 2 Korrus
978328 | 1 Korrus
1171882 | 1 Korrus
1049649 | 2 Korrus
1049670 | 2 Korrus
1049660 | 2 Korrus
1049655 | 2 Korrus
1049665 | 2 Korrus
1051207 | 2 Korrus
1051228 | 2 Korrus
1051218 | 2 Korrus
1051213 | 2 Korrus
1051223 | 2 Korrus
1051233 | 2 Korrus
1051254 | 2 Korrus
1051244 | 2 Korrus
1051239 | 2 Korrus
1051249 | 2 Korrus
1171983 | 1 Korrus
1520733 | 1 Korrus
1177058 | 1 Korrus
1234897 | 1 Korrus

# IfcPlate: System Panel:Solid (6)
Type - PredefinedType: CURTAIN_PANEL; Material: Default
Type - Pset_PlateCommon - IsExternal: no; Reference: Solid; ThermalTransmittance: 3.7021 kg/K/s3
Type - Pset_ProductRequirements - Category: Curtain Panels
Type - Pset_QuantityTakeOff - Reference: Solid
Pset_PlateCommon - IsExternal: yes
Name (System Panel:Solid:...) | In
1577352 | 1 Korrus
1588693 | 1 Korrus
1040267 | 2 Korrus
1040325 | 2 Korrus
1038995 | 2 Korrus
1038879 | 2 Korrus

# IfcRailing: Railing:1000mm_sisearh railing offsetiga 2 (4)
Material: Metal - Stainless Steel,Polished
Pset_ProductRequirements - Category: Railings
Pset_QuantityTakeOff - Reference: 1000mm_sisearh railing offsetiga 2
Pset_RailingCommon - IsExternal: no; Reference: 1000mm_sisearh railing offsetiga 2; Height: 900 mm
Name (Railing:1000mm_sisearh railing offsetiga 2:...) | In
2188527 | 1 Korrus A
2188617 | 1 Korrus A
2206030 | 1 Korrus
2262904 | 1 Korrus A

# IfcRailing: Railing:Piire 1 (4)
Material: Wood - Maple
Pset_ProductRequirements - Category: Railings
Pset_QuantityTakeOff - Reference: Piire 1
Pset_RailingCommon - IsExternal: no; Reference: Piire 1; Height: 1219.2 mm
Name (Railing:Piire 1:...) | In
1326300 | 3 Korrus A
1793159 | 1 Korrus A
1793635 | 2 Korrus
1817628 | 3 korrus

# IfcRailing: Railing:Piire 5 (4)
Material: Wood - Maple
Pset_ProductRequirements - Category: Railings
Pset_QuantityTakeOff - Reference: Piire 5
Pset_RailingCommon - IsExternal: no; Reference: Piire 5; Height: 1219.2 mm
Name (Railing:Piire 5:...) | In
1793560 | 1 Korrus A
1793582 | 1 Korrus A
1793593 | 2 Korrus A
1793604 | 0 Kelder

# IfcRailing: Railing:Piire 7 (20)
Material: Wood - Maple
Pset_ProductRequirements - Category: Railings
Pset_QuantityTakeOff - Reference: Piire 7
Pset_RailingCommon - IsExternal: no; Reference: Piire 7; Height: 1219.2 mm
Name (Railing:Piire 7:...) | In
1753787 | 2 Korrus A
1753831 | 2 Korrus
1753851 | 3 korrus
1753869 | 1 Korrus A
1753887 | 1 Korrus
1753912 | 0 Kelder
1787192 | 2 Korrus A
1787206 | 3 korrus
1787213 | 1 Korrus A
1787220 | 2 Korrus
1787227 | 0 Kelder
1793413 | 2 Korrus A
1793447 | 1 Korrus A
1793514 | 2 Korrus A
1793571 | 2 Korrus A
2227050 | 2 Korrus
2228127 | 3 korrus
2228384 | 3 Korrus A
2304120 | 0 Kelder
2320471 | 1 Korrus

# IfcRailing: Railing:Wall Handrail 700mm (3)
In: 1 Korrus A
Material: Metal - Steel
Pset_ProductRequirements - Category: Railings
Pset_QuantityTakeOff - Reference: Wall Handrail 700mm
Pset_RailingCommon - IsExternal: no; Reference: Wall Handrail 700mm; Height: 1219.2 mm
Name (Railing:Wall Handrail 700mm:...)
2195243
2195454
2263188

# IfcRailing: Railing:Wall Handrail 700mm 2, Railing:Wall Handrail 700mm 2:2206449
In: 1 Korrus
Material: Metal - Steel
Pset_ProductRequirements - Category: Railings
Pset_QuantityTakeOff - Reference: Wall Handrail 700mm 2
Pset_RailingCommon - IsExternal: no; Reference: Wall Handrail 700mm 2; Height: 1219.2 mm

# IfcRailing: Railing:Wall Handrail 900mm (3)
In: 1 Korrus A
Material: Metal - Steel
Pset_ProductRequirements - Category: Railings
Pset_QuantityTakeOff - Reference: Wall Handrail 900mm
Pset_RailingCommon - IsExternal: no; Reference: Wall Handrail 900mm; Height: 1219.2 mm
Name (Railing:Wall Handrail 900mm:...)
2195327
2195555
2263196

# IfcRailing: Railing:Wall Handrail 900mm 2, Railing:Wall Handrail 900mm 2:2206581
In: 1 Korrus
Material: Metal - Steel
Pset_ProductRequirements - Category: Railings
Pset_QuantityTakeOff - Reference: Wall Handrail 900mm 2
Pset_RailingCommon - IsExternal: no; Reference: Wall Handrail 900mm 2; Height: 1219.2 mm

# IfcRoof: Basic Roof:KL-00_R/B katus 500mm (3)
Material: EST. Katusekate. Rullmaterjal. PVC 5 mm, EST. Soojustus. Mineraalvill. Tuulutussoontega villaplaat. Default 30 mm, EST. Soojustus. EPS. Default 150 mm, EST. Soojustus. EPS. Default 150 mm, __Olemasolev konstruktsioon 220 mm
Pset_ElementShading - Roughness: 914.4 mm
Pset_ProductRequirements - Category: Roofs
Pset_QuantityTakeOff - Reference: KL-00_R/B katus 500mm
Pset_RoofCommon - IsExternal: yes; Reference: KL-00_R/B katus 500mm
Name (Basic Roof:KL-00_R/B katus 500mm:...) | In | ProjectedArea (m2) | TotalArea (m2)
847735 | Katus | 89.1399 | 89.2248
848130 | Katus | 91.0375 | 91.1242
849111 | Katus A | 303.129 | 299.751

# IfcSlab: Basic Roof:KL-00_R/B katus 500mm (2)
In: Katus
Type - PredefinedType: ROOF
Type - Pset_ElementShading - Roughness: 914.4 mm
Type - Pset_ProductRequirements - Category: Roofs
Type - Pset_QuantityTakeOff - Reference: KL-00_R/B katus 500mm
Type - Pset_ReinforcementBarPitchOfSlab - Reference: KL-00_R/B katus 500mm
Type - Pset_SlabCommon - IsExternal: yes; Reference: KL-00_R/B katus 500mm
Material: EST. Katusekate. Rullmaterjal. PVC
Pset_QuantityTakeOff - sets with these values: 2
Pset_SlabCommon - PitchAngle: 2.50159 deg
Name (Basic Roof:KL-00_R/B katus 500mm:...)
847735
848130

# IfcSlab: Floor:KL-03_Tuulekoja katuslagi (2)
In: 2 Korrus
Type - PredefinedType: FLOOR; Material: EST. Soojustus. Mineraalvill. Default 100 mm, EST. Ehitusplaat. Kipsplaat. Tulekindel 15 mm, EST. Ehitusplaat. Kipsplaat. Tulekindel 15 mm
Type - Pset_ElementShading - Roughness: 914.4 mm
Type - Pset_ProductRequirements - Category: Floors
Type - Pset_QuantityTakeOff - Reference: KL-03_Tuulekoja katuslagi
Type - Pset_ReinforcementBarPitchOfSlab - Reference: KL-03_Tuulekoja katuslagi
Type - Pset_SlabCommon - IsExternal: no; Reference: KL-03_Tuulekoja katuslagi
Pset_QuantityTakeOff - sets with these values: 2
Pset_SlabCommon - LoadBearing: no; PitchAngle: 0 deg
Name (Floor:KL-03_Tuulekoja katuslagi:...)
1595997
1641521

# IfcSlab: Floor:KL-03_Tuulekoja katuslagi alus (2)
In: 2 Korrus
Type - PredefinedType: FLOOR; Material: EST. Katusekate. Rullmaterjal. SBS 2 mm, EST. Tuuletõke. Kipsplaat 30 mm, EST. Ehitusplaat. Vineer 18 mm, EST. Õhkvahe. Default 190 mm
Type - Pset_ElementShading - Roughness: 914.4 mm
Type - Pset_ProductRequirements - Category: Floors
Type - Pset_QuantityTakeOff - Reference: KL-03_Tuulekoja katuslagi alus
Type - Pset_ReinforcementBarPitchOfSlab - Reference: KL-03_Tuulekoja katuslagi alus
Type - Pset_SlabCommon - IsExternal: no; Reference: KL-03_Tuulekoja katuslagi alus
Pset_QuantityTakeOff - sets with these values: 2
Pset_SlabCommon - LoadBearing: no; PitchAngle: 0 deg
Name (Floor:KL-03_Tuulekoja katuslagi alus:...)
852618
1039942

# IfcSlab: Floor:KL-03_Tuulekoja katuslagi väljast (2)
In: 2 Korrus
Pset_ElementShading - Roughness: 914.4 mm
Pset_ProductRequirements - Category: Floors
Pset_QuantityTakeOff - Reference: KL-03_Tuulekoja katuslagi väljast; sets with these values: 2
Pset_SlabCommon - IsExternal: no; LoadBearing: no; PitchAngle: 0 deg; Reference: KL-03_Tuulekoja katuslagi väljast
Name (Floor:KL-03_Tuulekoja katuslagi väljast:...)
1595932
1639378

# IfcSlab: Floor:KL-03_Tuulekoja katuslagi väljast (5)
In: 2 Korrus
Type - PredefinedType: ROOF
Type - Pset_ElementShading - Roughness: 914.4 mm
Type - Pset_ProductRequirements - Category: Floors
Type - Pset_QuantityTakeOff - Reference: KL-03_Tuulekoja katuslagi väljast
Type - Pset_ReinforcementBarPitchOfSlab - Reference: KL-03_Tuulekoja katuslagi väljast
Type - Pset_SlabCommon - IsExternal: no; Reference: KL-03_Tuulekoja katuslagi väljast
Material: EST. Õhkvahe. Roov. Fassaadikatte alusroov. Vertikaalne
Pset_QuantityTakeOff - sets with these values: 2
Pset_SlabCommon - LoadBearing: no
Name (Floor:KL-03_Tuulekoja katuslagi väljast:...) | PitchAngle (deg)
1595932 | 0.849185
1595932 | 0.80844
1595932 | 0.804098
1639378 | 0.75368
1639378 | 0.681902

# IfcSlab: Floor:Metallrestpõrand (4)
Type - PredefinedType: FLOOR; Material: __metallrest 20 mm
Type - Pset_ElementShading - Roughness: 304.8 mm
Type - Pset_ProductRequirements - Category: Floors
Type - Pset_QuantityTakeOff - Reference: Metallrestpõrand
Type - Pset_ReinforcementBarPitchOfSlab - Reference: Metallrestpõrand
Type - Pset_SlabCommon - IsExternal: no; Reference: Metallrestpõrand
Pset_QuantityTakeOff - sets with these values: 2
Pset_SlabCommon - LoadBearing: no; PitchAngle: 0 deg
Name (Floor:Metallrestpõrand:...) | In
1177977:2 | 1 Korrus
1191288:2 | 1 Korrus
1375720 | 2 Korrus A
1691766 | 2 Korrus A

# IfcSlab: Floor:Metallrestpõrand (2)
In: 1 Korrus
Type - PredefinedType: FLOOR
Type - Pset_ElementShading - Roughness: 304.8 mm
Type - Pset_ProductRequirements - Category: Floors
Type - Pset_QuantityTakeOff - Reference: Metallrestpõrand
Type - Pset_ReinforcementBarPitchOfSlab - Reference: Metallrestpõrand
Type - Pset_SlabCommon - IsExternal: no; Reference: Metallrestpõrand
Material: __metallrest 20 mm
Pset_QuantityTakeOff - sets with these values: 2
Pset_SlabCommon - LoadBearing: no; PitchAngle: 0 deg
Name (Floor:Metallrestpõrand:...)
1177977
1191288

# IfcSlab: Floor:P-00_Põrand pinnasel 400mm (2)
Type - PredefinedType: FLOOR; Material: EST. Betoon. Armeeritud. Kohtvalu 100 mm, EST. Soojustus. EPS. Default 200 mm
Type - Pset_ElementShading - Roughness: 914.4 mm
Type - Pset_ProductRequirements - Category: Floors
Type - Pset_QuantityTakeOff - Reference: P-00_Põrand pinnasel 400mm
Type - Pset_ReinforcementBarPitchOfSlab - Reference: P-00_Põrand pinnasel 400mm
Type - Pset_SlabCommon - IsExternal: no; Reference: P-00_Põrand pinnasel 400mm
Pset_QuantityTakeOff - sets with these values: 2
Pset_SlabCommon - LoadBearing: no; PitchAngle: 0 deg
Name (Floor:P-00_Põrand pinnasel 400mm:...) | In
847299 | 0 Kelder
847589:2 | 1 Korrus

# IfcSlab: Floor:P-00_Põrand pinnasel 400mm, Floor:P-00_Põrand pinnasel 400mm:847589
In: 1 Korrus
Type - PredefinedType: FLOOR
Type - Pset_ElementShading - Roughness: 914.4 mm
Type - Pset_ProductRequirements - Category: Floors
Type - Pset_QuantityTakeOff - Reference: P-00_Põrand pinnasel 400mm
Type - Pset_ReinforcementBarPitchOfSlab - Reference: P-00_Põrand pinnasel 400mm
Type - Pset_SlabCommon - IsExternal: no; Reference: P-00_Põrand pinnasel 400mm
Material: EST. Betoon. Armeeritud. Kohtvalu 100 mm, EST. Soojustus. EPS. Default 200 mm
Pset_QuantityTakeOff - sets with these values: 2
Pset_SlabCommon - LoadBearing: no; PitchAngle: 0 deg

# IfcSlab: Floor:VL-00_R/B 300mm 2 (6)
Type - PredefinedType: FLOOR; Material: EST. Betoon. Armeeritud. Kohtvalu 60 mm, EST. Soojustus. Mineraalvill. Default 20 mm, EST. Betoon. Armeeritud. Monteeritav(1) 220 mm
Type - Pset_ElementShading - Roughness: 914.4 mm
Type - Pset_ProductRequirements - Category: Floors
Type - Pset_QuantityTakeOff - Reference: VL-00_R/B 300mm 2
Type - Pset_ReinforcementBarPitchOfSlab - Reference: VL-00_R/B 300mm 2
Type - Pset_SlabCommon - IsExternal: no; Reference: VL-00_R/B 300mm 2
Pset_QuantityTakeOff - sets with these values: 2
Pset_SlabCommon - LoadBearing: no; PitchAngle: 0 deg
Name (Floor:VL-00_R/B 300mm 2:...) | In
847557 | 1 Korrus A
847578 | 3 Korrus A
847600:2 | 3 korrus
847611:2 | 2 Korrus
1234192 | 0 Kelder
1591434 | 2 Korrus A

# IfcSlab: Floor:VL-00_R/B 300mm 2 (2)
Type - PredefinedType: FLOOR
Type - Pset_ElementShading - Roughness: 914.4 mm
Type - Pset_ProductRequirements - Category: Floors
Type - Pset_QuantityTakeOff - Reference: VL-00_R/B 300mm 2
Type - Pset_ReinforcementBarPitchOfSlab - Reference: VL-00_R/B 300mm 2
Type - Pset_SlabCommon - IsExternal: no; Reference: VL-00_R/B 300mm 2
Material: EST. Betoon. Armeeritud. Kohtvalu 60 mm, EST. Soojustus. Mineraalvill. Default 20 mm, EST. Betoon. Armeeritud. Monteeritav(1) 220 mm
Pset_QuantityTakeOff - sets with these values: 2
Pset_SlabCommon - LoadBearing: no; PitchAngle: 0 deg
Name (Floor:VL-00_R/B 300mm 2:...) | In
847600 | 3 korrus
847611 | 2 Korrus

# IfcSlab: Floor:VL-02, Floor:VL-02:972902:5
In: 1 Korrus A
Type - PredefinedType: FLOOR; Material: EST. Soojustus. Mineraalvill. Default 200 mm
Type - Pset_ElementShading - Roughness: 914.4 mm
Type - Pset_ProductRequirements - Category: Floors
Type - Pset_QuantityTakeOff - Reference: VL-02
Type - Pset_ReinforcementBarPitchOfSlab - Reference: VL-02
Type - Pset_SlabCommon - IsExternal: no; Reference: VL-02
Pset_QuantityTakeOff - sets with these values: 2
Pset_SlabCommon - LoadBearing: no; PitchAngle: 0 deg

# IfcSlab: Floor:VL-02 (4)
In: 1 Korrus A
Type - PredefinedType: FLOOR
Type - Pset_ElementShading - Roughness: 914.4 mm
Type - Pset_ProductRequirements - Category: Floors
Type - Pset_QuantityTakeOff - Reference: VL-02
Type - Pset_ReinforcementBarPitchOfSlab - Reference: VL-02
Type - Pset_SlabCommon - IsExternal: no; Reference: VL-02
Material: EST. Soojustus. Mineraalvill. Default 200 mm
Pset_QuantityTakeOff - sets with these values: 2
Pset_SlabCommon - LoadBearing: no; PitchAngle: 0 deg
Name (Floor:VL-02:...)
972902
972902:2
972902:3
972902:4

# IfcSlab: Floor:_põrand toad orgaaniline (2)
Type - PredefinedType: FLOOR; Material: _põrand orgaaniline kate 20 mm
Type - Pset_ElementShading - Roughness: 304.8 mm
Type - Pset_ProductRequirements - Category: Floors
Type - Pset_QuantityTakeOff - Reference: _põrand toad orgaaniline
Type - Pset_ReinforcementBarPitchOfSlab - Reference: _põrand toad orgaaniline
Type - Pset_SlabCommon - IsExternal: no; Reference: _põrand toad orgaaniline
Pset_QuantityTakeOff - sets with these values: 2
Pset_SlabCommon - LoadBearing: no; PitchAngle: 0 deg
Name (Floor:_põrand toad orgaaniline:...) | In
1406268:2 | 2 Korrus A
1446859:4 | 3 korrus

# IfcSlab: Floor:_põrand toad orgaaniline (4)
Type - PredefinedType: FLOOR
Type - Pset_ElementShading - Roughness: 304.8 mm
Type - Pset_ProductRequirements - Category: Floors
Type - Pset_QuantityTakeOff - Reference: _põrand toad orgaaniline
Type - Pset_ReinforcementBarPitchOfSlab - Reference: _põrand toad orgaaniline
Type - Pset_SlabCommon - IsExternal: no; Reference: _põrand toad orgaaniline
Material: _põrand orgaaniline kate 20 mm
Pset_QuantityTakeOff - sets with these values: 2
Pset_SlabCommon - LoadBearing: no; PitchAngle: 0 deg
Name (Floor:_põrand toad orgaaniline:...) | In
1406268 | 2 Korrus A
1446859 | 3 korrus
1446859:2 | 3 korrus
1446859:3 | 3 korrus

# IfcSlab: Floor:_põrandaplaat puit (3)
Type - PredefinedType: FLOOR; Material: _põrandaplaat 150x900 20 mm
Type - Pset_ElementShading - Roughness: 304.8 mm
Type - Pset_ProductRequirements - Category: Floors
Type - Pset_QuantityTakeOff - Reference: _põrandaplaat puit
Type - Pset_ReinforcementBarPitchOfSlab - Reference: _põrandaplaat puit
Type - Pset_SlabCommon - IsExternal: no; Reference: _põrandaplaat puit
Pset_QuantityTakeOff - sets with these values: 2
Pset_SlabCommon - LoadBearing: no; PitchAngle: 0 deg
Name (Floor:_põrandaplaat puit:...) | In
1377295 | 2 Korrus A
1446747 | 3 korrus
1488515 | 2 Korrus A

# IfcSlab: Floor:_põrandaplaat väike 10x10, Floor:_põrandaplaat väike 10x10:1377373
In: 2 Korrus A
Type - PredefinedType: FLOOR; Material: _põrandaplaat 100x100 20 mm
Type - Pset_ElementShading - Roughness: 304.8 mm
Type - Pset_ProductRequirements - Category: Floors
Type - Pset_QuantityTakeOff - Reference: _põrandaplaat väike 10x10
Type - Pset_ReinforcementBarPitchOfSlab - Reference: _põrandaplaat väike 10x10
Type - Pset_SlabCommon - IsExternal: no; Reference: _põrandaplaat väike 10x10
Pset_QuantityTakeOff - sets with these values: 2
Pset_SlabCommon - LoadBearing: no; PitchAngle: 0 deg

# IfcSlab: Floor:_ramp, Floor:_ramp:2179813
In: 1 Korrus A
Pset_ElementShading - Roughness: 304.8 mm
Pset_ProductRequirements - Category: Floors
Pset_QuantityTakeOff - Reference: _ramp; sets with these values: 2
Pset_SlabCommon - IsExternal: no; LoadBearing: no; PitchAngle: 0 deg; Reference: _ramp

# IfcSlab: Floor:_ramp (4)
In: 1 Korrus A
Type - PredefinedType: ROOF
Type - Pset_ElementShading - Roughness: 304.8 mm
Type - Pset_ProductRequirements - Category: Floors
Type - Pset_QuantityTakeOff - Reference: _ramp
Type - Pset_ReinforcementBarPitchOfSlab - Reference: _ramp
Type - Pset_SlabCommon - IsExternal: no; Reference: _ramp
Material: EST. Metall. Teras. Tsingitud
Pset_QuantityTakeOff - sets with these values: 2
Pset_SlabCommon - LoadBearing: no
Name (Floor:_ramp:...) | PitchAngle (deg)
2179813 | 3.7133
2 x 2179813 | 0
2179813 | 3.6211

# IfcSlab: Monolithic Landing:300 mm Thickness (2)
In: 1 Korrus
Type - PredefinedType: LANDING
Type - Pset_ProductRequirements - Category: Landings
Type - Pset_QuantityTakeOff - Reference: 300 mm Thickness
Type - Pset_ReinforcementBarPitchOfSlab - Reference: 300 mm Thickness
Type - Pset_SlabCommon - IsExternal: no; Reference: 300 mm Thickness
Material: Concrete, Cast In Situ
Pset_QuantityTakeOff - sets with these values: 2
Pset_SlabCommon - PitchAngle: 0 deg
Name (Cast-In-Place Stair:Stair:...)
853708 Landing 1
978363 Landing 1

# IfcSlab: Pad:Kergkruus, Pad:Kergkruus:1025636
In: 0 Kelder
Type - PredefinedType: FLOOR; Material: EST. Puistematerjal. Kergkruus 200 mm
Type - Pset_ElementShading - Roughness: 304.8 mm
Type - Pset_ProductRequirements - Category: Pads
Type - Pset_QuantityTakeOff - Reference: Kergkruus
Type - Pset_ReinforcementBarPitchOfSlab - Reference: Kergkruus
Type - Pset_SlabCommon - IsExternal: no; Reference: Kergkruus
Pset_QuantityTakeOff - sets with these values: 2
Pset_SlabCommon - PitchAngle: 0 deg

# IfcStair: Cast-In-Place Stair:Cast-In-Place Stair (2)
In: 1 Korrus
ShapeType: STRAIGHT_RUN_STAIR
Pset_ProductRequirements - Category: Stairs
Pset_QuantityTakeOff - Reference: Cast-In-Place Stair
Pset_StairCommon - IsExternal: no; Reference: Cast-In-Place Stair; TreadLength: 300 mm
Name (Cast-In-Place Stair:Stair:...) | NumberOfRiser | NumberOfTreads | RiserHeight (mm)
853708 | 4 | 3 | 125
978363 | 3 | 2 | 146.667

# IfcStair: Stair:7" max riser 11" tread (24)
Name (Stair:7" max riser 11" tread:...) | In
1676077 | 1 Korrus | Material: __Olemasolev konstruktsioon
1676077 | 1 Korrus | Classification: C2010 Stair Construction (Uniformat); Pset_ProductRequirements - Category: Stairs; Pset_QuantityTakeOff - Reference: 7" max riser 11" tread; Pset_StairCommon - IsExternal: no; Reference: 7" max riser 11" tread; NumberOfRiser: 9; NumberOfTreads: 8; RiserHeight: 155.556 mm; TreadLength: 279.4 mm
1750332 | 2 Korrus | Material: __Olemasolev konstruktsioon
1750332 | 2 Korrus | Classification: C2010 Stair Construction (Uniformat); Pset_ProductRequirements - Category: Stairs; Pset_QuantityTakeOff - Reference: 7" max riser 11" tread; Pset_StairCommon - IsExternal: no; Reference: 7" max riser 11" tread; NumberOfRiser: 9; NumberOfTreads: 8; RiserHeight: 155.556 mm; TreadLength: 279.4 mm
1750422 | 3 korrus | Material: __Olemasolev konstruktsioon
1750422 | 3 korrus | Classification: C2010 Stair Construction (Uniformat); Pset_ProductRequirements - Category: Stairs; Pset_QuantityTakeOff - Reference: 7" max riser 11" tread; Pset_StairCommon - IsExternal: no; Reference: 7" max riser 11" tread; NumberOfRiser: 9; NumberOfTreads: 8; RiserHeight: 155.556 mm; TreadLength: 279.4 mm
1750495 | 1 Korrus A | Material: __Olemasolev konstruktsioon
1750495 | 1 Korrus A | Classification: C2010 Stair Construction (Uniformat); Pset_ProductRequirements - Category: Stairs; Pset_QuantityTakeOff - Reference: 7" max riser 11" tread; Pset_StairCommon - IsExternal: no; Reference: 7" max riser 11" tread; NumberOfRiser: 9; NumberOfTreads: 8; RiserHeight: 155.556 mm; TreadLength: 279.4 mm
1750582 | 2 Korrus A | Material: __Olemasolev konstruktsioon
1750582 | 2 Korrus A | Classification: C2010 Stair Construction (Uniformat); Pset_ProductRequirements - Category: Stairs; Pset_QuantityTakeOff - Reference: 7" max riser 11" tread; Pset_StairCommon - IsExternal: no; Reference: 7" max riser 11" tread; NumberOfRiser: 9; NumberOfTreads: 8; RiserHeight: 162.222 mm; TreadLength: 279.4 mm
1750653 | 0 Kelder | Material: __Olemasolev konstruktsioon
1750653 | 0 Kelder | Classification: C2010 Stair Construction (Uniformat); Pset_ProductRequirements - Category: Stairs; Pset_QuantityTakeOff - Reference: 7" max riser 11" tread; Pset_StairCommon - IsExternal: no; Reference: 7" max riser 11" tread; NumberOfRiser: 9; NumberOfTreads: 8; RiserHeight: 161.111 mm; TreadLength: 279.4 mm
1786673 | 1 Korrus | Material: __Olemasolev konstruktsioon
1786673 | 1 Korrus | Classification: C2010 Stair Construction (Uniformat); Pset_ProductRequirements - Category: Stairs; Pset_QuantityTakeOff - Reference: 7" max riser 11" tread; Pset_StairCommon - IsExternal: no; Reference: 7" max riser 11" tread; NumberOfRiser: 9; NumberOfTreads: 8; RiserHeight: 155.556 mm; TreadLength: 279.4 mm
1786714 | 2 Korrus | Material: __Olemasolev konstruktsioon
1786714 | 2 Korrus | Classification: C2010 Stair Construction (Uniformat); Pset_ProductRequirements - Category: Stairs; Pset_QuantityTakeOff - Reference: 7" max riser 11" tread; Pset_StairCommon - IsExternal: no; Reference: 7" max riser 11" tread; NumberOfRiser: 9; NumberOfTreads: 8; RiserHeight: 155.556 mm; TreadLength: 279.4 mm
1786742 | 3 korrus | Material: __Olemasolev konstruktsioon
1786742 | 3 korrus | Classification: C2010 Stair Construction (Uniformat); Pset_ProductRequirements - Category: Stairs; Pset_QuantityTakeOff - Reference: 7" max riser 11" tread; Pset_StairCommon - IsExternal: no; Reference: 7" max riser 11" tread; NumberOfRiser: 9; NumberOfTreads: 8; RiserHeight: 155.556 mm; TreadLength: 279.4 mm
1786770 | 1 Korrus A | Material: __Olemasolev konstruktsioon
1786770 | 1 Korrus A | Classification: C2010 Stair Construction (Uniformat); Pset_ProductRequirements - Category: Stairs; Pset_QuantityTakeOff - Reference: 7" max riser 11" tread; Pset_StairCommon - IsExternal: no; Reference: 7" max riser 11" tread; NumberOfRiser: 9; NumberOfTreads: 8; RiserHeight: 158.889 mm; TreadLength: 279.4 mm
1786798 | 2 Korrus A | Material: __Olemasolev konstruktsioon
1786798 | 2 Korrus A | Classification: C2010 Stair Construction (Uniformat); Pset_ProductRequirements - Category: Stairs; Pset_QuantityTakeOff - Reference: 7" max riser 11" tread; Pset_StairCommon - IsExternal: no; Reference: 7" max riser 11" tread; NumberOfRiser: 9; NumberOfTreads: 8; RiserHeight: 162.222 mm; TreadLength: 279.4 mm
1786826 | 0 Kelder | Material: __Olemasolev konstruktsioon
1786826 | 0 Kelder | Classification: C2010 Stair Construction (Uniformat); Pset_ProductRequirements - Category: Stairs; Pset_QuantityTakeOff - Reference: 7" max riser 11" tread; Pset_StairCommon - IsExternal: no; Reference: 7" max riser 11" tread; NumberOfRiser: 9; NumberOfTreads: 8; RiserHeight: 158.889 mm; TreadLength: 279.4 mm

# IfcStairFlight: Monolithic Run:Monolithic Run (2)
In: 1 Korrus
Type - Pset_ProductRequirements - Category: Runs
Type - Pset_QuantityTakeOff - Reference: Monolithic Run
Type - Pset_StairFlightCommon - Reference: Monolithic Run; NosingLength: 0 mm
TreadLength: 0.984252 mm; Material: Concrete, Cast In Situ
Pset_StairFlightCommon - TreadLength: 300 mm; TreadLengthAtOffset: 300 mm; TreadLengthAtInnerSide: 300 mm
Name (Cast-In-Place Stair:Stair:...) | NumberOfRiser = Pset_StairFlightCommon, NumberOfRiser | NumberOfTreads = Pset_StairFlightCommon, NumberOfTreads | RiserHeight (mm) | Pset_StairFlightCommon, RiserHeight (mm)
853708 Run 1 | 4 | 3 | 0.410105 | 125
978363 Run 1 | 3 | 2 | 0.48119 | 146.667

# IfcWall: Basic Wall:Generic - 150mm, Basic Wall:Generic - 150mm:2184441
In: 1 Korrus A
Type - PredefinedType: STANDARD; Material: _ol.olev sein 150 mm
Type - Pset_ElementShading - Roughness: 914.4 mm
Type - Pset_ProductRequirements - Category: Walls
Type - Pset_QuantityTakeOff - Reference: Generic - 150mm
Type - Pset_ReinforcementBarPitchOfWall - Reference: Generic - 150mm
Type - Pset_WallCommon - IsExternal: no; Reference: Generic - 150mm
Material: _ol.olev sein
Pset_QuantityTakeOff - sets with these values: 2
Pset_WallCommon - ExtendToStructure: no; LoadBearing: no

# IfcWall: Basic Wall:Generic - 250mm, Basic Wall:Generic - 250mm:847230
In: 0 Kelder
Type - PredefinedType: STANDARD; Material: _ol.olev sein 250 mm
Type - Pset_ElementShading - Roughness: 914.4 mm
Type - Pset_ProductRequirements - Category: Walls
Type - Pset_QuantityTakeOff - Reference: Generic - 250mm
Type - Pset_ReinforcementBarPitchOfWall - Reference: Generic - 250mm
Type - Pset_WallCommon - IsExternal: no; Reference: Generic - 250mm
Material: _ol.olev sein
Pset_QuantityTakeOff - sets with these values: 2
Pset_WallCommon - ExtendToStructure: no; LoadBearing: no

# IfcWall: Basic Wall:Generic - 300mm (3)
Type - PredefinedType: STANDARD; Material: _ol.olev sein 300 mm
Type - Pset_ConcreteElementGeneral - FireRating: EI-60
Type - Pset_ElementShading - Roughness: 914.4 mm
Type - Pset_ProductRequirements - Category: Walls
Type - Pset_QuantityTakeOff - Reference: Generic - 300mm
Type - Pset_ReinforcementBarPitchOfWall - Reference: Generic - 300mm
Type - Pset_WallCommon - Reference: Generic - 300mm; AcousticRating: 52 dB; FireRating: EI-60; IsExternal: no
Pset_QuantityTakeOff - sets with these values: 2
Pset_WallCommon - ExtendToStructure: no; LoadBearing: no
Name (Basic Wall:Generic - 300mm:...) | In
847286 | 1 Korrus
847288 | 1 Korrus
847344 | 2 Korrus A

# IfcWall: Basic Wall:Generic - 320mm (2)
Type - PredefinedType: STANDARD; Material: _ol.olev sein 320 mm
Type - Pset_ConcreteElementGeneral - FireRating: EI-60
Type - Pset_ElementShading - Roughness: 914.4 mm
Type - Pset_ProductRequirements - Category: Walls
Type - Pset_QuantityTakeOff - Reference: Generic - 320mm
Type - Pset_ReinforcementBarPitchOfWall - Reference: Generic - 320mm
Type - Pset_WallCommon - IsExternal: no; Reference: Generic - 320mm; AcousticRating: 52 dB; FireRating: EI-60
Pset_QuantityTakeOff - sets with these values: 2
Pset_WallCommon - LoadBearing: no
Name (Basic Wall:Generic - 320mm:...) | In | ExtendToStructure
847149 | 1 Korrus | no
847531 | 3 korrus | yes

# IfcWall: Basic Wall:Generic - 350mm, Basic Wall:Generic - 350mm:970389
In: 2 Korrus
Type - PredefinedType: STANDARD; Material: _ol.olev sein 350 mm
Type - Pset_ConcreteElementGeneral - FireRating: EI-60
Type - Pset_ElementShading - Roughness: 914.4 mm
Type - Pset_ProductRequirements - Category: Walls
Type - Pset_QuantityTakeOff - Reference: Generic - 350mm
Type - Pset_ReinforcementBarPitchOfWall - Reference: Generic - 350mm
Type - Pset_WallCommon - IsExternal: no; Reference: Generic - 350mm; AcousticRating: 52 dB; FireRating: EI-60
Pset_QuantityTakeOff - sets with these values: 2
Pset_WallCommon - ExtendToStructure: no; LoadBearing: no

# IfcWall: Basic Wall:Generic - 400mm (2)
In: 2 Korrus A
Type - PredefinedType: STANDARD; Material: _ol.olev sein 400 mm
Type - Pset_ConcreteElementGeneral - FireRating: EI-60
Type - Pset_ElementShading - Roughness: 914.4 mm
Type - Pset_ProductRequirements - Category: Walls
Type - Pset_QuantityTakeOff - Reference: Generic - 400mm
Type - Pset_ReinforcementBarPitchOfWall - Reference: Generic - 400mm
Type - Pset_WallCommon - IsExternal: no; Reference: Generic - 400mm; AcousticRating: 52 dB; FireRating: EI-60
Pset_QuantityTakeOff - sets with these values: 2
Pset_WallCommon - LoadBearing: no; ExtendToStructure: yes
Name (Basic Wall:Generic - 400mm:...)
1691195
1691346

# IfcWall: Basic Wall:Generic - 410mm (5)
Type - PredefinedType: STANDARD; Material: _ol.olev sein 410 mm
Type - Pset_ConcreteElementGeneral - FireRating: EI-60
Type - Pset_ElementShading - Roughness: 914.4 mm
Type - Pset_ProductRequirements - Category: Walls
Type - Pset_QuantityTakeOff - Reference: Generic - 410mm
Type - Pset_ReinforcementBarPitchOfWall - Reference: Generic - 410mm
Type - Pset_WallCommon - IsExternal: no; Reference: Generic - 410mm; AcousticRating: 52 dB; FireRating: EI-60
Pset_QuantityTakeOff - sets with these values: 2
Pset_WallCommon - ExtendToStructure: no; LoadBearing: no
Name (Basic Wall:Generic - 410mm:...) | In
847228 | 0 Kelder
847247 | 0 Kelder
847273 | 0 Kelder
858380 | 0 Kelder
1660188 | 1 Korrus

# IfcWall: Basic Wall:SS-03_Kips, 66mm metallkarkass, Basic Wall:SS-03_Kips, 66mm metallkarkass:1376431
In: 2 Korrus A
Type - PredefinedType: STANDARD; Material: EST. Ehitusplaat. Kipsplaat 12.5 mm, EST. Ehitusplaat. Kipsplaat 12.5 mm, EST. Õhkvahe. Roov. Kipsplaadi alusroov. Vertikaalne 66 mm, EST. Ehitusplaat. Kipsplaat 12.5 mm, EST. Ehitusplaat. Kipsplaat 12.5 mm
Type - Pset_ConcreteElementGeneral - FireRating: EI-60
Type - Pset_ElementShading - Roughness: 914.4 mm
Type - Pset_ProductRequirements - Category: Walls
Type - Pset_QuantityTakeOff - Reference: SS-03_Kips, 66mm metallkarkass
Type - Pset_ReinforcementBarPitchOfWall - Reference: SS-03_Kips, 66mm metallkarkass
Type - Pset_WallCommon - IsExternal: no; Reference: SS-03_Kips, 66mm metallkarkass; AcousticRating: 48 dB; FireRating: EI-60; Combustible: no
Pset_QuantityTakeOff - sets with these values: 2
Pset_WallCommon - ExtendToStructure: no; LoadBearing: no

# IfcWall: Basic Wall:SS-07_ 150mm Fobo 5, Basic Wall:SS-07_ 150mm Fobo 5:999541
In: 0 Kelder
Type - PredefinedType: STANDARD; Material: EST. Müüritis. Väikeplokk. Betoon-õõnesplokk 150 mm
Type - Pset_ConcreteElementGeneral - FireRating: EI-60
Type - Pset_ElementShading - Roughness: 914.4 mm
Type - Pset_ProductRequirements - Category: Walls
Type - Pset_QuantityTakeOff - Reference: SS-07_ 150mm Fobo 5
Type - Pset_ReinforcementBarPitchOfWall - Reference: SS-07_ 150mm Fobo 5
Type - Pset_WallCommon - IsExternal: no; Combustible: yes; Reference: SS-07_ 150mm Fobo 5; AcousticRating: 56 dB; FireRating: EI-60
Material: EST. Müüritis. Väikeplokk. Betoon-õõnesplokk
Pset_QuantityTakeOff - sets with these values: 2
Pset_WallCommon - ExtendToStructure: no; LoadBearing: no

# IfcWall: Basic Wall:VS-00_200mm EPS+ krohv (4)
Type - PredefinedType: STANDARD; Material: EST. Fassaadikate. Krohv. Valge 1 mm, EST. Soojustus. Mineraalvill. Default 250 mm
Type - Pset_ElementShading - Roughness: 914.4 mm
Type - Pset_ProductRequirements - Category: Walls
Type - Pset_QuantityTakeOff - Reference: VS-00_200mm EPS+ krohv
Type - Pset_ReinforcementBarPitchOfWall - Reference: VS-00_200mm EPS+ krohv
Type - Pset_WallCommon - IsExternal: yes; Combustible: no; Reference: VS-00_200mm EPS+ krohv
Pset_QuantityTakeOff - sets with these values: 2
Pset_WallCommon - ExtendToStructure: no; LoadBearing: no
Name (Basic Wall:VS-00_200mm EPS+ krohv:...) | In
1014850 | 0 Kelder
1014918 | 0 Kelder
1015215 | 0 Kelder
1801153 | Katus

# IfcWall: Basic Wall:VS-00_200mm EPS+ krohv pinnases, Basic Wall:VS-00_200mm EPS+ krohv pinnases:1015398
In: 0 Kelder
Type - PredefinedType: STANDARD; Material: EST. Fassaadikate. Krohv. Valge 1 mm, EST. Soojustus. Mineraalvill. Default 250 mm
Type - Pset_ElementShading - Roughness: 914.4 mm
Type - Pset_ProductRequirements - Category: Walls
Type - Pset_QuantityTakeOff - Reference: VS-00_200mm EPS+ krohv pinnases
Type - Pset_ReinforcementBarPitchOfWall - Reference: VS-00_200mm EPS+ krohv pinnases
Type - Pset_WallCommon - IsExternal: yes; Combustible: no; Reference: VS-00_200mm EPS+ krohv pinnases
Material: EST. Fassaadikate. Krohv. Valge, EST. Soojustus. Mineraalvill. Default
Pset_QuantityTakeOff - sets with these values: 2
Pset_WallCommon - ExtendToStructure: no; LoadBearing: no

# IfcWall: Basic Wall:VS-01_Puitkonstruktsioon 368mm (7)
Type - PredefinedType: STANDARD; Material: EST. Fassaadikate. Laudis. Horisontaalne. Default 16 mm, EST. Õhkvahe. Roov. Fassaadikatte alusroov. Vertikaalne 25 mm, EST. Tuuletõke. Kipsplaat 30 mm, EST. Soojustus. Mineraalvill. Default 195 mm, EST. Soojustus. Mineraalvill. Default 66 mm, EST. Ehitusplaat. Kipsplaat 15 mm, EST. Ehitusplaat. Kipsplaat 15 mm
Type - Pset_ElementShading - Roughness: 914.4 mm
Type - Pset_ProductRequirements - Category: Walls
Type - Pset_QuantityTakeOff - Reference: VS-01_Puitkonstruktsioon 368mm
Type - Pset_ReinforcementBarPitchOfWall - Reference: VS-01_Puitkonstruktsioon 368mm
Type - Pset_WallCommon - Reference: VS-01_Puitkonstruktsioon 368mm; Combustible: yes; IsExternal: yes
Pset_QuantityTakeOff - sets with these values: 2
Pset_WallCommon - ExtendToStructure: no; LoadBearing: no
Name (Basic Wall:VS-01_Puitkonstruktsioon 368mm:...) | In
847632 | 1 Korrus A | Material: EST. Fassaadikate. Laudis. Horisontaalne. Default, EST. Õhkvahe. Roov. Fassaadikatte alusroov. Vertikaalne, EST. Tuuletõke. Kipsplaat, EST. Soojustus. Mineraalvill. Default (2), Default, EST. Ehitusplaat. Kipsplaat (2)
847638 | 1 Korrus A
847639 | 1 Korrus A
847640 | 1 Korrus A
847644 | 2 Korrus A
847645 | 2 Korrus A
847850 | 3 Korrus A

# IfcWall: Basic Wall:VS-04_200mm EPS+ krohv (2)
Type - PredefinedType: STANDARD; Material: EST. Fassaadikate. Krohv. Valge 1 mm, EST. Soojustus. Mineraalvill. Default 250 mm
Type - Pset_ElementShading - Roughness: 914.4 mm
Type - Pset_ProductRequirements - Category: Walls
Type - Pset_QuantityTakeOff - Reference: VS-04_200mm EPS+ krohv
Type - Pset_ReinforcementBarPitchOfWall - Reference: VS-04_200mm EPS+ krohv
Type - Pset_WallCommon - IsExternal: yes; Combustible: no; Reference: VS-04_200mm EPS+ krohv
Pset_QuantityTakeOff - sets with these values: 2
Pset_WallCommon - ExtendToStructure: no; LoadBearing: no
Name (Basic Wall:VS-04_200mm EPS+ krohv:...) | In
945275 | 3 korrus
2293132 | 2 Korrus

# IfcWall: Basic Wall:VS-07_Puitkonstruktsioon, Basic Wall:VS-07_Puitkonstruktsioon:1051032
In: 2 Korrus A
Type - PredefinedType: STANDARD; Material: EST. Fassaadikate. Laudis. Horisontaalne. Default 16 mm, EST. Õhkvahe. Roov. Fassaadikatte alusroov. Vertikaalne 25 mm, EST. Tuuletõke. Kipsplaat 30 mm, EST. Soojustus. Mineraalvill. Default 195 mm
Type - Pset_ElementShading - Roughness: 914.4 mm
Type - Pset_ProductRequirements - Category: Walls
Type - Pset_QuantityTakeOff - Reference: VS-07_Puitkonstruktsioon
Type - Pset_ReinforcementBarPitchOfWall - Reference: VS-07_Puitkonstruktsioon
Type - Pset_WallCommon - Combustible: yes; IsExternal: yes; Reference: VS-07_Puitkonstruktsioon
Material: EST. Fassaadikate. Laudis. Horisontaalne. Default, EST. Õhkvahe. Roov. Fassaadikatte alusroov. Vertikaalne, EST. Tuuletõke. Kipsplaat, EST. Soojustus. Mineraalvill. Default, Default
Pset_QuantityTakeOff - sets with these values: 2
Pset_WallCommon - ExtendToStructure: no; LoadBearing: no

# IfcWall: Walls 1:Walls 1, Walls 1:Walls 1:1022189
In: 0 Kelder
Type - Material: _ol.olev sein
Type - Pset_ConcreteElementGeneral - FireRating: EI-60
Type - Pset_ProductRequirements - Category: Walls
Type - Pset_QuantityTakeOff - Reference: Walls 1
Type - Pset_ReinforcementBarPitchOfWall - Reference: Walls 1
Type - Pset_WallCommon - IsExternal: no; Reference: Walls 1; AcousticRating: 52 dB; FireRating: EI-60
Pset_QuantityTakeOff - sets with these values: 2

# IfcWallStandardCase: Basic Wall:Generic - 150mm (6)
In: 1 Korrus A
Type - PredefinedType: STANDARD; Material: _ol.olev sein 150 mm
Type - Pset_ElementShading - Roughness: 914.4 mm
Type - Pset_ProductRequirements - Category: Walls
Type - Pset_QuantityTakeOff - Reference: Generic - 150mm
Type - Pset_ReinforcementBarPitchOfWall - Reference: Generic - 150mm
Type - Pset_WallCommon - IsExternal: no; Reference: Generic - 150mm
Pset_QuantityTakeOff - sets with these values: 2
Pset_WallCommon - ExtendToStructure: no; LoadBearing: no
Name (Basic Wall:Generic - 150mm:...)
2184494
2184788
2185002
2185105
2189108
2190647

# IfcWallStandardCase: Basic Wall:Generic - 300mm (48)
Type - PredefinedType: STANDARD; Material: _ol.olev sein 300 mm
Type - Pset_ConcreteElementGeneral - FireRating: EI-60
Type - Pset_ElementShading - Roughness: 914.4 mm
Type - Pset_ProductRequirements - Category: Walls
Type - Pset_QuantityTakeOff - Reference: Generic - 300mm
Type - Pset_ReinforcementBarPitchOfWall - Reference: Generic - 300mm
Type - Pset_WallCommon - Reference: Generic - 300mm; AcousticRating: 52 dB; FireRating: EI-60; IsExternal: no
Pset_QuantityTakeOff - sets with these values: 2
Pset_WallCommon - LoadBearing: no
Name (Basic Wall:Generic - 300mm:...) | In | ExtendToStructure
847139 | 1 Korrus | no
847140 | 1 Korrus A | no
847141 | 1 Korrus | no
847142 | 1 Korrus | no
847144 | 1 Korrus A | no
847145 | 1 Korrus A | no
847146 | 1 Korrus | no
847147 | 1 Korrus | no
847151 | 0 Kelder | no
847224 | 0 Kelder | no
847289 | 1 Korrus | no
847292 | 1 Korrus A | no
847329 | 1 Korrus A | no
847345 | 2 Korrus A | no
847347 | 2 Korrus A | no
847384 | 2 Korrus A | no
847387 | 2 Korrus A | no
847400 | 3 Korrus A | no
847401 | 3 Korrus A | no
847402 | 3 Korrus A | yes
847403 | 3 Korrus A | yes
847405 | 3 Korrus A | yes
847437 | 3 Korrus A | no
847440 | 3 Korrus A | no
847453 | 2 Korrus | no
847455 | 2 Korrus | no
847460 | 2 Korrus | no
847483 | 2 Korrus | no
847493 | 3 korrus | no
847495 | 3 korrus | no
847498 | 2 Korrus A | no
847500 | 3 korrus | no
847523 | 3 korrus | no
847524 | 3 korrus | no
847530 | 3 Korrus A | no
847856 | Katus | no
848136 | Katus | no
849494 | Katus A | no
854660 | 0 Kelder | no
936701 | 1 Korrus A | no
1585110 | 2 Korrus | no
1654578 | 3 Korrus A | no
1658662 | 2 Korrus | no
1658810 | Katus | yes
1950151 | 3 korrus | no
1950524 | 2 Korrus | no
1950525 | 2 Korrus | no
2177760 | 0 Kelder | no

# IfcWallStandardCase: Basic Wall:Generic - 300mm 2 (2)
In: 0 Kelder
Type - PredefinedType: STANDARD; Material: _ol.olev sein 300 mm
Type - Pset_ElementShading - Roughness: 914.4 mm
Type - Pset_ProductRequirements - Category: Walls
Type - Pset_QuantityTakeOff - Reference: Generic - 300mm 2
Type - Pset_ReinforcementBarPitchOfWall - Reference: Generic - 300mm 2
Type - Pset_WallCommon - IsExternal: no; Reference: Generic - 300mm 2
Pset_QuantityTakeOff - sets with these values: 2
Pset_WallCommon - ExtendToStructure: no; LoadBearing: no
Name (Basic Wall:Generic - 300mm 2:...)
853443
858140

# IfcWallStandardCase: Basic Wall:Generic - 320mm (25)
Type - PredefinedType: STANDARD; Material: _ol.olev sein 320 mm
Type - Pset_ConcreteElementGeneral - FireRating: EI-60
Type - Pset_ElementShading - Roughness: 914.4 mm
Type - Pset_ProductRequirements - Category: Walls
Type - Pset_QuantityTakeOff - Reference: Generic - 320mm
Type - Pset_ReinforcementBarPitchOfWall - Reference: Generic - 320mm
Type - Pset_WallCommon - IsExternal: no; Reference: Generic - 320mm; AcousticRating: 52 dB; FireRating: EI-60
Pset_QuantityTakeOff - sets with these values: 2
Pset_WallCommon - LoadBearing: no
Name (Basic Wall:Generic - 320mm:...) | In | ExtendToStructure
847148 | 1 Korrus A | no
847152 | 1 Korrus | no
847153 | 1 Korrus A | no
847154 | 1 Korrus A | no
847155 | 1 Korrus A | no
847156 | 1 Korrus | no
847222 | 0 Kelder | no
847227 | 0 Kelder | no
847346 | 2 Korrus A | no
847348 | 2 Korrus A | yes
847349 | 2 Korrus A | no
847404 | 3 Korrus A | yes
847457 | 2 Korrus | no
847462 | 2 Korrus | no
847463 | 2 Korrus | no
847464 | 2 Korrus | no
847486 | 2 Korrus | no
847492 | 2 Korrus | no
847497 | 3 korrus | yes
847502 | 3 korrus | no
847503 | 3 korrus | yes
847504 | 3 korrus | yes
847526 | 3 korrus | yes
847858 | Katus | yes
2147712 | 3 korrus | no

# IfcWallStandardCase: Basic Wall:Generic - 350mm (34)
Type - PredefinedType: STANDARD; Material: _ol.olev sein 350 mm
Type - Pset_ConcreteElementGeneral - FireRating: EI-60
Type - Pset_ElementShading - Roughness: 914.4 mm
Type - Pset_ProductRequirements - Category: Walls
Type - Pset_QuantityTakeOff - Reference: Generic - 350mm
Type - Pset_ReinforcementBarPitchOfWall - Reference: Generic - 350mm
Type - Pset_WallCommon - IsExternal: no; Reference: Generic - 350mm; AcousticRating: 52 dB; FireRating: EI-60
Pset_QuantityTakeOff - sets with these values: 2
Pset_WallCommon - LoadBearing: no
Name (Basic Wall:Generic - 350mm:...) | In | ExtendToStructure
847150 | 1 Korrus | no
847225 | 0 Kelder | no
847226 | 0 Kelder | no
847234 | 0 Kelder | no
847235 | 0 Kelder | no
847236 | 0 Kelder | no
847241 | 0 Kelder | no
847242 | 0 Kelder | no
847244 | 0 Kelder | no
847249 | 0 Kelder | no
847290 | 1 Korrus | no
847326 | 1 Korrus A | no
847385 | 2 Korrus A | no
847438 | 3 Korrus A | no
847454 | 2 Korrus | no
847456 | 2 Korrus | no
847461 | 2 Korrus | no
847485 | 2 Korrus | no
847494 | 3 korrus | no
847496 | 3 korrus | no
847499 | 3 korrus | no
847501 | 3 korrus | yes
847525 | 3 korrus | yes
847857 | Katus | no
848135 | Katus | no
849911 | Katus | no
850329 | Katus A | no
854158 | 1 Korrus | no
1658661 | 1 Korrus | no
1658663 | 3 korrus | no
1675997 | 0 Kelder | no
1690100 | 0 Kelder | no
2147711 | 3 korrus | no
2293399 | 2 Korrus | no

# IfcWallStandardCase: Basic Wall:Generic - 380mm (2)
Type - PredefinedType: STANDARD; Material: _ol.olev sein 380 mm
Type - Pset_ElementShading - Roughness: 914.4 mm
Type - Pset_ProductRequirements - Category: Walls
Type - Pset_QuantityTakeOff - Reference: Generic - 380mm
Type - Pset_ReinforcementBarPitchOfWall - Reference: Generic - 380mm
Type - Pset_WallCommon - IsExternal: no; Reference: Generic - 380mm
Pset_QuantityTakeOff - sets with these values: 2
Pset_WallCommon - ExtendToStructure: no; LoadBearing: no
Name (Basic Wall:Generic - 380mm:...) | In
1136810 | 1 Korrus
1691347 | 2 Korrus A

# IfcWallStandardCase: Basic Wall:Generic - 400mm (14)
Type - PredefinedType: STANDARD; Material: _ol.olev sein 400 mm
Type - Pset_ConcreteElementGeneral - FireRating: EI-60
Type - Pset_ElementShading - Roughness: 914.4 mm
Type - Pset_ProductRequirements - Category: Walls
Type - Pset_QuantityTakeOff - Reference: Generic - 400mm
Type - Pset_ReinforcementBarPitchOfWall - Reference: Generic - 400mm
Type - Pset_WallCommon - IsExternal: no; Reference: Generic - 400mm; AcousticRating: 52 dB; FireRating: EI-60
Pset_QuantityTakeOff - sets with these values: 2
Pset_WallCommon - LoadBearing: no
Name (Basic Wall:Generic - 400mm:...) | In | ExtendToStructure
847338 | 1 Korrus A | no
847809 | 3 korrus | yes
914174 | 2 Korrus | no
1255929 | 0 Kelder | no
1656114 | 1 Korrus | no
1657661 | 1 Korrus | no
1658068 | 3 korrus | yes
1689257 | 0 Kelder | yes
1689612 | 0 Kelder | no
1690379 | 1 Korrus A | no
1690493 | 1 Korrus A | no
1691272 | 2 Korrus A | no
1691314 | 2 Korrus A | yes
1691315 | 2 Korrus A | no

# IfcWallStandardCase: Basic Wall:Generic - 410mm (37)
Type - PredefinedType: STANDARD; Material: _ol.olev sein 410 mm
Type - Pset_ConcreteElementGeneral - FireRating: EI-60
Type - Pset_ElementShading - Roughness: 914.4 mm
Type - Pset_ProductRequirements - Category: Walls
Type - Pset_QuantityTakeOff - Reference: Generic - 410mm
Type - Pset_ReinforcementBarPitchOfWall - Reference: Generic - 410mm
Type - Pset_WallCommon - IsExternal: no; Reference: Generic - 410mm; AcousticRating: 52 dB; FireRating: EI-60
Pset_QuantityTakeOff - sets with these values: 2
Pset_WallCommon - LoadBearing: no
Name (Basic Wall:Generic - 410mm:...) | In | ExtendToStructure
847220 | 0 Kelder | no
847221 | 0 Kelder | no
847229 | 0 Kelder | no
847231 | 0 Kelder | no
847232 | 0 Kelder | no
847243 | 0 Kelder | no
847246 | 0 Kelder | no
847250 | 0 Kelder | no
847395 | 2 Korrus A | no
847415 | 3 Korrus A | yes
847448 | 3 Korrus A | no
847459 | 2 Korrus | no
847535 | 2 Korrus A | no
847542 | 2 Korrus A | no
847551 | 3 Korrus A | no
847552 | 3 Korrus A | no
847630 | 1 Korrus A | no
854127 | 0 Kelder | no
935418 | 1 Korrus | no
984298 | 2 Korrus | no
1147973 | 0 Kelder | no
1191667 | 0 Kelder | no
1191714 | 0 Kelder | no
1191841 | 0 Kelder | no
1656006 | 1 Korrus | no
1657826 | 3 korrus | yes
1658067 | 1 Korrus | no
1658708 | 0 Kelder | no
1659490 | 1 Korrus | no
1659768 | 0 Kelder | no
1660670 | 1 Korrus A | no
1661528 | 2 Korrus A | no
1661893 | 2 Korrus | yes
1685656 | 0 Kelder | no
1685830 | 0 Kelder | no
1690238 | 1 Korrus A | no
1702697 | 1 Korrus | no

# IfcWallStandardCase: Basic Wall:Generic - 445mm (4)
Type - PredefinedType: STANDARD; Material: _ol.olev sein 445 mm
Type - Pset_ConcreteElementGeneral - FireRating: EI-60
Type - Pset_ElementShading - Roughness: 914.4 mm
Type - Pset_ProductRequirements - Category: Walls
Type - Pset_QuantityTakeOff - Reference: Generic - 445mm
Type - Pset_ReinforcementBarPitchOfWall - Reference: Generic - 445mm
Type - Pset_WallCommon - IsExternal: no; Reference: Generic - 445mm; AcousticRating: 52 dB; FireRating: EI-60
Pset_QuantityTakeOff - sets with these values: 2
Pset_WallCommon - ExtendToStructure: no; LoadBearing: no
Name (Basic Wall:Generic - 445mm:...) | In
847223 | 0 Kelder
847245 | 0 Kelder
847253 | 0 Kelder
1661024 | 2 Korrus A

# IfcWallStandardCase: Basic Wall:Generic - 500mm, Basic Wall:Generic - 500mm:847252
In: 0 Kelder
Type - PredefinedType: STANDARD; Material: _ol.olev sein 500 mm
Type - Pset_ElementShading - Roughness: 914.4 mm
Type - Pset_ProductRequirements - Category: Walls
Type - Pset_QuantityTakeOff - Reference: Generic - 500mm
Type - Pset_ReinforcementBarPitchOfWall - Reference: Generic - 500mm
Type - Pset_WallCommon - IsExternal: no; Reference: Generic - 500mm
Pset_QuantityTakeOff - sets with these values: 2
Pset_WallCommon - ExtendToStructure: no; LoadBearing: no

# IfcWallStandardCase: Basic Wall:Generic - 555mm, Basic Wall:Generic - 555mm:847233
In: 0 Kelder
Type - PredefinedType: STANDARD; Material: _ol.olev sein 555 mm
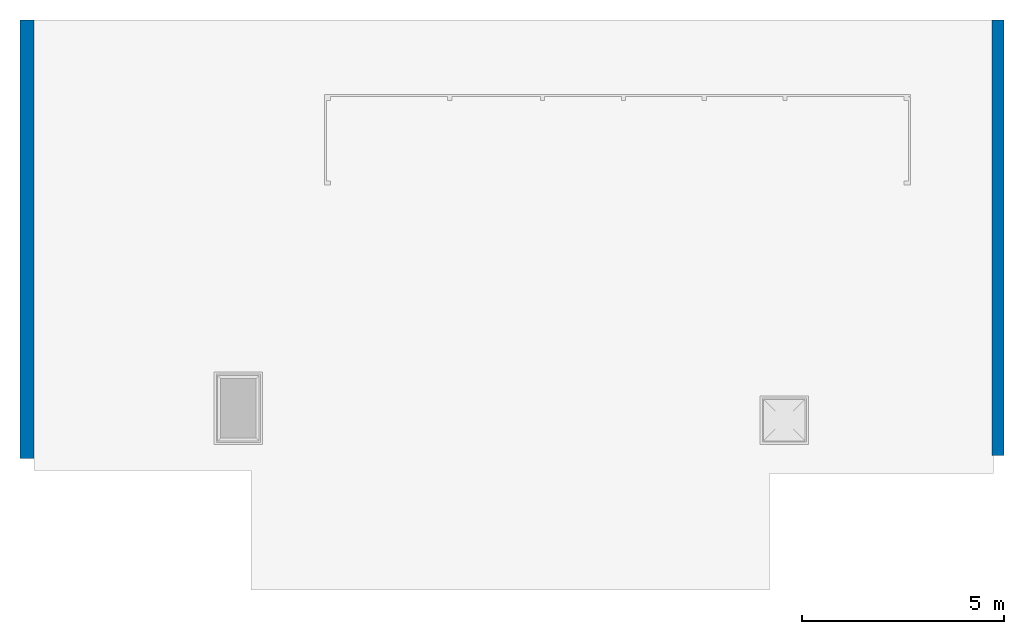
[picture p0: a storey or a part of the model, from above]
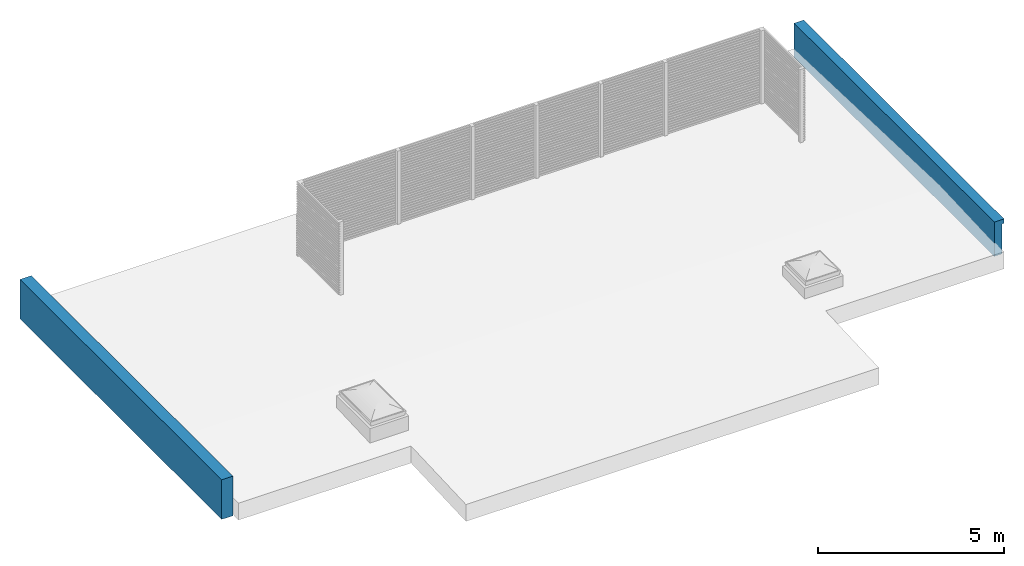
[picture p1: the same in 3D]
Properties of the parts of a building model (IFC2X3), part 7 of 7

# IfcWallStandardCase: Basic Wall:Generic - 555mm, Basic Wall:Generic - 555mm:847233
Type - Pset_ElementShading - Roughness: 914.4 mm
Type - Pset_ProductRequirements - Category: Walls
Type - Pset_QuantityTakeOff - Reference: Generic - 555mm
Type - Pset_ReinforcementBarPitchOfWall - Reference: Generic - 555mm
Type - Pset_WallCommon - IsExternal: no; Reference: Generic - 555mm
Pset_QuantityTakeOff - sets with these values: 2
Pset_WallCommon - ExtendToStructure: no; LoadBearing: no

# IfcWallStandardCase: Basic Wall:Generic -40 (3)
Type - PredefinedType: STANDARD; Material: _ol.olev sein 40 mm
Type - Pset_ElementShading - Roughness: 914.4 mm
Type - Pset_ProductRequirements - Category: Walls
Type - Pset_QuantityTakeOff - Reference: Generic -40
Type - Pset_ReinforcementBarPitchOfWall - Reference: Generic -40
Type - Pset_WallCommon - IsExternal: no; Reference: Generic -40
Pset_QuantityTakeOff - sets with these values: 2
Pset_WallCommon - LoadBearing: no
Name (Basic Wall:Generic -40:...) | In | ExtendToStructure
1085734 | 1 Korrus A | no
1192019 | 3 Korrus A | yes
1505669 | 2 Korrus A | yes

# IfcWallStandardCase: Basic Wall:Generic -80, Basic Wall:Generic -80:847175
In: 1 Korrus A
Type - PredefinedType: STANDARD; Material: _ol.olev sein 80 mm
Type - Pset_ElementShading - Roughness: 914.4 mm
Type - Pset_ProductRequirements - Category: Walls
Type - Pset_QuantityTakeOff - Reference: Generic -80
Type - Pset_ReinforcementBarPitchOfWall - Reference: Generic -80
Type - Pset_WallCommon - IsExternal: no; Reference: Generic -80
Pset_QuantityTakeOff - sets with these values: 2
Pset_WallCommon - ExtendToStructure: no; LoadBearing: no

# IfcWallStandardCase: Basic Wall:SS-00_Fibo 300mm, Basic Wall:SS-00_Fibo 300mm:2293321
In: 2 Korrus
Type - PredefinedType: STANDARD; Material: EST. Müüritis. Väikeplokk. Kergkruusplokk 350 mm
Type - Pset_ElementShading - Roughness: 914.4 mm
Type - Pset_ProductRequirements - Category: Walls
Type - Pset_QuantityTakeOff - Reference: SS-00_Fibo 300mm
Type - Pset_ReinforcementBarPitchOfWall - Reference: SS-00_Fibo 300mm
Type - Pset_WallCommon - IsExternal: no; Combustible: yes; Reference: SS-00_Fibo 300mm
Pset_QuantityTakeOff - sets with these values: 2
Pset_WallCommon - ExtendToStructure: no; LoadBearing: no

# IfcWallStandardCase: Basic Wall:SS-00_Kips, 150mm metallkarkass (4)
In: 1 Korrus
Type - PredefinedType: STANDARD; Material: EST. Ehitusplaat. Kipsplaat. Tulekindel 15 mm, EST. Ehitusplaat. Kipsplaat. Tulekindel 15 mm, EST. Soojustus. Mineraalvill. Default 150 mm, EST. Tuuletõke. Kipsplaat 20 mm, EST. Õhkvahe. Roov. Fassaadikatte alusroov. Vertikaalne 25 mm, EST. Ehitusplaat. Tsementkiudplaat 8 mm
Type - Pset_ElementShading - Roughness: 914.4 mm
Type - Pset_ProductRequirements - Category: Walls
Type - Pset_QuantityTakeOff - Reference: SS-00_Kips, 150mm metallkarkass
Type - Pset_ReinforcementBarPitchOfWall - Reference: SS-00_Kips, 150mm metallkarkass
Type - Pset_WallCommon - IsExternal: no; Combustible: no; Reference: SS-00_Kips, 150mm metallkarkass
Pset_QuantityTakeOff - sets with these values: 2
Pset_WallCommon - LoadBearing: no; ExtendToStructure: yes
Name (Basic Wall:SS-00_Kips, 150mm metallkarkass:...)
907001
1596785
1596855
1641018

# IfcWallStandardCase: Basic Wall:SS-01_Kips, 95mm metallkarkass (51)
Type - PredefinedType: STANDARD; Material: EST. Ehitusplaat. Kipsplaat 12.5 mm, EST. Ehitusplaat. Kipsplaat 12.5 mm, Default Wall 12 mm, EST. Õhkvahe. Roov. Kipsplaadi alusroov. Vertikaalne 95 mm, Default Wall 12 mm, EST. Ehitusplaat. Kipsplaat 12.5 mm, EST. Ehitusplaat. Kipsplaat 12.5 mm
Type - Pset_ConcreteElementGeneral - FireRating: EI-60
Type - Pset_ElementShading - Roughness: 914.4 mm
Type - Pset_ProductRequirements - Category: Walls
Type - Pset_QuantityTakeOff - Reference: SS-01_Kips, 95mm metallkarkass
Type - Pset_ReinforcementBarPitchOfWall - Reference: SS-01_Kips, 95mm metallkarkass
Type - Pset_WallCommon - IsExternal: no; Combustible: no; Reference: SS-01_Kips, 95mm metallkarkass; AcousticRating: 52 dB; FireRating: EI-60
Pset_QuantityTakeOff - sets with these values: 2
Pset_WallCommon - LoadBearing: no
Name (Basic Wall:SS-01_Kips, 95mm metallkarkass:...) | In | ExtendToStructure
886866 | 1 Korrus | no
886867 | 1 Korrus | no
887991 | 1 Korrus A | no
888367 | 1 Korrus A | no
888560 | 1 Korrus A | no
888919 | 1 Korrus A | no
889074 | 1 Korrus A | no
911988 | 2 Korrus A | no
911996 | 2 Korrus A | no
911997 | 2 Korrus A | no
911999 | 2 Korrus A | no
912000 | 2 Korrus A | no
912473 | 2 Korrus | yes
912474 | 2 Korrus | no
912475 | 2 Korrus | no
912486 | 2 Korrus | no
912487 | 2 Korrus | yes
912542 | 2 Korrus | no
914870 | 2 Korrus | no
917539 | 2 Korrus | no
919090 | 2 Korrus A | yes
928274 | 2 Korrus A | no
971283 | 1 Korrus | no
981294 | 3 korrus | yes
981295 | 3 korrus | yes
981296 | 3 korrus | yes
981389 | 3 korrus | yes
984683 | 3 Korrus A | yes
984691 | 3 Korrus A | yes
984692 | 3 Korrus A | yes
984694 | 3 Korrus A | yes
984695 | 3 Korrus A | yes
985186 | 3 korrus | yes
985187 | 3 korrus | yes
985239 | 3 korrus | yes
1093845 | 3 Korrus A | no
1093857 | 3 Korrus A | no
1215416 | 1 Korrus | no
1376688 | 2 Korrus A | no
1702606 | 1 Korrus | no
1715444 | 1 Korrus | yes
1716120 | 1 Korrus A | no
1718226 | 3 korrus | no
1761207 | 2 Korrus A | no
1761249 | 2 Korrus A | no
1761336 | 2 Korrus A | no
1762245 | 1 Korrus A | no
1762274 | 1 Korrus A | no
1762376 | 1 Korrus A | no
1763047 | 1 Korrus A | no
1766432 | 2 Korrus A | no

# IfcWallStandardCase: Basic Wall:SS-02_Kips, 95mm metallkarkass 2 (32)
Type - PredefinedType: STANDARD; Material: EST. Ehitusplaat. Kipsplaat 12.5 mm, EST. Ehitusplaat. Kipsplaat 12.5 mm, Default Wall 12 mm, EST. Õhkvahe. Roov. Kipsplaadi alusroov. Vertikaalne 95 mm, Default Wall 12 mm, EST. Ehitusplaat. Kipsplaat 12.5 mm, EST. Ehitusplaat. Kipsplaat 12.5 mm
Type - Pset_ConcreteElementGeneral - FireRating: EI-60
Type - Pset_ElementShading - Roughness: 914.4 mm
Type - Pset_ProductRequirements - Category: Walls
Type - Pset_QuantityTakeOff - Reference: SS-02_Kips, 95mm metallkarkass 2
Type - Pset_ReinforcementBarPitchOfWall - Reference: SS-02_Kips, 95mm metallkarkass 2
Type - Pset_WallCommon - IsExternal: no; Combustible: no; Reference: SS-02_Kips, 95mm metallkarkass 2; AcousticRating: 52 dB; FireRating: EI-60
Pset_QuantityTakeOff - sets with these values: 2
Pset_WallCommon - LoadBearing: no
Name (Basic Wall:SS-02_Kips, 95mm metallkarkass 2:...) | In | ExtendToStructure
887992 | 1 Korrus A | no
888110 | 1 Korrus A | no
894259 | 1 Korrus A | no
911992 | 2 Korrus A | no
912009 | 2 Korrus A | no
912010 | 2 Korrus A | no
930583 | 2 Korrus A | no
959702 | 1 Korrus A | no
964410 | 1 Korrus A | no
969154 | 2 Korrus A | no
984684 | 3 Korrus A | yes
984687 | 3 Korrus A | yes
984720 | 3 Korrus A | yes
984756 | 3 Korrus A | yes
984815 | 3 Korrus A | yes
1089636 | 1 Korrus A | yes
1094454 | 1 Korrus A | yes
1177052 | 1 Korrus | yes
1376755 | 2 Korrus A | no
1714501 | 2 Korrus | no
1715751 | 1 Korrus A | no
1716082 | 1 Korrus A | no
1759803 | 3 korrus | yes
1760818 | 3 korrus | yes
1761217 | 2 Korrus A | no
1761289 | 2 Korrus A | no
1761370 | 2 Korrus A | no
1762254 | 1 Korrus A | no
1762341 | 1 Korrus A | no
1762428 | 1 Korrus A | no
1766373 | 2 Korrus A | no
1766930 | 2 Korrus | no

# IfcWallStandardCase: Basic Wall:SS-03_Kips, 66mm metallkarkass (73)
Type - PredefinedType: STANDARD; Material: EST. Ehitusplaat. Kipsplaat 12.5 mm, EST. Ehitusplaat. Kipsplaat 12.5 mm, EST. Õhkvahe. Roov. Kipsplaadi alusroov. Vertikaalne 66 mm, EST. Ehitusplaat. Kipsplaat 12.5 mm, EST. Ehitusplaat. Kipsplaat 12.5 mm
Type - Pset_ConcreteElementGeneral - FireRating: EI-60
Type - Pset_ElementShading - Roughness: 914.4 mm
Type - Pset_ProductRequirements - Category: Walls
Type - Pset_QuantityTakeOff - Reference: SS-03_Kips, 66mm metallkarkass
Type - Pset_ReinforcementBarPitchOfWall - Reference: SS-03_Kips, 66mm metallkarkass
Type - Pset_WallCommon - IsExternal: no; Reference: SS-03_Kips, 66mm metallkarkass; AcousticRating: 48 dB; FireRating: EI-60; Combustible: no
Pset_QuantityTakeOff - sets with these values: 2
Pset_WallCommon - LoadBearing: no
Name (Basic Wall:SS-03_Kips, 66mm metallkarkass:...) | In | ExtendToStructure
865215 | 1 Korrus | no
865404 | 1 Korrus | no
865667 | 1 Korrus | no
888264 | 1 Korrus A | no
888803 | 1 Korrus A | no
894956 | 1 Korrus A | no
895638 | 1 Korrus A | no
895775 | 1 Korrus A | no
911995 | 2 Korrus A | no
911998 | 2 Korrus A | no
912005 | 2 Korrus A | no
912006 | 2 Korrus A | no
912011 | 2 Korrus A | no
912012 | 2 Korrus A | no
912016 | 2 Korrus A | no
912017 | 2 Korrus A | no
919194 | 2 Korrus A | no
919225 | 2 Korrus A | no
928275 | 2 Korrus A | no
928276 | 2 Korrus A | no
928479 | 2 Korrus A | no
932071 | 1 Korrus | no
960003 | 1 Korrus A | no
960007 | 1 Korrus A | no
971664 | 1 Korrus | yes
980770 | 1 Korrus A | no
981301 | 3 korrus | yes
981302 | 3 korrus | no
984690 | 3 Korrus A | yes
984693 | 3 Korrus A | yes
984721 | 3 Korrus A | yes
984728 | 3 Korrus A | yes
984730 | 3 Korrus A | yes
984758 | 3 Korrus A | no
984760 | 3 Korrus A | no
984797 | 3 Korrus A | yes
984799 | 3 Korrus A | no
984834 | 3 Korrus A | yes
985243 | 3 korrus | yes
985244 | 3 korrus | yes
996258 | 1 Korrus | yes
1002462 | 0 Kelder | no
1081742 | 1 Korrus A | no
1081743 | 1 Korrus A | no
1081747 | 1 Korrus A | no
1081748 | 1 Korrus A | no
1081758 | 1 Korrus A | no
1081759 | 1 Korrus A | no
1093846 | 3 Korrus A | no
1093847 | 3 Korrus A | no
1093858 | 3 Korrus A | yes
1093859 | 3 Korrus A | no
1124187 | 3 korrus | no
1133884 | 3 korrus | yes
1149604 | 1 Korrus | no
1149605 | 1 Korrus | no
1163736 | 2 Korrus A | no
1165591 | 2 Korrus | no
1165592 | 2 Korrus | no
1165598 | 2 Korrus | no
1165599 | 2 Korrus | no
1165617 | 2 Korrus | no
1165633 | 2 Korrus | no
1168672 | 1 Korrus | yes
1199509 | 0 Kelder | no
1308430 | 0 Kelder | yes
1376602 | 2 Korrus A | no
1755818 | 3 Korrus A | no
1758229 | 2 Korrus A | no
1759225 | 1 Korrus A | no
2401643 | 0 Kelder | no
2401673 | 0 Kelder | no
2404598 | 0 Kelder | no

# IfcWallStandardCase: Basic Wall:SS-04 - loputuskast (96)
Type - PredefinedType: STANDARD; Material: EST. Põrand. Plaatkate 10 mm, EST. Ehitusplaat. Kipsplaat 12.5 mm, EST. Õhkvahe. Roov. Kipsplaadi alusroov. Vertikaalne 42 mm
Type - Pset_ConcreteElementGeneral - FireRating: -
Type - Pset_ElementShading - Roughness: 914.4 mm
Type - Pset_ProductRequirements - Category: Walls
Type - Pset_QuantityTakeOff - Reference: SS-04 - loputuskast
Type - Pset_ReinforcementBarPitchOfWall - Reference: SS-04 - loputuskast
Type - Pset_WallCommon - IsExternal: no; Combustible: yes; Reference: SS-04 - loputuskast; AcousticRating: -; FireRating: -
Pset_QuantityTakeOff - sets with these values: 2
Pset_WallCommon - LoadBearing: no
Name (Basic Wall:SS-04 - loputuskast:...) | In | ExtendToStructure
1081767 | 1 Korrus A | no
1081768 | 1 Korrus A | no
1094453 | 1 Korrus A | no
1094457 | 1 Korrus A | no
1162988 | 1 Korrus A | no
1176438 | 1 Korrus A | no
1181755 | 1 Korrus A | no
1181993 | 1 Korrus A | no
1182706 | 1 Korrus A | no
1182707 | 1 Korrus A | no
1182708 | 1 Korrus A | no
1182709 | 1 Korrus A | no
1182710 | 1 Korrus A | no
1182711 | 1 Korrus A | no
1183092 | 1 Korrus A | no
1183093 | 1 Korrus A | no
1184449 | 1 Korrus | no
1184981 | 2 Korrus | no
1184984 | 2 Korrus A | no
1184985 | 2 Korrus A | no
1184989 | 2 Korrus A | no
1184990 | 2 Korrus A | no
1184991 | 2 Korrus A | no
1184992 | 2 Korrus A | no
1184993 | 2 Korrus A | no
1184994 | 2 Korrus | no
1184995 | 2 Korrus A | no
1184996 | 2 Korrus A | no
1184997 | 2 Korrus A | no
1184998 | 2 Korrus A | no
1184999 | 2 Korrus A | no
1185000 | 2 Korrus A | no
1185001 | 2 Korrus A | no
1185002 | 2 Korrus A | no
1185003 | 2 Korrus A | no
1185004 | 2 Korrus A | no
1185006 | 2 Korrus | no
1185007 | 2 Korrus | yes
1185064 | 2 Korrus A | no
1185834 | 2 Korrus | no
1185836 | 2 Korrus A | no
1185837 | 2 Korrus | no
1186617 | 2 Korrus | no
1186618 | 2 Korrus A | no
1186683 | 1 Korrus | no
1186684 | 1 Korrus A | no
1186718 | 1 Korrus | no
1186719 | 1 Korrus A | no
1186720 | 1 Korrus | no
1187370 | 3 korrus | no
1187371 | 3 Korrus A | no
1189085 | 3 korrus | no
1189088 | 3 Korrus A | yes
1189089 | 3 Korrus A | yes
1189093 | 3 Korrus A | no
1189094 | 3 Korrus A | no
1189095 | 3 Korrus A | yes
1189096 | 3 Korrus A | no
1189098 | 3 korrus | no
1189099 | 3 Korrus A | yes
1189100 | 3 Korrus A | yes
1189101 | 3 Korrus A | yes
1189102 | 3 Korrus A | yes
1189103 | 3 Korrus A | no
1189104 | 3 Korrus A | no
1189105 | 3 Korrus A | yes
1189106 | 3 Korrus A | yes
1189107 | 3 Korrus A | no
1189108 | 3 Korrus A | yes
1189110 | 3 korrus | no
1189111 | 3 korrus | yes
1189112 | 3 Korrus A | no
1189113 | 3 korrus | no
1189115 | 3 korrus | no
1189455 | 3 Korrus A | no
1213746 | 1 Korrus | no
1215190 | 1 Korrus | no
1308665 | 0 Kelder | no
1728148 | 3 Korrus A | no
1769590 | 1 Korrus A | no
1948073 | 2 Korrus | no
1948074 | 2 Korrus A | no
1948178 | 3 korrus | no
1948179 | 3 Korrus A | no
2000658 | 0 Kelder | no
2000659 | 0 Kelder | no
2000660 | 0 Kelder | no
2000661 | 0 Kelder | no
2000662 | 0 Kelder | no
2000663 | 0 Kelder | no
2000664 | 0 Kelder | no
2000665 | 0 Kelder | no
2000666 | 0 Kelder | no
2000667 | 0 Kelder | no
2000668 | 0 Kelder | no
2000669 | 0 Kelder | no

# IfcWallStandardCase: Basic Wall:SS-05_Sauna sein (4)
In: 0 Kelder
Type - PredefinedType: STANDARD; Material: EST. Fassaadikate. Laudis. Vertikaalne. Default 15 mm, EST. Õhkvahe. Roov. Fassaadikatte alusroov. Vertikaalne 25 mm, EST. Soojustus. Mineraalvill. Default 25 mm
Type - Pset_ConcreteElementGeneral - FireRating: EI-60
Type - Pset_ElementShading - Roughness: 914.4 mm
Type - Pset_ProductRequirements - Category: Walls
Type - Pset_QuantityTakeOff - Reference: SS-05_Sauna sein
Type - Pset_ReinforcementBarPitchOfWall - Reference: SS-05_Sauna sein
Type - Pset_WallCommon - IsExternal: no; Combustible: no; Reference: SS-05_Sauna sein; AcousticRating: 52 dB; FireRating: EI-60
Pset_QuantityTakeOff - sets with these values: 2
Pset_WallCommon - ExtendToStructure: no; LoadBearing: no
Name (Basic Wall:SS-05_Sauna sein:...)
1004178
1004219
1004283
1004335

# IfcWallStandardCase: Basic Wall:SS-06_ 150mm (132)
Type - PredefinedType: STANDARD; Material: EST. Müüritis. Väikeplokk. Kergkruusplokk 150 mm
Type - Pset_ConcreteElementGeneral - FireRating: EI-60
Type - Pset_ElementShading - Roughness: 914.4 mm
Type - Pset_ProductRequirements - Category: Walls
Type - Pset_QuantityTakeOff - Reference: SS-06_ 150mm
Type - Pset_ReinforcementBarPitchOfWall - Reference: SS-06_ 150mm
Type - Pset_WallCommon - IsExternal: no; Combustible: yes; Reference: SS-06_ 150mm; AcousticRating: 42 dB; FireRating: EI-60
Pset_QuantityTakeOff - sets with these values: 2
Pset_WallCommon - LoadBearing: no
Name (Basic Wall:SS-06_ 150mm:...) | In | ExtendToStructure
914571 | 2 Korrus | no
914595 | 2 Korrus | no
914645 | 2 Korrus | no
914646 | 2 Korrus | no
917203 | 2 Korrus | no
918605 | 2 Korrus A | no
918646 | 2 Korrus A | no
918714 | 2 Korrus A | no
918757 | 2 Korrus A | no
918790 | 2 Korrus A | no
926678 | 2 Korrus A | no
926790 | 2 Korrus A | no
926791 | 2 Korrus A | no
926792 | 2 Korrus A | no
926793 | 2 Korrus A | no
926794 | 2 Korrus A | no
962566 | 1 Korrus A | no
964300 | 1 Korrus A | no
968995 | 2 Korrus A | no
969448 | 2 Korrus A | no
969479 | 2 Korrus A | no
980334 | 1 Korrus A | no
980389 | 1 Korrus A | no
980442 | 1 Korrus A | yes
980685 | 1 Korrus A | no
983448 | 2 Korrus A | no
983449 | 2 Korrus A | no
983450 | 2 Korrus A | no
983451 | 2 Korrus A | no
983598 | 3 Korrus A | yes
983599 | 3 Korrus A | yes
1000309 | 0 Kelder | no
1000510 | 0 Kelder | no
1000582 | 0 Kelder | no
1000688 | 0 Kelder | no
1000858 | 0 Kelder | no
1001352 | 0 Kelder | no
1002236 | 0 Kelder | no
1086820 | 1 Korrus A | no
1086821 | 1 Korrus A | no
1086822 | 1 Korrus A | no
1086823 | 1 Korrus A | no
1086825 | 1 Korrus A | no
1086826 | 1 Korrus A | no
1086827 | 1 Korrus A | no
1086828 | 1 Korrus A | no
1087757 | 1 Korrus A | no
1087758 | 1 Korrus A | no
1087759 | 1 Korrus A | no
1093840 | 3 Korrus A | yes
1093841 | 3 Korrus A | yes
1093842 | 3 Korrus A | yes
1093843 | 3 Korrus A | yes
1093844 | 3 Korrus A | no
1093851 | 3 Korrus A | no
1093852 | 3 Korrus A | yes
1093853 | 3 Korrus A | yes
1093854 | 3 Korrus A | yes
1093855 | 3 Korrus A | no
1093874 | 3 Korrus A | yes
1093875 | 3 Korrus A | yes
1093876 | 3 Korrus A | no
1097768 | 3 korrus | yes
1097769 | 3 korrus | yes
1097770 | 3 korrus | yes
1097771 | 3 korrus | yes
1097772 | 3 korrus | yes
1134004 | 3 korrus | yes
1134006 | 3 korrus | yes
1149766 | 1 Korrus | no
1149767 | 1 Korrus | no
1149768 | 1 Korrus | no
1165597 | 2 Korrus | no
1165606 | 2 Korrus | no
1165641 | 2 Korrus | no
1165642 | 2 Korrus | no
1165643 | 2 Korrus | no
1189212 | 3 Korrus A | yes
1189213 | 3 Korrus A | yes
1718018 | 3 korrus | yes
1718019 | 3 korrus | yes
1718020 | 3 korrus | yes
1726820 | 2 Korrus A | no
1726821 | 2 Korrus A | no
1742638 | 3 Korrus A | no
1742639 | 3 Korrus A | no
1742646 | 1 Korrus A | no
1742647 | 1 Korrus A | no
1754861 | 1 Korrus A | no
1771519 | 2 Korrus A | no
1771605 | 3 Korrus A | yes
1800113 | Katus | no
1800114 | Katus | no
1800115 | Katus | no
1800116 | Katus | no
1800117 | Katus | no
1800118 | Katus | no
1800119 | Katus | no
1800120 | Katus | no
1800121 | Katus | no
1800122 | Katus | no
1800123 | Katus | no
1800124 | Katus | no
1800125 | Katus | no
1800126 | Katus | no
1800127 | Katus | no
1800128 | 3 Korrus A | no
1800129 | 3 Korrus A | no
1800130 | 3 Korrus A | no
1800131 | 3 Korrus A | no
1800132 | 3 Korrus A | no
1800133 | 3 Korrus A | no
1800134 | 3 Korrus A | no
1800135 | Katus | no
1800136 | Katus | no
1800138 | 3 Korrus A | no
1800139 | 3 Korrus A | no
1800140 | 3 Korrus A | no
1800236 | Katus | no
1801576 | Katus | no
1801577 | Katus | no
1801578 | Katus | no
1801579 | Katus | no
1801656 | 3 Korrus A | no
1801657 | 3 Korrus A | no
1801658 | 3 Korrus A | no
1801751 | 3 Korrus A | no
1801887 | 3 Korrus A | no
1801888 | 3 Korrus A | no
1801889 | 3 Korrus A | no
1801890 | 3 Korrus A | no
2090680 | 3 korrus | no

# IfcWallStandardCase: Basic Wall:SS-07_ 150mm Fobo 5 (6)
In: 0 Kelder
Type - PredefinedType: STANDARD; Material: EST. Müüritis. Väikeplokk. Betoon-õõnesplokk 150 mm
Type - Pset_ConcreteElementGeneral - FireRating: EI-60
Type - Pset_ElementShading - Roughness: 914.4 mm
Type - Pset_ProductRequirements - Category: Walls
Type - Pset_QuantityTakeOff - Reference: SS-07_ 150mm Fobo 5
Type - Pset_ReinforcementBarPitchOfWall - Reference: SS-07_ 150mm Fobo 5
Type - Pset_WallCommon - IsExternal: no; Combustible: yes; Reference: SS-07_ 150mm Fobo 5; AcousticRating: 56 dB; FireRating: EI-60
Pset_QuantityTakeOff - sets with these values: 2
Pset_WallCommon - LoadBearing: no
Name (Basic Wall:SS-07_ 150mm Fobo 5:...) | ExtendToStructure
999737 | no
999797 | no
1000167 | yes
1000928 | no
1147432 | no
1147556 | no

# IfcWallStandardCase: Basic Wall:SS-08_Kips, 66mm metallkarkass 3 (7)
Type - PredefinedType: STANDARD; Material: EST. Ehitusplaat. Kipsplaat 12.5 mm, EST. Ehitusplaat. Kipsplaat 12.5 mm, EST. Õhkvahe. Default 150 mm, EST. Õhkvahe. Default 10 mm, EST. Õhkvahe. Roov. Kipsplaadi alusroov. Vertikaalne 66 mm, EST. Ehitusplaat. Kipsplaat 12.5 mm, EST. Ehitusplaat. Kipsplaat 12.5 mm
Type - Pset_ConcreteElementGeneral - FireRating: EI-60
Type - Pset_ElementShading - Roughness: 914.4 mm
Type - Pset_ProductRequirements - Category: Walls
Type - Pset_QuantityTakeOff - Reference: SS-08_Kips, 66mm metallkarkass 3
Type - Pset_ReinforcementBarPitchOfWall - Reference: SS-08_Kips, 66mm metallkarkass 3
Type - Pset_WallCommon - IsExternal: no; Combustible: no; Reference: SS-08_Kips, 66mm metallkarkass 3; AcousticRating: 48dB; FireRating: EI-60
Pset_QuantityTakeOff - sets with these values: 2
Pset_WallCommon - LoadBearing: no
Name (Basic Wall:SS-08_Kips, 66mm metallkarkass 3:...) | In | ExtendToStructure
1131380 | 3 korrus | yes
1133887 | 3 korrus | yes
1165620 | 2 Korrus | no
1165636 | 2 Korrus | no
1756236 | 3 Korrus A | no
1758409 | 2 Korrus A | no
1759331 | 1 Korrus A | no

# IfcWallStandardCase: Basic Wall:SS-09_Kips, 66mm metallkarkass 4, Basic Wall:SS-09_Kips, 66mm metallkarkass 4:1770930
In: 1 Korrus
Type - PredefinedType: STANDARD; Material: EST. Ehitusplaat. Kipsplaat 12.5 mm, EST. Ehitusplaat. Kipsplaat 12.5 mm, EST. Õhkvahe. Roov. Kipsplaadi alusroov. Vertikaalne 160 mm, EST. Õhkvahe. Default 10 mm, EST. Õhkvahe. Roov. Kipsplaadi alusroov. Vertikaalne 66 mm, EST. Ehitusplaat. OSB 12 mm, EST. Ehitusplaat. Kipsplaat 12.5 mm, EST. Ehitusplaat. Kipsplaat 12.5 mm
Type - Pset_ConcreteElementGeneral - FireRating: EI-60
Type - Pset_ElementShading - Roughness: 914.4 mm
Type - Pset_ProductRequirements - Category: Walls
Type - Pset_QuantityTakeOff - Reference: SS-09_Kips, 66mm metallkarkass 4
Type - Pset_ReinforcementBarPitchOfWall - Reference: SS-09_Kips, 66mm metallkarkass 4
Type - Pset_WallCommon - IsExternal: no; Combustible: no; Reference: SS-09_Kips, 66mm metallkarkass 4; AcousticRating: 52 dB; FireRating: EI-60
Pset_QuantityTakeOff - sets with these values: 2
Pset_WallCommon - ExtendToStructure: no; LoadBearing: no

# IfcWallStandardCase: Basic Wall:VS-00_200mm EPS+ SBS (2)
In: Katus
Type - PredefinedType: STANDARD; Material: EST. Katusekate. Rullmaterjal. SBS 1 mm, EST. Ehitusplaat. Vineer. Veekindel 15 mm, EST. Õhkvahe. Roov. Fassaadikatte alusroov. Horisontaalne 25 mm, EST. Soojustus. Mineraalvill. Default 250 mm
Type - Pset_ElementShading - Roughness: 914.4 mm
Type - Pset_ProductRequirements - Category: Walls
Type - Pset_QuantityTakeOff - Reference: VS-00_200mm EPS+ SBS
Type - Pset_ReinforcementBarPitchOfWall - Reference: VS-00_200mm EPS+ SBS
Type - Pset_WallCommon - IsExternal: yes; Combustible: no; Reference: VS-00_200mm EPS+ SBS
Pset_QuantityTakeOff - sets with these values: 2
Pset_WallCommon - ExtendToStructure: no; LoadBearing: no
Name (Basic Wall:VS-00_200mm EPS+ SBS:...)
1801181
1804744

# IfcWallStandardCase: Basic Wall:VS-00_200mm EPS+ krohv (39)
Type - PredefinedType: STANDARD; Material: EST. Fassaadikate. Krohv. Valge 1 mm, EST. Soojustus. Mineraalvill. Default 250 mm
Type - Pset_ElementShading - Roughness: 914.4 mm
Type - Pset_ProductRequirements - Category: Walls
Type - Pset_QuantityTakeOff - Reference: VS-00_200mm EPS+ krohv
Type - Pset_ReinforcementBarPitchOfWall - Reference: VS-00_200mm EPS+ krohv
Type - Pset_WallCommon - IsExternal: yes; Combustible: no; Reference: VS-00_200mm EPS+ krohv
Pset_QuantityTakeOff - sets with these values: 2
Pset_WallCommon - ExtendToStructure: no; LoadBearing: no
Name (Basic Wall:VS-00_200mm EPS+ krohv:...) | In
945230 | 2 Korrus
952564 | 2 Korrus
952566 | 2 Korrus
952575 | 3 korrus
952577 | 3 korrus
954586 | 2 Korrus A
954591 | 2 Korrus A
954594 | 2 Korrus A
954596 | 2 Korrus
954816 | 3 Korrus A
954817 | 3 Korrus A
955585 | 3 korrus
973296 | 0 Kelder
974121 | Katus
974419 | Katus
1014077 | 0 Kelder
1014380 | 0 Kelder
1014674 | 0 Kelder
1014717 | 0 Kelder
1014764 | 0 Kelder
1014813 | 0 Kelder
1014964 | 0 Kelder
1015034 | 0 Kelder
1015087 | 0 Kelder
1015130 | 0 Kelder
1015171 | 0 Kelder
1015254 | 0 Kelder
1015317 | 0 Kelder
1015351 | 0 Kelder
1015429 | 0 Kelder
1015464 | 0 Kelder
1015526 | 0 Kelder
1023499 | Katus
1023535 | Katus
1658669 | 2 Korrus
1662527 | 2 Korrus
1662668 | 2 Korrus
1664789 | 3 korrus
1804730 | Katus

# IfcWallStandardCase: Basic Wall:VS-00_200mm EPS+ krohv pinnases (2)
In: 0 Kelder
Type - PredefinedType: STANDARD; Material: EST. Fassaadikate. Krohv. Valge 1 mm, EST. Soojustus. Mineraalvill. Default 250 mm
Type - Pset_ElementShading - Roughness: 914.4 mm
Type - Pset_ProductRequirements - Category: Walls
Type - Pset_QuantityTakeOff - Reference: VS-00_200mm EPS+ krohv pinnases
Type - Pset_ReinforcementBarPitchOfWall - Reference: VS-00_200mm EPS+ krohv pinnases
Type - Pset_WallCommon - IsExternal: yes; Combustible: no; Reference: VS-00_200mm EPS+ krohv pinnases
Pset_QuantityTakeOff - sets with these values: 2
Pset_WallCommon - ExtendToStructure: no; LoadBearing: no
Name (Basic Wall:VS-00_200mm EPS+ krohv pinnases:...)
1148075
1319236

# IfcWallStandardCase: Basic Wall:VS-01_Puitkonstruktsioon 2 (4)
In: 1 Korrus
Type - PredefinedType: STANDARD; Material: EST. Fassaadikate. Laudis. Horisontaalne. Default 16 mm, EST. Õhkvahe. Roov. Fassaadikatte alusroov. Vertikaalne 25 mm, EST. Tuuletõke. Kipsplaat 30 mm, EST. Soojustus. Mineraalvill. Default 195 mm
Type - Pset_ElementShading - Roughness: 914.4 mm
Type - Pset_ProductRequirements - Category: Walls
Type - Pset_QuantityTakeOff - Reference: VS-01_Puitkonstruktsioon 2
Type - Pset_ReinforcementBarPitchOfWall - Reference: VS-01_Puitkonstruktsioon 2
Type - Pset_WallCommon - Combustible: yes; IsExternal: yes; Reference: VS-01_Puitkonstruktsioon 2
Pset_QuantityTakeOff - sets with these values: 2
Pset_WallCommon - ExtendToStructure: no; LoadBearing: no
Name (Basic Wall:VS-01_Puitkonstruktsioon 2:...)
943836
944282
944859
1664418

# IfcWallStandardCase: Basic Wall:VS-01_Puitkonstruktsioon 368mm (19)
Type - PredefinedType: STANDARD; Material: EST. Fassaadikate. Laudis. Horisontaalne. Default 16 mm, EST. Õhkvahe. Roov. Fassaadikatte alusroov. Vertikaalne 25 mm, EST. Tuuletõke. Kipsplaat 30 mm, EST. Soojustus. Mineraalvill. Default 195 mm, EST. Soojustus. Mineraalvill. Default 66 mm, EST. Ehitusplaat. Kipsplaat 15 mm, EST. Ehitusplaat. Kipsplaat 15 mm
Type - Pset_ElementShading - Roughness: 914.4 mm
Type - Pset_ProductRequirements - Category: Walls
Type - Pset_QuantityTakeOff - Reference: VS-01_Puitkonstruktsioon 368mm
Type - Pset_ReinforcementBarPitchOfWall - Reference: VS-01_Puitkonstruktsioon 368mm
Type - Pset_WallCommon - Reference: VS-01_Puitkonstruktsioon 368mm; Combustible: yes; IsExternal: yes
Pset_QuantityTakeOff - sets with these values: 2
Pset_WallCommon - ExtendToStructure: no; LoadBearing: no
Name (Basic Wall:VS-01_Puitkonstruktsioon 368mm:...) | In
847633 | 1 Korrus A
847634 | 2 Korrus A
847635 | 2 Korrus A
847641 | 1 Korrus A
847646 | 2 Korrus A
847647 | 2 Korrus A
847728 | 3 Korrus A
847777 | 3 Korrus A
847820 | 3 Korrus A
952563 | 2 Korrus
952565 | 2 Korrus
952574 | 3 korrus
952576 | 3 korrus
1662477 | 2 Korrus
1662647 | 2 Korrus
1663537 | 3 Korrus A
1663613 | 3 Korrus A
1664330 | 3 korrus
1664658 | 3 korrus

# IfcWallStandardCase: Basic Wall:VS-04_200mm EPS+ krohv (41)
Type - PredefinedType: STANDARD; Material: EST. Fassaadikate. Krohv. Valge 1 mm, EST. Soojustus. Mineraalvill. Default 250 mm
Type - Pset_ElementShading - Roughness: 914.4 mm
Type - Pset_ProductRequirements - Category: Walls
Type - Pset_QuantityTakeOff - Reference: VS-04_200mm EPS+ krohv
Type - Pset_ReinforcementBarPitchOfWall - Reference: VS-04_200mm EPS+ krohv
Type - Pset_WallCommon - IsExternal: yes; Combustible: no; Reference: VS-04_200mm EPS+ krohv
Pset_QuantityTakeOff - sets with these values: 2
Pset_WallCommon - ExtendToStructure: no; LoadBearing: no
Name (Basic Wall:VS-04_200mm EPS+ krohv:...) | In
937040 | 1 Korrus
937461 | 1 Korrus
937496 | 1 Korrus
937714 | 1 Korrus A
938431 | 1 Korrus
938499 | 1 Korrus
939557 | 1 Korrus A
939728 | 1 Korrus A
939773 | 1 Korrus A
940051 | 1 Korrus A
940184 | 1 Korrus A
941229 | 1 Korrus A
944107 | 1 Korrus
944309 | 1 Korrus
944860 | 1 Korrus
944862 | 1 Korrus
954052 | 2 Korrus
954585 | 2 Korrus
954587 | 2 Korrus
954588 | 2 Korrus
954590 | 2 Korrus A
954593 | 2 Korrus A
954595 | 2 Korrus A
954807 | 3 korrus
954808 | 3 Korrus A
954809 | 3 korrus
954810 | 3 korrus
954811 | 3 korrus
954812 | 3 Korrus A
954813 | 3 Korrus A
954814 | 3 Korrus A
954815 | 3 Korrus A
956954 | 3 korrus
956956 | 3 korrus
1014013 | 0 Kelder
1014461 | 0 Kelder
1050455 | 2 Korrus A
1609967 | 1 Korrus
1658666 | 1 Korrus
1658672 | 3 korrus
1659808 | 1 Korrus

# IfcWallStandardCase: Basic Wall:VS-07_Puitkonstruktsioon, Basic Wall:VS-07_Puitkonstruktsioon:1122215
In: 2 Korrus A
Type - PredefinedType: STANDARD; Material: EST. Fassaadikate. Laudis. Horisontaalne. Default 16 mm, EST. Õhkvahe. Roov. Fassaadikatte alusroov. Vertikaalne 25 mm, EST. Tuuletõke. Kipsplaat 30 mm, EST. Soojustus. Mineraalvill. Default 195 mm
Type - Pset_ElementShading - Roughness: 914.4 mm
Type - Pset_ProductRequirements - Category: Walls
Type - Pset_QuantityTakeOff - Reference: VS-07_Puitkonstruktsioon
Type - Pset_ReinforcementBarPitchOfWall - Reference: VS-07_Puitkonstruktsioon
Type - Pset_WallCommon - Combustible: yes; IsExternal: yes; Reference: VS-07_Puitkonstruktsioon
Pset_QuantityTakeOff - sets with these values: 2
Pset_WallCommon - ExtendToStructure: no; LoadBearing: no

# IfcWallStandardCase: Basic Wall:Varikatus (4)
In: 1 Korrus
Type - PredefinedType: STANDARD; Material: EST. Puit. Ehituspuit 100 mm, EST. Ehitusplaat. Tsementkiudplaat 8 mm
Type - Pset_ElementShading - Roughness: 914.4 mm
Type - Pset_ProductRequirements - Category: Walls
Type - Pset_QuantityTakeOff - Reference: Varikatus
Type - Pset_ReinforcementBarPitchOfWall - Reference: Varikatus
Type - Pset_WallCommon - IsExternal: no; Reference: Varikatus
Pset_QuantityTakeOff - sets with these values: 2
Pset_WallCommon - ExtendToStructure: no; LoadBearing: no
Name (Basic Wall:Varikatus:...)
1603227
1603335
1642108
1642167

# IfcWallStandardCase: Basic Wall:äärekivi (133)
In: 1 Korrus
Type - PredefinedType: STANDARD; Material: valge 100 mm
Type - Pset_ElementShading - Roughness: 914.4 mm
Type - Pset_ProductRequirements - Category: Walls
Type - Pset_QuantityTakeOff - Reference: äärekivi
Type - Pset_ReinforcementBarPitchOfWall - Reference: äärekivi
Type - Pset_WallCommon - IsExternal: no; Reference: äärekivi
Pset_QuantityTakeOff - sets with these values: 2
Pset_WallCommon - ExtendToStructure: no; LoadBearing: no; IsExternal: yes
Name (Basic Wall:äärekivi:...)
1042245
1042249
1042253
1042262
1042266
1042270
1042274
1042278
1042282
1042286
1042290
1042294
1042298
1042302
1042306
1042310
1042314
1042318
1042322
1042326
1042330
1042334
1042338
1042342
1042346
1042350
1042354
1042358
1042362
1042366
1042370
1042374
1042378
1042382
1042386
1042390
1042394
1042398
1042402
1042406
1042410
1042414
1042418
1042422
1042426
1042678
1042679
1042784
1042785
1042786
1042787
1042788
1042789
1042790
1042791
1042792
1042793
1042794
1042795
1042796
1042797
1042798
1042799
1042800
1042801
1042802
1042805
1042806
1042808
1042809
1042811
1042818
1042819
1042820
1042821
1042823
1042824
1042825
1042826
1042827
1042828
1042829
1042830
1042831
1042832
1042833
1042834
1042835
1042836
1042837
1042838
1042839
1042840
1042887
1042888
1042889
1042890
1042891
1042892
1042893
1042894
1042895
1042896
1042897
1045187
1045191
1045195
1045199
1045203
1045207
1045211
1045263
1045267
1045271
1045275
1045279
1045283
1045287
1045291
1045295
1045299
1045303
1045307
1045311
1045315
1045319
1045323
1045327
1046314
1047096
1047300
1226471
2249974

# IfcWindow: 1.0 W - 2x2:-A-03 (7)
Type - ParameterTakesPrecedence: no; Sizeable: no; Material: <Unnamed> (2), EST. Metall. Alumiinium. Värvitud. RAL7023 (Concrete grey), __Metal Tumehall, Glass
Type - Pset_ProductRequirements - Category: Windows
Type - Pset_QuantityTakeOff - Reference: -A-03
Type - Pset_WindowCommon - IsExternal: no; Reference: -A-03; FireRating: -; AcousticRating: 35 dB
OverallHeight: 2500 mm; OverallWidth: 2000 mm; Material: EST. Metall. Alumiinium. Värvitud. RAL7023 (Concrete grey), Glass, __Metal Tumehall
Name (1.0 W - 2x2:-A-03:...) | In | Reference | sets with these values
952567 | 2 Korrus | -A-03 | 2
952578 | 3 korrus | -A-03 | 2
973951 | 2 Korrus | Pset_WindowCommon - IsExternal: yes
975865 | 1 Korrus A | Pset_WindowCommon - IsExternal: yes
989612 | 2 Korrus A | -A-03 | 2
989630 | 3 Korrus A | -A-03 | 2
1664915 | 3 korrus | -A-03 | 2

# IfcWindow: 1.0 W - 2x2:-A-03 (20)
Type - ParameterTakesPrecedence: no; Sizeable: no; Material: <Unnamed> (2), Glass, __Metal Tumehall, EST. Metall. Alumiinium. Värvitud. RAL7023 (Concrete grey)
Type - Pset_ProductRequirements - Category: Windows
Type - Pset_QuantityTakeOff - Reference: -A-03
Type - Pset_WindowCommon - IsExternal: no; Reference: -A-03; FireRating: -; AcousticRating: 35 dB
OverallHeight: 2500 mm; OverallWidth: 2000 mm; Material: EST. Metall. Alumiinium. Värvitud. RAL7023 (Concrete grey), Glass, __Metal Tumehall
Name (1.0 W - 2x2:-A-03:...) | In
955709 | 2 Korrus | Pset_OpeningElementCommon - Reference: -A-03; sets with these values: 2
955711 | 3 korrus | Pset_OpeningElementCommon - Reference: -A-03; sets with these values: 2
968525 | 2 Korrus A | Pset_OpeningElementCommon - Reference: -A-03; sets with these values: 2
968599 | 2 Korrus A | Pset_OpeningElementCommon - Reference: -A-03; sets with these values: 2
972651 | 3 Korrus A | Pset_WindowCommon - IsExternal: yes
972694 | 1 Korrus A | Pset_WindowCommon - IsExternal: yes
972695 | 1 Korrus A | Pset_WindowCommon - IsExternal: yes
973901 | 1 Korrus | Pset_WindowCommon - IsExternal: yes
973950 | 2 Korrus | Pset_WindowCommon - IsExternal: yes
975582 | 1 Korrus A | Pset_WindowCommon - IsExternal: yes
975912 | 1 Korrus A | Pset_WindowCommon - IsExternal: yes
976033 | 1 Korrus A | Pset_WindowCommon - IsExternal: yes
989475 | 2 Korrus A | Pset_WindowCommon - IsExternal: yes
989613 | 2 Korrus A | Pset_OpeningElementCommon - Reference: -A-03; sets with these values: 2
989614 | 2 Korrus A | Pset_OpeningElementCommon - Reference: -A-03; sets with these values: 2
989631 | 3 Korrus A | Pset_OpeningElementCommon - Reference: -A-03; sets with these values: 2
989632 | 3 Korrus A | Pset_OpeningElementCommon - Reference: -A-03; sets with these values: 2
989668 | 3 Korrus A | Pset_WindowCommon - IsExternal: yes
1663614 | 3 Korrus A | Pset_OpeningElementCommon - Reference: -A-03; sets with these values: 2
1664914 | 3 korrus | Pset_OpeningElementCommon - Reference: -A-03; sets with these values: 2

# IfcWindow: 1.0 W - 2x2:-A-03, 1.0 W - 2x2:-A-03:1664419
In: 1 Korrus
Type - ParameterTakesPrecedence: no; Sizeable: no; Material: EST. Metall. Alumiinium. Värvitud. RAL7023 (Concrete grey), <Unnamed> (2), __Metal Tumehall, Glass
Type - Pset_ProductRequirements - Category: Windows
Type - Pset_QuantityTakeOff - Reference: -A-03
Type - Pset_WindowCommon - IsExternal: no; Reference: -A-03; FireRating: -; AcousticRating: 35 dB
OverallHeight: 2500 mm; OverallWidth: 2000 mm; Material: EST. Metall. Alumiinium. Värvitud. RAL7023 (Concrete grey), Glass, __Metal Tumehall
Pset_OpeningElementCommon - Reference: -A-03; sets with these values: 2

# IfcWindow: SMA_W1, 1-jaotus:-A-05_1200x1500mm (2)
In: 2 Korrus
Type - ParameterTakesPrecedence: no; Sizeable: no; Material: <Unnamed> (2), EST. Metall. Alumiinium. Värvitud. RAL7023 (Concrete grey), Glass
Type - Pset_ProductRequirements - Category: Windows
Type - Pset_QuantityTakeOff - Reference: -A-05_1200x1500mm
Type - Pset_WindowCommon - IsExternal: no; Reference: -A-05_1200x1500mm; FireRating: EI-60; AcousticRating: 35 dB
OverallHeight: 1500 mm; OverallWidth: 1200 mm; Material: EST. Metall. Alumiinium. Värvitud. RAL7023 (Concrete grey), Glass
Pset_WindowCommon - IsExternal: yes
Name (SMA_W1, 1-jaotus:-A-05_1200x1500mm:...)
852345
954582

# IfcWindow: SMA_W1, 1-jaotus:-A-05_1200x1500mm (7)
Type - ParameterTakesPrecedence: no; Sizeable: no; Material: Glass, EST. Metall. Alumiinium. Värvitud. RAL7023 (Concrete grey), <Unnamed> (2)
Type - Pset_ProductRequirements - Category: Windows
Type - Pset_QuantityTakeOff - Reference: -A-05_1200x1500mm
Type - Pset_WindowCommon - IsExternal: no; Reference: -A-05_1200x1500mm; FireRating: EI-60; AcousticRating: 35 dB
OverallHeight: 1500 mm; OverallWidth: 1200 mm; Material: EST. Metall. Alumiinium. Värvitud. RAL7023 (Concrete grey), Glass
Name (SMA_W1, 1-jaotus:-A-05_1200x1500mm:...) | In | Reference | sets with these values
852346 | 2 Korrus | -A-05_1200x1500mm | 2
956955 | 3 korrus | -A-05_1200x1500mm | 2
989701 | 3 korrus | -A-05_1200x1500mm | 2
989775 | 3 korrus | -A-05_1200x1500mm | 2
989881 | 3 korrus | -A-05_1200x1500mm | 2
1659807 | 1 Korrus | Pset_WindowCommon - IsExternal: yes
2293718 | 2 Korrus | -A-05_1200x1500mm | 2

# IfcWindow: SMA_W1, 1-jaotus:SA-05_1200x1500mm EI-30, SMA_W1, 1-jaotus:SA-05_1200x1500mm EI-30:847695
In: 1 Korrus
Type - ParameterTakesPrecedence: no; Sizeable: no; Material: <Unnamed> (2), EST. Metall. Alumiinium. Värvitud. RAL7023 (Concrete grey), Glass
Type - Pset_ProductRequirements - Category: Windows
Type - Pset_QuantityTakeOff - Reference: SA-05_1200x1500mm EI-30
Type - Pset_WindowCommon - IsExternal: no; Reference: SA-05_1200x1500mm EI-30; FireRating: EI-30; AcousticRating: 35 dB
OverallHeight: 1500 mm; OverallWidth: 1200 mm; Material: EST. Metall. Alumiinium. Värvitud. RAL7023 (Concrete grey), Glass

# IfcWindow: SMA_katuseluuk 1, kuppel:LU-01 - 1200 x 1200, SMA_katuseluuk 1, kuppel:LU-01 - 1200 x 1200:1292210
In: Katus A
Type - ParameterTakesPrecedence: no; Sizeable: no; Material: <Unnamed> (6)
Type - Pset_ProductRequirements - Category: Windows
Type - Pset_QuantityTakeOff - Reference: LU-01 - 1200 x 1200
Type - Pset_WindowCommon - IsExternal: no; Reference: LU-01 - 1200 x 1200
OverallHeight: 1196.66 mm; OverallWidth: 1200 mm
Pset_WindowCommon - IsExternal: yes

# IfcWindow: SMA_katuseluuk 1, kuppel:LU-01 - 1200 x 1800, SMA_katuseluuk 1, kuppel:LU-01 - 1200 x 1800:1292253
In: Katus A
Type - ParameterTakesPrecedence: no; Sizeable: no; Material: <Unnamed> (6)
Type - Pset_ProductRequirements - Category: Windows
Type - Pset_QuantityTakeOff - Reference: LU-01 - 1200 x 1800
Type - Pset_WindowCommon - IsExternal: no; Reference: LU-01 - 1200 x 1800
OverallHeight: 1306.66 mm; OverallWidth: 1800 mm
Pset_WindowCommon - IsExternal: yes

# IfcWindow: Schueco_FWS_AWS-75-SI+_inw_Family-01:FWS SI insert unit (3)
In: 2 Korrus
Type - ConstructionType: OTHER_CONSTRUCTION; ParameterTakesPrecedence: no; Sizeable: no; Material: __Metal Tumehall (2), <Unnamed> (2), Glass
Type - Pset_ManufacturerTypeInformation - Manufacturer: Schueco International KG
Type - Pset_ProductRequirements - Category: Windows
Type - Pset_QuantityTakeOff - Reference: FWS SI insert unit
Type - Pset_WindowCommon - IsExternal: no; Reference: FWS SI insert unit
Material: __Metal Tumehall, Glass
Pset_WindowCommon - IsExternal: yes
Name (Schueco_FWS_AWS-75-SI+_inw_Family-01:FWS SI insert unit:...) | OverallHeight (mm) | OverallWidth (mm)
1040216 | 1641.29 | 1108
939565 | 671.286 | 1153
1038832 | 1488 | 1153

# IfcWindow: Schueco_FWS_AWS-75-SI+_inw_Family-01:FWS SI insert unit (3)
In: 2 Korrus
Type - ConstructionType: OTHER_CONSTRUCTION; ParameterTakesPrecedence: no; Sizeable: no; Material: __Metal Tumehall (2), Glass, <Unnamed> (2)
Type - Pset_ManufacturerTypeInformation - Manufacturer: Schueco International KG
Type - Pset_ProductRequirements - Category: Windows
Type - Pset_QuantityTakeOff - Reference: FWS SI insert unit
Type - Pset_WindowCommon - IsExternal: no; Reference: FWS SI insert unit
Material: __Metal Tumehall, Glass
Pset_WindowCommon - IsExternal: yes
Name (Schueco_FWS_AWS-75-SI+_inw_Family-01:FWS SI insert unit:...) | OverallHeight (mm) | OverallWidth (mm)
859216 | 671.286 | 1108
1040373 | 1488 | 1108
1038959 | 1641.29 | 1153

# IfcWindow: sma_W3:-A-01 2700x1500mm (12)
Type - ParameterTakesPrecedence: no; Sizeable: no; Material: <Unnamed> (2), EST. Metall. Alumiinium. Värvitud. RAL7023 (Concrete grey), __Metal Tumehall, Glass
Type - Pset_ProductRequirements - Category: Windows
Type - Pset_QuantityTakeOff - Reference: -A-01 2700x1500mm
Type - Pset_WindowCommon - IsExternal: no; Reference: -A-01 2700x1500mm; FireRating: -; AcousticRating: 35 dB
OverallHeight: 1400 mm; OverallWidth: 2700 mm; Material: Glass, EST. Metall. Alumiinium. Värvitud. RAL7023 (Concrete grey), __Metal Tumehall
Name (sma_W3:-A-01 2700x1500mm:...) | In | Reference | sets with these values
847629 | 1 Korrus A | -A-01 2700x1500mm | 2
847653 | 1 Korrus A | -A-01 2700x1500mm | 2
847707 | 1 Korrus A | Pset_WindowCommon - IsExternal: yes
952186 | 1 Korrus | Pset_WindowCommon - IsExternal: yes
954578 | 2 Korrus A | Pset_WindowCommon - IsExternal: yes
954805 | 3 Korrus A | -A-01 2700x1500mm | 2
989662 | 3 Korrus A | -A-01 2700x1500mm | 2
989664 | 3 Korrus A | -A-01 2700x1500mm | 2
1658664 | 1 Korrus | -A-01 2700x1500mm | 2
1658665 | 1 Korrus | -A-01 2700x1500mm | 2
1658670 | 3 korrus | -A-01 2700x1500mm | 2
1658671 | 3 korrus | -A-01 2700x1500mm | 2

# IfcWindow: sma_W3:-A-01 2700x1500mm (4)
Type - ParameterTakesPrecedence: no; Sizeable: no; Material: <Unnamed> (2), Glass, EST. Metall. Alumiinium. Värvitud. RAL7023 (Concrete grey), __Metal Tumehall
Type - Pset_ProductRequirements - Category: Windows
Type - Pset_QuantityTakeOff - Reference: -A-01 2700x1500mm
Type - Pset_WindowCommon - IsExternal: no; Reference: -A-01 2700x1500mm; FireRating: -; AcousticRating: 35 dB
OverallHeight: 1400 mm; OverallWidth: 2700 mm; Material: Glass, EST. Metall. Alumiinium. Värvitud. RAL7023 (Concrete grey), __Metal Tumehall
Name (sma_W3:-A-01 2700x1500mm:...) | In | Reference | sets with these values
954580 | 2 Korrus A | Pset_WindowCommon - IsExternal: yes
954583 | 2 Korrus A | -A-01 2700x1500mm | 2
1658667 | 2 Korrus | -A-01 2700x1500mm | 2
1658668 | 2 Korrus | -A-01 2700x1500mm | 2

# IfcWindow: sma_W3:-A-01 2700x1500mm (10)
Type - ParameterTakesPrecedence: no; Sizeable: no; Material: <Unnamed> (2), __Metal Tumehall, Glass, EST. Metall. Alumiinium. Värvitud. RAL7023 (Concrete grey)
Type - Pset_ProductRequirements - Category: Windows
Type - Pset_QuantityTakeOff - Reference: -A-01 2700x1500mm
Type - Pset_WindowCommon - IsExternal: no; Reference: -A-01 2700x1500mm; FireRating: -; AcousticRating: 35 dB
OverallHeight: 1400 mm; OverallWidth: 2700 mm; Material: Glass, EST. Metall. Alumiinium. Värvitud. RAL7023 (Concrete grey), __Metal Tumehall
Name (sma_W3:-A-01 2700x1500mm:...) | In | Reference | sets with these values
847648 | 1 Korrus A | -A-01 2700x1500mm | 2
847654 | 1 Korrus A | -A-01 2700x1500mm | 2
847677 | 1 Korrus | Pset_WindowCommon - IsExternal: yes
936873 | 1 Korrus A | -A-01 2700x1500mm | 2
945273 | 3 korrus | -A-01 2700x1500mm | 2
945274 | 3 korrus | -A-01 2700x1500mm | 2
954579 | 2 Korrus A | Pset_WindowCommon - IsExternal: yes
954806 | 3 Korrus A | -A-01 2700x1500mm | 2
989663 | 3 Korrus A | -A-01 2700x1500mm | 2
989665 | 3 Korrus A | -A-01 2700x1500mm | 2

# IfcWindow: sma_W3:-A-01 2700x1500mm (4)
Type - ParameterTakesPrecedence: no; Sizeable: no; Material: Glass, <Unnamed> (2), EST. Metall. Alumiinium. Värvitud. RAL7023 (Concrete grey), __Metal Tumehall
Type - Pset_ProductRequirements - Category: Windows
Type - Pset_QuantityTakeOff - Reference: -A-01 2700x1500mm
Type - Pset_WindowCommon - IsExternal: no; Reference: -A-01 2700x1500mm; FireRating: -; AcousticRating: 35 dB
OverallHeight: 1400 mm; OverallWidth: 2700 mm; Material: Glass, EST. Metall. Alumiinium. Värvitud. RAL7023 (Concrete grey), __Metal Tumehall
Name (sma_W3:-A-01 2700x1500mm:...) | In | Reference | sets with these values
945228 | 2 Korrus | -A-01 2700x1500mm | 2
945229 | 2 Korrus | -A-01 2700x1500mm | 2
954581 | 2 Korrus A | Pset_WindowCommon - IsExternal: yes
954584 | 2 Korrus A | -A-01 2700x1500mm | 2

# IfcWindow: sma_W3:-A-02 2000x1200mm (2)
In: 0 Kelder
Type - ParameterTakesPrecedence: no; Sizeable: no; Material: <Unnamed> (2), __Metal Tumehall, EST. Metall. Alumiinium. Värvitud. RAL7023 (Concrete grey), Glass
Type - Pset_ProductRequirements - Category: Windows
Type - Pset_QuantityTakeOff - Reference: -A-02 2000x1200mm
Type - Pset_WindowCommon - IsExternal: no; Reference: -A-02 2000x1200mm; FireRating: -; AcousticRating: 35 dB
OverallHeight: 1200 mm; OverallWidth: 2000 mm; Material: Glass, EST. Metall. Alumiinium. Värvitud. RAL7023 (Concrete grey), __Metal Tumehall
Pset_OpeningElementCommon - Reference: -A-02 2000x1200mm; sets with these values: 2
Name (sma_W3:-A-02 2000x1200mm:...)
850463
850958

# IfcWindow: sma_W3:-A-02 2000x1200mm, sma_W3:-A-02 2000x1200mm:850808
In: 0 Kelder
Type - ParameterTakesPrecedence: no; Sizeable: no; Material: EST. Metall. Alumiinium. Värvitud. RAL7023 (Concrete grey), <Unnamed> (2), Glass, __Metal Tumehall
Type - Pset_ProductRequirements - Category: Windows
Type - Pset_QuantityTakeOff - Reference: -A-02 2000x1200mm
Type - Pset_WindowCommon - IsExternal: no; Reference: -A-02 2000x1200mm; FireRating: -; AcousticRating: 35 dB
OverallHeight: 1200 mm; OverallWidth: 2000 mm; Material: Glass, EST. Metall. Alumiinium. Värvitud. RAL7023 (Concrete grey), __Metal Tumehall
Pset_WindowCommon - IsExternal: yes

# IfcWindow: sma_W3:-A-02 2000x1200mm, sma_W3:-A-02 2000x1200mm:1018344
In: 0 Kelder
Type - ParameterTakesPrecedence: no; Sizeable: no; Material: Glass, <Unnamed> (2), __Metal Tumehall, EST. Metall. Alumiinium. Värvitud. RAL7023 (Concrete grey)
Type - Pset_ProductRequirements - Category: Windows
Type - Pset_QuantityTakeOff - Reference: -A-02 2000x1200mm
Type - Pset_WindowCommon - IsExternal: no; Reference: -A-02 2000x1200mm; FireRating: -; AcousticRating: 35 dB
OverallHeight: 1200 mm; OverallWidth: 2000 mm; Material: Glass, EST. Metall. Alumiinium. Värvitud. RAL7023 (Concrete grey), __Metal Tumehall
Pset_OpeningElementCommon - Reference: -A-02 2000x1200mm; sets with these values: 2

# IfcWindow: sma_W3:-A-02 2000x1200mm, sma_W3:-A-02 2000x1200mm:850649
In: 0 Kelder
Type - ParameterTakesPrecedence: no; Sizeable: no; Material: Glass, EST. Metall. Alumiinium. Värvitud. RAL7023 (Concrete grey), <Unnamed> (2), __Metal Tumehall
Type - Pset_ProductRequirements - Category: Windows
Type - Pset_QuantityTakeOff - Reference: -A-02 2000x1200mm
Type - Pset_WindowCommon - IsExternal: no; Reference: -A-02 2000x1200mm; FireRating: -; AcousticRating: 35 dB
OverallHeight: 1200 mm; OverallWidth: 2000 mm; Material: Glass, EST. Metall. Alumiinium. Värvitud. RAL7023 (Concrete grey), __Metal Tumehall
Pset_WindowCommon - IsExternal: yes

# IfcWindow: sma_W3:-A-04 2500x1200mm (4)
In: 0 Kelder
Type - ParameterTakesPrecedence: no; Sizeable: no; Material: <Unnamed> (2), Glass, __Metal Tumehall, EST. Metall. Alumiinium. Värvitud. RAL7023 (Concrete grey)
Type - Pset_ProductRequirements - Category: Windows
Type - Pset_QuantityTakeOff - Reference: -A-04 2500x1200mm
Type - Pset_WindowCommon - IsExternal: no; Reference: -A-04 2500x1200mm; FireRating: -; AcousticRating: 35 dB
OverallHeight: 1200 mm; OverallWidth: 2500 mm; Material: Glass, EST. Metall. Alumiinium. Värvitud. RAL7023 (Concrete grey), __Metal Tumehall
Name (sma_W3:-A-04 2500x1200mm:...)
850306 | Pset_WindowCommon - IsExternal: yes
850612 | Pset_WindowCommon - IsExternal: yes
850698 | Pset_OpeningElementCommon - Reference: -A-04 2500x1200mm; sets with these values: 2
850759 | Pset_OpeningElementCommon - Reference: -A-04 2500x1200mm; sets with these values: 2

# IfcWindow: sma_W3:-A-04 2500x1200mm (2)
In: 0 Kelder
Type - ParameterTakesPrecedence: no; Sizeable: no; Material: __Metal Tumehall, EST. Metall. Alumiinium. Värvitud. RAL7023 (Concrete grey), <Unnamed> (2), Glass
Type - Pset_ProductRequirements - Category: Windows
Type - Pset_QuantityTakeOff - Reference: -A-04 2500x1200mm
Type - Pset_WindowCommon - IsExternal: no; Reference: -A-04 2500x1200mm; FireRating: -; AcousticRating: 35 dB
OverallHeight: 1200 mm; OverallWidth: 2500 mm; Material: Glass, EST. Metall. Alumiinium. Värvitud. RAL7023 (Concrete grey), __Metal Tumehall
Pset_WindowCommon - IsExternal: yes
Name (sma_W3:-A-04 2500x1200mm:...)
850305
850520

# IfcWindow: sma_W3:-A-06 2000x1500mm, sma_W3:-A-06 2000x1500mm:955677
In: 1 Korrus
Type - ParameterTakesPrecedence: no; Sizeable: no; Material: <Unnamed> (2), EST. Metall. Alumiinium. Värvitud. RAL7023 (Concrete grey), __Metal Tumehall, Glass
Type - Pset_ProductRequirements - Category: Windows
Type - Pset_QuantityTakeOff - Reference: -A-06 2000x1500mm
Type - Pset_WindowCommon - IsExternal: no; Reference: -A-06 2000x1500mm; FireRating: -; AcousticRating: 35 dB
OverallHeight: 1400 mm; OverallWidth: 2000 mm; Material: Glass, EST. Metall. Alumiinium. Värvitud. RAL7023 (Concrete grey), __Metal Tumehall
Pset_OpeningElementCommon - Reference: -A-06 2000x1500mm; sets with these values: 2

# IfcWindow: sma_W3:-A-06 2000x1500mm, sma_W3:-A-06 2000x1500mm:949195
In: 1 Korrus
Type - ParameterTakesPrecedence: no; Sizeable: no; Material: EST. Metall. Alumiinium. Värvitud. RAL7023 (Concrete grey), __Metal Tumehall, Glass, <Unnamed> (2)
Type - Pset_ProductRequirements - Category: Windows
Type - Pset_QuantityTakeOff - Reference: -A-06 2000x1500mm
Type - Pset_WindowCommon - IsExternal: no; Reference: -A-06 2000x1500mm; FireRating: -; AcousticRating: 35 dB
OverallHeight: 1400 mm; OverallWidth: 2000 mm; Material: Glass, EST. Metall. Alumiinium. Värvitud. RAL7023 (Concrete grey), __Metal Tumehall
Pset_WindowCommon - IsExternal: yes

# IfcWindow: sma_W3:-A-07 2000x1200mm 2, sma_W3:-A-07 2000x1200mm 2:1776279
In: 0 Kelder
Type - ParameterTakesPrecedence: no; Sizeable: no; Material: <Unnamed> (2), Glass, EST. Metall. Alumiinium. Värvitud. RAL7023 (Concrete grey), __Metal Tumehall
Type - Pset_ProductRequirements - Category: Windows
Type - Pset_QuantityTakeOff - Reference: -A-07 2000x1200mm 2
Type - Pset_WindowCommon - IsExternal: no; Reference: -A-07 2000x1200mm 2; FireRating: -; AcousticRating: 35 dB
OverallHeight: 1200 mm; OverallWidth: 2000 mm; Material: Glass, EST. Metall. Alumiinium. Värvitud. RAL7023 (Concrete grey), __Metal Tumehall
Pset_OpeningElementCommon - Reference: -A-07 2000x1200mm 2; sets with these values: 2
